VERSION 5.7 ;
  NOWIREEXTENSIONATPIN ON ;
  DIVIDERCHAR "/" ;
  BUSBITCHARS "[]" ;
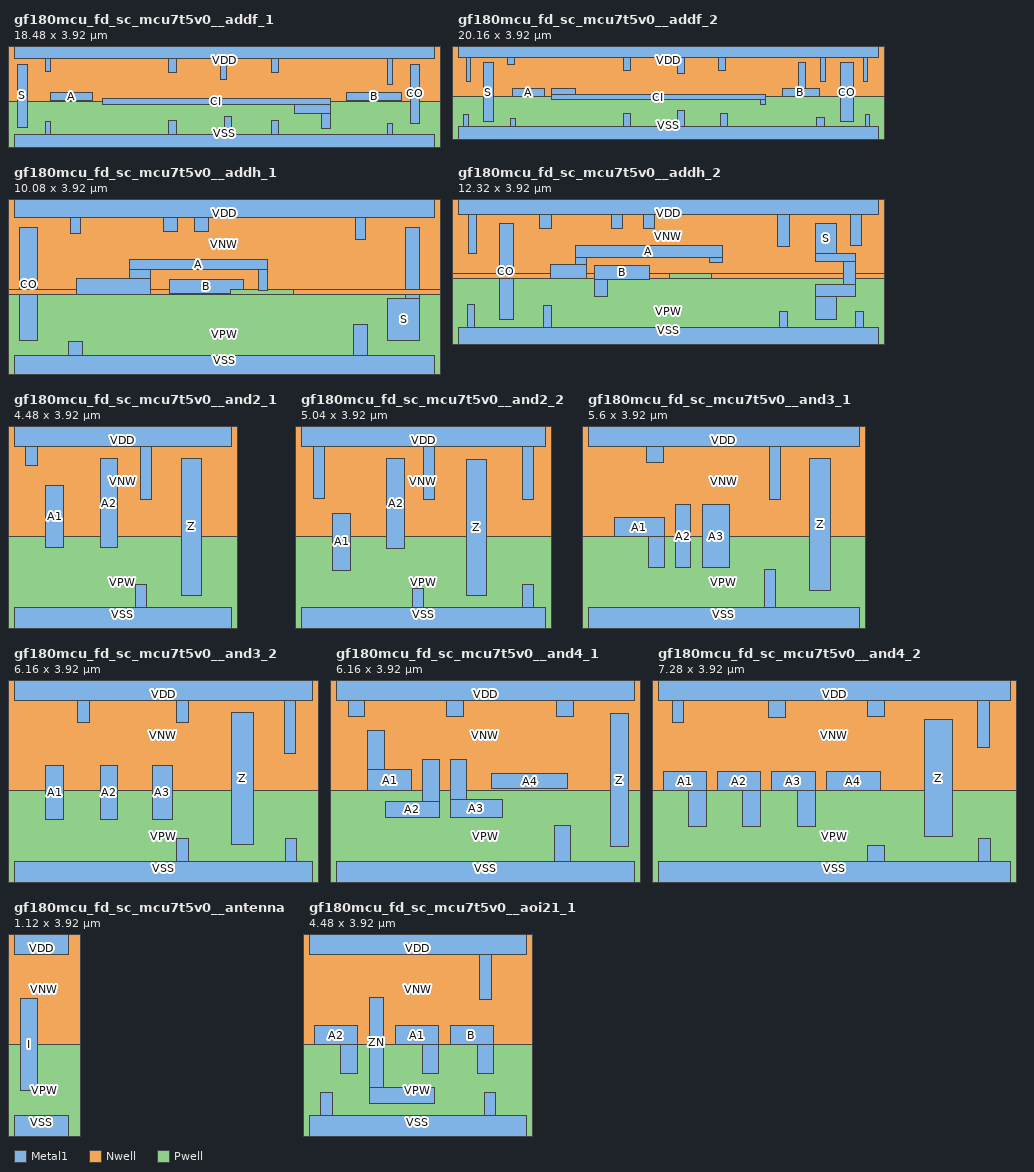
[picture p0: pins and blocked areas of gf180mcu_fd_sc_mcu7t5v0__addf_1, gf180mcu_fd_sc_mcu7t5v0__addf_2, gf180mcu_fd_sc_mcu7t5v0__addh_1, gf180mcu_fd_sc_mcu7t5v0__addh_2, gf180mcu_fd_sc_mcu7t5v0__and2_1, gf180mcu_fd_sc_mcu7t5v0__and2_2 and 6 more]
MACRO gf180mcu_fd_sc_mcu7t5v0__addf_1
  CLASS core ;
  FOREIGN gf180mcu_fd_sc_mcu7t5v0__addf_1 ;
  ORIGIN 0.000 0.000 ;
  SIZE 18.480 BY 3.920 ;
  SYMMETRY X Y ;
  SITE GF018hv5v_mcu_sc7 ;
  PIN A
    DIRECTION INPUT ;
    ANTENNAGATEAREA 2.272000 ;
    PORT
      LAYER Metal1 ;
        RECT 1.615 1.770 3.470 2.150 ;
    END
  END A
  PIN B
    DIRECTION INPUT ;
    ANTENNAGATEAREA 2.272000 ;
    PORT
      LAYER Metal1 ;
        RECT 14.640 1.795 17.070 2.150 ;
    END
  END B
  PIN CI
    DIRECTION INPUT ;
    ANTENNAGATEAREA 1.694000 ;
    PORT
      LAYER Metal1 ;
        RECT 3.890 1.620 13.910 1.850 ;
        RECT 12.340 1.200 13.910 1.620 ;
        RECT 13.540 0.550 13.910 1.200 ;
    END
  END CI
  PIN CO
    DIRECTION OUTPUT ;
    ANTENNADIFFAREA 0.893200 ;
    PORT
      LAYER Metal1 ;
        RECT 17.450 0.790 17.830 3.370 ;
    END
  END CO
  PIN S
    DIRECTION OUTPUT ;
    ANTENNADIFFAREA 0.847000 ;
    PORT
      LAYER Metal1 ;
        RECT 0.140 0.610 0.575 3.370 ;
    END
  END S
  PIN VDD
    DIRECTION INOUT ;
    USE POWER ;
    SHAPE ABUTMENT ;
    PORT
      LAYER Metal1 ;
        RECT 0.000 3.620 18.480 4.220 ;
        RECT 1.365 3.040 1.595 3.620 ;
        RECT 6.790 3.005 7.130 3.620 ;
        RECT 9.105 2.705 9.335 3.620 ;
        RECT 11.310 3.005 11.650 3.620 ;
        RECT 16.445 2.480 16.675 3.620 ;
    END
  END VDD
  PIN VNW
    DIRECTION INOUT ;
    USE POWER ;
    PORT
      LAYER Nwell ;
        RECT -0.430 1.760 18.910 4.350 ;
    END
  END VNW
  PIN VPW
    DIRECTION INOUT ;
    USE GROUND ;
    PORT
      LAYER Pwell ;
        RECT -0.430 -0.430 18.910 1.760 ;
    END
  END VPW
  PIN VSS
    DIRECTION INOUT ;
    USE GROUND ;
    SHAPE ABUTMENT ;
    PORT
      LAYER Metal1 ;
        RECT 1.365 0.300 1.595 0.870 ;
        RECT 6.790 0.300 7.130 0.915 ;
        RECT 9.250 0.300 9.590 1.090 ;
        RECT 11.310 0.300 11.650 0.915 ;
        RECT 16.445 0.300 16.675 0.765 ;
        RECT 0.000 -0.300 18.480 0.300 ;
    END
  END VSS
  OBS
      LAYER Metal1 ;
        RECT 0.925 2.560 4.710 2.790 ;
        RECT 5.550 2.775 5.890 2.845 ;
        RECT 8.030 2.775 8.370 2.845 ;
        RECT 0.925 1.390 1.155 2.560 ;
        RECT 5.550 2.545 8.370 2.775 ;
        RECT 10.070 2.545 13.430 2.775 ;
        RECT 14.165 2.315 14.400 2.765 ;
        RECT 5.010 2.080 14.400 2.315 ;
        RECT 14.170 1.565 14.400 2.080 ;
        RECT 0.925 1.160 4.615 1.390 ;
        RECT 4.385 0.810 4.615 1.160 ;
        RECT 5.505 1.145 8.415 1.375 ;
        RECT 5.505 0.810 5.735 1.145 ;
        RECT 8.185 0.810 8.415 1.145 ;
        RECT 10.025 1.145 12.110 1.375 ;
        RECT 10.025 0.770 10.255 1.145 ;
        RECT 11.880 0.915 12.110 1.145 ;
        RECT 14.170 1.335 17.200 1.565 ;
        RECT 11.880 0.680 13.210 0.915 ;
        RECT 14.170 0.750 14.495 1.335 ;
  END
END gf180mcu_fd_sc_mcu7t5v0__addf_1

#--------EOF---------

MACRO gf180mcu_fd_sc_mcu7t5v0__addf_2
  CLASS core ;
  FOREIGN gf180mcu_fd_sc_mcu7t5v0__addf_2 ;
  ORIGIN 0.000 0.000 ;
  SIZE 20.160 BY 3.920 ;
  SYMMETRY X Y ;
  SITE GF018hv5v_mcu_sc7 ;
  PIN A
    DIRECTION INPUT ;
    ANTENNAGATEAREA 2.372000 ;
    PORT
      LAYER Metal1 ;
        RECT 2.605 1.760 4.130 2.160 ;
    END
  END A
  PIN B
    DIRECTION INPUT ;
    ANTENNAGATEAREA 2.372000 ;
    PORT
      LAYER Metal1 ;
        RECT 16.340 2.160 16.700 3.370 ;
        RECT 15.580 1.760 17.335 2.160 ;
    END
  END B
  PIN CI
    DIRECTION INPUT ;
    ANTENNAGATEAREA 1.754000 ;
    PORT
      LAYER Metal1 ;
        RECT 4.490 1.835 5.660 2.160 ;
        RECT 4.490 1.605 14.755 1.835 ;
        RECT 14.525 1.345 14.755 1.605 ;
    END
  END CI
  PIN CO
    DIRECTION OUTPUT ;
    ANTENNADIFFAREA 1.045200 ;
    PORT
      LAYER Metal1 ;
        RECT 18.370 0.550 18.960 3.370 ;
    END
  END CO
  PIN S
    DIRECTION OUTPUT ;
    ANTENNADIFFAREA 1.006200 ;
    PORT
      LAYER Metal1 ;
        RECT 1.220 0.550 1.680 3.370 ;
    END
  END S
  PIN VDD
    DIRECTION INOUT ;
    USE POWER ;
    SHAPE ABUTMENT ;
    PORT
      LAYER Metal1 ;
        RECT 0.000 3.620 20.160 4.220 ;
        RECT 0.385 2.460 0.615 3.620 ;
        RECT 2.370 3.285 2.710 3.620 ;
        RECT 7.950 3.005 8.290 3.620 ;
        RECT 10.530 2.845 10.870 3.620 ;
        RECT 12.490 3.005 12.830 3.620 ;
        RECT 17.405 2.480 17.635 3.620 ;
        RECT 19.445 2.480 19.675 3.620 ;
    END
  END VDD
  PIN VNW
    DIRECTION INOUT ;
    USE POWER ;
    PORT
      LAYER Nwell ;
        RECT -0.430 1.760 20.590 4.350 ;
    END
  END VNW
  PIN VPW
    DIRECTION INOUT ;
    USE GROUND ;
    PORT
      LAYER Pwell ;
        RECT -0.430 -0.430 20.590 1.760 ;
    END
  END VPW
  PIN VSS
    DIRECTION INOUT ;
    USE GROUND ;
    SHAPE ABUTMENT ;
    PORT
      LAYER Metal1 ;
        RECT 0.285 0.300 0.515 0.905 ;
        RECT 2.525 0.300 2.755 0.695 ;
        RECT 7.950 0.300 8.290 0.915 ;
        RECT 10.530 0.300 10.870 1.075 ;
        RECT 12.590 0.300 12.930 0.915 ;
        RECT 17.230 0.300 17.570 0.730 ;
        RECT 19.545 0.300 19.775 0.905 ;
        RECT 0.000 -0.300 20.160 0.300 ;
    END
  END VSS
  OBS
      LAYER Metal1 ;
        RECT 1.940 2.610 5.830 2.845 ;
        RECT 1.940 1.155 2.170 2.610 ;
        RECT 6.710 2.540 9.790 2.775 ;
        RECT 11.240 2.545 14.310 2.775 ;
        RECT 15.105 2.295 15.335 3.140 ;
        RECT 6.070 2.065 15.335 2.295 ;
        RECT 1.940 0.925 5.775 1.155 ;
        RECT 5.545 0.780 5.775 0.925 ;
        RECT 6.665 1.145 9.695 1.375 ;
        RECT 6.665 0.790 6.895 1.145 ;
        RECT 9.465 0.790 9.695 1.145 ;
        RECT 11.305 1.145 14.215 1.375 ;
        RECT 11.305 0.790 11.535 1.145 ;
        RECT 13.985 0.790 14.215 1.145 ;
        RECT 15.105 1.315 15.335 2.065 ;
        RECT 17.890 1.315 18.120 2.230 ;
        RECT 15.105 1.085 18.120 1.315 ;
        RECT 15.105 0.780 15.335 1.085 ;
  END
END gf180mcu_fd_sc_mcu7t5v0__addf_2

#--------EOF---------

MACRO gf180mcu_fd_sc_mcu7t5v0__addh_1
  CLASS core ;
  FOREIGN gf180mcu_fd_sc_mcu7t5v0__addh_1 ;
  ORIGIN 0.000 0.000 ;
  SIZE 10.080 BY 3.920 ;
  SYMMETRY X Y ;
  SITE GF018hv5v_mcu_sc7 ;
  PIN A
    DIRECTION INPUT ;
    ANTENNAGATEAREA 1.175000 ;
    PORT
      LAYER Metal1 ;
        RECT 2.775 2.365 6.095 2.595 ;
        RECT 2.775 2.150 3.270 2.365 ;
        RECT 1.505 1.770 3.270 2.150 ;
        RECT 5.865 1.870 6.095 2.365 ;
    END
  END A
  PIN B
    DIRECTION INPUT ;
    ANTENNAGATEAREA 1.175000 ;
    PORT
      LAYER Metal1 ;
        RECT 3.725 1.790 5.510 2.135 ;
    END
  END B
  PIN CO
    DIRECTION OUTPUT ;
    ANTENNADIFFAREA 0.895400 ;
    PORT
      LAYER Metal1 ;
        RECT 0.140 0.650 0.575 3.370 ;
    END
  END CO
  PIN S
    DIRECTION OUTPUT ;
    ANTENNADIFFAREA 0.895400 ;
    PORT
      LAYER Metal1 ;
        RECT 9.405 1.680 9.735 3.370 ;
        RECT 8.975 0.650 9.735 1.680 ;
    END
  END S
  PIN VDD
    DIRECTION INOUT ;
    USE POWER ;
    SHAPE ABUTMENT ;
    PORT
      LAYER Metal1 ;
        RECT 0.000 3.620 10.080 4.220 ;
        RECT 1.365 3.230 1.595 3.620 ;
        RECT 3.590 3.285 3.930 3.620 ;
        RECT 4.330 3.285 4.670 3.620 ;
        RECT 8.205 3.075 8.435 3.620 ;
    END
  END VDD
  PIN VNW
    DIRECTION INOUT ;
    USE POWER ;
    PORT
      LAYER Nwell ;
        RECT -0.430 1.885 10.510 4.350 ;
        RECT -0.430 1.760 5.190 1.885 ;
        RECT 6.710 1.760 10.510 1.885 ;
    END
  END VNW
  PIN VPW
    DIRECTION INOUT ;
    USE GROUND ;
    PORT
      LAYER Pwell ;
        RECT 5.190 1.760 6.710 1.885 ;
        RECT -0.430 -0.430 10.510 1.760 ;
    END
  END VPW
  PIN VSS
    DIRECTION INOUT ;
    USE GROUND ;
    SHAPE ABUTMENT ;
    PORT
      LAYER Metal1 ;
        RECT 1.310 0.300 1.650 0.640 ;
        RECT 8.150 0.300 8.490 1.035 ;
        RECT 0.000 -0.300 10.080 0.300 ;
    END
  END VSS
  OBS
      LAYER Metal1 ;
        RECT 2.140 3.100 3.340 3.330 ;
        RECT 2.140 3.000 2.370 3.100 ;
        RECT 0.925 2.770 2.370 3.000 ;
        RECT 3.110 3.055 3.340 3.100 ;
        RECT 3.110 2.825 6.645 3.055 ;
        RECT 7.010 3.010 7.350 3.240 ;
        RECT 0.925 1.100 1.155 2.770 ;
        RECT 6.415 1.970 6.645 2.825 ;
        RECT 7.120 2.610 7.350 3.010 ;
        RECT 7.120 2.375 8.370 2.610 ;
        RECT 8.140 2.250 8.370 2.375 ;
        RECT 6.415 1.740 7.910 1.970 ;
        RECT 8.140 1.910 9.055 2.250 ;
        RECT 8.140 1.495 8.370 1.910 ;
        RECT 5.570 1.265 8.370 1.495 ;
        RECT 0.925 0.870 3.850 1.100 ;
        RECT 3.475 0.810 3.850 0.870 ;
        RECT 4.230 0.760 4.570 1.035 ;
        RECT 5.570 0.990 5.910 1.265 ;
        RECT 6.910 0.760 7.250 1.035 ;
        RECT 4.230 0.530 7.250 0.760 ;
  END
END gf180mcu_fd_sc_mcu7t5v0__addh_1

#--------EOF---------

MACRO gf180mcu_fd_sc_mcu7t5v0__addh_2
  CLASS core ;
  FOREIGN gf180mcu_fd_sc_mcu7t5v0__addh_2 ;
  ORIGIN 0.000 0.000 ;
  SIZE 12.320 BY 3.920 ;
  SYMMETRY X Y ;
  SITE GF018hv5v_mcu_sc7 ;
  PIN A
    DIRECTION INPUT ;
    ANTENNAGATEAREA 2.073000 ;
    PORT
      LAYER Metal1 ;
        RECT 3.435 2.350 7.770 2.710 ;
        RECT 3.435 2.150 3.780 2.350 ;
        RECT 7.380 2.205 7.770 2.350 ;
        RECT 2.715 1.740 3.780 2.150 ;
    END
  END A
  PIN B
    DIRECTION INPUT ;
    ANTENNAGATEAREA 2.073000 ;
    PORT
      LAYER Metal1 ;
        RECT 4.010 1.720 5.620 2.120 ;
        RECT 4.010 1.210 4.390 1.720 ;
    END
  END B
  PIN CO
    DIRECTION OUTPUT ;
    ANTENNADIFFAREA 1.177100 ;
    PORT
      LAYER Metal1 ;
        RECT 1.210 0.550 1.615 3.370 ;
    END
  END CO
  PIN S
    DIRECTION OUTPUT ;
    ANTENNADIFFAREA 0.930800 ;
    PORT
      LAYER Metal1 ;
        RECT 10.490 2.480 11.110 3.370 ;
        RECT 10.490 2.250 11.650 2.480 ;
        RECT 11.310 1.560 11.650 2.250 ;
        RECT 10.490 1.220 11.650 1.560 ;
        RECT 10.490 0.550 11.110 1.220 ;
    END
  END S
  PIN VDD
    DIRECTION INOUT ;
    USE POWER ;
    SHAPE ABUTMENT ;
    PORT
      LAYER Metal1 ;
        RECT 0.000 3.620 12.320 4.220 ;
        RECT 0.315 2.480 0.545 3.620 ;
        RECT 2.400 3.215 2.740 3.620 ;
        RECT 4.490 3.215 4.830 3.620 ;
        RECT 5.430 3.215 5.770 3.620 ;
        RECT 9.370 2.685 9.710 3.620 ;
        RECT 11.510 2.710 11.850 3.620 ;
    END
  END VDD
  PIN VNW
    DIRECTION INOUT ;
    USE POWER ;
    PORT
      LAYER Nwell ;
        RECT -0.430 1.885 12.750 4.350 ;
        RECT -0.430 1.760 6.200 1.885 ;
        RECT 7.425 1.760 12.750 1.885 ;
    END
  END VNW
  PIN VPW
    DIRECTION INOUT ;
    USE GROUND ;
    PORT
      LAYER Pwell ;
        RECT 6.200 1.760 7.425 1.885 ;
        RECT -0.430 -0.430 12.750 1.760 ;
    END
  END VPW
  PIN VSS
    DIRECTION INOUT ;
    USE GROUND ;
    SHAPE ABUTMENT ;
    PORT
      LAYER Metal1 ;
        RECT 0.265 0.300 0.495 0.985 ;
        RECT 2.505 0.300 2.735 0.940 ;
        RECT 9.425 0.300 9.655 0.780 ;
        RECT 11.665 0.300 11.895 0.780 ;
        RECT 0.000 -0.300 12.320 0.300 ;
    END
  END VSS
  OBS
      LAYER Metal1 ;
        RECT 2.975 2.985 3.810 3.170 ;
        RECT 2.015 2.940 3.810 2.985 ;
        RECT 2.015 2.755 3.205 2.940 ;
        RECT 2.015 1.410 2.245 2.755 ;
        RECT 8.010 2.435 8.350 3.370 ;
        RECT 8.010 2.205 9.400 2.435 ;
        RECT 9.170 2.020 9.400 2.205 ;
        RECT 6.095 1.745 8.790 1.975 ;
        RECT 9.170 1.790 10.790 2.020 ;
        RECT 6.095 1.420 6.325 1.745 ;
        RECT 9.170 1.515 9.400 1.790 ;
        RECT 2.015 1.180 3.355 1.410 ;
        RECT 3.125 0.760 3.355 1.180 ;
        RECT 4.665 1.190 6.325 1.420 ;
        RECT 6.670 1.285 9.400 1.515 ;
        RECT 4.665 0.760 4.895 1.190 ;
        RECT 6.670 0.990 7.010 1.285 ;
        RECT 3.125 0.530 4.895 0.760 ;
        RECT 5.330 0.530 8.350 0.760 ;
  END
END gf180mcu_fd_sc_mcu7t5v0__addh_2

#--------EOF---------

MACRO gf180mcu_fd_sc_mcu7t5v0__and2_1
  CLASS core ;
  FOREIGN gf180mcu_fd_sc_mcu7t5v0__and2_1 ;
  ORIGIN 0.000 0.000 ;
  SIZE 4.480 BY 3.920 ;
  SYMMETRY X Y ;
  SITE GF018hv5v_mcu_sc7 ;
  PIN A1
    DIRECTION INPUT ;
    ANTENNAGATEAREA 0.519000 ;
    PORT
      LAYER Metal1 ;
        RECT 0.660 1.540 1.020 2.810 ;
    END
  END A1
  PIN A2
    DIRECTION INPUT ;
    ANTENNAGATEAREA 0.519000 ;
    PORT
      LAYER Metal1 ;
        RECT 1.780 1.540 2.140 3.370 ;
    END
  END A2
  PIN Z
    DIRECTION OUTPUT ;
    ANTENNADIFFAREA 0.893200 ;
    PORT
      LAYER Metal1 ;
        RECT 3.450 0.555 3.870 3.380 ;
    END
  END Z
  PIN VDD
    DIRECTION INOUT ;
    USE POWER ;
    SHAPE ABUTMENT ;
    PORT
      LAYER Metal1 ;
        RECT 0.000 3.620 4.480 4.220 ;
        RECT 0.245 3.225 0.475 3.620 ;
        RECT 2.605 2.530 2.835 3.620 ;
    END
  END VDD
  PIN VNW
    DIRECTION INOUT ;
    USE POWER ;
    PORT
      LAYER Nwell ;
        RECT -0.430 1.760 4.910 4.350 ;
    END
  END VNW
  PIN VPW
    DIRECTION INOUT ;
    USE GROUND ;
    PORT
      LAYER Pwell ;
        RECT -0.430 -0.430 4.910 1.760 ;
    END
  END VPW
  PIN VSS
    DIRECTION INOUT ;
    USE GROUND ;
    SHAPE ABUTMENT ;
    PORT
      LAYER Metal1 ;
        RECT 2.505 0.300 2.735 0.765 ;
        RECT 0.000 -0.300 4.480 0.300 ;
    END
  END VSS
  OBS
      LAYER Metal1 ;
        RECT 1.265 1.290 1.495 3.325 ;
        RECT 2.945 1.290 3.175 1.985 ;
        RECT 0.245 1.055 3.175 1.290 ;
        RECT 0.245 0.805 0.475 1.055 ;
  END
END gf180mcu_fd_sc_mcu7t5v0__and2_1

#--------EOF---------

MACRO gf180mcu_fd_sc_mcu7t5v0__and2_2
  CLASS core ;
  FOREIGN gf180mcu_fd_sc_mcu7t5v0__and2_2 ;
  ORIGIN 0.000 0.000 ;
  SIZE 5.040 BY 3.920 ;
  SYMMETRY X Y ;
  SITE GF018hv5v_mcu_sc7 ;
  PIN A1
    DIRECTION INPUT ;
    ANTENNAGATEAREA 1.024000 ;
    PORT
      LAYER Metal1 ;
        RECT 0.660 1.065 1.020 2.240 ;
    END
  END A1
  PIN A2
    DIRECTION INPUT ;
    ANTENNAGATEAREA 1.024000 ;
    PORT
      LAYER Metal1 ;
        RECT 1.770 1.515 2.130 3.370 ;
    END
  END A2
  PIN Z
    DIRECTION OUTPUT ;
    ANTENNADIFFAREA 1.071900 ;
    PORT
      LAYER Metal1 ;
        RECT 3.420 0.550 3.830 3.355 ;
    END
  END Z
  PIN VDD
    DIRECTION INOUT ;
    USE POWER ;
    SHAPE ABUTMENT ;
    PORT
      LAYER Metal1 ;
        RECT 0.000 3.620 5.040 4.220 ;
        RECT 0.260 2.545 0.490 3.620 ;
        RECT 2.520 2.530 2.750 3.620 ;
        RECT 4.560 2.530 4.790 3.620 ;
    END
  END VDD
  PIN VNW
    DIRECTION INOUT ;
    USE POWER ;
    PORT
      LAYER Nwell ;
        RECT -0.430 1.760 5.470 4.350 ;
    END
  END VNW
  PIN VPW
    DIRECTION INOUT ;
    USE GROUND ;
    PORT
      LAYER Pwell ;
        RECT -0.430 -0.430 5.470 1.760 ;
    END
  END VPW
  PIN VSS
    DIRECTION INOUT ;
    USE GROUND ;
    SHAPE ABUTMENT ;
    PORT
      LAYER Metal1 ;
        RECT 2.300 0.300 2.530 0.690 ;
        RECT 4.560 0.300 4.790 0.765 ;
        RECT 0.000 -0.300 5.040 0.300 ;
    END
  END VSS
  OBS
      LAYER Metal1 ;
        RECT 1.280 1.165 1.510 3.355 ;
        RECT 2.960 1.165 3.190 1.755 ;
        RECT 1.280 0.930 3.190 1.165 ;
        RECT 1.280 0.780 1.510 0.930 ;
        RECT 0.195 0.550 1.510 0.780 ;
  END
END gf180mcu_fd_sc_mcu7t5v0__and2_2

#--------EOF---------

MACRO gf180mcu_fd_sc_mcu7t5v0__and3_1
  CLASS core ;
  FOREIGN gf180mcu_fd_sc_mcu7t5v0__and3_1 ;
  ORIGIN 0.000 0.000 ;
  SIZE 5.600 BY 3.920 ;
  SYMMETRY X Y ;
  SITE GF018hv5v_mcu_sc7 ;
  PIN A1
    DIRECTION INPUT ;
    ANTENNAGATEAREA 0.495500 ;
    PORT
      LAYER Metal1 ;
        RECT 0.540 1.770 1.570 2.150 ;
        RECT 1.250 1.120 1.570 1.770 ;
    END
  END A1
  PIN A2
    DIRECTION INPUT ;
    ANTENNAGATEAREA 0.495500 ;
    PORT
      LAYER Metal1 ;
        RECT 1.800 1.120 2.120 2.415 ;
    END
  END A2
  PIN A3
    DIRECTION INPUT ;
    ANTENNAGATEAREA 0.495500 ;
    PORT
      LAYER Metal1 ;
        RECT 2.360 1.120 2.910 2.415 ;
    END
  END A3
  PIN Z
    DIRECTION OUTPUT ;
    ANTENNADIFFAREA 0.875600 ;
    PORT
      LAYER Metal1 ;
        RECT 4.570 0.650 5.010 3.380 ;
    END
  END Z
  PIN VDD
    DIRECTION INOUT ;
    USE POWER ;
    SHAPE ABUTMENT ;
    PORT
      LAYER Metal1 ;
        RECT 0.000 3.620 5.600 4.220 ;
        RECT 1.210 3.285 1.550 3.620 ;
        RECT 3.745 2.530 3.975 3.620 ;
    END
  END VDD
  PIN VNW
    DIRECTION INOUT ;
    USE POWER ;
    PORT
      LAYER Nwell ;
        RECT -0.430 1.760 6.030 4.350 ;
    END
  END VNW
  PIN VPW
    DIRECTION INOUT ;
    USE GROUND ;
    PORT
      LAYER Pwell ;
        RECT -0.430 -0.430 6.030 1.760 ;
    END
  END VPW
  PIN VSS
    DIRECTION INOUT ;
    USE GROUND ;
    SHAPE ABUTMENT ;
    PORT
      LAYER Metal1 ;
        RECT 3.645 0.300 3.875 1.090 ;
        RECT 0.000 -0.300 5.600 0.300 ;
    END
  END VSS
  OBS
      LAYER Metal1 ;
        RECT 0.190 3.055 0.530 3.340 ;
        RECT 2.230 3.055 2.570 3.340 ;
        RECT 0.190 2.825 3.415 3.055 ;
        RECT 3.185 1.800 3.415 2.825 ;
        RECT 3.185 1.460 4.315 1.800 ;
        RECT 0.190 0.805 0.530 1.035 ;
        RECT 3.185 0.805 3.415 1.460 ;
        RECT 0.190 0.575 3.415 0.805 ;
  END
END gf180mcu_fd_sc_mcu7t5v0__and3_1

#--------EOF---------

MACRO gf180mcu_fd_sc_mcu7t5v0__and3_2
  CLASS core ;
  FOREIGN gf180mcu_fd_sc_mcu7t5v0__and3_2 ;
  ORIGIN 0.000 0.000 ;
  SIZE 6.160 BY 3.920 ;
  SYMMETRY X Y ;
  SITE GF018hv5v_mcu_sc7 ;
  PIN A1
    DIRECTION INPUT ;
    ANTENNAGATEAREA 0.981500 ;
    PORT
      LAYER Metal1 ;
        RECT 0.660 1.160 1.020 2.290 ;
    END
  END A1
  PIN A2
    DIRECTION INPUT ;
    ANTENNAGATEAREA 0.981500 ;
    PORT
      LAYER Metal1 ;
        RECT 1.780 1.160 2.140 2.290 ;
    END
  END A2
  PIN A3
    DIRECTION INPUT ;
    ANTENNAGATEAREA 0.981500 ;
    PORT
      LAYER Metal1 ;
        RECT 2.865 1.160 3.260 2.290 ;
    END
  END A3
  PIN Z
    DIRECTION OUTPUT ;
    ANTENNADIFFAREA 1.055600 ;
    PORT
      LAYER Metal1 ;
        RECT 4.480 0.650 4.950 3.380 ;
    END
  END Z
  PIN VDD
    DIRECTION INOUT ;
    USE POWER ;
    SHAPE ABUTMENT ;
    PORT
      LAYER Metal1 ;
        RECT 0.000 3.620 6.160 4.220 ;
        RECT 1.320 3.160 1.550 3.620 ;
        RECT 3.360 3.160 3.590 3.620 ;
        RECT 5.580 2.530 5.810 3.620 ;
    END
  END VDD
  PIN VNW
    DIRECTION INOUT ;
    USE POWER ;
    PORT
      LAYER Nwell ;
        RECT -0.430 1.760 6.590 4.350 ;
    END
  END VNW
  PIN VPW
    DIRECTION INOUT ;
    USE GROUND ;
    PORT
      LAYER Pwell ;
        RECT -0.430 -0.430 6.590 1.760 ;
    END
  END VPW
  PIN VSS
    DIRECTION INOUT ;
    USE GROUND ;
    SHAPE ABUTMENT ;
    PORT
      LAYER Metal1 ;
        RECT 3.360 0.300 3.590 0.765 ;
        RECT 5.600 0.300 5.830 0.765 ;
        RECT 0.000 -0.300 6.160 0.300 ;
    END
  END VSS
  OBS
      LAYER Metal1 ;
        RECT 0.245 2.910 0.585 3.355 ;
        RECT 0.245 2.655 4.250 2.910 ;
        RECT 1.285 0.865 1.515 2.655 ;
        RECT 4.020 1.445 4.250 2.655 ;
        RECT 0.235 0.635 1.515 0.865 ;
  END
END gf180mcu_fd_sc_mcu7t5v0__and3_2

#--------EOF---------

MACRO gf180mcu_fd_sc_mcu7t5v0__and4_1
  CLASS core ;
  FOREIGN gf180mcu_fd_sc_mcu7t5v0__and4_1 ;
  ORIGIN 0.000 0.000 ;
  SIZE 6.160 BY 3.920 ;
  SYMMETRY X Y ;
  SITE GF018hv5v_mcu_sc7 ;
  PIN A1
    DIRECTION INPUT ;
    ANTENNAGATEAREA 0.552000 ;
    PORT
      LAYER Metal1 ;
        RECT 0.660 2.190 1.000 3.000 ;
        RECT 0.660 1.770 1.560 2.190 ;
    END
  END A1
  PIN A2
    DIRECTION INPUT ;
    ANTENNAGATEAREA 0.552000 ;
    PORT
      LAYER Metal1 ;
        RECT 1.790 1.540 2.130 2.410 ;
        RECT 1.015 1.210 2.130 1.540 ;
    END
  END A2
  PIN A3
    DIRECTION INPUT ;
    ANTENNAGATEAREA 0.552000 ;
    PORT
      LAYER Metal1 ;
        RECT 2.360 1.570 2.700 2.410 ;
        RECT 2.360 1.210 3.430 1.570 ;
    END
  END A3
  PIN A4
    DIRECTION INPUT ;
    ANTENNAGATEAREA 0.552000 ;
    PORT
      LAYER Metal1 ;
        RECT 3.215 1.800 4.780 2.120 ;
    END
  END A4
  PIN Z
    DIRECTION OUTPUT ;
    ANTENNADIFFAREA 0.895400 ;
    PORT
      LAYER Metal1 ;
        RECT 5.660 0.610 6.030 3.350 ;
    END
  END Z
  PIN VDD
    DIRECTION INOUT ;
    USE POWER ;
    SHAPE ABUTMENT ;
    PORT
      LAYER Metal1 ;
        RECT 0.000 3.620 6.160 4.220 ;
        RECT 0.250 3.285 0.590 3.620 ;
        RECT 2.290 3.285 2.630 3.620 ;
        RECT 4.550 3.285 4.890 3.620 ;
    END
  END VDD
  PIN VNW
    DIRECTION INOUT ;
    USE POWER ;
    PORT
      LAYER Nwell ;
        RECT -0.430 1.760 6.590 4.350 ;
    END
  END VNW
  PIN VPW
    DIRECTION INOUT ;
    USE GROUND ;
    PORT
      LAYER Pwell ;
        RECT -0.430 -0.430 6.590 1.760 ;
    END
  END VPW
  PIN VSS
    DIRECTION INOUT ;
    USE GROUND ;
    SHAPE ABUTMENT ;
    PORT
      LAYER Metal1 ;
        RECT 4.505 0.300 4.845 1.035 ;
        RECT 0.000 -0.300 6.160 0.300 ;
    END
  END VSS
  OBS
      LAYER Metal1 ;
        RECT 1.270 3.055 1.610 3.390 ;
        RECT 3.310 3.055 3.650 3.390 ;
        RECT 1.270 2.825 5.385 3.055 ;
        RECT 5.155 1.505 5.385 2.825 ;
        RECT 3.770 1.265 5.385 1.505 ;
        RECT 0.305 0.760 0.535 1.090 ;
        RECT 3.770 0.760 4.000 1.265 ;
        RECT 0.305 0.530 4.000 0.760 ;
  END
END gf180mcu_fd_sc_mcu7t5v0__and4_1

#--------EOF---------

MACRO gf180mcu_fd_sc_mcu7t5v0__and4_2
  CLASS core ;
  FOREIGN gf180mcu_fd_sc_mcu7t5v0__and4_2 ;
  ORIGIN 0.000 0.000 ;
  SIZE 7.280 BY 3.920 ;
  SYMMETRY X Y ;
  SITE GF018hv5v_mcu_sc7 ;
  PIN A1
    DIRECTION INPUT ;
    ANTENNAGATEAREA 0.919500 ;
    PORT
      LAYER Metal1 ;
        RECT 0.120 1.770 1.000 2.150 ;
        RECT 0.630 1.030 1.000 1.770 ;
    END
  END A1
  PIN A2
    DIRECTION INPUT ;
    ANTENNAGATEAREA 0.919500 ;
    PORT
      LAYER Metal1 ;
        RECT 1.230 1.770 2.120 2.150 ;
        RECT 1.750 1.030 2.120 1.770 ;
    END
  END A2
  PIN A3
    DIRECTION INPUT ;
    ANTENNAGATEAREA 0.919500 ;
    PORT
      LAYER Metal1 ;
        RECT 2.350 1.770 3.240 2.150 ;
        RECT 2.870 1.030 3.240 1.770 ;
    END
  END A3
  PIN A4
    DIRECTION INPUT ;
    ANTENNAGATEAREA 0.919500 ;
    PORT
      LAYER Metal1 ;
        RECT 3.470 1.770 4.595 2.150 ;
    END
  END A4
  PIN Z
    DIRECTION OUTPUT ;
    ANTENNADIFFAREA 1.060800 ;
    PORT
      LAYER Metal1 ;
        RECT 5.495 0.805 6.070 3.235 ;
    END
  END Z
  PIN VDD
    DIRECTION INOUT ;
    USE POWER ;
    SHAPE ABUTMENT ;
    PORT
      LAYER Metal1 ;
        RECT 0.000 3.620 7.280 4.220 ;
        RECT 0.300 3.160 0.530 3.620 ;
        RECT 2.285 3.280 2.625 3.620 ;
        RECT 4.325 3.285 4.665 3.620 ;
        RECT 6.600 2.650 6.830 3.620 ;
    END
  END VDD
  PIN VNW
    DIRECTION INOUT ;
    USE POWER ;
    PORT
      LAYER Nwell ;
        RECT -0.430 1.760 7.710 4.350 ;
    END
  END VNW
  PIN VPW
    DIRECTION INOUT ;
    USE GROUND ;
    PORT
      LAYER Pwell ;
        RECT -0.430 -0.430 7.710 1.760 ;
    END
  END VPW
  PIN VSS
    DIRECTION INOUT ;
    USE GROUND ;
    SHAPE ABUTMENT ;
    PORT
      LAYER Metal1 ;
        RECT 4.325 0.300 4.665 0.635 ;
        RECT 6.620 0.300 6.850 0.765 ;
        RECT 0.000 -0.300 7.280 0.300 ;
    END
  END VSS
  OBS
      LAYER Metal1 ;
        RECT 1.260 2.790 5.230 3.020 ;
        RECT 5.000 1.095 5.230 2.790 ;
        RECT 3.845 0.865 5.230 1.095 ;
        RECT 3.845 0.780 4.075 0.865 ;
        RECT 0.235 0.550 4.075 0.780 ;
  END
END gf180mcu_fd_sc_mcu7t5v0__and4_2

#--------EOF---------

MACRO gf180mcu_fd_sc_mcu7t5v0__antenna
  CLASS core ANTENNACELL ;
  FOREIGN gf180mcu_fd_sc_mcu7t5v0__antenna ;
  ORIGIN 0.000 0.000 ;
  SIZE 1.120 BY 3.920 ;
  SYMMETRY X Y ;
  SITE GF018hv5v_mcu_sc7 ;
  PIN I
    DIRECTION INPUT ;
    ANTENNADIFFAREA 0.410400 ;
    PORT
      LAYER Metal1 ;
        RECT 0.140 0.810 0.475 2.710 ;
    END
  END I
  PIN VDD
    DIRECTION INOUT ;
    USE POWER ;
    SHAPE ABUTMENT ;
    PORT
      LAYER Metal1 ;
        RECT 0.000 3.620 1.120 4.220 ;
    END
  END VDD
  PIN VNW
    DIRECTION INOUT ;
    USE POWER ;
    PORT
      LAYER Nwell ;
        RECT -0.430 1.760 1.550 4.350 ;
    END
  END VNW
  PIN VPW
    DIRECTION INOUT ;
    USE GROUND ;
    PORT
      LAYER Pwell ;
        RECT -0.430 -0.430 1.550 1.760 ;
    END
  END VPW
  PIN VSS
    DIRECTION INOUT ;
    USE GROUND ;
    SHAPE ABUTMENT ;
    PORT
      LAYER Metal1 ;
        RECT 0.000 -0.300 1.120 0.300 ;
    END
  END VSS
END gf180mcu_fd_sc_mcu7t5v0__antenna

#--------EOF---------

MACRO gf180mcu_fd_sc_mcu7t5v0__aoi21_1
  CLASS core ;
  FOREIGN gf180mcu_fd_sc_mcu7t5v0__aoi21_1 ;
  ORIGIN 0.000 0.000 ;
  SIZE 4.480 BY 3.920 ;
  SYMMETRY X Y ;
  SITE GF018hv5v_mcu_sc7 ;
  PIN A1
    DIRECTION INPUT ;
    ANTENNAGATEAREA 1.099500 ;
    PORT
      LAYER Metal1 ;
        RECT 1.775 1.770 2.680 2.150 ;
        RECT 2.340 1.160 2.680 1.770 ;
    END
  END A1
  PIN A2
    DIRECTION INPUT ;
    ANTENNAGATEAREA 1.099500 ;
    PORT
      LAYER Metal1 ;
        RECT 0.115 1.770 1.010 2.150 ;
        RECT 0.660 1.160 1.010 1.770 ;
    END
  END A2
  PIN B
    DIRECTION INPUT ;
    ANTENNAGATEAREA 0.913500 ;
    PORT
      LAYER Metal1 ;
        RECT 2.910 1.770 3.815 2.150 ;
        RECT 3.475 1.160 3.815 1.770 ;
    END
  END B
  PIN ZN
    DIRECTION OUTPUT ;
    ANTENNADIFFAREA 1.145600 ;
    PORT
      LAYER Metal1 ;
        RECT 1.240 0.870 1.545 2.725 ;
        RECT 1.240 0.550 2.580 0.870 ;
    END
  END ZN
  PIN VDD
    DIRECTION INOUT ;
    USE POWER ;
    SHAPE ABUTMENT ;
    PORT
      LAYER Metal1 ;
        RECT 0.000 3.620 4.480 4.220 ;
        RECT 3.525 2.690 3.755 3.620 ;
    END
  END VDD
  PIN VNW
    DIRECTION INOUT ;
    USE POWER ;
    PORT
      LAYER Nwell ;
        RECT -0.430 1.760 4.910 4.350 ;
    END
  END VNW
  PIN VPW
    DIRECTION INOUT ;
    USE GROUND ;
    PORT
      LAYER Pwell ;
        RECT -0.430 -0.430 4.910 1.760 ;
    END
  END VPW
  PIN VSS
    DIRECTION INOUT ;
    USE GROUND ;
    SHAPE ABUTMENT ;
    PORT
      LAYER Metal1 ;
        RECT 0.245 0.300 0.475 0.765 ;
        RECT 3.625 0.300 3.855 0.765 ;
        RECT 0.000 -0.300 4.480 0.300 ;
    END
  END VSS
  OBS
      LAYER Metal1 ;
        RECT 0.190 3.160 2.570 3.390 ;
        RECT 0.190 2.495 0.530 3.160 ;
        RECT 2.230 2.495 2.570 3.160 ;
  END
END gf180mcu_fd_sc_mcu7t5v0__aoi21_1

#--------EOF---------

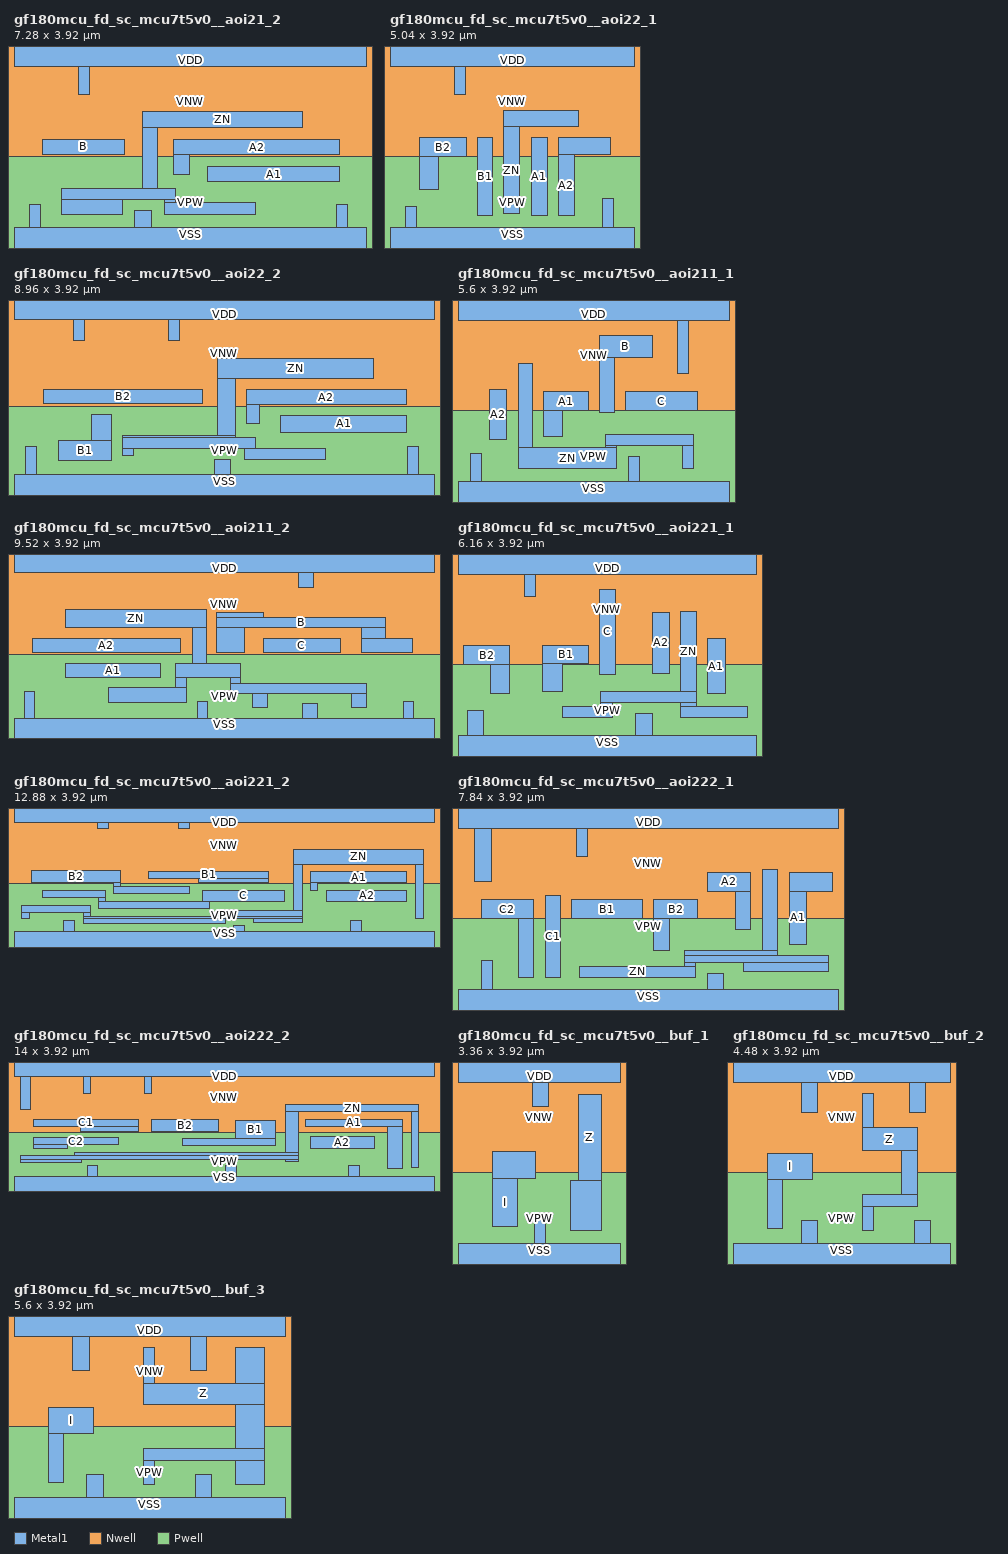
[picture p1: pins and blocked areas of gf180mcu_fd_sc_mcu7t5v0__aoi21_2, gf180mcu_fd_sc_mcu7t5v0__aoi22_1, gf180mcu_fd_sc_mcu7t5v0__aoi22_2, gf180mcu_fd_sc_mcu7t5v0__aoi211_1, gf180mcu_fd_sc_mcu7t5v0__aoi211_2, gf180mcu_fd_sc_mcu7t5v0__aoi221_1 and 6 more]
MACRO gf180mcu_fd_sc_mcu7t5v0__aoi21_2
  CLASS core ;
  FOREIGN gf180mcu_fd_sc_mcu7t5v0__aoi21_2 ;
  ORIGIN 0.000 0.000 ;
  SIZE 7.280 BY 3.920 ;
  SYMMETRY X Y ;
  SITE GF018hv5v_mcu_sc7 ;
  PIN A1
    DIRECTION INPUT ;
    ANTENNAGATEAREA 2.145000 ;
    PORT
      LAYER Metal1 ;
        RECT 4.000 1.240 6.725 1.560 ;
    END
  END A1
  PIN A2
    DIRECTION INPUT ;
    ANTENNAGATEAREA 2.145000 ;
    PORT
      LAYER Metal1 ;
        RECT 3.290 1.800 6.725 2.120 ;
        RECT 3.290 1.400 3.630 1.800 ;
    END
  END A2
  PIN B
    DIRECTION INPUT ;
    ANTENNAGATEAREA 1.893000 ;
    PORT
      LAYER Metal1 ;
        RECT 0.580 1.800 2.280 2.125 ;
    END
  END B
  PIN ZN
    DIRECTION OUTPUT ;
    ANTENNADIFFAREA 2.081900 ;
    PORT
      LAYER Metal1 ;
        RECT 2.650 2.360 5.955 2.700 ;
        RECT 2.650 1.100 2.970 2.360 ;
        RECT 0.970 0.870 3.325 1.100 ;
        RECT 0.970 0.560 2.245 0.870 ;
        RECT 3.095 0.805 3.325 0.870 ;
        RECT 3.095 0.575 4.975 0.805 ;
    END
  END ZN
  PIN VDD
    DIRECTION INOUT ;
    USE POWER ;
    SHAPE ABUTMENT ;
    PORT
      LAYER Metal1 ;
        RECT 0.000 3.620 7.280 4.220 ;
        RECT 1.330 3.040 1.560 3.620 ;
    END
  END VDD
  PIN VNW
    DIRECTION INOUT ;
    USE POWER ;
    PORT
      LAYER Nwell ;
        RECT -0.430 1.760 7.710 4.350 ;
    END
  END VNW
  PIN VPW
    DIRECTION INOUT ;
    USE GROUND ;
    PORT
      LAYER Pwell ;
        RECT -0.430 -0.430 7.710 1.760 ;
    END
  END VPW
  PIN VSS
    DIRECTION INOUT ;
    USE GROUND ;
    SHAPE ABUTMENT ;
    PORT
      LAYER Metal1 ;
        RECT 0.310 0.300 0.540 0.765 ;
        RECT 2.495 0.300 2.835 0.640 ;
        RECT 6.650 0.300 6.880 0.765 ;
        RECT 0.000 -0.300 7.280 0.300 ;
    END
  END VSS
  OBS
      LAYER Metal1 ;
        RECT 0.310 2.760 0.540 3.380 ;
        RECT 1.800 3.095 6.880 3.325 ;
        RECT 1.800 2.760 2.035 3.095 ;
        RECT 0.310 2.530 2.035 2.760 ;
        RECT 6.650 2.435 6.880 3.095 ;
  END
END gf180mcu_fd_sc_mcu7t5v0__aoi21_2

#--------EOF---------

MACRO gf180mcu_fd_sc_mcu7t5v0__aoi22_1
  CLASS core ;
  FOREIGN gf180mcu_fd_sc_mcu7t5v0__aoi22_1 ;
  ORIGIN 0.000 0.000 ;
  SIZE 5.040 BY 3.920 ;
  SYMMETRY X Y ;
  SITE GF018hv5v_mcu_sc7 ;
  PIN A1
    DIRECTION INPUT ;
    ANTENNAGATEAREA 1.096500 ;
    PORT
      LAYER Metal1 ;
        RECT 2.920 0.550 3.240 2.150 ;
    END
  END A1
  PIN A2
    DIRECTION INPUT ;
    ANTENNAGATEAREA 1.096500 ;
    PORT
      LAYER Metal1 ;
        RECT 3.480 1.800 4.545 2.150 ;
        RECT 3.480 0.550 3.800 1.800 ;
    END
  END A2
  PIN B1
    DIRECTION INPUT ;
    ANTENNAGATEAREA 1.096500 ;
    PORT
      LAYER Metal1 ;
        RECT 1.800 0.550 2.120 2.150 ;
    END
  END B1
  PIN B2
    DIRECTION INPUT ;
    ANTENNAGATEAREA 1.096500 ;
    PORT
      LAYER Metal1 ;
        RECT 0.610 1.770 1.570 2.150 ;
        RECT 0.610 1.085 1.005 1.770 ;
    END
  END B2
  PIN ZN
    DIRECTION OUTPUT ;
    ANTENNADIFFAREA 1.055600 ;
    PORT
      LAYER Metal1 ;
        RECT 2.350 2.380 3.890 2.710 ;
        RECT 2.350 0.585 2.680 2.380 ;
    END
  END ZN
  PIN VDD
    DIRECTION INOUT ;
    USE POWER ;
    SHAPE ABUTMENT ;
    PORT
      LAYER Metal1 ;
        RECT 0.000 3.620 5.040 4.220 ;
        RECT 1.330 3.040 1.560 3.620 ;
    END
  END VDD
  PIN VNW
    DIRECTION INOUT ;
    USE POWER ;
    PORT
      LAYER Nwell ;
        RECT -0.430 1.760 5.470 4.350 ;
    END
  END VNW
  PIN VPW
    DIRECTION INOUT ;
    USE GROUND ;
    PORT
      LAYER Pwell ;
        RECT -0.430 -0.430 5.470 1.760 ;
    END
  END VPW
  PIN VSS
    DIRECTION INOUT ;
    USE GROUND ;
    SHAPE ABUTMENT ;
    PORT
      LAYER Metal1 ;
        RECT 0.310 0.300 0.540 0.725 ;
        RECT 4.390 0.300 4.620 0.905 ;
        RECT 0.000 -0.300 5.040 0.300 ;
    END
  END VSS
  OBS
      LAYER Metal1 ;
        RECT 0.255 2.760 0.595 3.380 ;
        RECT 1.820 3.145 4.675 3.380 ;
        RECT 1.820 2.760 2.050 3.145 ;
        RECT 0.255 2.530 2.050 2.760 ;
        RECT 4.335 2.530 4.675 3.145 ;
  END
END gf180mcu_fd_sc_mcu7t5v0__aoi22_1

#--------EOF---------

MACRO gf180mcu_fd_sc_mcu7t5v0__aoi22_2
  CLASS core ;
  FOREIGN gf180mcu_fd_sc_mcu7t5v0__aoi22_2 ;
  ORIGIN 0.000 0.000 ;
  SIZE 8.960 BY 3.920 ;
  SYMMETRY X Y ;
  SITE GF018hv5v_mcu_sc7 ;
  PIN A1
    DIRECTION INPUT ;
    ANTENNAGATEAREA 2.193000 ;
    PORT
      LAYER Metal1 ;
        RECT 5.690 1.210 8.380 1.570 ;
    END
  END A1
  PIN A2
    DIRECTION INPUT ;
    ANTENNAGATEAREA 2.193000 ;
    PORT
      LAYER Metal1 ;
        RECT 4.950 1.800 8.380 2.120 ;
        RECT 4.950 1.400 5.235 1.800 ;
    END
  END A2
  PIN B1
    DIRECTION INPUT ;
    ANTENNAGATEAREA 2.193000 ;
    PORT
      LAYER Metal1 ;
        RECT 1.650 1.030 2.090 1.590 ;
        RECT 0.940 0.610 2.090 1.030 ;
    END
  END B1
  PIN B2
    DIRECTION INPUT ;
    ANTENNAGATEAREA 2.193000 ;
    PORT
      LAYER Metal1 ;
        RECT 0.620 1.820 4.030 2.120 ;
    END
  END B2
  PIN ZN
    DIRECTION OUTPUT ;
    ANTENNADIFFAREA 2.139725 ;
    PORT
      LAYER Metal1 ;
        RECT 4.345 2.360 7.670 2.780 ;
        RECT 4.345 1.150 4.720 2.360 ;
        RECT 2.320 1.100 4.720 1.150 ;
        RECT 2.320 0.870 5.155 1.100 ;
        RECT 2.320 0.715 2.555 0.870 ;
        RECT 4.925 0.640 6.650 0.870 ;
    END
  END ZN
  PIN VDD
    DIRECTION INOUT ;
    USE POWER ;
    SHAPE ABUTMENT ;
    PORT
      LAYER Metal1 ;
        RECT 0.000 3.620 8.960 4.220 ;
        RECT 1.265 3.160 1.495 3.620 ;
        RECT 3.305 3.160 3.535 3.620 ;
    END
  END VDD
  PIN VNW
    DIRECTION INOUT ;
    USE POWER ;
    PORT
      LAYER Nwell ;
        RECT -0.430 1.760 9.390 4.350 ;
    END
  END VNW
  PIN VPW
    DIRECTION INOUT ;
    USE GROUND ;
    PORT
      LAYER Pwell ;
        RECT -0.430 -0.430 9.390 1.760 ;
    END
  END VPW
  PIN VSS
    DIRECTION INOUT ;
    USE GROUND ;
    SHAPE ABUTMENT ;
    PORT
      LAYER Metal1 ;
        RECT 0.245 0.300 0.475 0.905 ;
        RECT 4.270 0.300 4.610 0.640 ;
        RECT 8.405 0.300 8.635 0.905 ;
        RECT 0.000 -0.300 8.960 0.300 ;
    END
  END VSS
  OBS
      LAYER Metal1 ;
        RECT 0.190 2.760 0.530 3.380 ;
        RECT 2.230 2.760 2.570 3.380 ;
        RECT 3.795 3.130 8.690 3.365 ;
        RECT 3.795 2.760 4.025 3.130 ;
        RECT 0.190 2.530 4.025 2.760 ;
        RECT 8.350 2.475 8.690 3.130 ;
  END
END gf180mcu_fd_sc_mcu7t5v0__aoi22_2

#--------EOF---------

MACRO gf180mcu_fd_sc_mcu7t5v0__aoi211_1
  CLASS core ;
  FOREIGN gf180mcu_fd_sc_mcu7t5v0__aoi211_1 ;
  ORIGIN 0.000 0.000 ;
  SIZE 5.600 BY 3.920 ;
  SYMMETRY X Y ;
  SITE GF018hv5v_mcu_sc7 ;
  PIN A1
    DIRECTION INPUT ;
    ANTENNAGATEAREA 1.033500 ;
    PORT
      LAYER Metal1 ;
        RECT 1.770 1.770 2.690 2.150 ;
        RECT 1.770 1.230 2.150 1.770 ;
    END
  END A1
  PIN A2
    DIRECTION INPUT ;
    ANTENNAGATEAREA 1.033500 ;
    PORT
      LAYER Metal1 ;
        RECT 0.650 1.160 1.000 2.190 ;
    END
  END A2
  PIN B
    DIRECTION INPUT ;
    ANTENNAGATEAREA 0.886500 ;
    PORT
      LAYER Metal1 ;
        RECT 2.920 2.850 4.010 3.310 ;
        RECT 2.920 1.730 3.220 2.850 ;
    END
  END B
  PIN C
    DIRECTION INPUT ;
    ANTENNAGATEAREA 0.886500 ;
    PORT
      LAYER Metal1 ;
        RECT 3.450 1.770 4.950 2.150 ;
    END
  END C
  PIN ZN
    DIRECTION OUTPUT ;
    ANTENNADIFFAREA 1.259900 ;
    PORT
      LAYER Metal1 ;
        RECT 1.240 1.000 1.540 2.725 ;
        RECT 3.050 1.045 4.860 1.275 ;
        RECT 3.050 1.000 3.280 1.045 ;
        RECT 1.240 0.560 3.280 1.000 ;
        RECT 4.630 0.565 4.860 1.045 ;
    END
  END ZN
  PIN VDD
    DIRECTION INOUT ;
    USE POWER ;
    SHAPE ABUTMENT ;
    PORT
      LAYER Metal1 ;
        RECT 0.000 3.620 5.600 4.220 ;
        RECT 4.530 2.530 4.760 3.620 ;
    END
  END VDD
  PIN VNW
    DIRECTION INOUT ;
    USE POWER ;
    PORT
      LAYER Nwell ;
        RECT -0.430 1.760 6.030 4.350 ;
    END
  END VNW
  PIN VPW
    DIRECTION INOUT ;
    USE GROUND ;
    PORT
      LAYER Pwell ;
        RECT -0.430 -0.430 6.030 1.760 ;
    END
  END VPW
  PIN VSS
    DIRECTION INOUT ;
    USE GROUND ;
    SHAPE ABUTMENT ;
    PORT
      LAYER Metal1 ;
        RECT 0.250 0.300 0.480 0.870 ;
        RECT 3.510 0.300 3.740 0.815 ;
        RECT 0.000 -0.300 5.600 0.300 ;
    END
  END VSS
  OBS
      LAYER Metal1 ;
        RECT 0.250 3.150 2.520 3.380 ;
        RECT 0.250 2.530 0.480 3.150 ;
        RECT 2.290 2.530 2.520 3.150 ;
  END
END gf180mcu_fd_sc_mcu7t5v0__aoi211_1

#--------EOF---------

MACRO gf180mcu_fd_sc_mcu7t5v0__aoi211_2
  CLASS core ;
  FOREIGN gf180mcu_fd_sc_mcu7t5v0__aoi211_2 ;
  ORIGIN 0.000 0.000 ;
  SIZE 9.520 BY 3.920 ;
  SYMMETRY X Y ;
  SITE GF018hv5v_mcu_sc7 ;
  PIN A1
    DIRECTION INPUT ;
    ANTENNAGATEAREA 2.076000 ;
    PORT
      LAYER Metal1 ;
        RECT 1.160 1.240 3.310 1.560 ;
    END
  END A1
  PIN A2
    DIRECTION INPUT ;
    ANTENNAGATEAREA 2.076000 ;
    PORT
      LAYER Metal1 ;
        RECT 0.420 1.800 3.770 2.120 ;
    END
  END A2
  PIN B
    DIRECTION INPUT ;
    ANTENNAGATEAREA 1.758000 ;
    PORT
      LAYER Metal1 ;
        RECT 4.600 2.595 5.665 2.710 ;
        RECT 4.600 2.360 8.430 2.595 ;
        RECT 4.600 1.800 5.220 2.360 ;
        RECT 7.885 2.120 8.430 2.360 ;
        RECT 7.885 1.800 9.025 2.120 ;
    END
  END B
  PIN C
    DIRECTION INPUT ;
    ANTENNAGATEAREA 1.758000 ;
    PORT
      LAYER Metal1 ;
        RECT 5.650 1.800 7.395 2.120 ;
    END
  END C
  PIN ZN
    DIRECTION OUTPUT ;
    ANTENNADIFFAREA 2.126800 ;
    PORT
      LAYER Metal1 ;
        RECT 1.170 2.360 4.360 2.780 ;
        RECT 4.040 1.560 4.360 2.360 ;
        RECT 3.655 1.240 5.145 1.560 ;
        RECT 3.655 1.000 3.915 1.240 ;
        RECT 2.150 0.680 3.915 1.000 ;
        RECT 4.915 1.100 5.145 1.240 ;
        RECT 4.915 0.870 7.990 1.100 ;
        RECT 5.410 0.560 5.750 0.870 ;
        RECT 7.650 0.560 7.990 0.870 ;
    END
  END ZN
  PIN VDD
    DIRECTION INOUT ;
    USE POWER ;
    SHAPE ABUTMENT ;
    PORT
      LAYER Metal1 ;
        RECT 0.000 3.620 9.520 4.220 ;
        RECT 6.450 3.285 6.790 3.620 ;
    END
  END VDD
  PIN VNW
    DIRECTION INOUT ;
    USE POWER ;
    PORT
      LAYER Nwell ;
        RECT -0.430 1.760 9.950 4.350 ;
    END
  END VNW
  PIN VPW
    DIRECTION INOUT ;
    USE GROUND ;
    PORT
      LAYER Pwell ;
        RECT -0.430 -0.430 9.950 1.760 ;
    END
  END VPW
  PIN VSS
    DIRECTION INOUT ;
    USE GROUND ;
    SHAPE ABUTMENT ;
    PORT
      LAYER Metal1 ;
        RECT 0.245 0.300 0.475 0.910 ;
        RECT 4.165 0.300 4.395 0.690 ;
        RECT 6.530 0.300 6.870 0.640 ;
        RECT 8.825 0.300 9.055 0.695 ;
        RECT 0.000 -0.300 9.520 0.300 ;
    END
  END VSS
  OBS
      LAYER Metal1 ;
        RECT 0.245 3.160 6.140 3.390 ;
        RECT 0.245 2.500 0.475 3.160 ;
        RECT 5.910 3.055 6.140 3.160 ;
        RECT 8.725 3.055 8.955 3.390 ;
        RECT 5.910 2.825 8.955 3.055 ;
        RECT 8.725 2.500 8.955 2.825 ;
  END
END gf180mcu_fd_sc_mcu7t5v0__aoi211_2

#--------EOF---------

MACRO gf180mcu_fd_sc_mcu7t5v0__aoi221_1
  CLASS core ;
  FOREIGN gf180mcu_fd_sc_mcu7t5v0__aoi221_1 ;
  ORIGIN 0.000 0.000 ;
  SIZE 6.160 BY 3.920 ;
  SYMMETRY X Y ;
  SITE GF018hv5v_mcu_sc7 ;
  PIN A1
    DIRECTION INPUT ;
    ANTENNAGATEAREA 1.033500 ;
    PORT
      LAYER Metal1 ;
        RECT 5.150 1.160 5.510 2.300 ;
    END
  END A1
  PIN A2
    DIRECTION INPUT ;
    ANTENNAGATEAREA 1.033500 ;
    PORT
      LAYER Metal1 ;
        RECT 4.005 1.585 4.370 2.835 ;
    END
  END A2
  PIN B1
    DIRECTION INPUT ;
    ANTENNAGATEAREA 1.033500 ;
    PORT
      LAYER Metal1 ;
        RECT 1.750 1.780 2.690 2.150 ;
        RECT 1.750 1.210 2.150 1.780 ;
    END
  END B1
  PIN B2
    DIRECTION INPUT ;
    ANTENNAGATEAREA 1.033500 ;
    PORT
      LAYER Metal1 ;
        RECT 0.120 1.770 1.070 2.150 ;
        RECT 0.680 1.160 1.070 1.770 ;
    END
  END B2
  PIN C
    DIRECTION INPUT ;
    ANTENNAGATEAREA 0.886500 ;
    PORT
      LAYER Metal1 ;
        RECT 2.920 1.550 3.240 3.320 ;
    END
  END C
  PIN ZN
    DIRECTION OUTPUT ;
    ANTENNADIFFAREA 1.489200 ;
    PORT
      LAYER Metal1 ;
        RECT 4.600 1.205 4.920 2.865 ;
        RECT 2.950 0.975 4.920 1.205 ;
        RECT 2.950 0.905 3.180 0.975 ;
        RECT 2.150 0.675 3.180 0.905 ;
        RECT 4.600 0.905 4.920 0.975 ;
        RECT 4.600 0.675 5.980 0.905 ;
    END
  END ZN
  PIN VDD
    DIRECTION INOUT ;
    USE POWER ;
    SHAPE ABUTMENT ;
    PORT
      LAYER Metal1 ;
        RECT 0.000 3.620 6.160 4.220 ;
        RECT 1.365 3.160 1.595 3.620 ;
    END
  END VDD
  PIN VNW
    DIRECTION INOUT ;
    USE POWER ;
    PORT
      LAYER Nwell ;
        RECT -0.430 1.760 6.590 4.350 ;
    END
  END VNW
  PIN VPW
    DIRECTION INOUT ;
    USE GROUND ;
    PORT
      LAYER Pwell ;
        RECT -0.430 -0.430 6.590 1.760 ;
    END
  END VPW
  PIN VSS
    DIRECTION INOUT ;
    USE GROUND ;
    SHAPE ABUTMENT ;
    PORT
      LAYER Metal1 ;
        RECT 0.190 0.300 0.530 0.815 ;
        RECT 3.670 0.300 4.010 0.745 ;
        RECT 0.000 -0.300 6.160 0.300 ;
    END
  END VSS
  OBS
      LAYER Metal1 ;
        RECT 0.280 2.930 0.630 3.380 ;
        RECT 2.330 2.930 2.670 3.380 ;
        RECT 0.280 2.590 2.670 2.930 ;
        RECT 3.545 3.150 5.915 3.380 ;
        RECT 3.545 2.530 3.775 3.150 ;
        RECT 5.685 2.530 5.915 3.150 ;
  END
END gf180mcu_fd_sc_mcu7t5v0__aoi221_1

#--------EOF---------

MACRO gf180mcu_fd_sc_mcu7t5v0__aoi221_2
  CLASS core ;
  FOREIGN gf180mcu_fd_sc_mcu7t5v0__aoi221_2 ;
  ORIGIN 0.000 0.000 ;
  SIZE 12.880 BY 3.920 ;
  SYMMETRY X Y ;
  SITE GF018hv5v_mcu_sc7 ;
  PIN A1
    DIRECTION INPUT ;
    ANTENNAGATEAREA 1.978000 ;
    PORT
      LAYER Metal1 ;
        RECT 9.080 1.790 12.050 2.120 ;
        RECT 9.080 1.550 9.310 1.790 ;
    END
  END A1
  PIN A2
    DIRECTION INPUT ;
    ANTENNAGATEAREA 1.978000 ;
    PORT
      LAYER Metal1 ;
        RECT 9.570 1.225 12.050 1.560 ;
    END
  END A2
  PIN B1
    DIRECTION INPUT ;
    ANTENNAGATEAREA 1.978000 ;
    PORT
      LAYER Metal1 ;
        RECT 4.125 1.910 7.815 2.140 ;
        RECT 5.650 1.800 7.815 1.910 ;
    END
  END B1
  PIN B2
    DIRECTION INPUT ;
    ANTENNAGATEAREA 1.978000 ;
    PORT
      LAYER Metal1 ;
        RECT 0.525 1.785 3.270 2.150 ;
        RECT 3.040 1.680 3.270 1.785 ;
        RECT 3.040 1.450 5.390 1.680 ;
    END
  END B2
  PIN C
    DIRECTION INPUT ;
    ANTENNAGATEAREA 1.708000 ;
    PORT
      LAYER Metal1 ;
        RECT 0.870 1.325 2.810 1.555 ;
        RECT 2.580 1.220 2.810 1.325 ;
        RECT 5.770 1.220 8.310 1.560 ;
        RECT 2.580 1.210 8.310 1.220 ;
        RECT 2.580 0.990 6.000 1.210 ;
    END
  END C
  PIN ZN
    DIRECTION OUTPUT ;
    ANTENNADIFFAREA 2.496525 ;
    PORT
      LAYER Metal1 ;
        RECT 8.565 2.360 12.550 2.795 ;
        RECT 0.245 0.865 2.350 1.095 ;
        RECT 8.565 0.935 8.845 2.360 ;
        RECT 0.245 0.705 0.475 0.865 ;
        RECT 2.120 0.760 2.350 0.865 ;
        RECT 6.265 0.760 8.845 0.935 ;
        RECT 2.120 0.705 8.845 0.760 ;
        RECT 2.120 0.530 6.495 0.705 ;
        RECT 7.350 0.565 8.845 0.705 ;
        RECT 12.320 0.700 12.550 2.360 ;
    END
  END ZN
  PIN VDD
    DIRECTION INOUT ;
    USE POWER ;
    SHAPE ABUTMENT ;
    PORT
      LAYER Metal1 ;
        RECT 0.000 3.620 12.880 4.220 ;
        RECT 2.550 3.445 2.890 3.620 ;
        RECT 5.050 3.445 5.390 3.620 ;
    END
  END VDD
  PIN VNW
    DIRECTION INOUT ;
    USE POWER ;
    PORT
      LAYER Nwell ;
        RECT -0.430 1.760 13.310 4.350 ;
    END
  END VNW
  PIN VPW
    DIRECTION INOUT ;
    USE GROUND ;
    PORT
      LAYER Pwell ;
        RECT -0.430 -0.430 13.310 1.760 ;
    END
  END VPW
  PIN VSS
    DIRECTION INOUT ;
    USE GROUND ;
    SHAPE ABUTMENT ;
    PORT
      LAYER Metal1 ;
        RECT 1.530 0.300 1.870 0.635 ;
        RECT 6.725 0.300 7.065 0.475 ;
        RECT 10.305 0.300 10.645 0.635 ;
        RECT 0.000 -0.300 12.880 0.300 ;
    END
  END VSS
  OBS
      LAYER Metal1 ;
        RECT 0.345 3.215 2.290 3.350 ;
        RECT 5.855 3.215 12.505 3.365 ;
        RECT 0.345 3.135 12.505 3.215 ;
        RECT 0.345 3.120 6.195 3.135 ;
        RECT 0.345 2.460 0.575 3.120 ;
        RECT 2.075 2.985 6.195 3.120 ;
        RECT 1.310 2.525 7.410 2.755 ;
        RECT 8.105 2.460 8.335 3.135 ;
  END
END gf180mcu_fd_sc_mcu7t5v0__aoi221_2

#--------EOF---------

MACRO gf180mcu_fd_sc_mcu7t5v0__aoi222_1
  CLASS core ;
  FOREIGN gf180mcu_fd_sc_mcu7t5v0__aoi222_1 ;
  ORIGIN 0.000 0.000 ;
  SIZE 7.840 BY 3.920 ;
  SYMMETRY X Y ;
  SITE GF018hv5v_mcu_sc7 ;
  PIN A1
    DIRECTION INPUT ;
    ANTENNAGATEAREA 1.072000 ;
    PORT
      LAYER Metal1 ;
        RECT 6.840 2.330 7.720 2.710 ;
        RECT 6.840 1.230 7.180 2.330 ;
    END
  END A1
  PIN A2
    DIRECTION INPUT ;
    ANTENNAGATEAREA 1.072000 ;
    PORT
      LAYER Metal1 ;
        RECT 5.140 2.330 6.040 2.710 ;
        RECT 5.720 1.535 6.040 2.330 ;
    END
  END A2
  PIN B1
    DIRECTION INPUT ;
    ANTENNAGATEAREA 1.072000 ;
    PORT
      LAYER Metal1 ;
        RECT 2.350 1.770 3.800 2.150 ;
    END
  END B1
  PIN B2
    DIRECTION INPUT ;
    ANTENNAGATEAREA 1.072000 ;
    PORT
      LAYER Metal1 ;
        RECT 4.040 1.770 4.950 2.150 ;
        RECT 4.040 1.105 4.360 1.770 ;
    END
  END B2
  PIN C1
    DIRECTION INPUT ;
    ANTENNAGATEAREA 1.072000 ;
    PORT
      LAYER Metal1 ;
        RECT 1.800 0.550 2.120 2.235 ;
    END
  END C1
  PIN C2
    DIRECTION INPUT ;
    ANTENNAGATEAREA 1.072000 ;
    PORT
      LAYER Metal1 ;
        RECT 0.480 1.770 1.560 2.150 ;
        RECT 1.240 0.550 1.560 1.770 ;
    END
  END C2
  PIN ZN
    DIRECTION OUTPUT ;
    ANTENNADIFFAREA 1.756500 ;
    PORT
      LAYER Metal1 ;
        RECT 6.280 1.095 6.600 2.770 ;
        RECT 4.665 1.000 6.600 1.095 ;
        RECT 4.665 0.865 7.635 1.000 ;
        RECT 4.665 0.780 4.895 0.865 ;
        RECT 2.510 0.550 4.895 0.780 ;
        RECT 5.880 0.670 7.635 0.865 ;
    END
  END ZN
  PIN VDD
    DIRECTION INOUT ;
    USE POWER ;
    SHAPE ABUTMENT ;
    PORT
      LAYER Metal1 ;
        RECT 0.000 3.620 7.840 4.220 ;
        RECT 0.345 2.530 0.685 3.620 ;
        RECT 2.440 3.040 2.670 3.620 ;
    END
  END VDD
  PIN VNW
    DIRECTION INOUT ;
    USE POWER ;
    PORT
      LAYER Nwell ;
        RECT -0.430 1.760 8.270 4.350 ;
    END
  END VNW
  PIN VPW
    DIRECTION INOUT ;
    USE GROUND ;
    PORT
      LAYER Pwell ;
        RECT -0.430 -0.430 8.270 1.760 ;
    END
  END VPW
  PIN VSS
    DIRECTION INOUT ;
    USE GROUND ;
    SHAPE ABUTMENT ;
    PORT
      LAYER Metal1 ;
        RECT 0.480 0.300 0.710 0.905 ;
        RECT 5.145 0.300 5.485 0.635 ;
        RECT 0.000 -0.300 7.840 0.300 ;
    END
  END VSS
  OBS
      LAYER Metal1 ;
        RECT 1.365 2.760 1.705 3.380 ;
        RECT 3.095 3.095 7.635 3.325 ;
        RECT 1.365 2.530 4.500 2.760 ;
  END
END gf180mcu_fd_sc_mcu7t5v0__aoi222_1

#--------EOF---------

MACRO gf180mcu_fd_sc_mcu7t5v0__aoi222_2
  CLASS core ;
  FOREIGN gf180mcu_fd_sc_mcu7t5v0__aoi222_2 ;
  ORIGIN 0.000 0.000 ;
  SIZE 14.000 BY 3.920 ;
  SYMMETRY X Y ;
  SITE GF018hv5v_mcu_sc7 ;
  PIN A1
    DIRECTION INPUT ;
    ANTENNAGATEAREA 2.180000 ;
    PORT
      LAYER Metal1 ;
        RECT 9.700 1.960 12.960 2.195 ;
        RECT 12.440 0.550 12.960 1.960 ;
    END
  END A1
  PIN A2
    DIRECTION INPUT ;
    ANTENNAGATEAREA 2.180000 ;
    PORT
      LAYER Metal1 ;
        RECT 9.870 1.210 12.005 1.630 ;
    END
  END A2
  PIN B1
    DIRECTION INPUT ;
    ANTENNAGATEAREA 2.180000 ;
    PORT
      LAYER Metal1 ;
        RECT 7.370 1.555 8.710 2.150 ;
        RECT 5.605 1.325 8.710 1.555 ;
    END
  END B1
  PIN B2
    DIRECTION INPUT ;
    ANTENNAGATEAREA 2.180000 ;
    PORT
      LAYER Metal1 ;
        RECT 4.570 1.785 6.825 2.195 ;
        RECT 4.570 1.770 5.460 1.785 ;
    END
  END B2
  PIN C1
    DIRECTION INPUT ;
    ANTENNAGATEAREA 2.180000 ;
    PORT
      LAYER Metal1 ;
        RECT 0.655 1.965 4.155 2.195 ;
        RECT 2.225 1.800 4.155 1.965 ;
    END
  END C1
  PIN C2
    DIRECTION INPUT ;
    ANTENNAGATEAREA 2.180000 ;
    PORT
      LAYER Metal1 ;
        RECT 0.650 1.570 1.790 1.590 ;
        RECT 0.650 1.340 3.485 1.570 ;
        RECT 0.650 1.210 1.790 1.340 ;
    END
  END C2
  PIN ZN
    DIRECTION OUTPUT ;
    ANTENNADIFFAREA 3.168800 ;
    PORT
      LAYER Metal1 ;
        RECT 9.050 2.440 13.485 2.670 ;
        RECT 9.050 1.095 9.470 2.440 ;
        RECT 2.020 0.970 9.470 1.095 ;
        RECT 0.225 0.865 9.470 0.970 ;
        RECT 0.225 0.740 2.250 0.865 ;
        RECT 4.925 0.845 5.265 0.865 ;
        RECT 9.050 0.790 9.470 0.865 ;
        RECT 13.255 0.570 13.485 2.440 ;
    END
  END ZN
  PIN VDD
    DIRECTION INOUT ;
    USE POWER ;
    SHAPE ABUTMENT ;
    PORT
      LAYER Metal1 ;
        RECT 0.000 3.620 14.000 4.220 ;
        RECT 0.225 2.530 0.565 3.620 ;
        RECT 2.320 3.040 2.550 3.620 ;
        RECT 4.360 3.040 4.590 3.620 ;
    END
  END VDD
  PIN VNW
    DIRECTION INOUT ;
    USE POWER ;
    PORT
      LAYER Nwell ;
        RECT -0.430 1.760 14.430 4.350 ;
    END
  END VNW
  PIN VPW
    DIRECTION INOUT ;
    USE GROUND ;
    PORT
      LAYER Pwell ;
        RECT -0.430 -0.430 14.430 1.760 ;
    END
  END VPW
  PIN VSS
    DIRECTION INOUT ;
    USE GROUND ;
    SHAPE ABUTMENT ;
    PORT
      LAYER Metal1 ;
        RECT 2.455 0.300 2.795 0.635 ;
        RECT 7.065 0.300 7.405 0.635 ;
        RECT 11.160 0.300 11.500 0.635 ;
        RECT 0.000 -0.300 14.000 0.300 ;
    END
  END VSS
  OBS
      LAYER Metal1 ;
        RECT 1.245 2.760 1.585 3.380 ;
        RECT 3.285 2.760 3.625 3.380 ;
        RECT 5.020 3.160 13.550 3.390 ;
        RECT 1.245 2.530 8.425 2.760 ;
  END
END gf180mcu_fd_sc_mcu7t5v0__aoi222_2

#--------EOF---------

MACRO gf180mcu_fd_sc_mcu7t5v0__buf_1
  CLASS core ;
  FOREIGN gf180mcu_fd_sc_mcu7t5v0__buf_1 ;
  ORIGIN 0.000 0.000 ;
  SIZE 3.360 BY 3.920 ;
  SYMMETRY X Y ;
  SITE GF018hv5v_mcu_sc7 ;
  PIN I
    DIRECTION INPUT ;
    ANTENNAGATEAREA 0.498500 ;
    PORT
      LAYER Metal1 ;
        RECT 0.705 1.630 1.590 2.190 ;
        RECT 0.705 0.650 1.220 1.630 ;
    END
  END I
  PIN Z
    DIRECTION OUTPUT ;
    ANTENNADIFFAREA 0.897600 ;
    PORT
      LAYER Metal1 ;
        RECT 2.485 1.600 2.955 3.380 ;
        RECT 2.330 0.575 2.955 1.600 ;
    END
  END Z
  PIN VDD
    DIRECTION INOUT ;
    USE POWER ;
    SHAPE ABUTMENT ;
    PORT
      LAYER Metal1 ;
        RECT 0.000 3.620 3.360 4.220 ;
        RECT 1.530 3.130 1.870 3.620 ;
    END
  END VDD
  PIN VNW
    DIRECTION INOUT ;
    USE POWER ;
    PORT
      LAYER Nwell ;
        RECT -0.430 1.760 3.790 4.350 ;
    END
  END VNW
  PIN VPW
    DIRECTION INOUT ;
    USE GROUND ;
    PORT
      LAYER Pwell ;
        RECT -0.430 -0.430 3.790 1.760 ;
    END
  END VPW
  PIN VSS
    DIRECTION INOUT ;
    USE GROUND ;
    SHAPE ABUTMENT ;
    PORT
      LAYER Metal1 ;
        RECT 1.585 0.300 1.815 0.865 ;
        RECT 0.000 -0.300 3.360 0.300 ;
    END
  END VSS
  OBS
      LAYER Metal1 ;
        RECT 0.245 2.815 0.630 3.390 ;
        RECT 0.245 2.580 2.255 2.815 ;
        RECT 0.245 0.800 0.475 2.580 ;
        RECT 1.970 1.830 2.255 2.580 ;
  END
END gf180mcu_fd_sc_mcu7t5v0__buf_1

#--------EOF---------

MACRO gf180mcu_fd_sc_mcu7t5v0__buf_2
  CLASS core ;
  FOREIGN gf180mcu_fd_sc_mcu7t5v0__buf_2 ;
  ORIGIN 0.000 0.000 ;
  SIZE 4.480 BY 3.920 ;
  SYMMETRY X Y ;
  SITE GF018hv5v_mcu_sc7 ;
  PIN I
    DIRECTION INPUT ;
    ANTENNAGATEAREA 1.102000 ;
    PORT
      LAYER Metal1 ;
        RECT 0.705 1.625 1.650 2.150 ;
        RECT 0.705 0.610 1.015 1.625 ;
    END
  END I
  PIN Z
    DIRECTION OUTPUT ;
    ANTENNADIFFAREA 1.182800 ;
    PORT
      LAYER Metal1 ;
        RECT 2.675 2.700 2.905 3.390 ;
        RECT 2.675 2.210 3.800 2.700 ;
        RECT 3.480 1.300 3.800 2.210 ;
        RECT 2.675 1.065 3.800 1.300 ;
        RECT 2.675 0.570 2.905 1.065 ;
    END
  END Z
  PIN VDD
    DIRECTION INOUT ;
    USE POWER ;
    SHAPE ABUTMENT ;
    PORT
      LAYER Metal1 ;
        RECT 0.000 3.620 4.480 4.220 ;
        RECT 1.405 3.010 1.745 3.620 ;
        RECT 3.640 3.010 3.980 3.620 ;
    END
  END VDD
  PIN VNW
    DIRECTION INOUT ;
    USE POWER ;
    PORT
      LAYER Nwell ;
        RECT -0.430 1.760 4.910 4.350 ;
    END
  END VNW
  PIN VPW
    DIRECTION INOUT ;
    USE GROUND ;
    PORT
      LAYER Pwell ;
        RECT -0.430 -0.430 4.910 1.760 ;
    END
  END VPW
  PIN VSS
    DIRECTION INOUT ;
    USE GROUND ;
    SHAPE ABUTMENT ;
    PORT
      LAYER Metal1 ;
        RECT 1.405 0.300 1.745 0.765 ;
        RECT 3.740 0.300 4.080 0.765 ;
        RECT 0.000 -0.300 4.480 0.300 ;
    END
  END VSS
  OBS
      LAYER Metal1 ;
        RECT 0.245 2.625 0.475 3.390 ;
        RECT 0.245 2.390 2.130 2.625 ;
        RECT 0.245 0.570 0.475 2.390 ;
        RECT 1.900 1.890 2.130 2.390 ;
        RECT 1.900 1.550 3.240 1.890 ;
  END
END gf180mcu_fd_sc_mcu7t5v0__buf_2

#--------EOF---------

MACRO gf180mcu_fd_sc_mcu7t5v0__buf_3
  CLASS core ;
  FOREIGN gf180mcu_fd_sc_mcu7t5v0__buf_3 ;
  ORIGIN 0.000 0.000 ;
  SIZE 5.600 BY 3.920 ;
  SYMMETRY X Y ;
  SITE GF018hv5v_mcu_sc7 ;
  PIN I
    DIRECTION INPUT ;
    ANTENNAGATEAREA 1.102000 ;
    PORT
      LAYER Metal1 ;
        RECT 0.705 1.625 1.650 2.150 ;
        RECT 0.705 0.610 1.015 1.625 ;
    END
  END I
  PIN Z
    DIRECTION OUTPUT ;
    ANTENNADIFFAREA 2.080400 ;
    PORT
      LAYER Metal1 ;
        RECT 2.675 2.660 2.905 3.390 ;
        RECT 4.580 2.660 5.160 3.390 ;
        RECT 2.675 2.210 5.160 2.660 ;
        RECT 4.580 1.300 5.160 2.210 ;
        RECT 2.675 1.065 5.160 1.300 ;
        RECT 2.675 0.570 2.905 1.065 ;
        RECT 4.580 0.570 5.160 1.065 ;
    END
  END Z
  PIN VDD
    DIRECTION INOUT ;
    USE POWER ;
    SHAPE ABUTMENT ;
    PORT
      LAYER Metal1 ;
        RECT 0.000 3.620 5.600 4.220 ;
        RECT 1.210 2.910 1.550 3.620 ;
        RECT 3.640 2.910 3.980 3.620 ;
    END
  END VDD
  PIN VNW
    DIRECTION INOUT ;
    USE POWER ;
    PORT
      LAYER Nwell ;
        RECT -0.430 1.760 6.030 4.350 ;
    END
  END VNW
  PIN VPW
    DIRECTION INOUT ;
    USE GROUND ;
    PORT
      LAYER Pwell ;
        RECT -0.430 -0.430 6.030 1.760 ;
    END
  END VPW
  PIN VSS
    DIRECTION INOUT ;
    USE GROUND ;
    SHAPE ABUTMENT ;
    PORT
      LAYER Metal1 ;
        RECT 1.500 0.300 1.840 0.765 ;
        RECT 3.740 0.300 4.080 0.765 ;
        RECT 0.000 -0.300 5.600 0.300 ;
    END
  END VSS
  OBS
      LAYER Metal1 ;
        RECT 0.245 2.625 0.475 3.390 ;
        RECT 0.245 2.390 2.130 2.625 ;
        RECT 0.245 0.570 0.475 2.390 ;
        RECT 1.900 1.890 2.130 2.390 ;
        RECT 1.900 1.550 4.175 1.890 ;
  END
END gf180mcu_fd_sc_mcu7t5v0__buf_3

#--------EOF---------

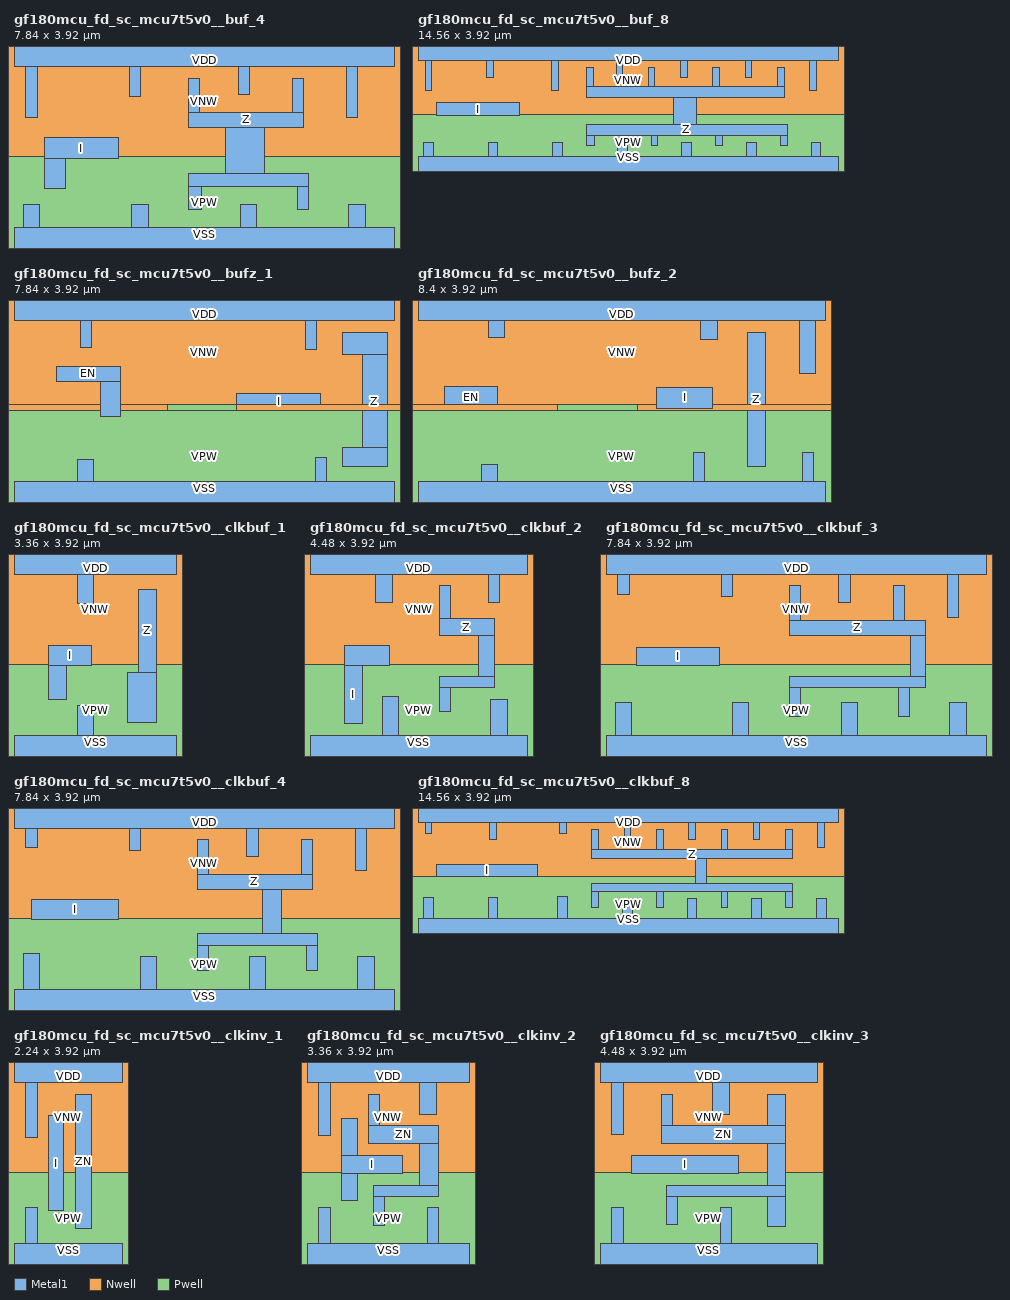
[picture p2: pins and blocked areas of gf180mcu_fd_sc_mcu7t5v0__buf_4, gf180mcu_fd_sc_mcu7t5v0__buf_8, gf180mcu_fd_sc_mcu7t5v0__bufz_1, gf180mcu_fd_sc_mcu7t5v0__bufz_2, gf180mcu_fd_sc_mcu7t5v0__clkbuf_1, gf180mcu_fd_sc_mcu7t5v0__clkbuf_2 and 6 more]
MACRO gf180mcu_fd_sc_mcu7t5v0__buf_4
  CLASS core ;
  FOREIGN gf180mcu_fd_sc_mcu7t5v0__buf_4 ;
  ORIGIN 0.000 0.000 ;
  SIZE 7.840 BY 3.920 ;
  SYMMETRY X Y ;
  SITE GF018hv5v_mcu_sc7 ;
  PIN I
    DIRECTION INPUT ;
    ANTENNAGATEAREA 2.204000 ;
    PORT
      LAYER Metal1 ;
        RECT 0.620 1.715 2.150 2.150 ;
        RECT 0.620 1.100 1.060 1.715 ;
    END
  END I
  PIN Z
    DIRECTION OUTPUT ;
    ANTENNADIFFAREA 2.365600 ;
    PORT
      LAYER Metal1 ;
        RECT 3.605 2.680 3.835 3.380 ;
        RECT 5.745 2.680 5.975 3.380 ;
        RECT 3.605 2.360 5.975 2.680 ;
        RECT 4.360 1.420 5.160 2.360 ;
        RECT 3.605 1.140 6.075 1.420 ;
        RECT 3.605 0.675 3.865 1.140 ;
        RECT 5.845 0.675 6.075 1.140 ;
    END
  END Z
  PIN VDD
    DIRECTION INOUT ;
    USE POWER ;
    SHAPE ABUTMENT ;
    PORT
      LAYER Metal1 ;
        RECT 0.000 3.620 7.840 4.220 ;
        RECT 0.245 2.570 0.475 3.620 ;
        RECT 2.385 3.000 2.615 3.620 ;
        RECT 4.625 3.050 4.855 3.620 ;
        RECT 6.865 2.570 7.095 3.620 ;
    END
  END VDD
  PIN VNW
    DIRECTION INOUT ;
    USE POWER ;
    PORT
      LAYER Nwell ;
        RECT -0.430 1.760 8.270 4.350 ;
    END
  END VNW
  PIN VPW
    DIRECTION INOUT ;
    USE GROUND ;
    PORT
      LAYER Pwell ;
        RECT -0.430 -0.430 8.270 1.760 ;
    END
  END VPW
  PIN VSS
    DIRECTION INOUT ;
    USE GROUND ;
    SHAPE ABUTMENT ;
    PORT
      LAYER Metal1 ;
        RECT 0.190 0.300 0.530 0.765 ;
        RECT 2.430 0.300 2.770 0.765 ;
        RECT 4.670 0.300 5.010 0.765 ;
        RECT 6.910 0.300 7.250 0.765 ;
        RECT 0.000 -0.300 7.840 0.300 ;
    END
  END VSS
  OBS
      LAYER Metal1 ;
        RECT 1.265 2.760 1.495 3.380 ;
        RECT 1.265 2.530 2.905 2.760 ;
        RECT 2.670 2.025 2.905 2.530 ;
        RECT 2.670 1.685 4.095 2.025 ;
        RECT 5.585 1.685 6.810 2.025 ;
        RECT 2.670 1.250 2.905 1.685 ;
        RECT 1.365 1.015 2.905 1.250 ;
        RECT 1.365 0.675 1.595 1.015 ;
  END
END gf180mcu_fd_sc_mcu7t5v0__buf_4

#--------EOF---------

MACRO gf180mcu_fd_sc_mcu7t5v0__buf_8
  CLASS core ;
  FOREIGN gf180mcu_fd_sc_mcu7t5v0__buf_8 ;
  ORIGIN 0.000 0.000 ;
  SIZE 14.560 BY 3.920 ;
  SYMMETRY X Y ;
  SITE GF018hv5v_mcu_sc7 ;
  PIN I
    DIRECTION INPUT ;
    ANTENNAGATEAREA 4.408000 ;
    PORT
      LAYER Metal1 ;
        RECT 0.650 1.715 3.510 2.150 ;
    END
  END I
  PIN Z
    DIRECTION OUTPUT ;
    ANTENNADIFFAREA 4.731200 ;
    PORT
      LAYER Metal1 ;
        RECT 5.845 2.710 6.075 3.380 ;
        RECT 7.985 2.710 8.215 3.380 ;
        RECT 10.225 2.710 10.455 3.380 ;
        RECT 12.465 2.710 12.695 3.380 ;
        RECT 5.845 2.330 12.695 2.710 ;
        RECT 8.840 1.420 9.640 2.330 ;
        RECT 5.845 1.040 12.795 1.420 ;
        RECT 5.845 0.675 6.105 1.040 ;
        RECT 8.085 0.675 8.315 1.040 ;
        RECT 10.325 0.675 10.555 1.040 ;
        RECT 12.565 0.675 12.795 1.040 ;
    END
  END Z
  PIN VDD
    DIRECTION INOUT ;
    USE POWER ;
    SHAPE ABUTMENT ;
    PORT
      LAYER Metal1 ;
        RECT 0.000 3.620 14.560 4.220 ;
        RECT 0.245 2.570 0.475 3.620 ;
        RECT 2.385 3.040 2.615 3.620 ;
        RECT 4.625 2.570 4.855 3.620 ;
        RECT 6.865 3.040 7.095 3.620 ;
        RECT 9.105 3.040 9.335 3.620 ;
        RECT 11.345 3.040 11.575 3.620 ;
        RECT 13.585 2.570 13.815 3.620 ;
    END
  END VDD
  PIN VNW
    DIRECTION INOUT ;
    USE POWER ;
    PORT
      LAYER Nwell ;
        RECT -0.430 1.760 14.990 4.350 ;
    END
  END VNW
  PIN VPW
    DIRECTION INOUT ;
    USE GROUND ;
    PORT
      LAYER Pwell ;
        RECT -0.430 -0.430 14.990 1.760 ;
    END
  END VPW
  PIN VSS
    DIRECTION INOUT ;
    USE GROUND ;
    SHAPE ABUTMENT ;
    PORT
      LAYER Metal1 ;
        RECT 0.190 0.300 0.530 0.765 ;
        RECT 2.430 0.300 2.770 0.765 ;
        RECT 4.670 0.300 5.010 0.765 ;
        RECT 6.910 0.300 7.250 0.765 ;
        RECT 9.150 0.300 9.490 0.765 ;
        RECT 11.390 0.300 11.730 0.765 ;
        RECT 13.630 0.300 13.970 0.765 ;
        RECT 0.000 -0.300 14.560 0.300 ;
    END
  END VSS
  OBS
      LAYER Metal1 ;
        RECT 1.265 2.760 1.495 3.380 ;
        RECT 3.505 2.760 3.735 3.380 ;
        RECT 1.265 2.530 4.315 2.760 ;
        RECT 3.980 2.025 4.315 2.530 ;
        RECT 3.980 1.685 8.270 2.025 ;
        RECT 10.340 1.685 13.540 2.030 ;
        RECT 3.980 1.250 4.315 1.685 ;
        RECT 1.365 1.015 4.315 1.250 ;
        RECT 1.365 0.675 1.595 1.015 ;
        RECT 3.605 0.675 3.835 1.015 ;
  END
END gf180mcu_fd_sc_mcu7t5v0__buf_8

#--------EOF---------

MACRO gf180mcu_fd_sc_mcu7t5v0__bufz_1
  CLASS core ;
  FOREIGN gf180mcu_fd_sc_mcu7t5v0__bufz_1 ;
  ORIGIN 0.000 0.000 ;
  SIZE 7.840 BY 3.920 ;
  SYMMETRY X Y ;
  SITE GF018hv5v_mcu_sc7 ;
  PIN EN
    DIRECTION INPUT ;
    ANTENNAGATEAREA 1.052000 ;
    PORT
      LAYER Metal1 ;
        RECT 0.870 2.360 2.190 2.680 ;
        RECT 1.780 1.650 2.190 2.360 ;
    END
  END EN
  PIN I
    DIRECTION INPUT ;
    ANTENNAGATEAREA 0.526000 ;
    PORT
      LAYER Metal1 ;
        RECT 4.600 1.795 6.330 2.120 ;
    END
  END I
  PIN Z
    DIRECTION OUTPUT ;
    ANTENNADIFFAREA 0.897600 ;
    PORT
      LAYER Metal1 ;
        RECT 6.770 2.920 7.710 3.380 ;
        RECT 7.180 1.000 7.710 2.920 ;
        RECT 6.770 0.600 7.710 1.000 ;
    END
  END Z
  PIN VDD
    DIRECTION INOUT ;
    USE POWER ;
    SHAPE ABUTMENT ;
    PORT
      LAYER Metal1 ;
        RECT 0.000 3.620 7.840 4.220 ;
        RECT 1.365 3.065 1.595 3.620 ;
        RECT 6.005 3.015 6.235 3.620 ;
    END
  END VDD
  PIN VNW
    DIRECTION INOUT ;
    USE POWER ;
    PORT
      LAYER Nwell ;
        RECT -0.430 1.885 8.270 4.350 ;
        RECT -0.430 1.760 3.175 1.885 ;
        RECT 4.595 1.760 8.270 1.885 ;
    END
  END VNW
  PIN VPW
    DIRECTION INOUT ;
    USE GROUND ;
    PORT
      LAYER Pwell ;
        RECT 3.175 1.760 4.595 1.885 ;
        RECT -0.430 -0.430 8.270 1.760 ;
    END
  END VPW
  PIN VSS
    DIRECTION INOUT ;
    USE GROUND ;
    SHAPE ABUTMENT ;
    PORT
      LAYER Metal1 ;
        RECT 1.310 0.300 1.650 0.760 ;
        RECT 6.225 0.300 6.455 0.790 ;
        RECT 0.000 -0.300 7.840 0.300 ;
    END
  END VSS
  OBS
      LAYER Metal1 ;
        RECT 0.190 1.240 0.575 3.370 ;
        RECT 2.290 3.160 5.235 3.390 ;
        RECT 2.630 2.480 3.175 2.740 ;
        RECT 2.630 1.240 2.860 2.480 ;
        RECT 3.650 2.170 3.910 2.930 ;
        RECT 0.190 1.005 2.860 1.240 ;
        RECT 3.090 1.880 3.910 2.170 ;
        RECT 0.190 0.530 0.530 1.005 ;
        RECT 3.090 0.760 3.320 1.880 ;
        RECT 4.140 1.220 4.370 3.160 ;
        RECT 4.920 2.590 5.235 3.160 ;
        RECT 4.920 2.360 6.855 2.590 ;
        RECT 6.625 1.880 6.855 2.360 ;
        RECT 3.760 0.990 4.370 1.220 ;
        RECT 4.885 1.335 6.950 1.565 ;
        RECT 4.885 0.760 5.115 1.335 ;
        RECT 2.340 0.530 5.115 0.760 ;
  END
END gf180mcu_fd_sc_mcu7t5v0__bufz_1

#--------EOF---------

MACRO gf180mcu_fd_sc_mcu7t5v0__bufz_2
  CLASS core ;
  FOREIGN gf180mcu_fd_sc_mcu7t5v0__bufz_2 ;
  ORIGIN 0.000 0.000 ;
  SIZE 8.400 BY 3.920 ;
  SYMMETRY X Y ;
  SITE GF018hv5v_mcu_sc7 ;
  PIN EN
    DIRECTION INPUT ;
    ANTENNAGATEAREA 1.929000 ;
    PORT
      LAYER Metal1 ;
        RECT 0.545 1.780 1.630 2.265 ;
    END
  END EN
  PIN I
    DIRECTION INPUT ;
    ANTENNAGATEAREA 1.079500 ;
    PORT
      LAYER Metal1 ;
        RECT 4.920 1.815 6.085 2.235 ;
    END
  END I
  PIN Z
    DIRECTION OUTPUT ;
    ANTENNADIFFAREA 1.037400 ;
    PORT
      LAYER Metal1 ;
        RECT 6.805 0.600 7.160 3.380 ;
    END
  END Z
  PIN VDD
    DIRECTION INOUT ;
    USE POWER ;
    SHAPE ABUTMENT ;
    PORT
      LAYER Metal1 ;
        RECT 0.000 3.620 8.400 4.220 ;
        RECT 1.450 3.260 1.790 3.620 ;
        RECT 5.830 3.220 6.170 3.620 ;
        RECT 7.870 2.530 8.210 3.620 ;
    END
  END VDD
  PIN VNW
    DIRECTION INOUT ;
    USE POWER ;
    PORT
      LAYER Nwell ;
        RECT -0.430 1.885 8.830 4.350 ;
        RECT -0.430 1.760 2.875 1.885 ;
        RECT 4.530 1.760 8.830 1.885 ;
    END
  END VNW
  PIN VPW
    DIRECTION INOUT ;
    USE GROUND ;
    PORT
      LAYER Pwell ;
        RECT 2.875 1.760 4.530 1.885 ;
        RECT -0.430 -0.430 8.830 1.760 ;
    END
  END VPW
  PIN VSS
    DIRECTION INOUT ;
    USE GROUND ;
    SHAPE ABUTMENT ;
    PORT
      LAYER Metal1 ;
        RECT 1.310 0.300 1.650 0.640 ;
        RECT 5.685 0.300 5.915 0.900 ;
        RECT 7.925 0.300 8.155 0.900 ;
        RECT 0.000 -0.300 8.400 0.300 ;
    END
  END VSS
  OBS
      LAYER Metal1 ;
        RECT 2.700 3.160 5.175 3.390 ;
        RECT 0.420 2.780 2.130 3.010 ;
        RECT 4.460 2.930 5.175 3.160 ;
        RECT 1.900 2.520 2.130 2.780 ;
        RECT 1.900 2.235 3.650 2.520 ;
        RECT 1.900 1.325 2.130 2.235 ;
        RECT 3.890 2.005 4.230 2.930 ;
        RECT 0.190 1.095 2.130 1.325 ;
        RECT 2.485 1.775 4.230 2.005 ;
        RECT 4.460 2.700 6.565 2.930 ;
        RECT 0.190 0.865 0.530 1.095 ;
        RECT 2.485 0.760 2.715 1.775 ;
        RECT 4.460 1.545 4.690 2.700 ;
        RECT 6.335 1.900 6.565 2.700 ;
        RECT 3.770 1.315 4.690 1.545 ;
        RECT 5.125 1.355 6.510 1.585 ;
        RECT 3.770 0.990 4.110 1.315 ;
        RECT 5.125 0.760 5.355 1.355 ;
        RECT 2.485 0.530 5.355 0.760 ;
  END
END gf180mcu_fd_sc_mcu7t5v0__bufz_2

#--------EOF---------

MACRO gf180mcu_fd_sc_mcu7t5v0__clkbuf_1
  CLASS core ;
  FOREIGN gf180mcu_fd_sc_mcu7t5v0__clkbuf_1 ;
  ORIGIN 0.000 0.000 ;
  SIZE 3.360 BY 3.920 ;
  SYMMETRY X Y ;
  SITE GF018hv5v_mcu_sc7 ;
  PIN I
    DIRECTION INPUT ;
    ANTENNAGATEAREA 0.741000 ;
    PORT
      LAYER Metal1 ;
        RECT 0.705 1.740 1.590 2.150 ;
        RECT 0.705 1.035 1.080 1.740 ;
    END
  END I
  PIN Z
    DIRECTION OUTPUT ;
    ANTENNADIFFAREA 0.754600 ;
    PORT
      LAYER Metal1 ;
        RECT 2.565 1.605 2.930 3.320 ;
        RECT 2.340 0.565 2.930 1.605 ;
    END
  END Z
  PIN VDD
    DIRECTION INOUT ;
    USE POWER ;
    SHAPE ABUTMENT ;
    PORT
      LAYER Metal1 ;
        RECT 0.000 3.620 3.360 4.220 ;
        RECT 1.310 3.015 1.650 3.620 ;
    END
  END VDD
  PIN VNW
    DIRECTION INOUT ;
    USE POWER ;
    PORT
      LAYER Nwell ;
        RECT -0.430 1.760 3.790 4.350 ;
    END
  END VNW
  PIN VPW
    DIRECTION INOUT ;
    USE GROUND ;
    PORT
      LAYER Pwell ;
        RECT -0.430 -0.430 3.790 1.760 ;
    END
  END VPW
  PIN VSS
    DIRECTION INOUT ;
    USE GROUND ;
    SHAPE ABUTMENT ;
    PORT
      LAYER Metal1 ;
        RECT 1.310 0.300 1.650 0.925 ;
        RECT 0.000 -0.300 3.360 0.300 ;
    END
  END VSS
  OBS
      LAYER Metal1 ;
        RECT 0.245 2.755 0.575 3.380 ;
        RECT 0.245 2.520 2.270 2.755 ;
        RECT 0.245 0.565 0.475 2.520 ;
        RECT 1.930 1.880 2.270 2.520 ;
  END
END gf180mcu_fd_sc_mcu7t5v0__clkbuf_1

#--------EOF---------

MACRO gf180mcu_fd_sc_mcu7t5v0__clkbuf_2
  CLASS core ;
  FOREIGN gf180mcu_fd_sc_mcu7t5v0__clkbuf_2 ;
  ORIGIN 0.000 0.000 ;
  SIZE 4.480 BY 3.920 ;
  SYMMETRY X Y ;
  SITE GF018hv5v_mcu_sc7 ;
  PIN I
    DIRECTION INPUT ;
    ANTENNAGATEAREA 0.726000 ;
    PORT
      LAYER Metal1 ;
        RECT 0.705 1.740 1.650 2.150 ;
        RECT 0.705 0.550 1.080 1.740 ;
    END
  END I
  PIN Z
    DIRECTION OUTPUT ;
    ANTENNADIFFAREA 1.008600 ;
    PORT
      LAYER Metal1 ;
        RECT 2.665 2.710 2.895 3.390 ;
        RECT 2.665 2.360 3.810 2.710 ;
        RECT 3.470 1.510 3.810 2.360 ;
        RECT 2.665 1.280 3.810 1.510 ;
        RECT 2.665 0.800 2.895 1.280 ;
    END
  END Z
  PIN VDD
    DIRECTION INOUT ;
    USE POWER ;
    SHAPE ABUTMENT ;
    PORT
      LAYER Metal1 ;
        RECT 0.000 3.620 4.480 4.220 ;
        RECT 1.360 3.050 1.700 3.620 ;
        RECT 3.685 3.050 3.915 3.620 ;
    END
  END VDD
  PIN VNW
    DIRECTION INOUT ;
    USE POWER ;
    PORT
      LAYER Nwell ;
        RECT -0.430 1.760 4.910 4.350 ;
    END
  END VNW
  PIN VPW
    DIRECTION INOUT ;
    USE GROUND ;
    PORT
      LAYER Pwell ;
        RECT -0.430 -0.430 4.910 1.760 ;
    END
  END VPW
  PIN VSS
    DIRECTION INOUT ;
    USE GROUND ;
    SHAPE ABUTMENT ;
    PORT
      LAYER Metal1 ;
        RECT 1.490 0.300 1.830 1.095 ;
        RECT 3.730 0.300 4.070 1.050 ;
        RECT 0.000 -0.300 4.480 0.300 ;
    END
  END VSS
  OBS
      LAYER Metal1 ;
        RECT 0.245 2.820 0.475 3.390 ;
        RECT 0.245 2.590 2.215 2.820 ;
        RECT 0.245 0.805 0.475 2.590 ;
        RECT 1.890 2.040 2.215 2.590 ;
        RECT 1.890 1.740 3.210 2.040 ;
  END
END gf180mcu_fd_sc_mcu7t5v0__clkbuf_2

#--------EOF---------

MACRO gf180mcu_fd_sc_mcu7t5v0__clkbuf_3
  CLASS core ;
  FOREIGN gf180mcu_fd_sc_mcu7t5v0__clkbuf_3 ;
  ORIGIN 0.000 0.000 ;
  SIZE 7.840 BY 3.920 ;
  SYMMETRY X Y ;
  SITE GF018hv5v_mcu_sc7 ;
  PIN I
    DIRECTION INPUT ;
    ANTENNAGATEAREA 1.183000 ;
    PORT
      LAYER Metal1 ;
        RECT 0.620 1.740 2.340 2.120 ;
    END
  END I
  PIN Z
    DIRECTION OUTPUT ;
    ANTENNADIFFAREA 1.986000 ;
    PORT
      LAYER Metal1 ;
        RECT 3.785 2.680 4.015 3.390 ;
        RECT 5.925 2.680 6.155 3.390 ;
        RECT 3.785 2.360 6.600 2.680 ;
        RECT 6.280 1.510 6.600 2.360 ;
        RECT 3.785 1.280 6.600 1.510 ;
        RECT 3.785 0.690 4.015 1.280 ;
        RECT 6.025 0.690 6.255 1.280 ;
    END
  END Z
  PIN VDD
    DIRECTION INOUT ;
    USE POWER ;
    SHAPE ABUTMENT ;
    PORT
      LAYER Metal1 ;
        RECT 0.000 3.620 7.840 4.220 ;
        RECT 0.245 3.200 0.475 3.620 ;
        RECT 2.385 3.160 2.615 3.620 ;
        RECT 4.805 3.050 5.035 3.620 ;
        RECT 7.045 2.730 7.275 3.620 ;
    END
  END VDD
  PIN VNW
    DIRECTION INOUT ;
    USE POWER ;
    PORT
      LAYER Nwell ;
        RECT -0.430 1.760 8.270 4.350 ;
    END
  END VNW
  PIN VPW
    DIRECTION INOUT ;
    USE GROUND ;
    PORT
      LAYER Pwell ;
        RECT -0.430 -0.430 8.270 1.760 ;
    END
  END VPW
  PIN VSS
    DIRECTION INOUT ;
    USE GROUND ;
    SHAPE ABUTMENT ;
    PORT
      LAYER Metal1 ;
        RECT 0.190 0.300 0.530 0.985 ;
        RECT 2.610 0.300 2.950 0.985 ;
        RECT 4.850 0.300 5.190 0.985 ;
        RECT 7.090 0.300 7.430 0.985 ;
        RECT 0.000 -0.300 7.840 0.300 ;
    END
  END VSS
  OBS
      LAYER Metal1 ;
        RECT 1.265 2.820 1.495 3.390 ;
        RECT 1.265 2.590 3.185 2.820 ;
        RECT 2.955 2.040 3.185 2.590 ;
        RECT 2.955 1.740 5.945 2.040 ;
        RECT 2.955 1.500 3.185 1.740 ;
        RECT 1.365 1.270 3.185 1.500 ;
        RECT 1.365 0.690 1.595 1.270 ;
  END
END gf180mcu_fd_sc_mcu7t5v0__clkbuf_3

#--------EOF---------

MACRO gf180mcu_fd_sc_mcu7t5v0__clkbuf_4
  CLASS core ;
  FOREIGN gf180mcu_fd_sc_mcu7t5v0__clkbuf_4 ;
  ORIGIN 0.000 0.000 ;
  SIZE 7.840 BY 3.920 ;
  SYMMETRY X Y ;
  SITE GF018hv5v_mcu_sc7 ;
  PIN I
    DIRECTION INPUT ;
    ANTENNAGATEAREA 1.183000 ;
    PORT
      LAYER Metal1 ;
        RECT 0.370 1.740 2.150 2.150 ;
    END
  END I
  PIN Z
    DIRECTION OUTPUT ;
    ANTENNADIFFAREA 1.986000 ;
    PORT
      LAYER Metal1 ;
        RECT 3.785 2.680 4.015 3.390 ;
        RECT 5.925 2.680 6.155 3.390 ;
        RECT 3.785 2.360 6.155 2.680 ;
        RECT 5.130 1.445 5.510 2.360 ;
        RECT 3.785 1.215 6.255 1.445 ;
        RECT 3.785 0.690 4.015 1.215 ;
        RECT 6.025 0.690 6.255 1.215 ;
    END
  END Z
  PIN VDD
    DIRECTION INOUT ;
    USE POWER ;
    SHAPE ABUTMENT ;
    PORT
      LAYER Metal1 ;
        RECT 0.000 3.620 7.840 4.220 ;
        RECT 0.245 3.230 0.475 3.620 ;
        RECT 2.385 3.160 2.615 3.620 ;
        RECT 4.805 3.050 5.035 3.620 ;
        RECT 7.045 2.760 7.275 3.620 ;
    END
  END VDD
  PIN VNW
    DIRECTION INOUT ;
    USE POWER ;
    PORT
      LAYER Nwell ;
        RECT -0.430 1.760 8.270 4.350 ;
    END
  END VNW
  PIN VPW
    DIRECTION INOUT ;
    USE GROUND ;
    PORT
      LAYER Pwell ;
        RECT -0.430 -0.430 8.270 1.760 ;
    END
  END VPW
  PIN VSS
    DIRECTION INOUT ;
    USE GROUND ;
    SHAPE ABUTMENT ;
    PORT
      LAYER Metal1 ;
        RECT 0.190 0.300 0.530 1.040 ;
        RECT 2.610 0.300 2.950 0.985 ;
        RECT 4.850 0.300 5.190 0.985 ;
        RECT 7.090 0.300 7.430 0.985 ;
        RECT 0.000 -0.300 7.840 0.300 ;
    END
  END VSS
  OBS
      LAYER Metal1 ;
        RECT 1.265 2.760 1.495 3.380 ;
        RECT 1.265 2.530 3.175 2.760 ;
        RECT 2.945 2.025 3.175 2.530 ;
        RECT 2.945 1.685 4.830 2.025 ;
        RECT 5.765 1.685 6.935 2.025 ;
        RECT 2.945 1.500 3.175 1.685 ;
        RECT 1.365 1.270 3.175 1.500 ;
        RECT 1.365 0.740 1.595 1.270 ;
  END
END gf180mcu_fd_sc_mcu7t5v0__clkbuf_4

#--------EOF---------

MACRO gf180mcu_fd_sc_mcu7t5v0__clkbuf_8
  CLASS core ;
  FOREIGN gf180mcu_fd_sc_mcu7t5v0__clkbuf_8 ;
  ORIGIN 0.000 0.000 ;
  SIZE 14.560 BY 3.920 ;
  SYMMETRY X Y ;
  SITE GF018hv5v_mcu_sc7 ;
  PIN I
    DIRECTION INPUT ;
    ANTENNAGATEAREA 2.369000 ;
    PORT
      LAYER Metal1 ;
        RECT 0.650 1.745 4.130 2.150 ;
    END
  END I
  PIN Z
    DIRECTION OUTPUT ;
    ANTENNADIFFAREA 4.408000 ;
    PORT
      LAYER Metal1 ;
        RECT 6.025 2.680 6.255 3.390 ;
        RECT 8.265 2.680 8.495 3.390 ;
        RECT 10.505 2.680 10.735 3.390 ;
        RECT 12.745 2.680 12.975 3.390 ;
        RECT 6.025 2.360 12.975 2.680 ;
        RECT 9.610 1.510 9.990 2.360 ;
        RECT 6.025 1.220 12.975 1.510 ;
        RECT 6.025 0.690 6.255 1.220 ;
        RECT 8.265 0.690 8.495 1.220 ;
        RECT 10.505 0.690 10.735 1.220 ;
        RECT 12.745 0.690 12.975 1.220 ;
    END
  END Z
  PIN VDD
    DIRECTION INOUT ;
    USE POWER ;
    SHAPE ABUTMENT ;
    PORT
      LAYER Metal1 ;
        RECT 0.000 3.620 14.560 4.220 ;
        RECT 0.245 3.230 0.475 3.620 ;
        RECT 2.485 3.050 2.715 3.620 ;
        RECT 4.905 3.230 5.135 3.620 ;
        RECT 7.145 3.050 7.375 3.620 ;
        RECT 9.385 3.050 9.615 3.620 ;
        RECT 11.625 3.050 11.855 3.620 ;
        RECT 13.865 2.760 14.095 3.620 ;
    END
  END VDD
  PIN VNW
    DIRECTION INOUT ;
    USE POWER ;
    PORT
      LAYER Nwell ;
        RECT -0.430 1.760 14.990 4.350 ;
    END
  END VNW
  PIN VPW
    DIRECTION INOUT ;
    USE GROUND ;
    PORT
      LAYER Pwell ;
        RECT -0.430 -0.430 14.990 1.760 ;
    END
  END VPW
  PIN VSS
    DIRECTION INOUT ;
    USE GROUND ;
    SHAPE ABUTMENT ;
    PORT
      LAYER Metal1 ;
        RECT 0.190 0.300 0.530 1.040 ;
        RECT 2.430 0.300 2.770 1.040 ;
        RECT 4.850 0.300 5.190 1.055 ;
        RECT 7.090 0.300 7.430 0.985 ;
        RECT 9.330 0.300 9.670 0.985 ;
        RECT 11.570 0.300 11.910 0.985 ;
        RECT 13.810 0.300 14.150 0.985 ;
        RECT 0.000 -0.300 14.560 0.300 ;
    END
  END VSS
  OBS
      LAYER Metal1 ;
        RECT 1.365 2.760 1.595 3.390 ;
        RECT 3.605 2.760 3.835 3.390 ;
        RECT 1.365 2.530 4.655 2.760 ;
        RECT 4.425 1.975 4.655 2.530 ;
        RECT 4.425 1.740 8.920 1.975 ;
        RECT 10.530 1.740 13.720 2.040 ;
        RECT 4.425 1.500 4.655 1.740 ;
        RECT 1.365 1.270 4.655 1.500 ;
        RECT 1.365 0.740 1.595 1.270 ;
        RECT 3.605 0.740 3.835 1.270 ;
  END
END gf180mcu_fd_sc_mcu7t5v0__clkbuf_8

#--------EOF---------

MACRO gf180mcu_fd_sc_mcu7t5v0__clkinv_1
  CLASS core ;
  FOREIGN gf180mcu_fd_sc_mcu7t5v0__clkinv_1 ;
  ORIGIN 0.000 0.000 ;
  SIZE 2.240 BY 3.920 ;
  SYMMETRY X Y ;
  SITE GF018hv5v_mcu_sc7 ;
  PIN I
    DIRECTION INPUT ;
    ANTENNAGATEAREA 0.898000 ;
    PORT
      LAYER Metal1 ;
        RECT 0.705 0.970 1.030 2.950 ;
    END
  END I
  PIN ZN
    DIRECTION OUTPUT ;
    ANTENNADIFFAREA 0.748000 ;
    PORT
      LAYER Metal1 ;
        RECT 1.260 0.600 1.595 3.370 ;
    END
  END ZN
  PIN VDD
    DIRECTION INOUT ;
    USE POWER ;
    SHAPE ABUTMENT ;
    PORT
      LAYER Metal1 ;
        RECT 0.000 3.620 2.240 4.220 ;
        RECT 0.245 2.480 0.475 3.620 ;
    END
  END VDD
  PIN VNW
    DIRECTION INOUT ;
    USE POWER ;
    PORT
      LAYER Nwell ;
        RECT -0.430 1.760 2.670 4.350 ;
    END
  END VNW
  PIN VPW
    DIRECTION INOUT ;
    USE GROUND ;
    PORT
      LAYER Pwell ;
        RECT -0.430 -0.430 2.670 1.760 ;
    END
  END VPW
  PIN VSS
    DIRECTION INOUT ;
    USE GROUND ;
    SHAPE ABUTMENT ;
    PORT
      LAYER Metal1 ;
        RECT 0.245 0.300 0.475 1.040 ;
        RECT 0.000 -0.300 2.240 0.300 ;
    END
  END VSS
END gf180mcu_fd_sc_mcu7t5v0__clkinv_1

#--------EOF---------

MACRO gf180mcu_fd_sc_mcu7t5v0__clkinv_2
  CLASS core ;
  FOREIGN gf180mcu_fd_sc_mcu7t5v0__clkinv_2 ;
  ORIGIN 0.000 0.000 ;
  SIZE 3.360 BY 3.920 ;
  SYMMETRY X Y ;
  SITE GF018hv5v_mcu_sc7 ;
  PIN I
    DIRECTION INPUT ;
    ANTENNAGATEAREA 1.796000 ;
    PORT
      LAYER Metal1 ;
        RECT 0.705 2.120 1.035 2.875 ;
        RECT 0.705 1.735 1.970 2.120 ;
        RECT 0.705 1.190 1.035 1.735 ;
    END
  END I
  PIN ZN
    DIRECTION OUTPUT ;
    ANTENNADIFFAREA 1.006000 ;
    PORT
      LAYER Metal1 ;
        RECT 1.265 2.735 1.495 3.380 ;
        RECT 1.265 2.360 2.710 2.735 ;
        RECT 2.330 1.505 2.710 2.360 ;
        RECT 1.365 1.270 2.710 1.505 ;
        RECT 1.365 0.680 1.595 1.270 ;
    END
  END ZN
  PIN VDD
    DIRECTION INOUT ;
    USE POWER ;
    SHAPE ABUTMENT ;
    PORT
      LAYER Metal1 ;
        RECT 0.000 3.620 3.360 4.220 ;
        RECT 0.245 2.530 0.475 3.620 ;
        RECT 2.330 2.965 2.670 3.620 ;
    END
  END VDD
  PIN VNW
    DIRECTION INOUT ;
    USE POWER ;
    PORT
      LAYER Nwell ;
        RECT -0.430 1.760 3.790 4.350 ;
    END
  END VNW
  PIN VPW
    DIRECTION INOUT ;
    USE GROUND ;
    PORT
      LAYER Pwell ;
        RECT -0.430 -0.430 3.790 1.760 ;
    END
  END VPW
  PIN VSS
    DIRECTION INOUT ;
    USE GROUND ;
    SHAPE ABUTMENT ;
    PORT
      LAYER Metal1 ;
        RECT 0.245 0.300 0.475 1.040 ;
        RECT 2.485 0.300 2.715 1.040 ;
        RECT 0.000 -0.300 3.360 0.300 ;
    END
  END VSS
END gf180mcu_fd_sc_mcu7t5v0__clkinv_2

#--------EOF---------

MACRO gf180mcu_fd_sc_mcu7t5v0__clkinv_3
  CLASS core ;
  FOREIGN gf180mcu_fd_sc_mcu7t5v0__clkinv_3 ;
  ORIGIN 0.000 0.000 ;
  SIZE 4.480 BY 3.920 ;
  SYMMETRY X Y ;
  SITE GF018hv5v_mcu_sc7 ;
  PIN I
    DIRECTION INPUT ;
    ANTENNAGATEAREA 2.694000 ;
    PORT
      LAYER Metal1 ;
        RECT 0.650 1.740 2.855 2.120 ;
    END
  END I
  PIN ZN
    DIRECTION OUTPUT ;
    ANTENNADIFFAREA 1.754000 ;
    PORT
      LAYER Metal1 ;
        RECT 1.265 2.735 1.495 3.380 ;
        RECT 3.450 2.735 3.835 3.380 ;
        RECT 1.265 2.360 3.835 2.735 ;
        RECT 3.460 1.505 3.835 2.360 ;
        RECT 1.365 1.270 3.835 1.505 ;
        RECT 1.365 0.700 1.595 1.270 ;
        RECT 3.450 0.650 3.835 1.270 ;
    END
  END ZN
  PIN VDD
    DIRECTION INOUT ;
    USE POWER ;
    SHAPE ABUTMENT ;
    PORT
      LAYER Metal1 ;
        RECT 0.000 3.620 4.480 4.220 ;
        RECT 0.245 2.550 0.475 3.620 ;
        RECT 2.330 2.965 2.670 3.620 ;
    END
  END VDD
  PIN VNW
    DIRECTION INOUT ;
    USE POWER ;
    PORT
      LAYER Nwell ;
        RECT -0.430 1.760 4.910 4.350 ;
    END
  END VNW
  PIN VPW
    DIRECTION INOUT ;
    USE GROUND ;
    PORT
      LAYER Pwell ;
        RECT -0.430 -0.430 4.910 1.760 ;
    END
  END VPW
  PIN VSS
    DIRECTION INOUT ;
    USE GROUND ;
    SHAPE ABUTMENT ;
    PORT
      LAYER Metal1 ;
        RECT 0.245 0.300 0.475 1.040 ;
        RECT 2.485 0.300 2.715 1.040 ;
        RECT 0.000 -0.300 4.480 0.300 ;
    END
  END VSS
END gf180mcu_fd_sc_mcu7t5v0__clkinv_3

#--------EOF---------

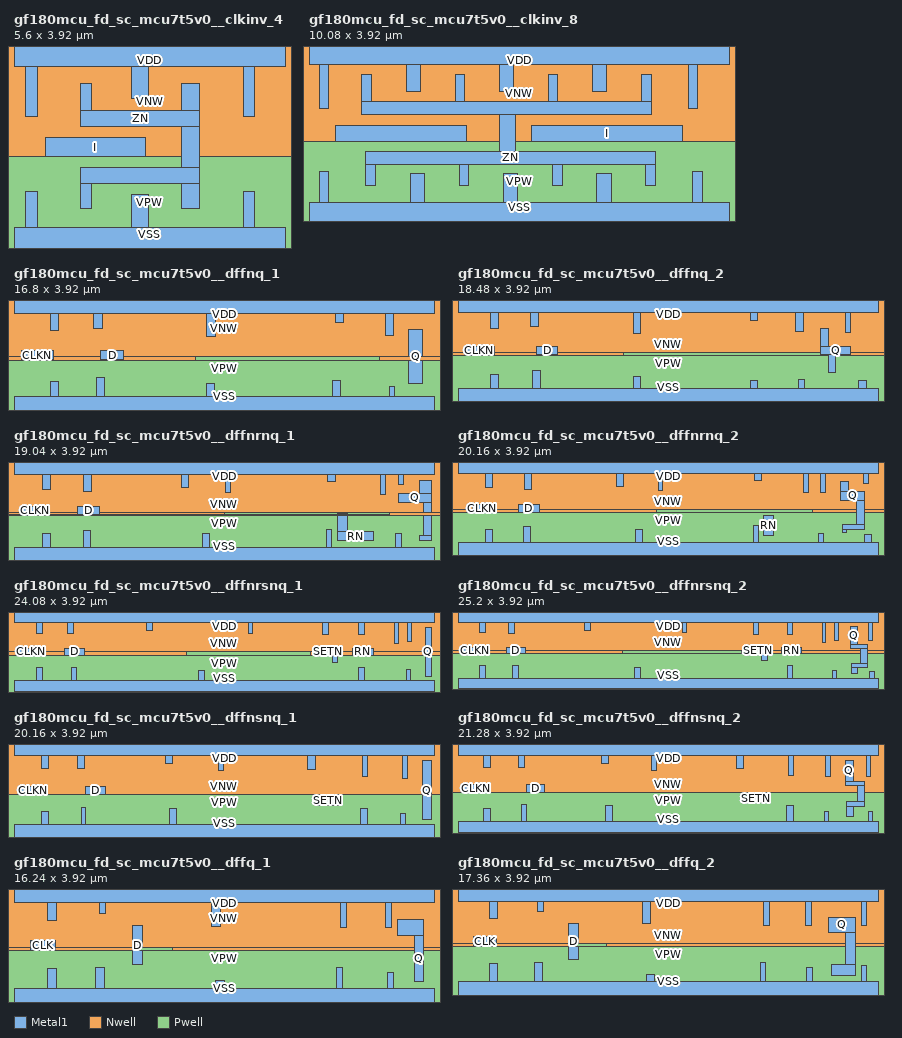
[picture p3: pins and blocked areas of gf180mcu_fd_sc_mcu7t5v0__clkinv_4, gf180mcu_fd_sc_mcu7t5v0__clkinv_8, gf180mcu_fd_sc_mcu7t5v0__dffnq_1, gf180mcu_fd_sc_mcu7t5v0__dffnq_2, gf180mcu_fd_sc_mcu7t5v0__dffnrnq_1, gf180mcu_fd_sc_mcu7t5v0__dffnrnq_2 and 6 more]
MACRO gf180mcu_fd_sc_mcu7t5v0__clkinv_4
  CLASS core ;
  FOREIGN gf180mcu_fd_sc_mcu7t5v0__clkinv_4 ;
  ORIGIN 0.000 0.000 ;
  SIZE 5.600 BY 3.920 ;
  SYMMETRY X Y ;
  SITE GF018hv5v_mcu_sc7 ;
  PIN I
    DIRECTION INPUT ;
    ANTENNAGATEAREA 3.592000 ;
    PORT
      LAYER Metal1 ;
        RECT 0.650 1.765 2.710 2.150 ;
    END
  END I
  PIN ZN
    DIRECTION OUTPUT ;
    ANTENNADIFFAREA 2.256000 ;
    PORT
      LAYER Metal1 ;
        RECT 1.365 2.705 1.595 3.270 ;
        RECT 3.450 2.705 3.835 3.270 ;
        RECT 1.365 2.385 3.835 2.705 ;
        RECT 3.450 1.535 3.835 2.385 ;
        RECT 1.365 1.215 3.835 1.535 ;
        RECT 1.365 0.700 1.595 1.215 ;
        RECT 3.450 0.700 3.835 1.215 ;
    END
  END ZN
  PIN VDD
    DIRECTION INOUT ;
    USE POWER ;
    SHAPE ABUTMENT ;
    PORT
      LAYER Metal1 ;
        RECT 0.000 3.620 5.600 4.220 ;
        RECT 0.245 2.590 0.475 3.620 ;
        RECT 2.430 2.965 2.770 3.620 ;
        RECT 4.725 2.590 4.955 3.620 ;
    END
  END VDD
  PIN VNW
    DIRECTION INOUT ;
    USE POWER ;
    PORT
      LAYER Nwell ;
        RECT -0.430 1.760 6.030 4.350 ;
    END
  END VNW
  PIN VPW
    DIRECTION INOUT ;
    USE GROUND ;
    PORT
      LAYER Pwell ;
        RECT -0.430 -0.430 6.030 1.760 ;
    END
  END VPW
  PIN VSS
    DIRECTION INOUT ;
    USE GROUND ;
    SHAPE ABUTMENT ;
    PORT
      LAYER Metal1 ;
        RECT 0.245 0.300 0.475 1.040 ;
        RECT 2.430 0.300 2.770 0.985 ;
        RECT 4.725 0.300 4.955 1.040 ;
        RECT 0.000 -0.300 5.600 0.300 ;
    END
  END VSS
END gf180mcu_fd_sc_mcu7t5v0__clkinv_4

#--------EOF---------

MACRO gf180mcu_fd_sc_mcu7t5v0__clkinv_8
  CLASS core ;
  FOREIGN gf180mcu_fd_sc_mcu7t5v0__clkinv_8 ;
  ORIGIN 0.000 0.000 ;
  SIZE 10.080 BY 3.920 ;
  SYMMETRY X Y ;
  SITE GF018hv5v_mcu_sc7 ;
  PIN I
    DIRECTION INPUT ;
    ANTENNAGATEAREA 7.184000 ;
    PORT
      LAYER Metal1 ;
        RECT 0.630 1.765 3.790 2.150 ;
        RECT 5.330 1.765 8.960 2.150 ;
    END
  END I
  PIN ZN
    DIRECTION OUTPUT ;
    ANTENNADIFFAREA 4.024000 ;
    PORT
      LAYER Metal1 ;
        RECT 1.265 2.730 1.495 3.380 ;
        RECT 3.505 2.730 3.735 3.380 ;
        RECT 1.265 2.725 3.735 2.730 ;
        RECT 5.745 2.725 5.975 3.380 ;
        RECT 7.985 2.725 8.215 3.380 ;
        RECT 1.265 2.410 8.215 2.725 ;
        RECT 4.570 1.535 4.950 2.410 ;
        RECT 1.365 1.215 8.315 1.535 ;
        RECT 1.365 0.700 1.595 1.215 ;
        RECT 3.605 0.700 3.835 1.215 ;
        RECT 5.845 0.700 6.075 1.215 ;
        RECT 8.085 0.700 8.315 1.215 ;
    END
  END ZN
  PIN VDD
    DIRECTION INOUT ;
    USE POWER ;
    SHAPE ABUTMENT ;
    PORT
      LAYER Metal1 ;
        RECT 0.000 3.620 10.080 4.220 ;
        RECT 0.245 2.550 0.475 3.620 ;
        RECT 2.330 2.965 2.670 3.620 ;
        RECT 4.570 2.965 4.910 3.620 ;
        RECT 6.810 2.965 7.150 3.620 ;
        RECT 9.105 2.550 9.335 3.620 ;
    END
  END VDD
  PIN VNW
    DIRECTION INOUT ;
    USE POWER ;
    PORT
      LAYER Nwell ;
        RECT -0.430 1.760 10.510 4.350 ;
    END
  END VNW
  PIN VPW
    DIRECTION INOUT ;
    USE GROUND ;
    PORT
      LAYER Pwell ;
        RECT -0.430 -0.430 10.510 1.760 ;
    END
  END VPW
  PIN VSS
    DIRECTION INOUT ;
    USE GROUND ;
    SHAPE ABUTMENT ;
    PORT
      LAYER Metal1 ;
        RECT 0.245 0.300 0.475 1.040 ;
        RECT 2.430 0.300 2.770 0.985 ;
        RECT 4.670 0.300 5.010 0.985 ;
        RECT 6.910 0.300 7.250 0.985 ;
        RECT 9.205 0.300 9.435 1.040 ;
        RECT 0.000 -0.300 10.080 0.300 ;
    END
  END VSS
END gf180mcu_fd_sc_mcu7t5v0__clkinv_8

#--------EOF---------

MACRO gf180mcu_fd_sc_mcu7t5v0__dffnq_1
  CLASS core ;
  FOREIGN gf180mcu_fd_sc_mcu7t5v0__dffnq_1 ;
  ORIGIN 0.000 0.000 ;
  SIZE 16.800 BY 3.920 ;
  SYMMETRY X Y ;
  SITE GF018hv5v_mcu_sc7 ;
  PIN D
    DIRECTION INPUT ;
    ANTENNAGATEAREA 0.463500 ;
    PORT
      LAYER Metal1 ;
        RECT 3.450 1.770 4.390 2.150 ;
    END
  END D
  PIN CLKN
    DIRECTION INPUT ;
    USE CLOCK ;
    ANTENNAGATEAREA 0.711500 ;
    PORT
      LAYER Metal1 ;
        RECT 0.280 1.770 1.590 2.130 ;
    END
  END CLKN
  PIN Q
    DIRECTION OUTPUT ;
    ANTENNADIFFAREA 0.858000 ;
    PORT
      LAYER Metal1 ;
        RECT 15.770 0.810 16.350 2.985 ;
    END
  END Q
  PIN VDD
    DIRECTION INOUT ;
    USE POWER ;
    SHAPE ABUTMENT ;
    PORT
      LAYER Metal1 ;
        RECT 0.000 3.620 16.800 4.220 ;
        RECT 1.440 2.930 1.780 3.620 ;
        RECT 3.180 3.005 3.520 3.620 ;
        RECT 7.705 2.700 8.045 3.620 ;
        RECT 12.850 3.280 13.190 3.620 ;
        RECT 14.845 2.755 15.185 3.620 ;
    END
  END VDD
  PIN VNW
    DIRECTION INOUT ;
    USE POWER ;
    PORT
      LAYER Nwell ;
        RECT -0.430 1.885 17.230 4.350 ;
        RECT -0.430 1.760 7.265 1.885 ;
        RECT 14.620 1.760 17.230 1.885 ;
    END
  END VNW
  PIN VPW
    DIRECTION INOUT ;
    USE GROUND ;
    PORT
      LAYER Pwell ;
        RECT 7.265 1.760 14.620 1.885 ;
        RECT -0.430 -0.430 17.230 1.760 ;
    END
  END VPW
  PIN VSS
    DIRECTION INOUT ;
    USE GROUND ;
    SHAPE ABUTMENT ;
    PORT
      LAYER Metal1 ;
        RECT 1.440 0.300 1.780 0.915 ;
        RECT 3.280 0.300 3.620 1.075 ;
        RECT 7.700 0.300 8.040 0.810 ;
        RECT 12.720 0.300 13.060 0.950 ;
        RECT 15.000 0.300 15.230 0.690 ;
        RECT 0.000 -0.300 16.800 0.300 ;
    END
  END VSS
  OBS
      LAYER Metal1 ;
        RECT 0.475 2.590 0.705 3.225 ;
        RECT 2.515 2.710 2.845 3.225 ;
        RECT 3.830 3.160 6.355 3.390 ;
        RECT 3.830 2.710 4.060 3.160 ;
        RECT 13.430 3.100 14.615 3.330 ;
        RECT 13.430 3.050 13.660 3.100 ;
        RECT 0.475 2.360 2.165 2.590 ;
        RECT 1.935 1.375 2.165 2.360 ;
        RECT 0.375 1.145 2.165 1.375 ;
        RECT 2.515 2.480 4.060 2.710 ;
        RECT 4.420 2.645 5.290 2.875 ;
        RECT 0.375 0.735 0.605 1.145 ;
        RECT 2.515 0.735 2.845 2.480 ;
        RECT 5.055 1.075 5.290 2.645 ;
        RECT 4.400 0.845 5.290 1.075 ;
        RECT 5.575 2.050 5.915 2.795 ;
        RECT 9.040 2.390 9.380 2.930 ;
        RECT 7.095 2.050 9.380 2.390 ;
        RECT 5.575 1.820 6.780 2.050 ;
        RECT 5.575 0.790 5.805 1.820 ;
        RECT 6.550 1.730 6.780 1.820 ;
        RECT 6.090 1.270 6.320 1.590 ;
        RECT 6.550 1.500 8.700 1.730 ;
        RECT 6.090 1.040 8.560 1.270 ;
        RECT 8.330 0.760 8.560 1.040 ;
        RECT 9.040 0.990 9.380 2.050 ;
        RECT 10.160 2.585 10.500 2.930 ;
        RECT 11.790 2.815 13.660 3.050 ;
        RECT 10.160 2.355 13.630 2.585 ;
        RECT 10.160 0.990 10.500 2.355 ;
        RECT 13.290 2.105 13.630 2.355 ;
        RECT 11.195 0.760 11.425 2.095 ;
        RECT 13.925 1.885 14.155 2.850 ;
        RECT 14.385 2.345 14.615 3.100 ;
        RECT 14.385 2.115 15.460 2.345 ;
        RECT 13.925 1.875 15.000 1.885 ;
        RECT 12.175 1.640 15.000 1.875 ;
        RECT 13.900 1.500 15.000 1.640 ;
        RECT 11.655 1.180 13.520 1.410 ;
        RECT 11.655 0.890 11.885 1.180 ;
        RECT 8.330 0.530 11.425 0.760 ;
        RECT 13.290 0.760 13.520 1.180 ;
        RECT 13.900 0.990 14.240 1.500 ;
        RECT 15.230 1.150 15.460 2.115 ;
        RECT 14.540 0.920 15.460 1.150 ;
        RECT 14.540 0.760 14.770 0.920 ;
        RECT 13.290 0.530 14.770 0.760 ;
  END
END gf180mcu_fd_sc_mcu7t5v0__dffnq_1

#--------EOF---------

MACRO gf180mcu_fd_sc_mcu7t5v0__dffnq_2
  CLASS core ;
  FOREIGN gf180mcu_fd_sc_mcu7t5v0__dffnq_2 ;
  ORIGIN 0.000 0.000 ;
  SIZE 18.480 BY 3.920 ;
  SYMMETRY X Y ;
  SITE GF018hv5v_mcu_sc7 ;
  PIN D
    DIRECTION INPUT ;
    ANTENNAGATEAREA 0.463500 ;
    PORT
      LAYER Metal1 ;
        RECT 3.450 1.770 4.390 2.150 ;
    END
  END D
  PIN CLKN
    DIRECTION INPUT ;
    USE CLOCK ;
    ANTENNAGATEAREA 0.711500 ;
    PORT
      LAYER Metal1 ;
        RECT 0.280 1.770 1.590 2.130 ;
    END
  END CLKN
  PIN Q
    DIRECTION OUTPUT ;
    ANTENNADIFFAREA 1.401600 ;
    PORT
      LAYER Metal1 ;
        RECT 15.965 2.150 16.315 2.930 ;
        RECT 15.965 1.770 17.270 2.150 ;
        RECT 16.285 0.990 16.625 1.770 ;
    END
  END Q
  PIN VDD
    DIRECTION INOUT ;
    USE POWER ;
    SHAPE ABUTMENT ;
    PORT
      LAYER Metal1 ;
        RECT 0.000 3.620 18.480 4.220 ;
        RECT 1.440 2.930 1.780 3.620 ;
        RECT 3.180 3.005 3.520 3.620 ;
        RECT 7.705 2.700 8.045 3.620 ;
        RECT 12.850 3.280 13.190 3.620 ;
        RECT 14.845 2.815 15.185 3.620 ;
        RECT 17.040 2.760 17.270 3.620 ;
    END
  END VDD
  PIN VNW
    DIRECTION INOUT ;
    USE POWER ;
    PORT
      LAYER Nwell ;
        RECT -0.430 1.885 18.910 4.350 ;
        RECT -0.430 1.760 7.265 1.885 ;
        RECT 17.275 1.760 18.910 1.885 ;
    END
  END VNW
  PIN VPW
    DIRECTION INOUT ;
    USE GROUND ;
    PORT
      LAYER Pwell ;
        RECT 7.265 1.760 17.275 1.885 ;
        RECT -0.430 -0.430 18.910 1.760 ;
    END
  END VPW
  PIN VSS
    DIRECTION INOUT ;
    USE GROUND ;
    SHAPE ABUTMENT ;
    PORT
      LAYER Metal1 ;
        RECT 1.440 0.300 1.780 0.915 ;
        RECT 3.280 0.300 3.620 1.075 ;
        RECT 7.700 0.300 8.040 0.810 ;
        RECT 12.850 0.300 13.190 0.635 ;
        RECT 15.000 0.300 15.230 0.690 ;
        RECT 17.625 0.300 17.965 0.635 ;
        RECT 0.000 -0.300 18.480 0.300 ;
    END
  END VSS
  OBS
      LAYER Metal1 ;
        RECT 0.475 2.590 0.705 3.225 ;
        RECT 2.515 2.710 2.845 3.225 ;
        RECT 3.830 3.160 6.355 3.390 ;
        RECT 3.830 2.710 4.060 3.160 ;
        RECT 13.430 3.100 14.615 3.330 ;
        RECT 13.430 3.050 13.660 3.100 ;
        RECT 0.475 2.360 2.165 2.590 ;
        RECT 1.935 1.375 2.165 2.360 ;
        RECT 0.375 1.145 2.165 1.375 ;
        RECT 2.515 2.480 4.060 2.710 ;
        RECT 4.420 2.645 5.290 2.875 ;
        RECT 0.375 0.735 0.605 1.145 ;
        RECT 2.515 0.735 2.845 2.480 ;
        RECT 5.055 1.075 5.290 2.645 ;
        RECT 4.400 0.845 5.290 1.075 ;
        RECT 5.575 2.050 5.915 2.795 ;
        RECT 9.040 2.390 9.380 2.930 ;
        RECT 7.095 2.050 9.380 2.390 ;
        RECT 5.575 1.820 6.780 2.050 ;
        RECT 5.575 0.790 5.805 1.820 ;
        RECT 6.550 1.730 6.780 1.820 ;
        RECT 6.090 1.270 6.320 1.590 ;
        RECT 6.550 1.500 8.700 1.730 ;
        RECT 6.090 1.040 8.560 1.270 ;
        RECT 8.330 0.760 8.560 1.040 ;
        RECT 9.040 0.990 9.380 2.050 ;
        RECT 10.160 2.585 10.500 2.930 ;
        RECT 11.790 2.815 13.660 3.050 ;
        RECT 10.160 2.355 13.575 2.585 ;
        RECT 10.160 0.990 10.500 2.355 ;
        RECT 13.345 2.050 13.575 2.355 ;
        RECT 13.925 2.055 14.155 2.850 ;
        RECT 14.385 2.515 14.615 3.100 ;
        RECT 14.385 2.285 15.645 2.515 ;
        RECT 11.170 0.760 11.510 2.040 ;
        RECT 13.925 1.730 15.075 2.055 ;
        RECT 12.410 1.715 15.075 1.730 ;
        RECT 12.410 1.495 14.310 1.715 ;
        RECT 8.330 0.530 11.510 0.760 ;
        RECT 11.745 0.865 13.650 1.095 ;
        RECT 13.970 0.990 14.310 1.495 ;
        RECT 15.415 1.150 15.645 2.285 ;
        RECT 11.745 0.675 11.975 0.865 ;
        RECT 13.420 0.760 13.650 0.865 ;
        RECT 14.540 0.920 15.645 1.150 ;
        RECT 14.540 0.760 14.770 0.920 ;
        RECT 13.420 0.530 14.770 0.760 ;
  END
END gf180mcu_fd_sc_mcu7t5v0__dffnq_2

#--------EOF---------

MACRO gf180mcu_fd_sc_mcu7t5v0__dffnrnq_1
  CLASS core ;
  FOREIGN gf180mcu_fd_sc_mcu7t5v0__dffnrnq_1 ;
  ORIGIN 0.000 0.000 ;
  SIZE 19.040 BY 3.920 ;
  SYMMETRY X Y ;
  SITE GF018hv5v_mcu_sc7 ;
  PIN D
    DIRECTION INPUT ;
    ANTENNAGATEAREA 0.614000 ;
    PORT
      LAYER Metal1 ;
        RECT 2.890 1.770 3.895 2.150 ;
    END
  END D
  PIN RN
    DIRECTION INPUT ;
    ANTENNAGATEAREA 1.318000 ;
    PORT
      LAYER Metal1 ;
        RECT 14.650 1.020 15.140 1.830 ;
        RECT 14.650 0.600 16.300 1.020 ;
    END
  END RN
  PIN CLKN
    DIRECTION INPUT ;
    USE CLOCK ;
    ANTENNAGATEAREA 0.675500 ;
    PORT
      LAYER Metal1 ;
        RECT 0.290 1.770 1.575 2.150 ;
    END
  END CLKN
  PIN Q
    DIRECTION OUTPUT ;
    ANTENNADIFFAREA 0.866800 ;
    PORT
      LAYER Metal1 ;
        RECT 18.365 2.765 18.920 3.320 ;
        RECT 17.450 2.330 18.920 2.765 ;
        RECT 18.570 0.830 18.920 2.330 ;
        RECT 18.380 0.600 18.920 0.830 ;
    END
  END Q
  PIN VDD
    DIRECTION INOUT ;
    USE POWER ;
    SHAPE ABUTMENT ;
    PORT
      LAYER Metal1 ;
        RECT 0.000 3.620 19.040 4.220 ;
        RECT 1.310 2.930 1.650 3.620 ;
        RECT 3.170 2.845 3.510 3.620 ;
        RECT 7.590 3.005 7.930 3.620 ;
        RECT 9.605 2.790 9.835 3.620 ;
        RECT 14.220 3.280 14.560 3.620 ;
        RECT 16.595 2.690 16.825 3.620 ;
        RECT 17.415 3.160 17.645 3.620 ;
    END
  END VDD
  PIN VNW
    DIRECTION INOUT ;
    USE POWER ;
    PORT
      LAYER Nwell ;
        RECT -0.430 1.885 19.470 4.350 ;
        RECT -0.430 1.770 9.525 1.885 ;
        RECT -0.430 1.760 2.960 1.770 ;
        RECT 17.040 1.760 19.470 1.885 ;
    END
  END VNW
  PIN VPW
    DIRECTION INOUT ;
    USE GROUND ;
    PORT
      LAYER Pwell ;
        RECT 9.525 1.770 17.040 1.885 ;
        RECT 2.960 1.760 17.040 1.770 ;
        RECT -0.430 -0.430 19.470 1.760 ;
    END
  END VPW
  PIN VSS
    DIRECTION INOUT ;
    USE GROUND ;
    SHAPE ABUTMENT ;
    PORT
      LAYER Metal1 ;
        RECT 1.310 0.300 1.650 0.915 ;
        RECT 3.150 0.300 3.490 1.075 ;
        RECT 8.530 0.300 8.870 0.915 ;
        RECT 14.175 0.300 14.405 1.130 ;
        RECT 17.315 0.300 17.545 0.930 ;
        RECT 0.000 -0.300 19.040 0.300 ;
    END
  END VSS
  OBS
      LAYER Metal1 ;
        RECT 3.785 3.160 5.015 3.390 ;
        RECT 0.345 2.700 0.575 2.805 ;
        RECT 0.345 2.465 2.035 2.700 ;
        RECT 1.805 1.375 2.035 2.465 ;
        RECT 0.245 1.145 2.035 1.375 ;
        RECT 2.385 2.610 2.615 2.805 ;
        RECT 3.785 2.610 4.015 3.160 ;
        RECT 2.385 2.380 4.015 2.610 ;
        RECT 0.245 0.630 0.475 1.145 ;
        RECT 2.385 0.970 2.615 2.380 ;
        RECT 2.385 0.630 2.715 0.970 ;
        RECT 4.245 0.790 4.555 2.800 ;
        RECT 4.785 1.555 5.015 3.160 ;
        RECT 11.875 3.160 13.900 3.390 ;
        RECT 5.265 2.315 5.495 2.800 ;
        RECT 6.285 2.775 6.515 3.115 ;
        RECT 8.160 2.830 9.170 3.060 ;
        RECT 8.160 2.775 8.390 2.830 ;
        RECT 6.285 2.545 8.390 2.775 ;
        RECT 8.620 2.315 10.330 2.470 ;
        RECT 5.265 2.240 10.330 2.315 ;
        RECT 5.265 2.085 8.850 2.240 ;
        RECT 5.265 0.790 5.675 2.085 ;
        RECT 10.625 2.010 10.855 3.130 ;
        RECT 11.875 2.405 12.105 3.160 ;
        RECT 13.670 3.050 13.900 3.160 ;
        RECT 14.790 3.160 16.365 3.390 ;
        RECT 14.790 3.050 15.020 3.160 ;
        RECT 10.060 1.855 10.855 2.010 ;
        RECT 6.930 1.780 10.855 1.855 ;
        RECT 11.645 2.065 12.105 2.405 ;
        RECT 6.930 1.625 10.430 1.780 ;
        RECT 6.170 1.395 6.515 1.565 ;
        RECT 6.170 1.165 9.330 1.395 ;
        RECT 9.100 0.760 9.330 1.165 ;
        RECT 10.090 0.990 10.430 1.625 ;
        RECT 11.025 0.760 11.255 1.620 ;
        RECT 11.645 0.990 11.995 2.065 ;
        RECT 12.395 0.760 12.625 2.525 ;
        RECT 12.980 0.820 13.320 2.930 ;
        RECT 13.670 2.815 15.020 3.050 ;
        RECT 15.450 2.470 15.790 2.930 ;
        RECT 13.560 2.235 15.790 2.470 ;
        RECT 15.560 1.735 15.790 2.235 ;
        RECT 16.135 2.375 16.365 3.160 ;
        RECT 16.135 2.035 16.385 2.375 ;
        RECT 15.560 1.505 18.040 1.735 ;
        RECT 16.595 0.790 16.825 1.505 ;
        RECT 9.100 0.530 12.625 0.760 ;
  END
END gf180mcu_fd_sc_mcu7t5v0__dffnrnq_1

#--------EOF---------

MACRO gf180mcu_fd_sc_mcu7t5v0__dffnrnq_2
  CLASS core ;
  FOREIGN gf180mcu_fd_sc_mcu7t5v0__dffnrnq_2 ;
  ORIGIN 0.000 0.000 ;
  SIZE 20.160 BY 3.920 ;
  SYMMETRY X Y ;
  SITE GF018hv5v_mcu_sc7 ;
  PIN D
    DIRECTION INPUT ;
    ANTENNAGATEAREA 0.614000 ;
    PORT
      LAYER Metal1 ;
        RECT 2.890 1.770 3.895 2.150 ;
    END
  END D
  PIN RN
    DIRECTION INPUT ;
    ANTENNAGATEAREA 1.393000 ;
    PORT
      LAYER Metal1 ;
        RECT 14.650 0.650 15.140 1.590 ;
    END
  END RN
  PIN CLKN
    DIRECTION INPUT ;
    USE CLOCK ;
    ANTENNAGATEAREA 0.675500 ;
    PORT
      LAYER Metal1 ;
        RECT 0.710 1.770 1.575 2.150 ;
    END
  END CLKN
  PIN Q
    DIRECTION OUTPUT ;
    ANTENNADIFFAREA 1.029600 ;
    PORT
      LAYER Metal1 ;
        RECT 18.380 2.765 18.720 3.235 ;
        RECT 18.380 2.330 19.510 2.765 ;
        RECT 19.130 1.175 19.510 2.330 ;
        RECT 18.435 0.945 19.510 1.175 ;
        RECT 18.435 0.790 18.665 0.945 ;
    END
  END Q
  PIN VDD
    DIRECTION INOUT ;
    USE POWER ;
    SHAPE ABUTMENT ;
    PORT
      LAYER Metal1 ;
        RECT 0.000 3.620 20.160 4.220 ;
        RECT 1.310 2.930 1.650 3.620 ;
        RECT 3.170 2.845 3.510 3.620 ;
        RECT 7.590 3.005 7.930 3.620 ;
        RECT 9.605 2.790 9.835 3.620 ;
        RECT 14.220 3.280 14.560 3.620 ;
        RECT 16.595 2.690 16.825 3.620 ;
        RECT 17.415 2.690 17.645 3.620 ;
        RECT 19.455 3.160 19.685 3.620 ;
    END
  END VDD
  PIN VNW
    DIRECTION INOUT ;
    USE POWER ;
    PORT
      LAYER Nwell ;
        RECT -0.430 1.885 20.590 4.350 ;
        RECT -0.430 1.770 9.525 1.885 ;
        RECT -0.430 1.760 2.960 1.770 ;
        RECT 17.020 1.760 20.590 1.885 ;
    END
  END VNW
  PIN VPW
    DIRECTION INOUT ;
    USE GROUND ;
    PORT
      LAYER Pwell ;
        RECT 9.525 1.770 17.020 1.885 ;
        RECT 2.960 1.760 17.020 1.770 ;
        RECT -0.430 -0.430 20.590 1.760 ;
    END
  END VPW
  PIN VSS
    DIRECTION INOUT ;
    USE GROUND ;
    SHAPE ABUTMENT ;
    PORT
      LAYER Metal1 ;
        RECT 1.310 0.300 1.650 0.915 ;
        RECT 3.150 0.300 3.490 1.075 ;
        RECT 8.530 0.300 8.870 0.915 ;
        RECT 14.175 0.300 14.405 1.130 ;
        RECT 17.315 0.300 17.545 0.765 ;
        RECT 19.500 0.300 19.840 0.715 ;
        RECT 0.000 -0.300 20.160 0.300 ;
    END
  END VSS
  OBS
      LAYER Metal1 ;
        RECT 3.785 3.160 5.015 3.390 ;
        RECT 0.345 2.700 0.575 2.805 ;
        RECT 0.345 2.465 2.035 2.700 ;
        RECT 1.805 1.375 2.035 2.465 ;
        RECT 0.245 1.145 2.035 1.375 ;
        RECT 2.385 2.610 2.615 2.805 ;
        RECT 3.785 2.610 4.015 3.160 ;
        RECT 2.385 2.380 4.015 2.610 ;
        RECT 0.245 0.630 0.475 1.145 ;
        RECT 2.385 0.970 2.615 2.380 ;
        RECT 2.385 0.630 2.715 0.970 ;
        RECT 4.245 0.790 4.555 2.800 ;
        RECT 4.785 1.555 5.015 3.160 ;
        RECT 11.875 3.160 13.900 3.390 ;
        RECT 5.265 2.315 5.495 2.800 ;
        RECT 6.285 2.775 6.515 3.115 ;
        RECT 8.160 2.830 9.170 3.060 ;
        RECT 8.160 2.775 8.390 2.830 ;
        RECT 6.285 2.545 8.390 2.775 ;
        RECT 8.620 2.315 10.330 2.470 ;
        RECT 5.265 2.240 10.330 2.315 ;
        RECT 5.265 2.085 8.850 2.240 ;
        RECT 5.265 0.790 5.675 2.085 ;
        RECT 10.625 2.010 10.855 3.130 ;
        RECT 11.875 2.405 12.105 3.160 ;
        RECT 13.670 3.050 13.900 3.160 ;
        RECT 14.790 3.155 16.365 3.390 ;
        RECT 14.790 3.050 15.020 3.155 ;
        RECT 10.060 1.855 10.855 2.010 ;
        RECT 6.930 1.780 10.855 1.855 ;
        RECT 11.645 2.065 12.105 2.405 ;
        RECT 6.930 1.625 10.430 1.780 ;
        RECT 6.170 1.395 6.515 1.565 ;
        RECT 6.170 1.165 9.330 1.395 ;
        RECT 9.100 0.760 9.330 1.165 ;
        RECT 10.090 0.990 10.430 1.625 ;
        RECT 11.025 0.760 11.255 1.620 ;
        RECT 11.645 0.990 11.995 2.065 ;
        RECT 12.395 0.760 12.625 2.525 ;
        RECT 12.980 0.820 13.320 2.930 ;
        RECT 13.670 2.815 15.020 3.050 ;
        RECT 15.450 2.470 15.790 2.870 ;
        RECT 13.560 2.235 15.790 2.470 ;
        RECT 13.560 1.770 13.900 2.235 ;
        RECT 15.560 1.735 15.790 2.235 ;
        RECT 16.135 2.375 16.365 3.155 ;
        RECT 16.135 2.035 16.385 2.375 ;
        RECT 15.560 1.505 18.610 1.735 ;
        RECT 9.100 0.530 12.625 0.760 ;
        RECT 16.595 0.740 16.825 1.505 ;
  END
END gf180mcu_fd_sc_mcu7t5v0__dffnrnq_2

#--------EOF---------

MACRO gf180mcu_fd_sc_mcu7t5v0__dffnrsnq_1
  CLASS core ;
  FOREIGN gf180mcu_fd_sc_mcu7t5v0__dffnrsnq_1 ;
  ORIGIN 0.000 0.000 ;
  SIZE 24.080 BY 3.920 ;
  SYMMETRY X Y ;
  SITE GF018hv5v_mcu_sc7 ;
  PIN D
    DIRECTION INPUT ;
    ANTENNAGATEAREA 0.433000 ;
    PORT
      LAYER Metal1 ;
        RECT 2.890 1.770 4.050 2.150 ;
    END
  END D
  PIN RN
    DIRECTION INPUT ;
    ANTENNAGATEAREA 1.284000 ;
    PORT
      LAYER Metal1 ;
        RECT 19.380 1.770 20.630 2.150 ;
    END
  END RN
  PIN SETN
    DIRECTION INPUT ;
    ANTENNAGATEAREA 1.149500 ;
    PORT
      LAYER Metal1 ;
        RECT 17.450 1.770 18.550 2.150 ;
        RECT 18.280 1.320 18.550 1.770 ;
    END
  END SETN
  PIN CLKN
    DIRECTION INPUT ;
    USE CLOCK ;
    ANTENNAGATEAREA 0.675500 ;
    PORT
      LAYER Metal1 ;
        RECT 0.280 1.770 1.590 2.150 ;
    END
  END CLKN
  PIN Q
    DIRECTION OUTPUT ;
    ANTENNADIFFAREA 0.895400 ;
    PORT
      LAYER Metal1 ;
        RECT 23.585 0.550 23.960 3.380 ;
    END
  END Q
  PIN VDD
    DIRECTION INOUT ;
    USE POWER ;
    SHAPE ABUTMENT ;
    PORT
      LAYER Metal1 ;
        RECT 0.000 3.620 24.080 4.220 ;
        RECT 1.310 3.005 1.650 3.620 ;
        RECT 3.050 3.000 3.390 3.620 ;
        RECT 7.585 3.165 7.930 3.620 ;
        RECT 13.450 3.035 13.680 3.620 ;
        RECT 17.705 2.940 18.045 3.620 ;
        RECT 19.745 2.940 20.085 3.620 ;
        RECT 21.840 2.415 22.070 3.620 ;
        RECT 22.580 2.565 22.810 3.620 ;
    END
  END VDD
  PIN VNW
    DIRECTION INOUT ;
    USE POWER ;
    PORT
      LAYER Nwell ;
        RECT -0.430 1.980 24.510 4.350 ;
        RECT -0.430 1.760 9.885 1.980 ;
        RECT 17.020 1.760 24.510 1.980 ;
    END
  END VNW
  PIN VPW
    DIRECTION INOUT ;
    USE GROUND ;
    PORT
      LAYER Pwell ;
        RECT 9.885 1.760 17.020 1.980 ;
        RECT -0.430 -0.430 24.510 1.760 ;
    END
  END VPW
  PIN VSS
    DIRECTION INOUT ;
    USE GROUND ;
    SHAPE ABUTMENT ;
    PORT
      LAYER Metal1 ;
        RECT 1.310 0.300 1.650 1.050 ;
        RECT 3.270 0.300 3.610 1.075 ;
        RECT 10.580 0.300 10.920 0.915 ;
        RECT 19.745 0.300 20.085 1.075 ;
        RECT 22.480 0.300 22.710 0.930 ;
        RECT 0.000 -0.300 24.080 0.300 ;
    END
  END VSS
  OBS
      LAYER Metal1 ;
        RECT 0.345 2.670 0.575 3.300 ;
        RECT 2.385 2.770 2.615 3.300 ;
        RECT 3.785 3.105 7.095 3.335 ;
        RECT 3.785 2.770 4.015 3.105 ;
        RECT 6.865 2.935 7.095 3.105 ;
        RECT 8.280 3.160 13.220 3.390 ;
        RECT 8.280 2.935 8.510 3.160 ;
        RECT 0.345 2.435 2.055 2.670 ;
        RECT 1.825 1.510 2.055 2.435 ;
        RECT 0.245 1.280 2.055 1.510 ;
        RECT 2.385 2.540 4.015 2.770 ;
        RECT 0.245 0.810 0.475 1.280 ;
        RECT 2.385 1.150 2.615 2.540 ;
        RECT 2.385 0.810 2.715 1.150 ;
        RECT 4.290 0.845 4.730 2.830 ;
        RECT 5.310 2.015 5.650 2.830 ;
        RECT 6.405 2.475 6.635 2.870 ;
        RECT 6.865 2.705 8.510 2.935 ;
        RECT 10.510 2.815 10.850 2.875 ;
        RECT 8.740 2.585 10.850 2.815 ;
        RECT 11.790 2.645 12.760 2.875 ;
        RECT 8.740 2.475 8.970 2.585 ;
        RECT 6.405 2.245 8.970 2.475 ;
        RECT 12.530 2.345 12.760 2.645 ;
        RECT 12.990 2.805 13.220 3.160 ;
        RECT 14.175 3.160 15.480 3.390 ;
        RECT 14.175 2.805 14.405 3.160 ;
        RECT 12.990 2.575 14.405 2.805 ;
        RECT 14.635 2.345 14.975 2.875 ;
        RECT 9.200 2.070 12.300 2.300 ;
        RECT 12.530 2.125 14.975 2.345 ;
        RECT 12.530 2.115 14.750 2.125 ;
        RECT 9.200 2.015 9.430 2.070 ;
        RECT 5.310 1.785 9.430 2.015 ;
        RECT 5.565 0.790 5.795 1.785 ;
        RECT 9.660 1.605 11.840 1.835 ;
        RECT 9.660 1.555 9.890 1.605 ;
        RECT 6.135 1.020 6.475 1.555 ;
        RECT 7.030 1.325 9.890 1.555 ;
        RECT 10.120 1.145 11.380 1.375 ;
        RECT 10.120 1.020 10.350 1.145 ;
        RECT 6.135 0.790 10.350 1.020 ;
        RECT 11.150 0.760 11.380 1.145 ;
        RECT 11.610 1.315 11.840 1.605 ;
        RECT 12.070 1.775 12.300 2.070 ;
        RECT 12.070 1.545 12.470 1.775 ;
        RECT 14.465 1.315 14.750 2.115 ;
        RECT 15.250 2.070 15.480 3.160 ;
        RECT 15.710 3.160 17.475 3.390 ;
        RECT 15.710 1.315 15.940 3.160 ;
        RECT 16.675 1.370 17.015 2.895 ;
        RECT 17.245 2.710 17.475 3.160 ;
        RECT 18.275 3.085 19.470 3.320 ;
        RECT 18.275 2.710 18.505 3.085 ;
        RECT 17.245 2.475 18.505 2.710 ;
        RECT 11.610 1.085 14.750 1.315 ;
        RECT 14.980 1.085 15.940 1.315 ;
        RECT 16.170 1.315 17.015 1.370 ;
        RECT 16.170 1.085 17.925 1.315 ;
        RECT 16.170 1.030 16.455 1.085 ;
        RECT 17.640 1.075 17.925 1.085 ;
        RECT 18.780 1.075 19.010 2.855 ;
        RECT 19.240 2.710 19.470 3.085 ;
        RECT 20.315 3.085 21.610 3.320 ;
        RECT 20.315 2.710 20.545 3.085 ;
        RECT 19.240 2.480 20.545 2.710 ;
        RECT 20.820 2.515 21.150 2.855 ;
        RECT 20.920 1.560 21.150 2.515 ;
        RECT 21.380 1.910 21.610 3.085 ;
        RECT 20.920 1.540 23.250 1.560 ;
        RECT 19.305 1.330 23.250 1.540 ;
        RECT 19.305 1.310 21.990 1.330 ;
        RECT 14.430 0.760 14.770 0.855 ;
        RECT 16.775 0.760 17.115 0.855 ;
        RECT 17.640 0.790 19.010 1.075 ;
        RECT 21.760 0.790 21.990 1.310 ;
        RECT 11.150 0.530 17.115 0.760 ;
  END
END gf180mcu_fd_sc_mcu7t5v0__dffnrsnq_1

#--------EOF---------

MACRO gf180mcu_fd_sc_mcu7t5v0__dffnrsnq_2
  CLASS core ;
  FOREIGN gf180mcu_fd_sc_mcu7t5v0__dffnrsnq_2 ;
  ORIGIN 0.000 0.000 ;
  SIZE 25.200 BY 3.920 ;
  SYMMETRY X Y ;
  SITE GF018hv5v_mcu_sc7 ;
  PIN D
    DIRECTION INPUT ;
    ANTENNAGATEAREA 0.433000 ;
    PORT
      LAYER Metal1 ;
        RECT 2.890 1.770 4.050 2.150 ;
    END
  END D
  PIN RN
    DIRECTION INPUT ;
    ANTENNAGATEAREA 1.284000 ;
    PORT
      LAYER Metal1 ;
        RECT 19.380 1.770 20.630 2.150 ;
    END
  END RN
  PIN SETN
    DIRECTION INPUT ;
    ANTENNAGATEAREA 1.149500 ;
    PORT
      LAYER Metal1 ;
        RECT 17.450 1.770 18.540 2.150 ;
        RECT 18.225 1.340 18.540 1.770 ;
    END
  END SETN
  PIN CLKN
    DIRECTION INPUT ;
    USE CLOCK ;
    ANTENNAGATEAREA 0.675500 ;
    PORT
      LAYER Metal1 ;
        RECT 0.280 1.770 1.590 2.150 ;
    END
  END CLKN
  PIN Q
    DIRECTION OUTPUT ;
    ANTENNADIFFAREA 1.058200 ;
    PORT
      LAYER Metal1 ;
        RECT 23.545 2.320 23.980 3.380 ;
        RECT 23.545 2.070 24.550 2.320 ;
        RECT 24.170 1.170 24.550 2.070 ;
        RECT 23.600 0.940 24.550 1.170 ;
        RECT 23.600 0.550 23.980 0.940 ;
    END
  END Q
  PIN VDD
    DIRECTION INOUT ;
    USE POWER ;
    SHAPE ABUTMENT ;
    PORT
      LAYER Metal1 ;
        RECT 0.000 3.620 25.200 4.220 ;
        RECT 1.310 3.005 1.650 3.620 ;
        RECT 3.050 3.000 3.390 3.620 ;
        RECT 7.585 3.165 7.930 3.620 ;
        RECT 13.450 3.035 13.680 3.620 ;
        RECT 17.705 2.940 18.045 3.620 ;
        RECT 19.745 2.940 20.085 3.620 ;
        RECT 21.840 2.415 22.070 3.620 ;
        RECT 22.580 2.570 22.810 3.620 ;
        RECT 24.620 2.570 24.850 3.620 ;
    END
  END VDD
  PIN VNW
    DIRECTION INOUT ;
    USE POWER ;
    PORT
      LAYER Nwell ;
        RECT -0.430 1.980 25.630 4.350 ;
        RECT -0.430 1.760 9.885 1.980 ;
        RECT 17.020 1.760 25.630 1.980 ;
    END
  END VNW
  PIN VPW
    DIRECTION INOUT ;
    USE GROUND ;
    PORT
      LAYER Pwell ;
        RECT 9.885 1.760 17.020 1.980 ;
        RECT -0.430 -0.430 25.630 1.760 ;
    END
  END VPW
  PIN VSS
    DIRECTION INOUT ;
    USE GROUND ;
    SHAPE ABUTMENT ;
    PORT
      LAYER Metal1 ;
        RECT 1.310 0.300 1.650 1.050 ;
        RECT 3.270 0.300 3.610 1.075 ;
        RECT 10.580 0.300 10.920 0.915 ;
        RECT 19.745 0.300 20.085 1.075 ;
        RECT 22.480 0.300 22.710 0.765 ;
        RECT 24.665 0.300 25.005 0.710 ;
        RECT 0.000 -0.300 25.200 0.300 ;
    END
  END VSS
  OBS
      LAYER Metal1 ;
        RECT 0.345 2.670 0.575 3.300 ;
        RECT 2.385 2.770 2.615 3.300 ;
        RECT 3.785 3.105 7.095 3.335 ;
        RECT 3.785 2.770 4.015 3.105 ;
        RECT 6.865 2.935 7.095 3.105 ;
        RECT 8.280 3.160 13.220 3.390 ;
        RECT 8.280 2.935 8.510 3.160 ;
        RECT 0.345 2.435 2.055 2.670 ;
        RECT 1.825 1.510 2.055 2.435 ;
        RECT 0.245 1.280 2.055 1.510 ;
        RECT 2.385 2.540 4.015 2.770 ;
        RECT 0.245 0.810 0.475 1.280 ;
        RECT 2.385 1.150 2.615 2.540 ;
        RECT 2.385 0.810 2.715 1.150 ;
        RECT 4.290 0.845 4.730 2.830 ;
        RECT 5.310 2.015 5.650 2.830 ;
        RECT 6.405 2.475 6.635 2.870 ;
        RECT 6.865 2.705 8.510 2.935 ;
        RECT 10.510 2.815 10.850 2.875 ;
        RECT 8.740 2.585 10.850 2.815 ;
        RECT 11.790 2.645 12.760 2.875 ;
        RECT 8.740 2.475 8.970 2.585 ;
        RECT 6.405 2.245 8.970 2.475 ;
        RECT 12.530 2.345 12.760 2.645 ;
        RECT 12.990 2.805 13.220 3.160 ;
        RECT 14.175 3.160 15.480 3.390 ;
        RECT 14.175 2.805 14.405 3.160 ;
        RECT 12.990 2.575 14.405 2.805 ;
        RECT 14.635 2.345 14.975 2.875 ;
        RECT 9.200 2.070 12.300 2.300 ;
        RECT 12.530 2.125 14.975 2.345 ;
        RECT 12.530 2.115 14.750 2.125 ;
        RECT 9.200 2.015 9.430 2.070 ;
        RECT 5.310 1.785 9.430 2.015 ;
        RECT 5.565 0.790 5.795 1.785 ;
        RECT 9.660 1.605 11.840 1.835 ;
        RECT 9.660 1.555 9.890 1.605 ;
        RECT 6.135 1.020 6.475 1.555 ;
        RECT 7.030 1.325 9.890 1.555 ;
        RECT 10.120 1.145 11.380 1.375 ;
        RECT 10.120 1.020 10.350 1.145 ;
        RECT 6.135 0.790 10.350 1.020 ;
        RECT 11.150 0.760 11.380 1.145 ;
        RECT 11.610 1.315 11.840 1.605 ;
        RECT 12.070 1.775 12.300 2.070 ;
        RECT 12.070 1.545 12.470 1.775 ;
        RECT 14.465 1.315 14.750 2.115 ;
        RECT 15.250 2.070 15.480 3.160 ;
        RECT 15.710 3.160 17.475 3.390 ;
        RECT 15.710 1.315 15.940 3.160 ;
        RECT 16.675 1.370 17.015 2.895 ;
        RECT 17.245 2.710 17.475 3.160 ;
        RECT 18.275 3.085 19.470 3.320 ;
        RECT 18.275 2.710 18.505 3.085 ;
        RECT 17.245 2.475 18.505 2.710 ;
        RECT 11.610 1.085 14.750 1.315 ;
        RECT 14.980 1.085 15.940 1.315 ;
        RECT 16.170 1.315 17.015 1.370 ;
        RECT 16.170 1.085 17.995 1.315 ;
        RECT 16.170 1.030 16.455 1.085 ;
        RECT 17.710 1.075 17.995 1.085 ;
        RECT 18.780 1.075 19.010 2.855 ;
        RECT 19.240 2.710 19.470 3.085 ;
        RECT 20.315 3.085 21.610 3.320 ;
        RECT 20.315 2.710 20.545 3.085 ;
        RECT 19.240 2.480 20.545 2.710 ;
        RECT 20.820 2.515 21.150 2.855 ;
        RECT 20.920 1.560 21.150 2.515 ;
        RECT 21.380 1.910 21.610 3.085 ;
        RECT 22.965 1.560 23.720 1.820 ;
        RECT 20.920 1.540 23.720 1.560 ;
        RECT 19.305 1.475 23.720 1.540 ;
        RECT 19.305 1.330 23.305 1.475 ;
        RECT 19.305 1.310 21.990 1.330 ;
        RECT 14.430 0.760 14.770 0.855 ;
        RECT 16.775 0.760 17.115 0.855 ;
        RECT 17.710 0.790 19.010 1.075 ;
        RECT 21.760 0.790 21.990 1.310 ;
        RECT 11.150 0.530 17.115 0.760 ;
  END
END gf180mcu_fd_sc_mcu7t5v0__dffnrsnq_2

#--------EOF---------

MACRO gf180mcu_fd_sc_mcu7t5v0__dffnsnq_1
  CLASS core ;
  FOREIGN gf180mcu_fd_sc_mcu7t5v0__dffnsnq_1 ;
  ORIGIN 0.000 0.000 ;
  SIZE 20.160 BY 3.920 ;
  SYMMETRY X Y ;
  SITE GF018hv5v_mcu_sc7 ;
  PIN D
    DIRECTION INPUT ;
    ANTENNAGATEAREA 0.530500 ;
    PORT
      LAYER Metal1 ;
        RECT 3.450 1.770 4.390 2.150 ;
    END
  END D
  PIN SETN
    DIRECTION INPUT ;
    ANTENNAGATEAREA 1.156500 ;
    PORT
      LAYER Metal1 ;
        RECT 14.560 1.220 15.590 1.670 ;
    END
  END SETN
  PIN CLKN
    DIRECTION INPUT ;
    USE CLOCK ;
    ANTENNAGATEAREA 0.794000 ;
    PORT
      LAYER Metal1 ;
        RECT 0.280 1.770 1.590 2.130 ;
    END
  END CLKN
  PIN Q
    DIRECTION OUTPUT ;
    ANTENNADIFFAREA 0.893200 ;
    PORT
      LAYER Metal1 ;
        RECT 19.610 0.550 20.040 3.380 ;
    END
  END Q
  PIN VDD
    DIRECTION INOUT ;
    USE POWER ;
    SHAPE ABUTMENT ;
    PORT
      LAYER Metal1 ;
        RECT 0.000 3.620 20.160 4.220 ;
        RECT 1.310 3.005 1.650 3.620 ;
        RECT 3.050 3.005 3.390 3.620 ;
        RECT 7.290 3.240 7.630 3.620 ;
        RECT 9.825 2.885 10.055 3.620 ;
        RECT 14.110 2.945 14.450 3.620 ;
        RECT 16.745 2.600 16.975 3.620 ;
        RECT 18.645 2.530 18.875 3.620 ;
    END
  END VDD
  PIN VNW
    DIRECTION INOUT ;
    USE POWER ;
    PORT
      LAYER Nwell ;
        RECT -0.430 1.760 20.590 4.350 ;
    END
  END VNW
  PIN VPW
    DIRECTION INOUT ;
    USE GROUND ;
    PORT
      LAYER Pwell ;
        RECT -0.430 -0.430 20.590 1.760 ;
    END
  END VPW
  PIN VSS
    DIRECTION INOUT ;
    USE GROUND ;
    SHAPE ABUTMENT ;
    PORT
      LAYER Metal1 ;
        RECT 1.310 0.300 1.650 0.935 ;
        RECT 3.225 0.300 3.455 1.145 ;
        RECT 7.470 0.300 7.810 1.090 ;
        RECT 16.650 0.300 16.990 1.080 ;
        RECT 18.545 0.300 18.775 0.835 ;
        RECT 0.000 -0.300 20.160 0.300 ;
    END
  END VSS
  OBS
      LAYER Metal1 ;
        RECT 0.345 2.595 0.575 3.300 ;
        RECT 2.385 2.775 2.715 3.300 ;
        RECT 3.620 3.120 6.230 3.360 ;
        RECT 3.620 2.775 3.850 3.120 ;
        RECT 0.345 2.360 2.155 2.595 ;
        RECT 1.925 1.395 2.155 2.360 ;
        RECT 0.245 1.165 2.155 1.395 ;
        RECT 2.385 2.545 3.850 2.775 ;
        RECT 5.940 2.880 6.230 3.120 ;
        RECT 7.975 2.885 9.330 3.115 ;
        RECT 7.975 2.880 8.205 2.885 ;
        RECT 0.245 0.660 0.475 1.165 ;
        RECT 2.385 0.660 2.715 2.545 ;
        RECT 4.290 2.520 5.090 2.750 ;
        RECT 4.860 1.095 5.090 2.520 ;
        RECT 4.290 0.865 5.090 1.095 ;
        RECT 5.365 1.630 5.595 2.710 ;
        RECT 5.940 2.650 8.205 2.880 ;
        RECT 9.100 2.655 9.330 2.885 ;
        RECT 10.285 3.065 11.670 3.295 ;
        RECT 10.285 2.655 10.515 3.065 ;
        RECT 12.145 2.940 13.855 3.175 ;
        RECT 8.530 2.195 8.870 2.655 ;
        RECT 9.100 2.425 10.515 2.655 ;
        RECT 10.890 2.195 11.230 2.655 ;
        RECT 6.630 1.965 11.230 2.195 ;
        RECT 9.825 1.930 11.230 1.965 ;
        RECT 5.365 1.395 8.290 1.630 ;
        RECT 5.365 0.865 5.850 1.395 ;
        RECT 9.825 0.810 10.055 1.930 ;
        RECT 12.145 1.585 12.375 2.940 ;
        RECT 13.625 2.715 13.855 2.940 ;
        RECT 14.755 2.885 16.380 3.120 ;
        RECT 14.755 2.715 14.985 2.885 ;
        RECT 10.945 1.355 12.375 1.585 ;
        RECT 13.165 2.195 13.395 2.710 ;
        RECT 13.625 2.480 14.985 2.715 ;
        RECT 15.380 2.195 15.730 2.655 ;
        RECT 13.165 1.965 15.730 2.195 ;
        RECT 16.150 2.195 16.380 2.885 ;
        RECT 10.945 0.810 11.175 1.355 ;
        RECT 13.165 1.135 13.395 1.965 ;
        RECT 16.150 1.960 17.470 2.195 ;
        RECT 17.765 1.895 17.995 2.875 ;
        RECT 17.765 1.615 19.215 1.895 ;
        RECT 15.990 1.545 19.215 1.615 ;
        RECT 15.990 1.385 18.055 1.545 ;
        RECT 13.165 1.075 14.295 1.135 ;
        RECT 12.010 0.795 14.295 1.075 ;
        RECT 17.825 0.795 18.055 1.385 ;
  END
END gf180mcu_fd_sc_mcu7t5v0__dffnsnq_1

#--------EOF---------

MACRO gf180mcu_fd_sc_mcu7t5v0__dffnsnq_2
  CLASS core ;
  FOREIGN gf180mcu_fd_sc_mcu7t5v0__dffnsnq_2 ;
  ORIGIN 0.000 0.000 ;
  SIZE 21.280 BY 3.920 ;
  SYMMETRY X Y ;
  SITE GF018hv5v_mcu_sc7 ;
  PIN D
    DIRECTION INPUT ;
    ANTENNAGATEAREA 0.530500 ;
    PORT
      LAYER Metal1 ;
        RECT 3.450 1.770 4.390 2.150 ;
    END
  END D
  PIN SETN
    DIRECTION INPUT ;
    ANTENNAGATEAREA 1.156500 ;
    PORT
      LAYER Metal1 ;
        RECT 14.560 1.220 15.590 1.670 ;
    END
  END SETN
  PIN CLKN
    DIRECTION INPUT ;
    USE CLOCK ;
    ANTENNAGATEAREA 0.794000 ;
    PORT
      LAYER Metal1 ;
        RECT 0.280 1.770 1.590 2.130 ;
    END
  END CLKN
  PIN Q
    DIRECTION OUTPUT ;
    ANTENNADIFFAREA 1.055600 ;
    PORT
      LAYER Metal1 ;
        RECT 19.610 2.320 20.060 3.380 ;
        RECT 19.610 2.090 20.620 2.320 ;
        RECT 20.260 1.290 20.620 2.090 ;
        RECT 19.665 1.060 20.620 1.290 ;
        RECT 19.665 0.550 20.060 1.060 ;
    END
  END Q
  PIN VDD
    DIRECTION INOUT ;
    USE POWER ;
    SHAPE ABUTMENT ;
    PORT
      LAYER Metal1 ;
        RECT 0.000 3.620 21.280 4.220 ;
        RECT 1.310 3.005 1.650 3.620 ;
        RECT 3.050 3.005 3.390 3.620 ;
        RECT 7.290 3.240 7.630 3.620 ;
        RECT 9.825 2.885 10.055 3.620 ;
        RECT 14.110 2.945 14.450 3.620 ;
        RECT 16.745 2.600 16.975 3.620 ;
        RECT 18.645 2.570 18.875 3.620 ;
        RECT 20.685 2.570 20.915 3.620 ;
    END
  END VDD
  PIN VNW
    DIRECTION INOUT ;
    USE POWER ;
    PORT
      LAYER Nwell ;
        RECT -0.430 1.760 21.710 4.350 ;
    END
  END VNW
  PIN VPW
    DIRECTION INOUT ;
    USE GROUND ;
    PORT
      LAYER Pwell ;
        RECT -0.430 -0.430 21.710 1.760 ;
    END
  END VPW
  PIN VSS
    DIRECTION INOUT ;
    USE GROUND ;
    SHAPE ABUTMENT ;
    PORT
      LAYER Metal1 ;
        RECT 1.310 0.300 1.650 0.935 ;
        RECT 3.225 0.300 3.455 1.145 ;
        RECT 7.470 0.300 7.810 1.090 ;
        RECT 16.650 0.300 16.990 1.080 ;
        RECT 18.545 0.300 18.775 0.765 ;
        RECT 20.785 0.300 21.015 0.765 ;
        RECT 0.000 -0.300 21.280 0.300 ;
    END
  END VSS
  OBS
      LAYER Metal1 ;
        RECT 0.345 2.595 0.575 3.300 ;
        RECT 2.385 2.775 2.715 3.300 ;
        RECT 3.620 3.120 6.230 3.360 ;
        RECT 3.620 2.775 3.850 3.120 ;
        RECT 0.345 2.360 2.155 2.595 ;
        RECT 1.925 1.395 2.155 2.360 ;
        RECT 0.245 1.165 2.155 1.395 ;
        RECT 2.385 2.545 3.850 2.775 ;
        RECT 5.940 2.880 6.230 3.120 ;
        RECT 7.975 2.885 9.330 3.115 ;
        RECT 7.975 2.880 8.205 2.885 ;
        RECT 0.245 0.660 0.475 1.165 ;
        RECT 2.385 0.660 2.715 2.545 ;
        RECT 4.290 2.520 5.090 2.750 ;
        RECT 4.860 1.095 5.090 2.520 ;
        RECT 4.290 0.865 5.090 1.095 ;
        RECT 5.365 1.630 5.595 2.710 ;
        RECT 5.940 2.650 8.205 2.880 ;
        RECT 9.100 2.655 9.330 2.885 ;
        RECT 10.285 3.065 11.670 3.295 ;
        RECT 10.285 2.655 10.515 3.065 ;
        RECT 12.145 2.940 13.855 3.175 ;
        RECT 8.530 2.195 8.870 2.655 ;
        RECT 9.100 2.425 10.515 2.655 ;
        RECT 10.890 2.195 11.230 2.655 ;
        RECT 6.630 1.965 11.230 2.195 ;
        RECT 9.825 1.930 11.230 1.965 ;
        RECT 5.365 1.395 8.290 1.630 ;
        RECT 5.365 0.865 5.850 1.395 ;
        RECT 9.825 0.810 10.055 1.930 ;
        RECT 12.145 1.585 12.375 2.940 ;
        RECT 13.625 2.715 13.855 2.940 ;
        RECT 14.755 2.885 16.380 3.120 ;
        RECT 14.755 2.715 14.985 2.885 ;
        RECT 10.945 1.355 12.375 1.585 ;
        RECT 13.165 2.195 13.395 2.710 ;
        RECT 13.625 2.480 14.985 2.715 ;
        RECT 15.380 2.195 15.730 2.655 ;
        RECT 13.165 1.965 15.730 2.195 ;
        RECT 16.150 2.195 16.380 2.885 ;
        RECT 10.945 0.810 11.175 1.355 ;
        RECT 13.165 1.135 13.395 1.965 ;
        RECT 16.150 1.960 17.470 2.195 ;
        RECT 17.765 1.835 17.995 2.875 ;
        RECT 17.765 1.615 19.930 1.835 ;
        RECT 15.990 1.605 19.930 1.615 ;
        RECT 15.990 1.385 18.055 1.605 ;
        RECT 13.165 1.075 14.295 1.135 ;
        RECT 12.010 0.795 14.295 1.075 ;
        RECT 17.825 0.795 18.055 1.385 ;
  END
END gf180mcu_fd_sc_mcu7t5v0__dffnsnq_2

#--------EOF---------

MACRO gf180mcu_fd_sc_mcu7t5v0__dffq_1
  CLASS core ;
  FOREIGN gf180mcu_fd_sc_mcu7t5v0__dffq_1 ;
  ORIGIN 0.000 0.000 ;
  SIZE 16.240 BY 3.920 ;
  SYMMETRY X Y ;
  SITE GF018hv5v_mcu_sc7 ;
  PIN D
    DIRECTION INPUT ;
    ANTENNAGATEAREA 0.396000 ;
    PORT
      LAYER Metal1 ;
        RECT 4.570 1.210 4.975 2.710 ;
    END
  END D
  PIN CLK
    DIRECTION INPUT ;
    USE CLOCK ;
    ANTENNAGATEAREA 0.675500 ;
    PORT
      LAYER Metal1 ;
        RECT 0.650 1.770 1.590 2.150 ;
    END
  END CLK
  PIN Q
    DIRECTION OUTPUT ;
    ANTENNADIFFAREA 0.897600 ;
    PORT
      LAYER Metal1 ;
        RECT 14.835 2.330 15.850 2.975 ;
        RECT 15.470 0.550 15.850 2.330 ;
    END
  END Q
  PIN VDD
    DIRECTION INOUT ;
    USE POWER ;
    SHAPE ABUTMENT ;
    PORT
      LAYER Metal1 ;
        RECT 0.000 3.620 16.240 4.220 ;
        RECT 1.310 2.930 1.650 3.620 ;
        RECT 3.305 3.185 3.535 3.620 ;
        RECT 7.630 2.700 7.970 3.620 ;
        RECT 12.625 2.635 12.855 3.620 ;
        RECT 14.365 2.635 14.595 3.620 ;
    END
  END VDD
  PIN VNW
    DIRECTION INOUT ;
    USE POWER ;
    PORT
      LAYER Nwell ;
        RECT -0.430 1.885 16.670 4.350 ;
        RECT -0.430 1.760 4.865 1.885 ;
        RECT 6.120 1.760 16.670 1.885 ;
    END
  END VNW
  PIN VPW
    DIRECTION INOUT ;
    USE GROUND ;
    PORT
      LAYER Pwell ;
        RECT 4.865 1.760 6.120 1.885 ;
        RECT -0.430 -0.430 16.670 1.760 ;
    END
  END VPW
  PIN VSS
    DIRECTION INOUT ;
    USE GROUND ;
    SHAPE ABUTMENT ;
    PORT
      LAYER Metal1 ;
        RECT 1.310 0.300 1.650 1.050 ;
        RECT 3.150 0.300 3.490 1.090 ;
        RECT 7.790 0.300 8.130 0.585 ;
        RECT 12.485 0.300 12.715 1.105 ;
        RECT 14.425 0.300 14.655 0.890 ;
        RECT 0.000 -0.300 16.240 0.300 ;
    END
  END VSS
  OBS
      LAYER Metal1 ;
        RECT 0.345 2.700 0.575 3.155 ;
        RECT 1.915 2.980 3.075 3.215 ;
        RECT 1.915 2.700 2.145 2.980 ;
        RECT 2.845 2.885 3.075 2.980 ;
        RECT 3.890 3.160 6.590 3.390 ;
        RECT 8.640 3.160 11.330 3.390 ;
        RECT 3.890 2.885 4.120 3.160 ;
        RECT 0.345 2.470 2.145 2.700 ;
        RECT 1.915 1.510 2.145 2.470 ;
        RECT 2.385 2.325 2.615 2.710 ;
        RECT 2.845 2.650 4.120 2.885 ;
        RECT 5.610 2.470 5.950 2.930 ;
        RECT 2.385 2.090 4.075 2.325 ;
        RECT 3.845 1.555 4.075 2.090 ;
        RECT 0.245 1.280 2.145 1.510 ;
        RECT 2.485 1.325 4.075 1.555 ;
        RECT 0.245 0.810 0.475 1.280 ;
        RECT 2.485 0.810 2.715 1.325 ;
        RECT 3.845 0.760 4.075 1.325 ;
        RECT 5.325 2.240 8.410 2.470 ;
        RECT 5.325 0.990 5.670 2.240 ;
        RECT 8.640 2.010 8.870 3.160 ;
        RECT 6.165 1.780 8.870 2.010 ;
        RECT 6.165 0.760 6.395 1.780 ;
        RECT 9.125 1.550 9.470 2.930 ;
        RECT 7.130 1.320 9.470 1.550 ;
        RECT 9.130 0.860 9.470 1.320 ;
        RECT 9.720 1.225 9.950 3.160 ;
        RECT 10.250 2.130 10.590 2.930 ;
        RECT 10.250 1.895 13.350 2.130 ;
        RECT 10.250 0.860 10.590 1.895 ;
        RECT 13.645 1.840 13.875 3.030 ;
        RECT 13.645 1.630 15.095 1.840 ;
        RECT 11.770 1.500 15.095 1.630 ;
        RECT 11.770 1.400 13.870 1.500 ;
        RECT 3.845 0.530 6.395 0.760 ;
        RECT 13.605 0.755 13.870 1.400 ;
  END
END gf180mcu_fd_sc_mcu7t5v0__dffq_1

#--------EOF---------

MACRO gf180mcu_fd_sc_mcu7t5v0__dffq_2
  CLASS core ;
  FOREIGN gf180mcu_fd_sc_mcu7t5v0__dffq_2 ;
  ORIGIN 0.000 0.000 ;
  SIZE 17.360 BY 3.920 ;
  SYMMETRY X Y ;
  SITE GF018hv5v_mcu_sc7 ;
  PIN D
    DIRECTION INPUT ;
    ANTENNAGATEAREA 0.396000 ;
    PORT
      LAYER Metal1 ;
        RECT 4.570 1.210 4.975 2.710 ;
    END
  END D
  PIN CLK
    DIRECTION INPUT ;
    USE CLOCK ;
    ANTENNAGATEAREA 0.675500 ;
    PORT
      LAYER Metal1 ;
        RECT 0.650 1.770 1.590 2.150 ;
    END
  END CLK
  PIN Q
    DIRECTION OUTPUT ;
    ANTENNADIFFAREA 1.060800 ;
    PORT
      LAYER Metal1 ;
        RECT 15.330 2.330 16.410 2.975 ;
        RECT 16.030 1.020 16.410 2.330 ;
        RECT 15.450 0.550 16.410 1.020 ;
    END
  END Q
  PIN VDD
    DIRECTION INOUT ;
    USE POWER ;
    SHAPE ABUTMENT ;
    PORT
      LAYER Metal1 ;
        RECT 0.000 3.620 17.360 4.220 ;
        RECT 1.310 2.930 1.650 3.620 ;
        RECT 3.305 3.185 3.535 3.620 ;
        RECT 7.630 2.700 7.970 3.620 ;
        RECT 12.625 2.635 12.855 3.620 ;
        RECT 14.365 2.635 14.595 3.620 ;
        RECT 16.665 2.635 16.895 3.620 ;
    END
  END VDD
  PIN VNW
    DIRECTION INOUT ;
    USE POWER ;
    PORT
      LAYER Nwell ;
        RECT -0.430 1.885 17.790 4.350 ;
        RECT -0.430 1.760 4.865 1.885 ;
        RECT 6.120 1.760 17.790 1.885 ;
    END
  END VNW
  PIN VPW
    DIRECTION INOUT ;
    USE GROUND ;
    PORT
      LAYER Pwell ;
        RECT 4.865 1.760 6.120 1.885 ;
        RECT -0.430 -0.430 17.790 1.760 ;
    END
  END VPW
  PIN VSS
    DIRECTION INOUT ;
    USE GROUND ;
    SHAPE ABUTMENT ;
    PORT
      LAYER Metal1 ;
        RECT 1.310 0.300 1.650 1.050 ;
        RECT 3.150 0.300 3.490 1.090 ;
        RECT 7.790 0.300 8.130 0.585 ;
        RECT 12.485 0.300 12.715 1.105 ;
        RECT 14.425 0.300 14.655 0.890 ;
        RECT 16.665 0.300 16.895 0.970 ;
        RECT 0.000 -0.300 17.360 0.300 ;
    END
  END VSS
  OBS
      LAYER Metal1 ;
        RECT 0.345 2.700 0.575 3.155 ;
        RECT 1.915 2.980 3.075 3.215 ;
        RECT 1.915 2.700 2.145 2.980 ;
        RECT 2.845 2.885 3.075 2.980 ;
        RECT 3.890 3.160 6.590 3.390 ;
        RECT 8.640 3.160 11.330 3.390 ;
        RECT 3.890 2.885 4.120 3.160 ;
        RECT 0.345 2.470 2.145 2.700 ;
        RECT 1.915 1.510 2.145 2.470 ;
        RECT 2.385 2.325 2.615 2.710 ;
        RECT 2.845 2.650 4.120 2.885 ;
        RECT 5.610 2.470 5.950 2.930 ;
        RECT 2.385 2.090 4.075 2.325 ;
        RECT 3.845 1.555 4.075 2.090 ;
        RECT 0.245 1.280 2.145 1.510 ;
        RECT 2.485 1.325 4.075 1.555 ;
        RECT 0.245 0.810 0.475 1.280 ;
        RECT 2.485 0.810 2.715 1.325 ;
        RECT 3.845 0.760 4.075 1.325 ;
        RECT 5.325 2.240 8.410 2.470 ;
        RECT 5.325 0.990 5.670 2.240 ;
        RECT 8.640 2.010 8.870 3.160 ;
        RECT 6.165 1.780 8.870 2.010 ;
        RECT 6.165 0.760 6.395 1.780 ;
        RECT 9.125 1.550 9.470 2.930 ;
        RECT 7.130 1.320 9.470 1.550 ;
        RECT 9.130 0.860 9.470 1.320 ;
        RECT 9.720 1.225 9.950 3.160 ;
        RECT 10.250 2.130 10.590 2.930 ;
        RECT 10.250 1.895 13.350 2.130 ;
        RECT 10.250 0.860 10.590 1.895 ;
        RECT 13.645 1.840 13.875 3.030 ;
        RECT 13.645 1.630 15.565 1.840 ;
        RECT 11.770 1.500 15.565 1.630 ;
        RECT 11.770 1.400 13.870 1.500 ;
        RECT 13.605 0.805 13.870 1.400 ;
        RECT 3.845 0.530 6.395 0.760 ;
  END
END gf180mcu_fd_sc_mcu7t5v0__dffq_2

#--------EOF---------

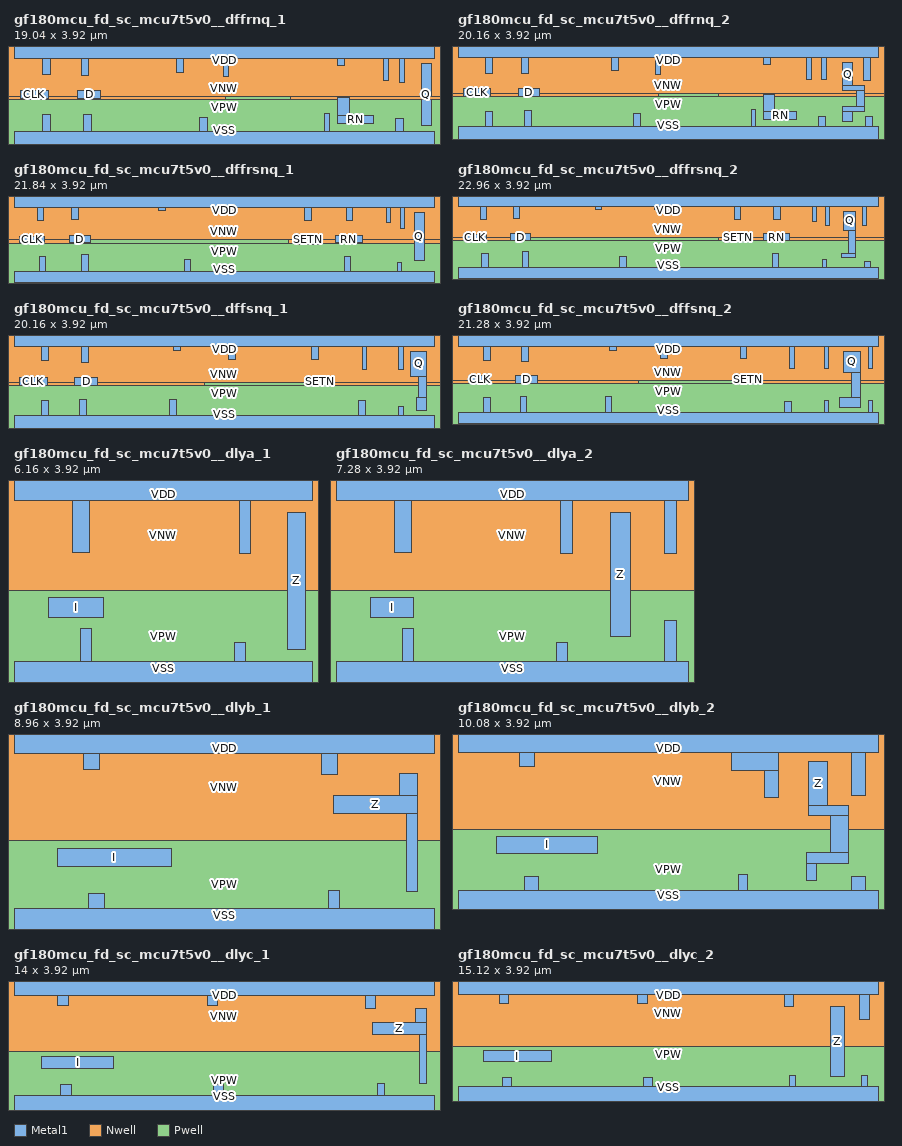
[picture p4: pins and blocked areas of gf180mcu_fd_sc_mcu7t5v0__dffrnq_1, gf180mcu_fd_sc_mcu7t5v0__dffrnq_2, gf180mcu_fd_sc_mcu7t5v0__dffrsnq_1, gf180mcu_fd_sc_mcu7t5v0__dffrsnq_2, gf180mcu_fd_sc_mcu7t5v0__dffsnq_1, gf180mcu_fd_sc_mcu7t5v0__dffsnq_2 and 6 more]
MACRO gf180mcu_fd_sc_mcu7t5v0__dffrnq_1
  CLASS core ;
  FOREIGN gf180mcu_fd_sc_mcu7t5v0__dffrnq_1 ;
  ORIGIN 0.000 0.000 ;
  SIZE 19.040 BY 3.920 ;
  SYMMETRY X Y ;
  SITE GF018hv5v_mcu_sc7 ;
  PIN D
    DIRECTION INPUT ;
    ANTENNAGATEAREA 0.606000 ;
    PORT
      LAYER Metal1 ;
        RECT 2.890 1.770 3.920 2.150 ;
    END
  END D
  PIN RN
    DIRECTION INPUT ;
    ANTENNAGATEAREA 1.322000 ;
    PORT
      LAYER Metal1 ;
        RECT 14.660 1.020 15.205 1.830 ;
        RECT 14.660 0.660 16.295 1.020 ;
    END
  END RN
  PIN CLK
    DIRECTION INPUT ;
    USE CLOCK ;
    ANTENNAGATEAREA 0.675500 ;
    PORT
      LAYER Metal1 ;
        RECT 0.280 1.770 1.570 2.150 ;
    END
  END CLK
  PIN Q
    DIRECTION OUTPUT ;
    ANTENNADIFFAREA 0.893200 ;
    PORT
      LAYER Metal1 ;
        RECT 18.475 0.550 18.910 3.380 ;
    END
  END Q
  PIN VDD
    DIRECTION INOUT ;
    USE POWER ;
    SHAPE ABUTMENT ;
    PORT
      LAYER Metal1 ;
        RECT 0.000 3.620 19.040 4.220 ;
        RECT 1.310 2.865 1.650 3.620 ;
        RECT 3.050 2.845 3.390 3.620 ;
        RECT 7.350 2.990 7.690 3.620 ;
        RECT 9.485 2.790 9.715 3.620 ;
        RECT 14.655 3.280 14.995 3.620 ;
        RECT 16.750 2.590 16.980 3.620 ;
        RECT 17.470 2.530 17.700 3.620 ;
    END
  END VDD
  PIN VNW
    DIRECTION INOUT ;
    USE POWER ;
    PORT
      LAYER Nwell ;
        RECT -0.430 1.895 19.470 4.350 ;
        RECT -0.430 1.760 9.600 1.895 ;
        RECT 12.515 1.760 19.470 1.895 ;
    END
  END VNW
  PIN VPW
    DIRECTION INOUT ;
    USE GROUND ;
    PORT
      LAYER Pwell ;
        RECT 9.600 1.760 12.515 1.895 ;
        RECT -0.430 -0.430 19.470 1.760 ;
    END
  END VPW
  PIN VSS
    DIRECTION INOUT ;
    USE GROUND ;
    SHAPE ABUTMENT ;
    PORT
      LAYER Metal1 ;
        RECT 1.310 0.300 1.655 1.050 ;
        RECT 3.170 0.300 3.510 1.075 ;
        RECT 8.430 0.300 8.770 0.915 ;
        RECT 14.070 0.300 14.300 1.130 ;
        RECT 17.315 0.300 17.655 0.875 ;
        RECT 0.000 -0.300 19.040 0.300 ;
    END
  END VSS
  OBS
      LAYER Metal1 ;
        RECT 0.345 2.635 0.575 3.225 ;
        RECT 0.345 2.405 2.035 2.635 ;
        RECT 1.805 1.510 2.035 2.405 ;
        RECT 0.245 1.280 2.035 1.510 ;
        RECT 2.265 2.615 2.615 3.215 ;
        RECT 3.665 2.990 4.915 3.220 ;
        RECT 12.210 3.160 14.425 3.390 ;
        RECT 3.665 2.615 3.895 2.990 ;
        RECT 2.265 2.385 3.895 2.615 ;
        RECT 4.125 2.420 4.455 2.760 ;
        RECT 0.245 0.810 0.475 1.280 ;
        RECT 2.265 1.095 2.495 2.385 ;
        RECT 2.265 0.865 2.770 1.095 ;
        RECT 4.225 1.075 4.455 2.420 ;
        RECT 4.685 1.910 4.915 2.990 ;
        RECT 6.165 2.760 6.395 2.955 ;
        RECT 8.765 2.760 8.995 3.130 ;
        RECT 5.145 2.300 5.375 2.760 ;
        RECT 6.165 2.530 8.995 2.760 ;
        RECT 10.440 2.845 11.080 3.075 ;
        RECT 9.855 2.300 10.155 2.525 ;
        RECT 5.145 2.070 10.155 2.300 ;
        RECT 4.225 0.845 4.630 1.075 ;
        RECT 5.465 0.790 5.695 2.070 ;
        RECT 10.440 1.840 10.670 2.845 ;
        RECT 12.210 2.050 12.440 3.160 ;
        RECT 14.195 3.050 14.425 3.160 ;
        RECT 15.235 3.160 16.420 3.390 ;
        RECT 15.235 3.050 15.465 3.160 ;
        RECT 6.690 1.610 10.670 1.840 ;
        RECT 11.550 1.820 12.440 2.050 ;
        RECT 6.045 1.380 6.275 1.590 ;
        RECT 6.045 1.150 9.230 1.380 ;
        RECT 9.000 0.760 9.230 1.150 ;
        RECT 9.990 1.000 10.330 1.610 ;
        RECT 10.925 0.760 11.155 1.590 ;
        RECT 11.550 1.000 11.890 1.820 ;
        RECT 12.890 1.590 13.120 2.525 ;
        RECT 12.120 1.360 13.120 1.590 ;
        RECT 12.120 0.760 12.350 1.360 ;
        RECT 13.415 1.130 13.755 2.930 ;
        RECT 14.195 2.820 15.465 3.050 ;
        RECT 15.730 2.405 15.960 2.930 ;
        RECT 13.995 2.175 15.960 2.405 ;
        RECT 15.730 1.680 15.960 2.175 ;
        RECT 16.190 1.910 16.420 3.160 ;
        RECT 15.730 1.450 18.230 1.680 ;
        RECT 12.950 0.790 13.755 1.130 ;
        RECT 16.650 0.790 16.880 1.450 ;
        RECT 9.000 0.530 12.350 0.760 ;
  END
END gf180mcu_fd_sc_mcu7t5v0__dffrnq_1

#--------EOF---------

MACRO gf180mcu_fd_sc_mcu7t5v0__dffrnq_2
  CLASS core ;
  FOREIGN gf180mcu_fd_sc_mcu7t5v0__dffrnq_2 ;
  ORIGIN 0.000 0.000 ;
  SIZE 20.160 BY 3.920 ;
  SYMMETRY X Y ;
  SITE GF018hv5v_mcu_sc7 ;
  PIN D
    DIRECTION INPUT ;
    ANTENNAGATEAREA 0.606000 ;
    PORT
      LAYER Metal1 ;
        RECT 2.890 1.770 3.920 2.150 ;
    END
  END D
  PIN RN
    DIRECTION INPUT ;
    ANTENNAGATEAREA 1.429500 ;
    PORT
      LAYER Metal1 ;
        RECT 14.660 1.020 15.205 1.830 ;
        RECT 14.660 0.660 16.255 1.020 ;
    END
  END RN
  PIN CLK
    DIRECTION INPUT ;
    USE CLOCK ;
    ANTENNAGATEAREA 0.675500 ;
    PORT
      LAYER Metal1 ;
        RECT 0.280 1.770 1.570 2.150 ;
    END
  END CLK
  PIN Q
    DIRECTION OUTPUT ;
    ANTENNADIFFAREA 1.055600 ;
    PORT
      LAYER Metal1 ;
        RECT 18.475 2.280 18.940 3.380 ;
        RECT 18.475 2.050 19.500 2.280 ;
        RECT 19.140 1.270 19.500 2.050 ;
        RECT 18.475 1.040 19.500 1.270 ;
        RECT 18.475 0.550 18.940 1.040 ;
    END
  END Q
  PIN VDD
    DIRECTION INOUT ;
    USE POWER ;
    SHAPE ABUTMENT ;
    PORT
      LAYER Metal1 ;
        RECT 0.000 3.620 20.160 4.220 ;
        RECT 1.310 2.865 1.650 3.620 ;
        RECT 3.050 2.845 3.390 3.620 ;
        RECT 7.350 2.990 7.690 3.620 ;
        RECT 9.485 2.790 9.715 3.620 ;
        RECT 14.655 3.280 14.995 3.620 ;
        RECT 16.750 2.570 16.985 3.620 ;
        RECT 17.465 2.570 17.700 3.620 ;
        RECT 19.455 2.530 19.795 3.620 ;
    END
  END VDD
  PIN VNW
    DIRECTION INOUT ;
    USE POWER ;
    PORT
      LAYER Nwell ;
        RECT -0.430 1.895 20.590 4.350 ;
        RECT -0.430 1.760 9.600 1.895 ;
        RECT 12.515 1.760 20.590 1.895 ;
    END
  END VNW
  PIN VPW
    DIRECTION INOUT ;
    USE GROUND ;
    PORT
      LAYER Pwell ;
        RECT 9.600 1.760 12.515 1.895 ;
        RECT -0.430 -0.430 20.590 1.760 ;
    END
  END VPW
  PIN VSS
    DIRECTION INOUT ;
    USE GROUND ;
    SHAPE ABUTMENT ;
    PORT
      LAYER Metal1 ;
        RECT 1.310 0.300 1.655 1.050 ;
        RECT 3.170 0.300 3.510 1.075 ;
        RECT 8.430 0.300 8.770 0.915 ;
        RECT 14.070 0.300 14.300 1.130 ;
        RECT 17.315 0.300 17.655 0.790 ;
        RECT 19.555 0.300 19.895 0.790 ;
        RECT 0.000 -0.300 20.160 0.300 ;
    END
  END VSS
  OBS
      LAYER Metal1 ;
        RECT 0.345 2.635 0.575 3.225 ;
        RECT 0.345 2.405 2.035 2.635 ;
        RECT 1.805 1.510 2.035 2.405 ;
        RECT 0.245 1.280 2.035 1.510 ;
        RECT 2.265 2.615 2.615 3.215 ;
        RECT 3.665 2.990 4.915 3.220 ;
        RECT 12.210 3.160 14.425 3.390 ;
        RECT 3.665 2.615 3.895 2.990 ;
        RECT 2.265 2.385 3.895 2.615 ;
        RECT 4.125 2.420 4.455 2.760 ;
        RECT 0.245 0.810 0.475 1.280 ;
        RECT 2.265 1.095 2.495 2.385 ;
        RECT 2.265 0.865 2.770 1.095 ;
        RECT 4.225 1.075 4.455 2.420 ;
        RECT 4.685 1.910 4.915 2.990 ;
        RECT 6.165 2.760 6.395 2.955 ;
        RECT 8.765 2.760 8.995 3.130 ;
        RECT 5.145 2.300 5.375 2.760 ;
        RECT 6.165 2.530 8.995 2.760 ;
        RECT 10.440 2.845 11.080 3.075 ;
        RECT 9.855 2.300 10.155 2.525 ;
        RECT 5.145 2.070 10.155 2.300 ;
        RECT 4.225 0.845 4.630 1.075 ;
        RECT 5.465 0.790 5.695 2.070 ;
        RECT 10.440 1.840 10.670 2.845 ;
        RECT 12.210 2.050 12.440 3.160 ;
        RECT 14.195 3.050 14.425 3.160 ;
        RECT 15.235 3.160 16.420 3.390 ;
        RECT 15.235 3.050 15.465 3.160 ;
        RECT 6.690 1.610 10.670 1.840 ;
        RECT 11.550 1.820 12.440 2.050 ;
        RECT 6.045 1.380 6.275 1.590 ;
        RECT 6.045 1.150 9.230 1.380 ;
        RECT 9.000 0.760 9.230 1.150 ;
        RECT 9.990 1.000 10.330 1.610 ;
        RECT 10.925 0.760 11.155 1.590 ;
        RECT 11.550 1.000 11.890 1.820 ;
        RECT 12.890 1.590 13.120 2.525 ;
        RECT 12.120 1.360 13.120 1.590 ;
        RECT 12.120 0.760 12.350 1.360 ;
        RECT 13.415 1.130 13.755 2.930 ;
        RECT 14.195 2.820 15.465 3.050 ;
        RECT 15.730 2.405 15.960 2.930 ;
        RECT 13.995 2.175 15.960 2.405 ;
        RECT 15.730 1.680 15.960 2.175 ;
        RECT 16.190 1.910 16.420 3.160 ;
        RECT 16.650 1.680 18.690 1.755 ;
        RECT 15.730 1.525 18.690 1.680 ;
        RECT 15.730 1.450 16.880 1.525 ;
        RECT 12.950 0.790 13.755 1.130 ;
        RECT 16.650 0.810 16.880 1.450 ;
        RECT 9.000 0.530 12.350 0.760 ;
  END
END gf180mcu_fd_sc_mcu7t5v0__dffrnq_2

#--------EOF---------

MACRO gf180mcu_fd_sc_mcu7t5v0__dffrsnq_1
  CLASS core ;
  FOREIGN gf180mcu_fd_sc_mcu7t5v0__dffrsnq_1 ;
  ORIGIN 0.000 0.000 ;
  SIZE 21.840 BY 3.920 ;
  SYMMETRY X Y ;
  SITE GF018hv5v_mcu_sc7 ;
  PIN D
    DIRECTION INPUT ;
    ANTENNAGATEAREA 0.401500 ;
    PORT
      LAYER Metal1 ;
        RECT 2.890 1.770 3.960 2.150 ;
    END
  END D
  PIN RN
    DIRECTION INPUT ;
    ANTENNAGATEAREA 1.209500 ;
    PORT
      LAYER Metal1 ;
        RECT 16.715 1.785 18.115 2.150 ;
    END
  END RN
  PIN SETN
    DIRECTION INPUT ;
    ANTENNAGATEAREA 1.096000 ;
    PORT
      LAYER Metal1 ;
        RECT 14.650 1.700 15.955 2.150 ;
    END
  END SETN
  PIN CLK
    DIRECTION INPUT ;
    USE CLOCK ;
    ANTENNAGATEAREA 0.675500 ;
    PORT
      LAYER Metal1 ;
        RECT 0.280 1.770 1.575 2.130 ;
    END
  END CLK
  PIN Q
    DIRECTION OUTPUT ;
    ANTENNADIFFAREA 0.893200 ;
    PORT
      LAYER Metal1 ;
        RECT 20.825 0.860 21.335 3.380 ;
    END
  END Q
  PIN VDD
    DIRECTION INOUT ;
    USE POWER ;
    SHAPE ABUTMENT ;
    PORT
      LAYER Metal1 ;
        RECT 0.000 3.620 21.840 4.220 ;
        RECT 1.205 2.930 1.555 3.620 ;
        RECT 3.010 3.005 3.350 3.620 ;
        RECT 7.530 3.445 7.870 3.620 ;
        RECT 10.730 3.445 11.070 3.620 ;
        RECT 15.125 2.930 15.465 3.620 ;
        RECT 17.270 2.930 17.610 3.620 ;
        RECT 19.365 2.810 19.595 3.620 ;
        RECT 20.085 2.530 20.315 3.620 ;
    END
  END VDD
  PIN VNW
    DIRECTION INOUT ;
    USE POWER ;
    PORT
      LAYER Nwell ;
        RECT -0.430 1.940 22.270 4.350 ;
        RECT -0.430 1.760 3.225 1.940 ;
        RECT 14.255 1.760 22.270 1.940 ;
    END
  END VNW
  PIN VPW
    DIRECTION INOUT ;
    USE GROUND ;
    PORT
      LAYER Pwell ;
        RECT 3.225 1.760 14.255 1.940 ;
        RECT -0.430 -0.430 22.270 1.760 ;
    END
  END VPW
  PIN VSS
    DIRECTION INOUT ;
    USE GROUND ;
    SHAPE ABUTMENT ;
    PORT
      LAYER Metal1 ;
        RECT 1.310 0.300 1.650 1.050 ;
        RECT 3.510 0.300 3.850 1.150 ;
        RECT 8.850 0.300 9.190 0.915 ;
        RECT 17.170 0.300 17.510 1.075 ;
        RECT 19.925 0.300 20.155 0.765 ;
        RECT 0.000 -0.300 21.840 0.300 ;
    END
  END VSS
  OBS
      LAYER Metal1 ;
        RECT 0.245 2.590 0.475 3.225 ;
        RECT 2.285 2.725 2.515 3.225 ;
        RECT 3.650 3.110 5.095 3.340 ;
        RECT 5.850 3.215 7.300 3.345 ;
        RECT 8.180 3.215 10.480 3.390 ;
        RECT 11.300 3.215 12.750 3.295 ;
        RECT 5.850 3.155 12.750 3.215 ;
        RECT 5.850 3.110 8.410 3.155 ;
        RECT 3.650 2.725 3.880 3.110 ;
        RECT 0.245 2.360 2.055 2.590 ;
        RECT 1.825 1.510 2.055 2.360 ;
        RECT 0.245 1.280 2.055 1.510 ;
        RECT 2.285 2.490 3.880 2.725 ;
        RECT 0.245 0.810 0.475 1.280 ;
        RECT 2.285 1.105 2.515 2.490 ;
        RECT 4.250 1.205 4.590 2.880 ;
        RECT 4.865 1.895 5.095 3.110 ;
        RECT 7.070 2.985 8.410 3.110 ;
        RECT 10.245 3.065 12.750 3.155 ;
        RECT 13.045 3.120 14.815 3.355 ;
        RECT 10.245 2.985 11.530 3.065 ;
        RECT 5.325 2.295 5.555 2.940 ;
        RECT 6.290 2.755 6.630 2.880 ;
        RECT 8.770 2.755 9.110 2.925 ;
        RECT 6.290 2.525 9.110 2.755 ;
        RECT 9.490 2.755 9.830 2.925 ;
        RECT 11.970 2.755 12.310 2.835 ;
        RECT 9.490 2.525 12.310 2.755 ;
        RECT 5.325 2.065 10.270 2.295 ;
        RECT 5.325 2.040 6.035 2.065 ;
        RECT 2.285 0.765 2.715 1.105 ;
        RECT 4.250 0.865 4.915 1.205 ;
        RECT 5.805 0.865 6.035 2.040 ;
        RECT 11.280 1.835 11.510 2.525 ;
        RECT 13.045 2.295 13.275 3.120 ;
        RECT 6.265 1.375 6.495 1.685 ;
        RECT 7.030 1.605 11.510 1.835 ;
        RECT 12.400 2.060 13.275 2.295 ;
        RECT 6.265 1.145 10.880 1.375 ;
        RECT 10.650 0.760 10.880 1.145 ;
        RECT 11.170 0.990 11.510 1.605 ;
        RECT 11.745 0.760 12.000 1.735 ;
        RECT 12.400 1.220 12.630 2.060 ;
        RECT 13.505 1.830 13.735 2.430 ;
        RECT 12.290 0.990 12.630 1.220 ;
        RECT 12.895 1.600 13.735 1.830 ;
        RECT 12.895 0.760 13.125 1.600 ;
        RECT 14.065 1.220 14.295 2.890 ;
        RECT 14.585 2.700 14.815 3.120 ;
        RECT 15.695 3.090 17.035 3.325 ;
        RECT 15.695 2.700 15.925 3.090 ;
        RECT 14.585 2.465 15.925 2.700 ;
        RECT 16.185 2.465 16.535 2.805 ;
        RECT 16.805 2.700 17.035 3.090 ;
        RECT 17.885 3.035 19.035 3.270 ;
        RECT 17.885 2.700 18.115 3.035 ;
        RECT 16.805 2.465 18.115 2.700 ;
        RECT 13.410 1.075 14.295 1.220 ;
        RECT 16.185 1.075 16.415 2.465 ;
        RECT 18.345 1.610 18.575 2.805 ;
        RECT 18.805 2.005 19.035 3.035 ;
        RECT 18.345 1.555 20.595 1.610 ;
        RECT 16.645 1.325 20.595 1.555 ;
        RECT 13.410 0.990 16.415 1.075 ;
        RECT 14.065 0.845 16.415 0.990 ;
        RECT 19.205 1.270 20.595 1.325 ;
        RECT 19.205 0.790 19.435 1.270 ;
        RECT 10.650 0.530 13.125 0.760 ;
  END
END gf180mcu_fd_sc_mcu7t5v0__dffrsnq_1

#--------EOF---------

MACRO gf180mcu_fd_sc_mcu7t5v0__dffrsnq_2
  CLASS core ;
  FOREIGN gf180mcu_fd_sc_mcu7t5v0__dffrsnq_2 ;
  ORIGIN 0.000 0.000 ;
  SIZE 22.960 BY 3.920 ;
  SYMMETRY X Y ;
  SITE GF018hv5v_mcu_sc7 ;
  PIN D
    DIRECTION INPUT ;
    ANTENNAGATEAREA 0.401500 ;
    PORT
      LAYER Metal1 ;
        RECT 2.890 1.770 3.960 2.150 ;
    END
  END D
  PIN RN
    DIRECTION INPUT ;
    ANTENNAGATEAREA 1.209500 ;
    PORT
      LAYER Metal1 ;
        RECT 16.715 1.785 18.115 2.150 ;
    END
  END RN
  PIN SETN
    DIRECTION INPUT ;
    ANTENNAGATEAREA 1.096000 ;
    PORT
      LAYER Metal1 ;
        RECT 14.650 1.700 15.955 2.150 ;
    END
  END SETN
  PIN CLK
    DIRECTION INPUT ;
    USE CLOCK ;
    ANTENNAGATEAREA 0.675500 ;
    PORT
      LAYER Metal1 ;
        RECT 0.310 1.770 1.575 2.130 ;
    END
  END CLK
  PIN Q
    DIRECTION OUTPUT ;
    ANTENNADIFFAREA 1.055600 ;
    PORT
      LAYER Metal1 ;
        RECT 21.100 2.330 21.755 3.380 ;
        RECT 21.370 1.090 21.755 2.330 ;
        RECT 20.990 0.860 21.755 1.090 ;
    END
  END Q
  PIN VDD
    DIRECTION INOUT ;
    USE POWER ;
    SHAPE ABUTMENT ;
    PORT
      LAYER Metal1 ;
        RECT 0.000 3.620 22.960 4.220 ;
        RECT 1.205 2.930 1.555 3.620 ;
        RECT 3.010 3.005 3.350 3.620 ;
        RECT 7.530 3.445 7.870 3.620 ;
        RECT 10.730 3.445 11.070 3.620 ;
        RECT 15.125 2.930 15.465 3.620 ;
        RECT 17.270 2.930 17.610 3.620 ;
        RECT 19.365 2.810 19.595 3.620 ;
        RECT 20.085 2.570 20.315 3.620 ;
        RECT 22.125 2.570 22.355 3.620 ;
    END
  END VDD
  PIN VNW
    DIRECTION INOUT ;
    USE POWER ;
    PORT
      LAYER Nwell ;
        RECT -0.430 1.940 23.390 4.350 ;
        RECT -0.430 1.760 3.225 1.940 ;
        RECT 14.255 1.760 23.390 1.940 ;
    END
  END VNW
  PIN VPW
    DIRECTION INOUT ;
    USE GROUND ;
    PORT
      LAYER Pwell ;
        RECT 3.225 1.760 14.255 1.940 ;
        RECT -0.430 -0.430 23.390 1.760 ;
    END
  END VPW
  PIN VSS
    DIRECTION INOUT ;
    USE GROUND ;
    SHAPE ABUTMENT ;
    PORT
      LAYER Metal1 ;
        RECT 1.310 0.300 1.650 1.050 ;
        RECT 3.510 0.300 3.850 1.150 ;
        RECT 8.850 0.300 9.190 0.915 ;
        RECT 17.170 0.300 17.510 1.075 ;
        RECT 19.925 0.300 20.155 0.765 ;
        RECT 22.210 0.300 22.550 0.640 ;
        RECT 0.000 -0.300 22.960 0.300 ;
    END
  END VSS
  OBS
      LAYER Metal1 ;
        RECT 0.245 2.590 0.475 3.225 ;
        RECT 2.285 2.725 2.515 3.225 ;
        RECT 3.650 3.110 5.095 3.340 ;
        RECT 5.850 3.215 7.300 3.345 ;
        RECT 8.180 3.215 10.480 3.390 ;
        RECT 11.300 3.215 12.750 3.295 ;
        RECT 5.850 3.155 12.750 3.215 ;
        RECT 5.850 3.110 8.410 3.155 ;
        RECT 3.650 2.725 3.880 3.110 ;
        RECT 0.245 2.360 2.055 2.590 ;
        RECT 1.825 1.510 2.055 2.360 ;
        RECT 0.245 1.280 2.055 1.510 ;
        RECT 2.285 2.490 3.880 2.725 ;
        RECT 0.245 0.810 0.475 1.280 ;
        RECT 2.285 1.105 2.515 2.490 ;
        RECT 4.250 1.205 4.590 2.880 ;
        RECT 4.865 1.895 5.095 3.110 ;
        RECT 7.070 2.985 8.410 3.110 ;
        RECT 10.245 3.065 12.750 3.155 ;
        RECT 13.045 3.120 14.815 3.355 ;
        RECT 10.245 2.985 11.530 3.065 ;
        RECT 5.325 2.295 5.555 2.940 ;
        RECT 6.290 2.755 6.630 2.880 ;
        RECT 8.770 2.755 9.110 2.925 ;
        RECT 6.290 2.525 9.110 2.755 ;
        RECT 9.490 2.755 9.830 2.925 ;
        RECT 11.970 2.755 12.310 2.835 ;
        RECT 9.490 2.525 12.310 2.755 ;
        RECT 5.325 2.065 10.270 2.295 ;
        RECT 5.325 2.040 6.035 2.065 ;
        RECT 2.285 0.765 2.715 1.105 ;
        RECT 4.250 0.865 4.915 1.205 ;
        RECT 5.805 0.865 6.035 2.040 ;
        RECT 11.280 1.835 11.510 2.525 ;
        RECT 13.045 2.295 13.275 3.120 ;
        RECT 6.265 1.375 6.495 1.685 ;
        RECT 7.030 1.605 11.510 1.835 ;
        RECT 12.400 2.060 13.275 2.295 ;
        RECT 6.265 1.145 10.880 1.375 ;
        RECT 10.650 0.760 10.880 1.145 ;
        RECT 11.170 0.990 11.510 1.605 ;
        RECT 11.745 0.760 12.000 1.735 ;
        RECT 12.400 1.220 12.630 2.060 ;
        RECT 13.505 1.830 13.735 2.430 ;
        RECT 12.290 0.990 12.630 1.220 ;
        RECT 12.895 1.600 13.735 1.830 ;
        RECT 12.895 0.760 13.125 1.600 ;
        RECT 14.065 1.220 14.295 2.890 ;
        RECT 14.585 2.700 14.815 3.120 ;
        RECT 15.695 3.090 17.035 3.325 ;
        RECT 15.695 2.700 15.925 3.090 ;
        RECT 14.585 2.465 15.925 2.700 ;
        RECT 16.185 2.465 16.535 2.805 ;
        RECT 16.805 2.700 17.035 3.090 ;
        RECT 17.885 3.035 19.035 3.270 ;
        RECT 17.885 2.700 18.115 3.035 ;
        RECT 16.805 2.465 18.115 2.700 ;
        RECT 13.410 1.075 14.295 1.220 ;
        RECT 16.185 1.075 16.415 2.465 ;
        RECT 18.345 1.555 18.575 2.805 ;
        RECT 18.805 2.005 19.035 3.035 ;
        RECT 20.305 1.555 21.120 1.755 ;
        RECT 16.645 1.525 21.120 1.555 ;
        RECT 16.645 1.325 20.595 1.525 ;
        RECT 13.410 0.990 16.415 1.075 ;
        RECT 14.065 0.845 16.415 0.990 ;
        RECT 19.205 0.790 19.435 1.325 ;
        RECT 10.650 0.530 13.125 0.760 ;
  END
END gf180mcu_fd_sc_mcu7t5v0__dffrsnq_2

#--------EOF---------

MACRO gf180mcu_fd_sc_mcu7t5v0__dffsnq_1
  CLASS core ;
  FOREIGN gf180mcu_fd_sc_mcu7t5v0__dffsnq_1 ;
  ORIGIN 0.000 0.000 ;
  SIZE 20.160 BY 3.920 ;
  SYMMETRY X Y ;
  SITE GF018hv5v_mcu_sc7 ;
  PIN D
    DIRECTION INPUT ;
    ANTENNAGATEAREA 0.468500 ;
    PORT
      LAYER Metal1 ;
        RECT 2.890 1.770 4.030 2.150 ;
    END
  END D
  PIN SETN
    DIRECTION INPUT ;
    ANTENNAGATEAREA 1.141500 ;
    PORT
      LAYER Metal1 ;
        RECT 14.090 1.770 15.285 2.150 ;
    END
  END SETN
  PIN CLK
    DIRECTION INPUT ;
    USE CLOCK ;
    ANTENNAGATEAREA 0.675500 ;
    PORT
      LAYER Metal1 ;
        RECT 0.280 1.765 1.590 2.130 ;
    END
  END CLK
  PIN Q
    DIRECTION OUTPUT ;
    ANTENNADIFFAREA 1.014700 ;
    PORT
      LAYER Metal1 ;
        RECT 19.045 2.190 19.815 3.380 ;
        RECT 19.425 1.160 19.815 2.190 ;
        RECT 19.300 0.550 19.815 1.160 ;
    END
  END Q
  PIN VDD
    DIRECTION INOUT ;
    USE POWER ;
    SHAPE ABUTMENT ;
    PORT
      LAYER Metal1 ;
        RECT 0.000 3.620 20.160 4.220 ;
        RECT 1.310 2.930 1.650 3.620 ;
        RECT 3.240 2.845 3.580 3.620 ;
        RECT 7.675 3.445 8.015 3.620 ;
        RECT 10.275 3.005 10.615 3.620 ;
        RECT 14.295 3.005 14.635 3.620 ;
        RECT 16.710 2.530 16.940 3.620 ;
        RECT 18.450 2.530 18.680 3.620 ;
    END
  END VDD
  PIN VNW
    DIRECTION INOUT ;
    USE POWER ;
    PORT
      LAYER Nwell ;
        RECT -0.430 1.885 20.590 4.350 ;
        RECT -0.430 1.760 9.135 1.885 ;
        RECT 15.165 1.760 20.590 1.885 ;
    END
  END VNW
  PIN VPW
    DIRECTION INOUT ;
    USE GROUND ;
    PORT
      LAYER Pwell ;
        RECT 9.135 1.760 15.165 1.885 ;
        RECT -0.430 -0.430 20.590 1.760 ;
    END
  END VPW
  PIN VSS
    DIRECTION INOUT ;
    USE GROUND ;
    SHAPE ABUTMENT ;
    PORT
      LAYER Metal1 ;
        RECT 1.310 0.300 1.650 1.050 ;
        RECT 3.150 0.300 3.490 1.075 ;
        RECT 7.455 0.300 7.795 1.075 ;
        RECT 16.555 0.300 16.895 1.050 ;
        RECT 18.450 0.300 18.680 0.765 ;
        RECT 0.000 -0.300 20.160 0.300 ;
    END
  END VSS
  OBS
      LAYER Metal1 ;
        RECT 0.345 2.595 0.575 3.225 ;
        RECT 2.385 2.615 2.615 3.225 ;
        RECT 3.810 3.160 5.115 3.390 ;
        RECT 8.270 3.215 9.915 3.390 ;
        RECT 3.810 2.615 4.040 3.160 ;
        RECT 0.345 2.360 2.090 2.595 ;
        RECT 1.860 1.510 2.090 2.360 ;
        RECT 0.245 1.280 2.090 1.510 ;
        RECT 2.385 2.380 4.040 2.615 ;
        RECT 0.245 0.810 0.475 1.280 ;
        RECT 2.385 1.150 2.620 2.380 ;
        RECT 2.385 0.810 2.715 1.150 ;
        RECT 4.270 0.790 4.610 2.930 ;
        RECT 4.885 1.930 5.115 3.160 ;
        RECT 6.115 3.160 9.915 3.215 ;
        RECT 6.115 2.985 8.500 3.160 ;
        RECT 5.345 1.995 5.575 2.985 ;
        RECT 6.115 2.240 6.455 2.985 ;
        RECT 9.035 2.455 9.375 2.930 ;
        RECT 9.685 2.775 9.915 3.160 ;
        RECT 10.845 3.065 12.315 3.295 ;
        RECT 10.845 2.775 11.075 3.065 ;
        RECT 9.685 2.540 11.075 2.775 ;
        RECT 7.015 2.310 9.375 2.455 ;
        RECT 11.305 2.310 11.645 2.780 ;
        RECT 7.015 2.225 11.645 2.310 ;
        RECT 9.035 2.080 11.645 2.225 ;
        RECT 11.930 2.550 12.895 2.780 ;
        RECT 13.630 2.775 13.860 2.845 ;
        RECT 15.370 2.775 15.600 2.885 ;
        RECT 5.345 1.765 8.235 1.995 ;
        RECT 5.345 0.790 5.675 1.765 ;
        RECT 6.000 1.305 8.340 1.535 ;
        RECT 8.110 0.760 8.340 1.305 ;
        RECT 9.875 0.990 10.215 2.080 ;
        RECT 10.810 0.760 11.040 1.615 ;
        RECT 11.930 1.130 12.160 2.550 ;
        RECT 13.630 2.540 15.600 2.775 ;
        RECT 13.630 1.220 13.860 2.540 ;
        RECT 17.730 2.105 17.960 3.380 ;
        RECT 15.755 1.860 17.960 2.105 ;
        RECT 17.730 1.840 17.960 1.860 ;
        RECT 15.880 1.395 17.335 1.630 ;
        RECT 17.730 1.500 19.120 1.840 ;
        RECT 11.270 0.790 12.160 1.130 ;
        RECT 12.555 0.990 14.495 1.220 ;
        RECT 8.110 0.530 11.040 0.760 ;
        RECT 11.930 0.760 12.160 0.790 ;
        RECT 15.880 0.760 16.110 1.395 ;
        RECT 17.730 0.805 17.960 1.500 ;
        RECT 11.930 0.530 16.110 0.760 ;
  END
END gf180mcu_fd_sc_mcu7t5v0__dffsnq_1

#--------EOF---------

MACRO gf180mcu_fd_sc_mcu7t5v0__dffsnq_2
  CLASS core ;
  FOREIGN gf180mcu_fd_sc_mcu7t5v0__dffsnq_2 ;
  ORIGIN 0.000 0.000 ;
  SIZE 21.280 BY 3.920 ;
  SYMMETRY X Y ;
  SITE GF018hv5v_mcu_sc7 ;
  PIN D
    DIRECTION INPUT ;
    ANTENNAGATEAREA 0.468500 ;
    PORT
      LAYER Metal1 ;
        RECT 2.890 1.770 4.030 2.150 ;
    END
  END D
  PIN SETN
    DIRECTION INPUT ;
    ANTENNAGATEAREA 1.141500 ;
    PORT
      LAYER Metal1 ;
        RECT 14.090 1.770 15.285 2.150 ;
    END
  END SETN
  PIN CLK
    DIRECTION INPUT ;
    USE CLOCK ;
    ANTENNAGATEAREA 0.675500 ;
    PORT
      LAYER Metal1 ;
        RECT 0.650 1.765 1.590 2.130 ;
    END
  END CLK
  PIN Q
    DIRECTION OUTPUT ;
    ANTENNADIFFAREA 1.298600 ;
    PORT
      LAYER Metal1 ;
        RECT 19.530 2.330 20.370 3.380 ;
        RECT 19.950 1.020 20.370 2.330 ;
        RECT 19.330 0.550 20.370 1.020 ;
    END
  END Q
  PIN VDD
    DIRECTION INOUT ;
    USE POWER ;
    SHAPE ABUTMENT ;
    PORT
      LAYER Metal1 ;
        RECT 0.000 3.620 21.280 4.220 ;
        RECT 1.310 2.930 1.650 3.620 ;
        RECT 3.240 2.845 3.580 3.620 ;
        RECT 7.675 3.445 8.015 3.620 ;
        RECT 10.275 3.005 10.615 3.620 ;
        RECT 14.295 3.005 14.635 3.620 ;
        RECT 16.810 2.530 17.040 3.620 ;
        RECT 18.550 2.530 18.780 3.620 ;
        RECT 20.790 2.530 21.020 3.620 ;
    END
  END VDD
  PIN VNW
    DIRECTION INOUT ;
    USE POWER ;
    PORT
      LAYER Nwell ;
        RECT -0.430 1.885 21.710 4.350 ;
        RECT -0.430 1.760 9.135 1.885 ;
        RECT 15.165 1.760 21.710 1.885 ;
    END
  END VNW
  PIN VPW
    DIRECTION INOUT ;
    USE GROUND ;
    PORT
      LAYER Pwell ;
        RECT 9.135 1.760 15.165 1.885 ;
        RECT -0.430 -0.430 21.710 1.760 ;
    END
  END VPW
  PIN VSS
    DIRECTION INOUT ;
    USE GROUND ;
    SHAPE ABUTMENT ;
    PORT
      LAYER Metal1 ;
        RECT 1.310 0.300 1.650 1.050 ;
        RECT 3.150 0.300 3.490 1.075 ;
        RECT 7.455 0.300 7.795 1.075 ;
        RECT 16.555 0.300 16.895 0.835 ;
        RECT 18.550 0.300 18.780 0.890 ;
        RECT 20.790 0.300 21.020 0.890 ;
        RECT 0.000 -0.300 21.280 0.300 ;
    END
  END VSS
  OBS
      LAYER Metal1 ;
        RECT 0.345 2.595 0.575 3.225 ;
        RECT 2.385 2.615 2.615 3.225 ;
        RECT 3.810 3.160 5.115 3.390 ;
        RECT 8.270 3.215 9.915 3.390 ;
        RECT 3.810 2.615 4.040 3.160 ;
        RECT 0.345 2.360 2.090 2.595 ;
        RECT 1.860 1.510 2.090 2.360 ;
        RECT 0.245 1.280 2.090 1.510 ;
        RECT 2.385 2.380 4.040 2.615 ;
        RECT 0.245 0.810 0.475 1.280 ;
        RECT 2.385 1.150 2.620 2.380 ;
        RECT 2.385 0.810 2.715 1.150 ;
        RECT 4.270 0.790 4.610 2.930 ;
        RECT 4.885 1.930 5.115 3.160 ;
        RECT 6.115 3.160 9.915 3.215 ;
        RECT 6.115 2.985 8.500 3.160 ;
        RECT 5.345 1.995 5.575 2.985 ;
        RECT 6.115 2.240 6.455 2.985 ;
        RECT 9.035 2.455 9.375 2.930 ;
        RECT 9.685 2.775 9.915 3.160 ;
        RECT 10.845 3.065 12.315 3.295 ;
        RECT 10.845 2.775 11.075 3.065 ;
        RECT 9.685 2.540 11.075 2.775 ;
        RECT 7.015 2.310 9.375 2.455 ;
        RECT 11.305 2.310 11.645 2.780 ;
        RECT 7.015 2.225 11.645 2.310 ;
        RECT 9.035 2.080 11.645 2.225 ;
        RECT 11.930 2.550 12.895 2.780 ;
        RECT 13.630 2.775 13.860 2.845 ;
        RECT 15.370 2.775 15.600 2.885 ;
        RECT 5.345 1.765 8.235 1.995 ;
        RECT 5.345 0.790 5.675 1.765 ;
        RECT 6.000 1.305 8.340 1.535 ;
        RECT 8.110 0.760 8.340 1.305 ;
        RECT 9.875 0.990 10.215 2.080 ;
        RECT 10.810 0.760 11.040 1.615 ;
        RECT 11.930 1.130 12.160 2.550 ;
        RECT 13.630 2.540 15.600 2.775 ;
        RECT 13.630 1.220 13.860 2.540 ;
        RECT 17.830 2.105 18.060 3.380 ;
        RECT 15.755 1.860 18.060 2.105 ;
        RECT 17.730 1.840 18.060 1.860 ;
        RECT 15.880 1.395 17.335 1.630 ;
        RECT 17.730 1.500 19.690 1.840 ;
        RECT 11.270 0.790 12.160 1.130 ;
        RECT 12.555 0.990 14.495 1.220 ;
        RECT 8.110 0.530 11.040 0.760 ;
        RECT 11.930 0.760 12.160 0.790 ;
        RECT 15.880 0.760 16.110 1.395 ;
        RECT 11.930 0.530 16.110 0.760 ;
        RECT 17.730 0.550 17.960 1.500 ;
  END
END gf180mcu_fd_sc_mcu7t5v0__dffsnq_2

#--------EOF---------

MACRO gf180mcu_fd_sc_mcu7t5v0__dlya_1
  CLASS core ;
  FOREIGN gf180mcu_fd_sc_mcu7t5v0__dlya_1 ;
  ORIGIN 0.000 0.000 ;
  SIZE 6.160 BY 3.920 ;
  SYMMETRY X Y ;
  SITE GF018hv5v_mcu_sc7 ;
  PIN I
    DIRECTION INPUT ;
    ANTENNAGATEAREA 0.396000 ;
    PORT
      LAYER Metal1 ;
        RECT 0.705 1.210 1.845 1.610 ;
    END
  END I
  PIN Z
    DIRECTION OUTPUT ;
    ANTENNADIFFAREA 0.897600 ;
    PORT
      LAYER Metal1 ;
        RECT 5.650 0.550 6.020 3.380 ;
    END
  END Z
  PIN VDD
    DIRECTION INOUT ;
    USE POWER ;
    SHAPE ABUTMENT ;
    PORT
      LAYER Metal1 ;
        RECT 0.000 3.620 6.160 4.220 ;
        RECT 1.210 2.540 1.550 3.620 ;
        RECT 4.645 2.530 4.875 3.620 ;
    END
  END VDD
  PIN VNW
    DIRECTION INOUT ;
    USE POWER ;
    PORT
      LAYER Nwell ;
        RECT -0.430 1.760 6.590 4.350 ;
    END
  END VNW
  PIN VPW
    DIRECTION INOUT ;
    USE GROUND ;
    PORT
      LAYER Pwell ;
        RECT -0.430 -0.430 6.590 1.760 ;
    END
  END VPW
  PIN VSS
    DIRECTION INOUT ;
    USE GROUND ;
    SHAPE ABUTMENT ;
    PORT
      LAYER Metal1 ;
        RECT 1.365 0.300 1.595 0.980 ;
        RECT 4.545 0.300 4.775 0.690 ;
        RECT 0.000 -0.300 6.160 0.300 ;
    END
  END VSS
  OBS
      LAYER Metal1 ;
        RECT 0.245 2.255 0.475 2.825 ;
        RECT 0.245 2.025 2.135 2.255 ;
        RECT 0.245 0.640 0.475 2.025 ;
        RECT 2.385 1.725 2.615 2.825 ;
        RECT 3.105 2.280 3.335 2.710 ;
        RECT 3.105 2.050 5.215 2.280 ;
        RECT 2.385 1.495 4.180 1.725 ;
        RECT 2.385 0.640 2.715 1.495 ;
        RECT 4.985 1.180 5.215 2.050 ;
        RECT 3.870 0.950 5.215 1.180 ;
        RECT 3.870 0.765 4.105 0.950 ;
        RECT 3.145 0.530 4.105 0.765 ;
  END
END gf180mcu_fd_sc_mcu7t5v0__dlya_1

#--------EOF---------

MACRO gf180mcu_fd_sc_mcu7t5v0__dlya_2
  CLASS core ;
  FOREIGN gf180mcu_fd_sc_mcu7t5v0__dlya_2 ;
  ORIGIN 0.000 0.000 ;
  SIZE 7.280 BY 3.920 ;
  SYMMETRY X Y ;
  SITE GF018hv5v_mcu_sc7 ;
  PIN I
    DIRECTION INPUT ;
    ANTENNAGATEAREA 0.396000 ;
    PORT
      LAYER Metal1 ;
        RECT 0.705 1.210 1.590 1.610 ;
    END
  END I
  PIN Z
    DIRECTION OUTPUT ;
    ANTENNADIFFAREA 1.188900 ;
    PORT
      LAYER Metal1 ;
        RECT 5.660 0.805 6.070 3.380 ;
    END
  END Z
  PIN VDD
    DIRECTION INOUT ;
    USE POWER ;
    SHAPE ABUTMENT ;
    PORT
      LAYER Metal1 ;
        RECT 0.000 3.620 7.280 4.220 ;
        RECT 1.210 2.540 1.550 3.620 ;
        RECT 4.640 2.530 4.870 3.620 ;
        RECT 6.785 2.530 7.020 3.620 ;
    END
  END VDD
  PIN VNW
    DIRECTION INOUT ;
    USE POWER ;
    PORT
      LAYER Nwell ;
        RECT -0.430 1.760 7.710 4.350 ;
    END
  END VNW
  PIN VPW
    DIRECTION INOUT ;
    USE GROUND ;
    PORT
      LAYER Pwell ;
        RECT -0.430 -0.430 7.710 1.760 ;
    END
  END VPW
  PIN VSS
    DIRECTION INOUT ;
    USE GROUND ;
    SHAPE ABUTMENT ;
    PORT
      LAYER Metal1 ;
        RECT 1.365 0.300 1.595 0.980 ;
        RECT 4.545 0.300 4.775 0.690 ;
        RECT 6.785 0.300 7.015 1.145 ;
        RECT 0.000 -0.300 7.280 0.300 ;
    END
  END VSS
  OBS
      LAYER Metal1 ;
        RECT 0.245 2.310 0.475 2.825 ;
        RECT 0.245 2.075 2.035 2.310 ;
        RECT 0.245 0.640 0.475 2.075 ;
        RECT 1.805 1.970 2.035 2.075 ;
        RECT 2.385 1.790 2.615 2.825 ;
        RECT 3.105 2.280 3.335 2.710 ;
        RECT 3.105 2.050 5.375 2.280 ;
        RECT 2.385 1.550 4.055 1.790 ;
        RECT 2.385 0.640 2.715 1.550 ;
        RECT 5.145 1.250 5.375 2.050 ;
        RECT 4.050 1.020 5.375 1.250 ;
        RECT 4.050 0.765 4.285 1.020 ;
        RECT 3.145 0.530 4.285 0.765 ;
  END
END gf180mcu_fd_sc_mcu7t5v0__dlya_2

#--------EOF---------

MACRO gf180mcu_fd_sc_mcu7t5v0__dlyb_1
  CLASS core ;
  FOREIGN gf180mcu_fd_sc_mcu7t5v0__dlyb_1 ;
  ORIGIN 0.000 0.000 ;
  SIZE 8.960 BY 3.920 ;
  SYMMETRY X Y ;
  SITE GF018hv5v_mcu_sc7 ;
  PIN I
    DIRECTION INPUT ;
    ANTENNAGATEAREA 0.396000 ;
    PORT
      LAYER Metal1 ;
        RECT 0.930 1.200 3.355 1.600 ;
    END
  END I
  PIN Z
    DIRECTION OUTPUT ;
    ANTENNADIFFAREA 0.897600 ;
    PORT
      LAYER Metal1 ;
        RECT 8.215 2.710 8.600 3.195 ;
        RECT 6.810 2.330 8.600 2.710 ;
        RECT 8.370 0.675 8.600 2.330 ;
    END
  END Z
  PIN VDD
    DIRECTION INOUT ;
    USE POWER ;
    SHAPE ABUTMENT ;
    PORT
      LAYER Metal1 ;
        RECT 0.000 3.620 8.960 4.220 ;
        RECT 1.485 3.285 1.825 3.620 ;
        RECT 6.565 3.175 6.905 3.620 ;
    END
  END VDD
  PIN VNW
    DIRECTION INOUT ;
    USE POWER ;
    PORT
      LAYER Nwell ;
        RECT -0.430 1.760 9.390 4.350 ;
    END
  END VNW
  PIN VPW
    DIRECTION INOUT ;
    USE GROUND ;
    PORT
      LAYER Pwell ;
        RECT -0.430 -0.430 9.390 1.760 ;
    END
  END VPW
  PIN VSS
    DIRECTION INOUT ;
    USE GROUND ;
    SHAPE ABUTMENT ;
    PORT
      LAYER Metal1 ;
        RECT 1.585 0.300 1.925 0.635 ;
        RECT 6.720 0.300 6.950 0.690 ;
        RECT 0.000 -0.300 8.960 0.300 ;
    END
  END VSS
  OBS
      LAYER Metal1 ;
        RECT 0.245 2.405 0.585 3.105 ;
        RECT 0.245 2.065 3.265 2.405 ;
        RECT 0.245 0.900 0.475 2.065 ;
        RECT 3.720 1.910 3.950 3.160 ;
        RECT 4.540 2.465 4.770 3.160 ;
        RECT 4.540 2.235 6.155 2.465 ;
        RECT 3.720 1.680 5.485 1.910 ;
        RECT 0.245 0.670 0.585 0.900 ;
        RECT 3.720 0.770 4.105 1.680 ;
        RECT 5.835 1.625 6.155 2.235 ;
        RECT 5.835 1.395 7.975 1.625 ;
        RECT 5.835 1.055 6.155 1.395 ;
        RECT 4.540 0.715 6.155 1.055 ;
  END
END gf180mcu_fd_sc_mcu7t5v0__dlyb_1

#--------EOF---------

MACRO gf180mcu_fd_sc_mcu7t5v0__dlyb_2
  CLASS core ;
  FOREIGN gf180mcu_fd_sc_mcu7t5v0__dlyb_2 ;
  ORIGIN 0.000 0.000 ;
  SIZE 10.080 BY 3.920 ;
  SYMMETRY X Y ;
  SITE GF018hv5v_mcu_sc7 ;
  PIN I
    DIRECTION INPUT ;
    ANTENNAGATEAREA 0.396000 ;
    PORT
      LAYER Metal1 ;
        RECT 0.930 1.200 3.355 1.600 ;
    END
  END I
  PIN Z
    DIRECTION OUTPUT ;
    ANTENNADIFFAREA 1.060800 ;
    PORT
      LAYER Metal1 ;
        RECT 8.420 2.340 8.860 3.390 ;
        RECT 8.420 2.105 9.380 2.340 ;
        RECT 8.930 1.215 9.380 2.105 ;
        RECT 8.370 0.960 9.380 1.215 ;
        RECT 8.370 0.530 8.600 0.960 ;
    END
  END Z
  PIN VDD
    DIRECTION INOUT ;
    USE POWER ;
    SHAPE ABUTMENT ;
    PORT
      LAYER Metal1 ;
        RECT 0.000 3.620 10.080 4.220 ;
        RECT 1.485 3.285 1.825 3.620 ;
        RECT 6.565 3.175 7.685 3.620 ;
        RECT 7.345 2.530 7.685 3.175 ;
        RECT 9.435 2.570 9.775 3.620 ;
    END
  END VDD
  PIN VNW
    DIRECTION INOUT ;
    USE POWER ;
    PORT
      LAYER Nwell ;
        RECT -0.430 1.760 10.510 4.350 ;
    END
  END VNW
  PIN VPW
    DIRECTION INOUT ;
    USE GROUND ;
    PORT
      LAYER Pwell ;
        RECT -0.430 -0.430 10.510 1.760 ;
    END
  END VPW
  PIN VSS
    DIRECTION INOUT ;
    USE GROUND ;
    SHAPE ABUTMENT ;
    PORT
      LAYER Metal1 ;
        RECT 1.585 0.300 1.925 0.635 ;
        RECT 6.720 0.300 6.950 0.690 ;
        RECT 9.435 0.300 9.775 0.635 ;
        RECT 0.000 -0.300 10.080 0.300 ;
    END
  END VSS
  OBS
      LAYER Metal1 ;
        RECT 0.245 2.405 0.585 3.105 ;
        RECT 0.245 2.065 3.265 2.405 ;
        RECT 0.245 0.900 0.475 2.065 ;
        RECT 3.720 1.910 3.950 3.160 ;
        RECT 4.540 2.465 4.770 3.160 ;
        RECT 4.540 2.235 6.155 2.465 ;
        RECT 3.720 1.680 5.485 1.910 ;
        RECT 5.835 1.855 6.155 2.235 ;
        RECT 0.245 0.670 0.585 0.900 ;
        RECT 3.720 0.770 4.105 1.680 ;
        RECT 5.835 1.625 8.540 1.855 ;
        RECT 5.835 1.055 6.155 1.625 ;
        RECT 4.540 0.715 6.155 1.055 ;
  END
END gf180mcu_fd_sc_mcu7t5v0__dlyb_2

#--------EOF---------

MACRO gf180mcu_fd_sc_mcu7t5v0__dlyc_1
  CLASS core ;
  FOREIGN gf180mcu_fd_sc_mcu7t5v0__dlyc_1 ;
  ORIGIN 0.000 0.000 ;
  SIZE 14.000 BY 3.920 ;
  SYMMETRY X Y ;
  SITE GF018hv5v_mcu_sc7 ;
  PIN I
    DIRECTION INPUT ;
    ANTENNAGATEAREA 0.396000 ;
    PORT
      LAYER Metal1 ;
        RECT 0.905 1.200 3.330 1.600 ;
    END
  END I
  PIN Z
    DIRECTION OUTPUT ;
    ANTENNADIFFAREA 0.897600 ;
    PORT
      LAYER Metal1 ;
        RECT 13.370 2.710 13.755 3.195 ;
        RECT 11.965 2.330 13.755 2.710 ;
        RECT 13.525 0.675 13.755 2.330 ;
    END
  END Z
  PIN VDD
    DIRECTION INOUT ;
    USE POWER ;
    SHAPE ABUTMENT ;
    PORT
      LAYER Metal1 ;
        RECT 0.000 3.620 14.000 4.220 ;
        RECT 1.460 3.285 1.800 3.620 ;
        RECT 6.440 3.285 6.780 3.620 ;
        RECT 11.720 3.175 12.060 3.620 ;
    END
  END VDD
  PIN VNW
    DIRECTION INOUT ;
    USE POWER ;
    PORT
      LAYER Nwell ;
        RECT -0.430 1.760 14.430 4.350 ;
    END
  END VNW
  PIN VPW
    DIRECTION INOUT ;
    USE GROUND ;
    PORT
      LAYER Pwell ;
        RECT -0.430 -0.430 14.430 1.760 ;
    END
  END VPW
  PIN VSS
    DIRECTION INOUT ;
    USE GROUND ;
    SHAPE ABUTMENT ;
    PORT
      LAYER Metal1 ;
        RECT 1.560 0.300 1.900 0.635 ;
        RECT 6.640 0.300 6.980 0.635 ;
        RECT 12.115 0.300 12.345 0.690 ;
        RECT 0.000 -0.300 14.000 0.300 ;
    END
  END VSS
  OBS
      LAYER Metal1 ;
        RECT 0.220 2.405 0.560 3.105 ;
        RECT 0.220 2.065 3.240 2.405 ;
        RECT 0.220 0.670 0.560 2.065 ;
        RECT 3.695 1.805 3.925 3.160 ;
        RECT 4.360 2.875 5.765 3.105 ;
        RECT 3.695 1.465 5.305 1.805 ;
        RECT 5.535 1.750 5.765 2.875 ;
        RECT 8.875 1.965 9.260 3.160 ;
        RECT 9.695 2.465 9.925 3.160 ;
        RECT 9.695 2.235 11.665 2.465 ;
        RECT 5.535 1.520 8.090 1.750 ;
        RECT 8.875 1.535 11.055 1.965 ;
        RECT 11.345 1.625 11.665 2.235 ;
        RECT 3.695 0.770 4.080 1.465 ;
        RECT 5.535 1.000 5.765 1.520 ;
        RECT 4.460 0.770 5.765 1.000 ;
        RECT 8.875 0.715 9.105 1.535 ;
        RECT 11.345 1.395 13.130 1.625 ;
        RECT 11.345 1.055 11.665 1.395 ;
        RECT 9.695 0.715 11.665 1.055 ;
  END
END gf180mcu_fd_sc_mcu7t5v0__dlyc_1

#--------EOF---------

MACRO gf180mcu_fd_sc_mcu7t5v0__dlyc_2
  CLASS core ;
  FOREIGN gf180mcu_fd_sc_mcu7t5v0__dlyc_2 ;
  ORIGIN 0.000 0.000 ;
  SIZE 15.120 BY 3.920 ;
  SYMMETRY X Y ;
  SITE GF018hv5v_mcu_sc7 ;
  PIN I
    DIRECTION INPUT ;
    ANTENNAGATEAREA 0.396000 ;
    PORT
      LAYER Metal1 ;
        RECT 0.930 1.200 3.350 1.600 ;
    END
  END I
  PIN Z
    DIRECTION OUTPUT ;
    ANTENNADIFFAREA 1.281700 ;
    PORT
      LAYER Metal1 ;
        RECT 13.395 0.675 13.910 3.195 ;
    END
  END Z
  PIN VDD
    DIRECTION INOUT ;
    USE POWER ;
    SHAPE ABUTMENT ;
    PORT
      LAYER Metal1 ;
        RECT 0.000 3.620 15.120 4.220 ;
        RECT 1.485 3.285 1.825 3.620 ;
        RECT 6.465 3.285 6.805 3.620 ;
        RECT 11.745 3.175 12.085 3.620 ;
        RECT 14.465 2.705 14.805 3.620 ;
    END
  END VDD
  PIN VNW
    DIRECTION INOUT ;
    USE POWER ;
    PORT
      LAYER Nwell ;
        RECT -0.430 1.760 15.550 4.350 ;
    END
  END VNW
  PIN VPW
    DIRECTION INOUT ;
    USE GROUND ;
    PORT
      LAYER Pwell ;
        RECT -0.430 -0.430 15.550 1.760 ;
    END
  END VPW
  PIN VSS
    DIRECTION INOUT ;
    USE GROUND ;
    SHAPE ABUTMENT ;
    PORT
      LAYER Metal1 ;
        RECT 1.585 0.300 1.925 0.635 ;
        RECT 6.665 0.300 7.005 0.635 ;
        RECT 11.925 0.300 12.155 0.690 ;
        RECT 14.520 0.300 14.750 0.690 ;
        RECT 0.000 -0.300 15.120 0.300 ;
    END
  END VSS
  OBS
      LAYER Metal1 ;
        RECT 0.245 2.405 0.585 3.105 ;
        RECT 0.245 2.065 3.265 2.405 ;
        RECT 0.245 0.900 0.475 2.065 ;
        RECT 3.720 1.805 3.950 3.160 ;
        RECT 4.385 2.875 5.790 3.105 ;
        RECT 3.720 1.465 5.330 1.805 ;
        RECT 5.560 1.750 5.790 2.875 ;
        RECT 8.900 2.820 9.285 3.160 ;
        RECT 8.900 1.875 9.130 2.820 ;
        RECT 9.720 2.465 9.950 3.160 ;
        RECT 9.720 2.235 11.690 2.465 ;
        RECT 5.560 1.520 8.115 1.750 ;
        RECT 8.900 1.535 11.080 1.875 ;
        RECT 11.370 1.730 11.690 2.235 ;
        RECT 0.245 0.670 0.585 0.900 ;
        RECT 3.720 0.770 4.105 1.465 ;
        RECT 5.560 1.000 5.790 1.520 ;
        RECT 4.485 0.770 5.790 1.000 ;
        RECT 8.900 0.715 9.130 1.535 ;
        RECT 11.370 1.500 12.810 1.730 ;
        RECT 11.370 1.055 11.690 1.500 ;
        RECT 9.720 0.715 11.690 1.055 ;
  END
END gf180mcu_fd_sc_mcu7t5v0__dlyc_2

#--------EOF---------

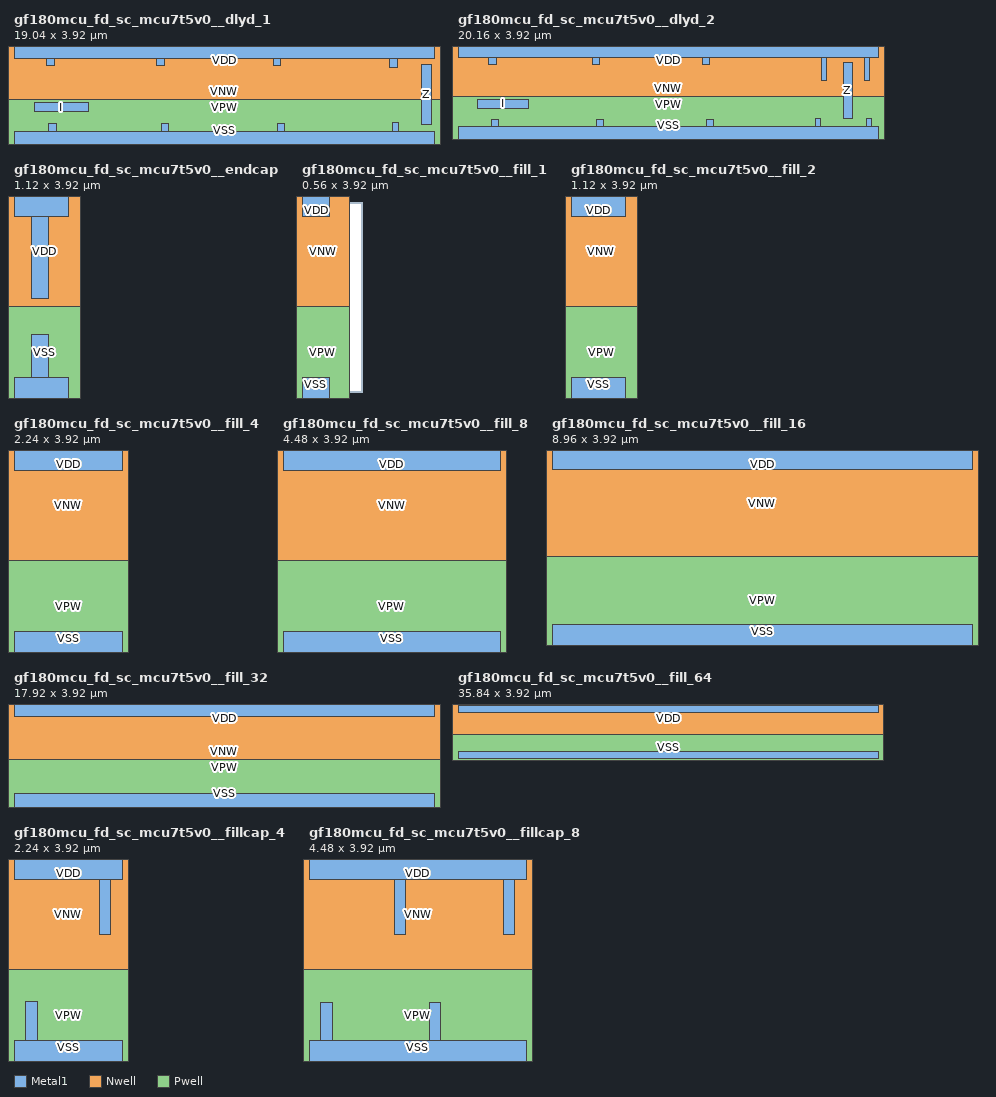
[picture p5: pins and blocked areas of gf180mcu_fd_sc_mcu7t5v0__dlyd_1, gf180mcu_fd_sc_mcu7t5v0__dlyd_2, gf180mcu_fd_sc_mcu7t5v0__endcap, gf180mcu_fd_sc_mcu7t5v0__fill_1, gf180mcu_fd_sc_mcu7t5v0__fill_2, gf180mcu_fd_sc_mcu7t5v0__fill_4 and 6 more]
MACRO gf180mcu_fd_sc_mcu7t5v0__dlyd_1
  CLASS core ;
  FOREIGN gf180mcu_fd_sc_mcu7t5v0__dlyd_1 ;
  ORIGIN 0.000 0.000 ;
  SIZE 19.040 BY 3.920 ;
  SYMMETRY X Y ;
  SITE GF018hv5v_mcu_sc7 ;
  PIN I
    DIRECTION INPUT ;
    ANTENNAGATEAREA 0.396000 ;
    PORT
      LAYER Metal1 ;
        RECT 0.930 1.200 3.355 1.600 ;
    END
  END I
  PIN Z
    DIRECTION OUTPUT ;
    ANTENNADIFFAREA 0.897600 ;
    PORT
      LAYER Metal1 ;
        RECT 18.480 0.600 18.920 3.320 ;
    END
  END Z
  PIN VDD
    DIRECTION INOUT ;
    USE POWER ;
    SHAPE ABUTMENT ;
    PORT
      LAYER Metal1 ;
        RECT 0.000 3.620 19.040 4.220 ;
        RECT 1.485 3.285 1.825 3.620 ;
        RECT 6.465 3.285 6.805 3.620 ;
        RECT 11.745 3.285 12.085 3.620 ;
        RECT 17.025 3.175 17.365 3.620 ;
    END
  END VDD
  PIN VNW
    DIRECTION INOUT ;
    USE POWER ;
    PORT
      LAYER Nwell ;
        RECT -0.430 1.760 19.470 4.350 ;
    END
  END VNW
  PIN VPW
    DIRECTION INOUT ;
    USE GROUND ;
    PORT
      LAYER Pwell ;
        RECT -0.430 -0.430 19.470 1.760 ;
    END
  END VPW
  PIN VSS
    DIRECTION INOUT ;
    USE GROUND ;
    SHAPE ABUTMENT ;
    PORT
      LAYER Metal1 ;
        RECT 1.585 0.300 1.925 0.635 ;
        RECT 6.665 0.300 7.005 0.635 ;
        RECT 11.945 0.300 12.285 0.635 ;
        RECT 17.180 0.300 17.410 0.690 ;
        RECT 0.000 -0.300 19.040 0.300 ;
    END
  END VSS
  OBS
      LAYER Metal1 ;
        RECT 0.245 2.405 0.585 3.105 ;
        RECT 0.245 2.065 3.265 2.405 ;
        RECT 0.245 0.900 0.475 2.065 ;
        RECT 3.720 1.805 3.950 3.160 ;
        RECT 4.385 2.875 5.790 3.105 ;
        RECT 3.720 1.465 5.330 1.805 ;
        RECT 5.560 1.750 5.790 2.875 ;
        RECT 8.900 2.820 9.285 3.160 ;
        RECT 9.665 2.875 11.070 3.105 ;
        RECT 8.900 1.805 9.130 2.820 ;
        RECT 5.560 1.520 8.115 1.750 ;
        RECT 0.245 0.670 0.585 0.900 ;
        RECT 3.720 0.770 4.105 1.465 ;
        RECT 5.560 1.000 5.790 1.520 ;
        RECT 4.485 0.770 5.790 1.000 ;
        RECT 8.900 1.465 10.610 1.805 ;
        RECT 10.840 1.750 11.070 2.875 ;
        RECT 14.180 2.820 14.565 3.160 ;
        RECT 14.180 1.875 14.410 2.820 ;
        RECT 15.000 2.465 15.230 3.160 ;
        RECT 15.000 2.235 16.880 2.465 ;
        RECT 10.840 1.520 13.395 1.750 ;
        RECT 14.180 1.535 16.360 1.875 ;
        RECT 16.650 1.625 16.880 2.235 ;
        RECT 8.900 0.715 9.130 1.465 ;
        RECT 10.840 1.000 11.070 1.520 ;
        RECT 9.765 0.770 11.070 1.000 ;
        RECT 14.180 0.715 14.410 1.535 ;
        RECT 16.650 1.395 18.185 1.625 ;
        RECT 16.650 1.000 16.880 1.395 ;
        RECT 14.945 0.770 16.880 1.000 ;
  END
END gf180mcu_fd_sc_mcu7t5v0__dlyd_1

#--------EOF---------

MACRO gf180mcu_fd_sc_mcu7t5v0__dlyd_2
  CLASS core ;
  FOREIGN gf180mcu_fd_sc_mcu7t5v0__dlyd_2 ;
  ORIGIN 0.000 0.000 ;
  SIZE 20.160 BY 3.920 ;
  SYMMETRY X Y ;
  SITE GF018hv5v_mcu_sc7 ;
  PIN I
    DIRECTION INPUT ;
    ANTENNAGATEAREA 0.396000 ;
    PORT
      LAYER Metal1 ;
        RECT 0.930 1.200 3.395 1.600 ;
    END
  END I
  PIN Z
    DIRECTION OUTPUT ;
    ANTENNADIFFAREA 1.060800 ;
    PORT
      LAYER Metal1 ;
        RECT 18.480 0.675 18.950 3.380 ;
    END
  END Z
  PIN VDD
    DIRECTION INOUT ;
    USE POWER ;
    SHAPE ABUTMENT ;
    PORT
      LAYER Metal1 ;
        RECT 0.000 3.620 20.160 4.220 ;
        RECT 1.485 3.285 1.825 3.620 ;
        RECT 6.465 3.285 6.805 3.620 ;
        RECT 11.745 3.285 12.085 3.620 ;
        RECT 17.460 2.530 17.690 3.620 ;
        RECT 19.500 2.530 19.730 3.620 ;
    END
  END VDD
  PIN VNW
    DIRECTION INOUT ;
    USE POWER ;
    PORT
      LAYER Nwell ;
        RECT -0.430 1.760 20.590 4.350 ;
    END
  END VNW
  PIN VPW
    DIRECTION INOUT ;
    USE GROUND ;
    PORT
      LAYER Pwell ;
        RECT -0.430 -0.430 20.590 1.760 ;
    END
  END VPW
  PIN VSS
    DIRECTION INOUT ;
    USE GROUND ;
    SHAPE ABUTMENT ;
    PORT
      LAYER Metal1 ;
        RECT 1.585 0.300 1.925 0.635 ;
        RECT 6.665 0.300 7.005 0.635 ;
        RECT 11.945 0.300 12.285 0.635 ;
        RECT 17.180 0.300 17.410 0.690 ;
        RECT 19.600 0.300 19.830 0.690 ;
        RECT 0.000 -0.300 20.160 0.300 ;
    END
  END VSS
  OBS
      LAYER Metal1 ;
        RECT 0.245 2.405 0.585 3.105 ;
        RECT 0.245 2.065 3.265 2.405 ;
        RECT 0.245 0.900 0.475 2.065 ;
        RECT 3.720 1.805 3.950 3.160 ;
        RECT 4.385 2.875 5.790 3.105 ;
        RECT 3.720 1.465 5.330 1.805 ;
        RECT 5.560 1.750 5.790 2.875 ;
        RECT 8.900 2.820 9.285 3.160 ;
        RECT 9.665 2.875 11.070 3.105 ;
        RECT 8.900 1.805 9.130 2.820 ;
        RECT 5.560 1.520 8.115 1.750 ;
        RECT 0.245 0.670 0.585 0.900 ;
        RECT 3.720 0.770 4.105 1.465 ;
        RECT 5.560 1.000 5.790 1.520 ;
        RECT 4.485 0.770 5.790 1.000 ;
        RECT 8.900 1.465 10.610 1.805 ;
        RECT 10.840 1.750 11.070 2.875 ;
        RECT 14.180 2.820 14.565 3.160 ;
        RECT 14.180 1.875 14.410 2.820 ;
        RECT 15.000 2.465 15.230 3.160 ;
        RECT 15.000 2.235 16.880 2.465 ;
        RECT 10.840 1.520 13.395 1.750 ;
        RECT 14.180 1.535 16.360 1.875 ;
        RECT 16.650 1.625 16.880 2.235 ;
        RECT 8.900 0.715 9.130 1.465 ;
        RECT 10.840 1.000 11.070 1.520 ;
        RECT 9.765 0.770 11.070 1.000 ;
        RECT 14.180 0.715 14.410 1.535 ;
        RECT 16.650 1.395 18.185 1.625 ;
        RECT 16.650 1.000 16.880 1.395 ;
        RECT 14.945 0.770 16.880 1.000 ;
  END
END gf180mcu_fd_sc_mcu7t5v0__dlyd_2

#--------EOF---------

MACRO gf180mcu_fd_sc_mcu7t5v0__endcap
  CLASS ENDCAP PRE ;
  FOREIGN gf180mcu_fd_sc_mcu7t5v0__endcap ;
  ORIGIN 0.000 0.000 ;
  SIZE 1.120 BY 3.920 ;
  SYMMETRY X Y ;
  SITE GF018hv5v_mcu_sc7 ;
  PIN VDD
    DIRECTION INOUT ;
    USE POWER ;
    SHAPE ABUTMENT ;
    PORT
      LAYER Nwell ;
        RECT -0.430 1.760 1.550 4.350 ;
      LAYER Metal1 ;
        RECT 0.000 3.620 1.120 4.220 ;
        RECT 0.370 1.920 0.710 3.620 ;
    END
  END VDD
  PIN VSS
    DIRECTION INOUT ;
    USE GROUND ;
    SHAPE ABUTMENT ;
    PORT
      LAYER Pwell ;
        RECT -0.430 -0.430 1.550 1.760 ;
      LAYER Metal1 ;
        RECT 0.370 0.300 0.710 1.190 ;
        RECT 0.000 -0.300 1.120 0.300 ;
    END
  END VSS
END gf180mcu_fd_sc_mcu7t5v0__endcap

#--------EOF---------

MACRO gf180mcu_fd_sc_mcu7t5v0__fill_1
  CLASS core SPACER ;
  FOREIGN gf180mcu_fd_sc_mcu7t5v0__fill_1 ;
  ORIGIN 0.000 0.000 ;
  SIZE 0.560 BY 3.920 ;
  SYMMETRY X Y ;
  SITE GF018hv5v_mcu_sc7 ;
  PIN VDD
    DIRECTION INOUT ;
    USE POWER ;
    SHAPE ABUTMENT ;
    PORT
      LAYER Metal1 ;
        RECT 0.000 3.620 0.560 4.220 ;
    END
  END VDD
  PIN VNW
    DIRECTION INOUT ;
    USE POWER ;
    PORT
      LAYER Nwell ;
        RECT -0.430 1.760 0.990 4.350 ;
    END
  END VNW
  PIN VPW
    DIRECTION INOUT ;
    USE GROUND ;
    PORT
      LAYER Pwell ;
        RECT -0.430 -0.430 0.990 1.760 ;
    END
  END VPW
  PIN VSS
    DIRECTION INOUT ;
    USE GROUND ;
    SHAPE ABUTMENT ;
    PORT
      LAYER Metal1 ;
        RECT 0.000 -0.300 0.560 0.300 ;
    END
  END VSS
END gf180mcu_fd_sc_mcu7t5v0__fill_1

#--------EOF---------

MACRO gf180mcu_fd_sc_mcu7t5v0__fill_2
  CLASS core SPACER ;
  FOREIGN gf180mcu_fd_sc_mcu7t5v0__fill_2 ;
  ORIGIN 0.000 0.000 ;
  SIZE 1.120 BY 3.920 ;
  SYMMETRY X Y ;
  SITE GF018hv5v_mcu_sc7 ;
  PIN VDD
    DIRECTION INOUT ;
    USE POWER ;
    SHAPE ABUTMENT ;
    PORT
      LAYER Metal1 ;
        RECT 0.000 3.620 1.120 4.220 ;
    END
  END VDD
  PIN VNW
    DIRECTION INOUT ;
    USE POWER ;
    PORT
      LAYER Nwell ;
        RECT -0.430 1.760 1.550 4.350 ;
    END
  END VNW
  PIN VPW
    DIRECTION INOUT ;
    USE GROUND ;
    PORT
      LAYER Pwell ;
        RECT -0.430 -0.430 1.550 1.760 ;
    END
  END VPW
  PIN VSS
    DIRECTION INOUT ;
    USE GROUND ;
    SHAPE ABUTMENT ;
    PORT
      LAYER Metal1 ;
        RECT 0.000 -0.300 1.120 0.300 ;
    END
  END VSS
END gf180mcu_fd_sc_mcu7t5v0__fill_2

#--------EOF---------

MACRO gf180mcu_fd_sc_mcu7t5v0__fill_4
  CLASS core SPACER ;
  FOREIGN gf180mcu_fd_sc_mcu7t5v0__fill_4 ;
  ORIGIN 0.000 0.000 ;
  SIZE 2.240 BY 3.920 ;
  SYMMETRY X Y ;
  SITE GF018hv5v_mcu_sc7 ;
  PIN VDD
    DIRECTION INOUT ;
    USE POWER ;
    SHAPE ABUTMENT ;
    PORT
      LAYER Metal1 ;
        RECT 0.000 3.620 2.240 4.220 ;
    END
  END VDD
  PIN VNW
    DIRECTION INOUT ;
    USE POWER ;
    PORT
      LAYER Nwell ;
        RECT -0.430 1.760 2.670 4.350 ;
    END
  END VNW
  PIN VPW
    DIRECTION INOUT ;
    USE GROUND ;
    PORT
      LAYER Pwell ;
        RECT -0.430 -0.430 2.670 1.760 ;
    END
  END VPW
  PIN VSS
    DIRECTION INOUT ;
    USE GROUND ;
    SHAPE ABUTMENT ;
    PORT
      LAYER Metal1 ;
        RECT 0.000 -0.300 2.240 0.300 ;
    END
  END VSS
END gf180mcu_fd_sc_mcu7t5v0__fill_4

#--------EOF---------

MACRO gf180mcu_fd_sc_mcu7t5v0__fill_8
  CLASS core SPACER ;
  FOREIGN gf180mcu_fd_sc_mcu7t5v0__fill_8 ;
  ORIGIN 0.000 0.000 ;
  SIZE 4.480 BY 3.920 ;
  SYMMETRY X Y ;
  SITE GF018hv5v_mcu_sc7 ;
  PIN VDD
    DIRECTION INOUT ;
    USE POWER ;
    SHAPE ABUTMENT ;
    PORT
      LAYER Metal1 ;
        RECT 0.000 3.620 4.480 4.220 ;
    END
  END VDD
  PIN VNW
    DIRECTION INOUT ;
    USE POWER ;
    PORT
      LAYER Nwell ;
        RECT -0.430 1.760 4.910 4.350 ;
    END
  END VNW
  PIN VPW
    DIRECTION INOUT ;
    USE GROUND ;
    PORT
      LAYER Pwell ;
        RECT -0.430 -0.430 4.910 1.760 ;
    END
  END VPW
  PIN VSS
    DIRECTION INOUT ;
    USE GROUND ;
    SHAPE ABUTMENT ;
    PORT
      LAYER Metal1 ;
        RECT 0.000 -0.300 4.480 0.300 ;
    END
  END VSS
END gf180mcu_fd_sc_mcu7t5v0__fill_8

#--------EOF---------

MACRO gf180mcu_fd_sc_mcu7t5v0__fill_16
  CLASS core SPACER ;
  FOREIGN gf180mcu_fd_sc_mcu7t5v0__fill_16 ;
  ORIGIN 0.000 0.000 ;
  SIZE 8.960 BY 3.920 ;
  SYMMETRY X Y ;
  SITE GF018hv5v_mcu_sc7 ;
  PIN VDD
    DIRECTION INOUT ;
    USE POWER ;
    SHAPE ABUTMENT ;
    PORT
      LAYER Metal1 ;
        RECT 0.000 3.620 8.960 4.220 ;
    END
  END VDD
  PIN VNW
    DIRECTION INOUT ;
    USE POWER ;
    PORT
      LAYER Nwell ;
        RECT -0.430 1.760 9.390 4.350 ;
    END
  END VNW
  PIN VPW
    DIRECTION INOUT ;
    USE GROUND ;
    PORT
      LAYER Pwell ;
        RECT -0.430 -0.430 9.390 1.760 ;
    END
  END VPW
  PIN VSS
    DIRECTION INOUT ;
    USE GROUND ;
    SHAPE ABUTMENT ;
    PORT
      LAYER Metal1 ;
        RECT 0.000 -0.300 8.960 0.300 ;
    END
  END VSS
END gf180mcu_fd_sc_mcu7t5v0__fill_16

#--------EOF---------

MACRO gf180mcu_fd_sc_mcu7t5v0__fill_32
  CLASS core SPACER ;
  FOREIGN gf180mcu_fd_sc_mcu7t5v0__fill_32 ;
  ORIGIN 0.000 0.000 ;
  SIZE 17.920 BY 3.920 ;
  SYMMETRY X Y ;
  SITE GF018hv5v_mcu_sc7 ;
  PIN VDD
    DIRECTION INOUT ;
    USE POWER ;
    SHAPE ABUTMENT ;
    PORT
      LAYER Metal1 ;
        RECT 0.000 3.620 17.920 4.220 ;
    END
  END VDD
  PIN VNW
    DIRECTION INOUT ;
    USE POWER ;
    PORT
      LAYER Nwell ;
        RECT -0.430 1.760 18.350 4.350 ;
    END
  END VNW
  PIN VPW
    DIRECTION INOUT ;
    USE GROUND ;
    PORT
      LAYER Pwell ;
        RECT -0.430 -0.430 18.350 1.760 ;
    END
  END VPW
  PIN VSS
    DIRECTION INOUT ;
    USE GROUND ;
    SHAPE ABUTMENT ;
    PORT
      LAYER Metal1 ;
        RECT 0.000 -0.300 17.920 0.300 ;
    END
  END VSS
END gf180mcu_fd_sc_mcu7t5v0__fill_32

#--------EOF---------

MACRO gf180mcu_fd_sc_mcu7t5v0__fill_64
  CLASS core SPACER ;
  FOREIGN gf180mcu_fd_sc_mcu7t5v0__fill_64 ;
  ORIGIN 0.000 0.000 ;
  SIZE 35.840 BY 3.920 ;
  SYMMETRY X Y ;
  SITE GF018hv5v_mcu_sc7 ;
  PIN VDD
    DIRECTION INOUT ;
    USE POWER ;
    SHAPE ABUTMENT ;
    PORT
      LAYER Metal1 ;
        RECT 0.000 3.620 35.840 4.220 ;
    END
  END VDD
  PIN VNW
    DIRECTION INOUT ;
    USE POWER ;
    PORT
      LAYER Nwell ;
        RECT -0.430 1.760 36.270 4.350 ;
    END
  END VNW
  PIN VPW
    DIRECTION INOUT ;
    USE GROUND ;
    PORT
      LAYER Pwell ;
        RECT -0.430 -0.430 36.270 1.760 ;
    END
  END VPW
  PIN VSS
    DIRECTION INOUT ;
    USE GROUND ;
    SHAPE ABUTMENT ;
    PORT
      LAYER Metal1 ;
        RECT 0.000 -0.300 35.840 0.300 ;
    END
  END VSS
END gf180mcu_fd_sc_mcu7t5v0__fill_64

#--------EOF---------

MACRO gf180mcu_fd_sc_mcu7t5v0__fillcap_4
  CLASS core SPACER ;
  FOREIGN gf180mcu_fd_sc_mcu7t5v0__fillcap_4 ;
  ORIGIN 0.000 0.000 ;
  SIZE 2.240 BY 3.920 ;
  SYMMETRY X Y ;
  SITE GF018hv5v_mcu_sc7 ;
  PIN VDD
    DIRECTION INOUT ;
    USE POWER ;
    SHAPE ABUTMENT ;
    PORT
      LAYER Metal1 ;
        RECT 0.000 3.620 2.240 4.220 ;
        RECT 1.765 2.490 1.995 3.620 ;
    END
  END VDD
  PIN VNW
    DIRECTION INOUT ;
    USE POWER ;
    PORT
      LAYER Nwell ;
        RECT -0.430 1.760 2.670 4.350 ;
    END
  END VNW
  PIN VPW
    DIRECTION INOUT ;
    USE GROUND ;
    PORT
      LAYER Pwell ;
        RECT -0.430 -0.430 2.670 1.760 ;
    END
  END VPW
  PIN VSS
    DIRECTION INOUT ;
    USE GROUND ;
    SHAPE ABUTMENT ;
    PORT
      LAYER Metal1 ;
        RECT 0.245 0.300 0.475 1.095 ;
        RECT 0.000 -0.300 2.240 0.300 ;
    END
  END VSS
  OBS
      LAYER Metal1 ;
        RECT 0.245 1.555 0.475 3.390 ;
        RECT 0.730 1.960 1.995 2.190 ;
        RECT 0.245 1.325 1.520 1.555 ;
        RECT 1.765 0.530 1.995 1.960 ;
  END
END gf180mcu_fd_sc_mcu7t5v0__fillcap_4

#--------EOF---------

MACRO gf180mcu_fd_sc_mcu7t5v0__fillcap_8
  CLASS core SPACER ;
  FOREIGN gf180mcu_fd_sc_mcu7t5v0__fillcap_8 ;
  ORIGIN 0.000 0.000 ;
  SIZE 4.480 BY 3.920 ;
  SYMMETRY X Y ;
  SITE GF018hv5v_mcu_sc7 ;
  PIN VDD
    DIRECTION INOUT ;
    USE POWER ;
    SHAPE ABUTMENT ;
    PORT
      LAYER Metal1 ;
        RECT 0.000 3.620 4.480 4.220 ;
        RECT 1.765 2.490 1.995 3.620 ;
        RECT 4.005 2.490 4.235 3.620 ;
    END
  END VDD
  PIN VNW
    DIRECTION INOUT ;
    USE POWER ;
    PORT
      LAYER Nwell ;
        RECT -0.430 1.760 4.910 4.350 ;
    END
  END VNW
  PIN VPW
    DIRECTION INOUT ;
    USE GROUND ;
    PORT
      LAYER Pwell ;
        RECT -0.430 -0.430 4.910 1.760 ;
    END
  END VPW
  PIN VSS
    DIRECTION INOUT ;
    USE GROUND ;
    SHAPE ABUTMENT ;
    PORT
      LAYER Metal1 ;
        RECT 0.245 0.300 0.475 1.085 ;
        RECT 2.485 0.300 2.715 1.085 ;
        RECT 0.000 -0.300 4.480 0.300 ;
    END
  END VSS
  OBS
      LAYER Metal1 ;
        RECT 0.245 1.555 0.475 3.390 ;
        RECT 0.730 1.960 1.995 2.190 ;
        RECT 0.245 1.325 1.520 1.555 ;
        RECT 1.765 0.530 1.995 1.960 ;
        RECT 2.485 1.555 2.715 3.390 ;
        RECT 2.970 1.960 4.235 2.190 ;
        RECT 2.485 1.325 3.760 1.555 ;
        RECT 4.005 0.530 4.235 1.960 ;
  END
END gf180mcu_fd_sc_mcu7t5v0__fillcap_8

#--------EOF---------

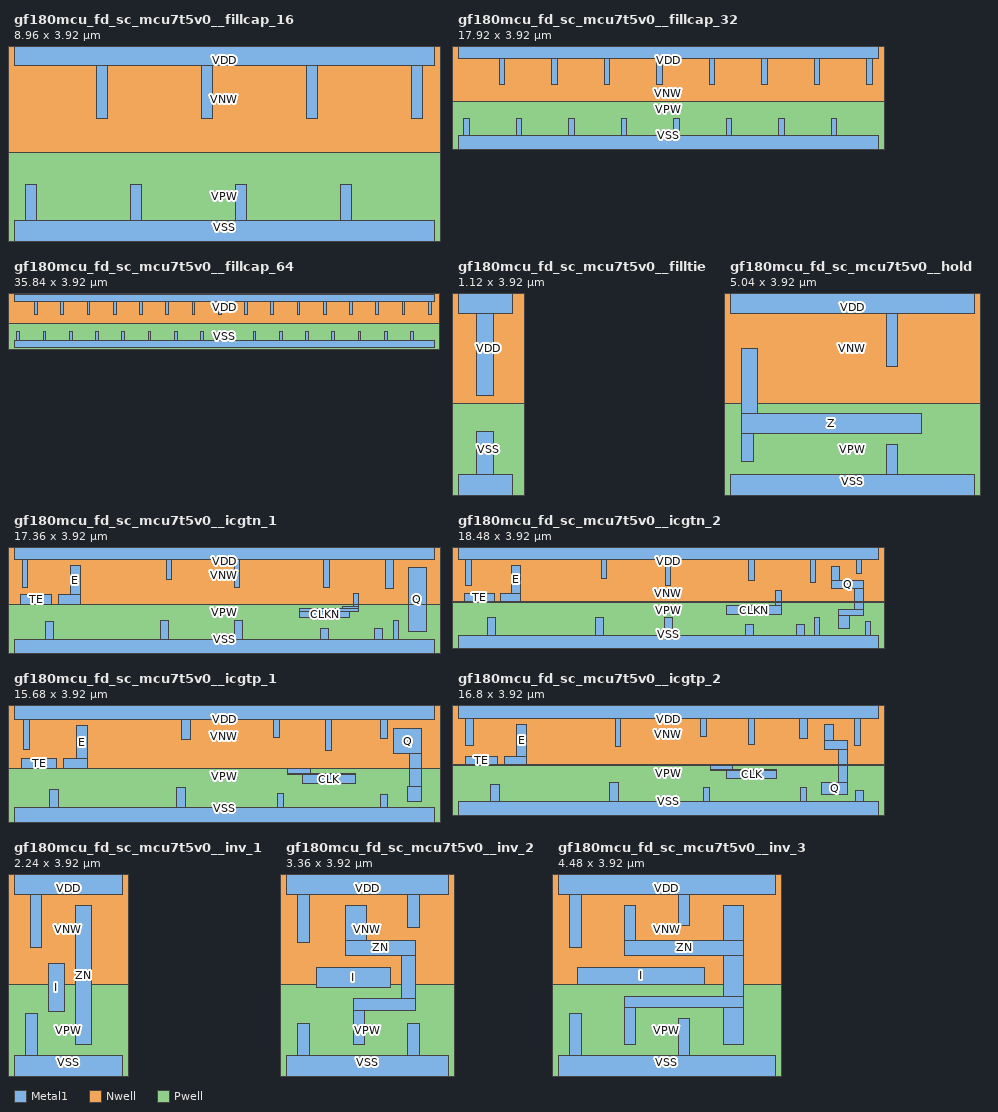
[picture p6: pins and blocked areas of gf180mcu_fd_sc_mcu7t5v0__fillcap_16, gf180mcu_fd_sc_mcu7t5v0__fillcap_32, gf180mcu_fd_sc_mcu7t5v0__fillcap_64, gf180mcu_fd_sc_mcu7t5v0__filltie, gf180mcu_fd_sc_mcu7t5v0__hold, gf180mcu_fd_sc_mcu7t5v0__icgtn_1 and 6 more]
MACRO gf180mcu_fd_sc_mcu7t5v0__fillcap_16
  CLASS core SPACER ;
  FOREIGN gf180mcu_fd_sc_mcu7t5v0__fillcap_16 ;
  ORIGIN 0.000 0.000 ;
  SIZE 8.960 BY 3.920 ;
  SYMMETRY X Y ;
  SITE GF018hv5v_mcu_sc7 ;
  PIN VDD
    DIRECTION INOUT ;
    USE POWER ;
    SHAPE ABUTMENT ;
    PORT
      LAYER Metal1 ;
        RECT 0.000 3.620 8.960 4.220 ;
        RECT 1.765 2.490 1.995 3.620 ;
        RECT 4.005 2.490 4.235 3.620 ;
        RECT 6.245 2.490 6.475 3.620 ;
        RECT 8.485 2.490 8.715 3.620 ;
    END
  END VDD
  PIN VNW
    DIRECTION INOUT ;
    USE POWER ;
    PORT
      LAYER Nwell ;
        RECT -0.430 1.760 9.390 4.350 ;
    END
  END VNW
  PIN VPW
    DIRECTION INOUT ;
    USE GROUND ;
    PORT
      LAYER Pwell ;
        RECT -0.430 -0.430 9.390 1.760 ;
    END
  END VPW
  PIN VSS
    DIRECTION INOUT ;
    USE GROUND ;
    SHAPE ABUTMENT ;
    PORT
      LAYER Metal1 ;
        RECT 0.245 0.300 0.475 1.070 ;
        RECT 2.485 0.300 2.715 1.070 ;
        RECT 4.725 0.300 4.955 1.070 ;
        RECT 6.965 0.300 7.195 1.070 ;
        RECT 0.000 -0.300 8.960 0.300 ;
    END
  END VSS
  OBS
      LAYER Metal1 ;
        RECT 0.245 1.555 0.475 3.390 ;
        RECT 0.730 1.960 1.995 2.190 ;
        RECT 0.245 1.325 1.520 1.555 ;
        RECT 1.765 0.530 1.995 1.960 ;
        RECT 2.485 1.555 2.715 3.390 ;
        RECT 2.970 1.960 4.235 2.190 ;
        RECT 2.485 1.325 3.760 1.555 ;
        RECT 4.005 0.530 4.235 1.960 ;
        RECT 4.725 1.555 4.955 3.390 ;
        RECT 5.210 1.960 6.475 2.190 ;
        RECT 4.725 1.325 6.000 1.555 ;
        RECT 6.245 0.530 6.475 1.960 ;
        RECT 6.965 1.555 7.195 3.390 ;
        RECT 7.450 1.960 8.715 2.190 ;
        RECT 6.965 1.325 8.240 1.555 ;
        RECT 8.485 0.530 8.715 1.960 ;
  END
END gf180mcu_fd_sc_mcu7t5v0__fillcap_16

#--------EOF---------

MACRO gf180mcu_fd_sc_mcu7t5v0__fillcap_32
  CLASS core SPACER ;
  FOREIGN gf180mcu_fd_sc_mcu7t5v0__fillcap_32 ;
  ORIGIN 0.000 0.000 ;
  SIZE 17.920 BY 3.920 ;
  SYMMETRY X Y ;
  SITE GF018hv5v_mcu_sc7 ;
  PIN VDD
    DIRECTION INOUT ;
    USE POWER ;
    SHAPE ABUTMENT ;
    PORT
      LAYER Metal1 ;
        RECT 0.000 3.620 17.920 4.220 ;
        RECT 1.765 2.490 1.995 3.620 ;
        RECT 4.005 2.490 4.235 3.620 ;
        RECT 6.245 2.490 6.475 3.620 ;
        RECT 8.485 2.490 8.715 3.620 ;
        RECT 10.725 2.490 10.955 3.620 ;
        RECT 12.965 2.490 13.195 3.620 ;
        RECT 15.205 2.490 15.435 3.620 ;
        RECT 17.445 2.490 17.675 3.620 ;
    END
  END VDD
  PIN VNW
    DIRECTION INOUT ;
    USE POWER ;
    PORT
      LAYER Nwell ;
        RECT -0.430 1.760 18.350 4.350 ;
    END
  END VNW
  PIN VPW
    DIRECTION INOUT ;
    USE GROUND ;
    PORT
      LAYER Pwell ;
        RECT -0.430 -0.430 18.350 1.760 ;
    END
  END VPW
  PIN VSS
    DIRECTION INOUT ;
    USE GROUND ;
    SHAPE ABUTMENT ;
    PORT
      LAYER Metal1 ;
        RECT 0.245 0.300 0.475 1.045 ;
        RECT 2.485 0.300 2.715 1.045 ;
        RECT 4.725 0.300 4.955 1.045 ;
        RECT 6.965 0.300 7.195 1.045 ;
        RECT 9.205 0.300 9.435 1.045 ;
        RECT 11.445 0.300 11.675 1.045 ;
        RECT 13.685 0.300 13.915 1.045 ;
        RECT 15.925 0.300 16.155 1.045 ;
        RECT 0.000 -0.300 17.920 0.300 ;
    END
  END VSS
  OBS
      LAYER Metal1 ;
        RECT 0.245 1.555 0.475 3.390 ;
        RECT 0.730 1.960 1.995 2.190 ;
        RECT 0.245 1.325 1.520 1.555 ;
        RECT 1.765 0.530 1.995 1.960 ;
        RECT 2.485 1.555 2.715 3.390 ;
        RECT 2.970 1.960 4.235 2.190 ;
        RECT 2.485 1.325 3.760 1.555 ;
        RECT 4.005 0.530 4.235 1.960 ;
        RECT 4.725 1.555 4.955 3.390 ;
        RECT 5.210 1.960 6.475 2.190 ;
        RECT 4.725 1.325 6.000 1.555 ;
        RECT 6.245 0.530 6.475 1.960 ;
        RECT 6.965 1.555 7.195 3.390 ;
        RECT 7.450 1.960 8.715 2.190 ;
        RECT 6.965 1.325 8.240 1.555 ;
        RECT 8.485 0.530 8.715 1.960 ;
        RECT 9.205 1.555 9.435 3.390 ;
        RECT 9.690 1.960 10.955 2.190 ;
        RECT 9.205 1.325 10.480 1.555 ;
        RECT 10.725 0.530 10.955 1.960 ;
        RECT 11.445 1.555 11.675 3.390 ;
        RECT 11.930 1.960 13.195 2.190 ;
        RECT 11.445 1.325 12.720 1.555 ;
        RECT 12.965 0.530 13.195 1.960 ;
        RECT 13.685 1.555 13.915 3.390 ;
        RECT 14.170 1.960 15.435 2.190 ;
        RECT 13.685 1.325 14.960 1.555 ;
        RECT 15.205 0.530 15.435 1.960 ;
        RECT 15.925 1.555 16.155 3.390 ;
        RECT 16.410 1.960 17.675 2.190 ;
        RECT 15.925 1.325 17.200 1.555 ;
        RECT 17.445 0.530 17.675 1.960 ;
  END
END gf180mcu_fd_sc_mcu7t5v0__fillcap_32

#--------EOF---------

MACRO gf180mcu_fd_sc_mcu7t5v0__fillcap_64
  CLASS core SPACER ;
  FOREIGN gf180mcu_fd_sc_mcu7t5v0__fillcap_64 ;
  ORIGIN 0.000 0.000 ;
  SIZE 35.840 BY 3.920 ;
  SYMMETRY X Y ;
  SITE GF018hv5v_mcu_sc7 ;
  PIN VDD
    DIRECTION INOUT ;
    USE POWER ;
    SHAPE ABUTMENT ;
    PORT
      LAYER Metal1 ;
        RECT 0.000 3.620 35.840 4.220 ;
        RECT 1.765 2.490 1.995 3.620 ;
        RECT 4.005 2.490 4.235 3.620 ;
        RECT 6.245 2.490 6.475 3.620 ;
        RECT 8.485 2.490 8.715 3.620 ;
        RECT 10.725 2.490 10.955 3.620 ;
        RECT 12.965 2.490 13.195 3.620 ;
        RECT 15.205 2.490 15.435 3.620 ;
        RECT 17.445 2.490 17.675 3.620 ;
        RECT 19.685 2.490 19.915 3.620 ;
        RECT 21.925 2.490 22.155 3.620 ;
        RECT 24.165 2.490 24.395 3.620 ;
        RECT 26.405 2.490 26.635 3.620 ;
        RECT 28.645 2.490 28.875 3.620 ;
        RECT 30.885 2.490 31.115 3.620 ;
        RECT 33.125 2.490 33.355 3.620 ;
        RECT 35.365 2.490 35.595 3.620 ;
    END
  END VDD
  PIN VNW
    DIRECTION INOUT ;
    USE POWER ;
    PORT
      LAYER Nwell ;
        RECT -0.430 1.760 36.270 4.350 ;
    END
  END VNW
  PIN VPW
    DIRECTION INOUT ;
    USE GROUND ;
    PORT
      LAYER Pwell ;
        RECT -0.430 -0.430 36.270 1.760 ;
    END
  END VPW
  PIN VSS
    DIRECTION INOUT ;
    USE GROUND ;
    SHAPE ABUTMENT ;
    PORT
      LAYER Metal1 ;
        RECT 0.245 0.300 0.475 1.055 ;
        RECT 2.485 0.300 2.715 1.055 ;
        RECT 4.725 0.300 4.955 1.055 ;
        RECT 6.965 0.300 7.195 1.055 ;
        RECT 9.205 0.300 9.435 1.055 ;
        RECT 11.445 0.300 11.675 1.055 ;
        RECT 13.685 0.300 13.915 1.055 ;
        RECT 15.925 0.300 16.155 1.055 ;
        RECT 18.165 0.300 18.395 1.055 ;
        RECT 20.405 0.300 20.635 1.055 ;
        RECT 22.645 0.300 22.875 1.055 ;
        RECT 24.885 0.300 25.115 1.055 ;
        RECT 27.125 0.300 27.355 1.055 ;
        RECT 29.365 0.300 29.595 1.055 ;
        RECT 31.605 0.300 31.835 1.055 ;
        RECT 33.845 0.300 34.075 1.055 ;
        RECT 0.000 -0.300 35.840 0.300 ;
    END
  END VSS
  OBS
      LAYER Metal1 ;
        RECT 0.245 1.555 0.475 3.390 ;
        RECT 0.730 1.960 1.995 2.190 ;
        RECT 0.245 1.325 1.520 1.555 ;
        RECT 1.765 0.530 1.995 1.960 ;
        RECT 2.485 1.555 2.715 3.390 ;
        RECT 2.970 1.960 4.235 2.190 ;
        RECT 2.485 1.325 3.760 1.555 ;
        RECT 4.005 0.530 4.235 1.960 ;
        RECT 4.725 1.555 4.955 3.390 ;
        RECT 5.210 1.960 6.475 2.190 ;
        RECT 4.725 1.325 6.000 1.555 ;
        RECT 6.245 0.530 6.475 1.960 ;
        RECT 6.965 1.555 7.195 3.390 ;
        RECT 7.450 1.960 8.715 2.190 ;
        RECT 6.965 1.325 8.240 1.555 ;
        RECT 8.485 0.530 8.715 1.960 ;
        RECT 9.205 1.555 9.435 3.390 ;
        RECT 9.690 1.960 10.955 2.190 ;
        RECT 9.205 1.325 10.480 1.555 ;
        RECT 10.725 0.530 10.955 1.960 ;
        RECT 11.445 1.555 11.675 3.390 ;
        RECT 11.930 1.960 13.195 2.190 ;
        RECT 11.445 1.325 12.720 1.555 ;
        RECT 12.965 0.530 13.195 1.960 ;
        RECT 13.685 1.555 13.915 3.390 ;
        RECT 14.170 1.960 15.435 2.190 ;
        RECT 13.685 1.325 14.960 1.555 ;
        RECT 15.205 0.530 15.435 1.960 ;
        RECT 15.925 1.555 16.155 3.390 ;
        RECT 16.410 1.960 17.675 2.190 ;
        RECT 15.925 1.325 17.200 1.555 ;
        RECT 17.445 0.530 17.675 1.960 ;
        RECT 18.165 1.555 18.395 3.390 ;
        RECT 18.650 1.960 19.915 2.190 ;
        RECT 18.165 1.325 19.440 1.555 ;
        RECT 19.685 0.530 19.915 1.960 ;
        RECT 20.405 1.555 20.635 3.390 ;
        RECT 20.890 1.960 22.155 2.190 ;
        RECT 20.405 1.325 21.680 1.555 ;
        RECT 21.925 0.530 22.155 1.960 ;
        RECT 22.645 1.555 22.875 3.390 ;
        RECT 23.130 1.960 24.395 2.190 ;
        RECT 22.645 1.325 23.920 1.555 ;
        RECT 24.165 0.530 24.395 1.960 ;
        RECT 24.885 1.555 25.115 3.390 ;
        RECT 25.370 1.960 26.635 2.190 ;
        RECT 24.885 1.325 26.160 1.555 ;
        RECT 26.405 0.530 26.635 1.960 ;
        RECT 27.125 1.555 27.355 3.390 ;
        RECT 27.610 1.960 28.875 2.190 ;
        RECT 27.125 1.325 28.400 1.555 ;
        RECT 28.645 0.530 28.875 1.960 ;
        RECT 29.365 1.555 29.595 3.390 ;
        RECT 29.850 1.960 31.115 2.190 ;
        RECT 29.365 1.325 30.640 1.555 ;
        RECT 30.885 0.530 31.115 1.960 ;
        RECT 31.605 1.555 31.835 3.390 ;
        RECT 32.090 1.960 33.355 2.190 ;
        RECT 31.605 1.325 32.880 1.555 ;
        RECT 33.125 0.530 33.355 1.960 ;
        RECT 33.845 1.555 34.075 3.390 ;
        RECT 34.330 1.960 35.595 2.190 ;
        RECT 33.845 1.325 35.120 1.555 ;
        RECT 35.365 0.530 35.595 1.960 ;
  END
END gf180mcu_fd_sc_mcu7t5v0__fillcap_64

#--------EOF---------

MACRO gf180mcu_fd_sc_mcu7t5v0__filltie
  CLASS core WELLTAP ;
  FOREIGN gf180mcu_fd_sc_mcu7t5v0__filltie ;
  ORIGIN 0.000 0.000 ;
  SIZE 1.120 BY 3.920 ;
  SYMMETRY X Y ;
  SITE GF018hv5v_mcu_sc7 ;
  PIN VDD
    DIRECTION INOUT ;
    USE POWER ;
    SHAPE ABUTMENT ;
    PORT
      LAYER Nwell ;
        RECT -0.430 1.760 1.550 4.350 ;
      LAYER Metal1 ;
        RECT 0.000 3.620 1.120 4.220 ;
        RECT 0.390 1.930 0.730 3.620 ;
    END
  END VDD
  PIN VSS
    DIRECTION INOUT ;
    USE GROUND ;
    SHAPE ABUTMENT ;
    PORT
      LAYER Pwell ;
        RECT -0.430 -0.430 1.550 1.760 ;
      LAYER Metal1 ;
        RECT 0.390 0.300 0.730 1.185 ;
        RECT 0.000 -0.300 1.120 0.300 ;
    END
  END VSS
END gf180mcu_fd_sc_mcu7t5v0__filltie

#--------EOF---------

MACRO gf180mcu_fd_sc_mcu7t5v0__hold
  CLASS core ;
  FOREIGN gf180mcu_fd_sc_mcu7t5v0__hold ;
  ORIGIN 0.000 0.000 ;
  SIZE 5.040 BY 3.920 ;
  SYMMETRY X Y ;
  SITE GF018hv5v_mcu_sc7 ;
  PIN Z
    DIRECTION INOUT ;
    ANTENNAGATEAREA 1.102000 ;
    ANTENNADIFFAREA 0.451200 ;
    PORT
      LAYER Metal1 ;
        RECT 0.245 1.560 0.575 2.895 ;
        RECT 0.245 1.155 3.950 1.560 ;
        RECT 0.245 0.565 0.475 1.155 ;
    END
  END Z
  PIN VDD
    DIRECTION INOUT ;
    USE POWER ;
    SHAPE ABUTMENT ;
    PORT
      LAYER Metal1 ;
        RECT 0.000 3.620 5.040 4.220 ;
        RECT 3.225 2.535 3.455 3.620 ;
    END
  END VDD
  PIN VNW
    DIRECTION INOUT ;
    USE POWER ;
    PORT
      LAYER Nwell ;
        RECT -0.430 1.760 5.470 4.350 ;
    END
  END VNW
  PIN VPW
    DIRECTION INOUT ;
    USE GROUND ;
    PORT
      LAYER Pwell ;
        RECT -0.430 -0.430 5.470 1.760 ;
    END
  END VPW
  PIN VSS
    DIRECTION INOUT ;
    USE GROUND ;
    SHAPE ABUTMENT ;
    PORT
      LAYER Metal1 ;
        RECT 3.225 0.300 3.455 0.925 ;
        RECT 0.000 -0.300 5.040 0.300 ;
    END
  END VSS
  OBS
      LAYER Metal1 ;
        RECT 4.245 2.185 4.575 3.180 ;
        RECT 2.450 1.885 4.575 2.185 ;
        RECT 4.345 0.575 4.575 1.885 ;
  END
END gf180mcu_fd_sc_mcu7t5v0__hold

#--------EOF---------

MACRO gf180mcu_fd_sc_mcu7t5v0__icgtn_1
  CLASS core ;
  FOREIGN gf180mcu_fd_sc_mcu7t5v0__icgtn_1 ;
  ORIGIN 0.000 0.000 ;
  SIZE 17.360 BY 3.920 ;
  SYMMETRY X Y ;
  SITE GF018hv5v_mcu_sc7 ;
  PIN CLKN
    DIRECTION INPUT ;
    USE CLOCK ;
    ANTENNAGATEAREA 1.394000 ;
    PORT
      LAYER Metal1 ;
        RECT 14.025 1.680 14.255 2.195 ;
        RECT 13.570 1.590 14.255 1.680 ;
        RECT 11.810 1.450 14.255 1.590 ;
        RECT 11.810 1.210 13.865 1.450 ;
    END
  END CLKN
  PIN E
    DIRECTION INPUT ;
    ANTENNAGATEAREA 0.699500 ;
    PORT
      LAYER Metal1 ;
        RECT 2.320 2.150 2.730 3.370 ;
        RECT 1.845 1.770 2.730 2.150 ;
    END
  END E
  PIN TE
    DIRECTION INPUT ;
    ANTENNAGATEAREA 0.699500 ;
    PORT
      LAYER Metal1 ;
        RECT 0.270 1.770 1.570 2.150 ;
    END
  END TE
  PIN Q
    DIRECTION OUTPUT ;
    ANTENNADIFFAREA 0.811800 ;
    PORT
      LAYER Metal1 ;
        RECT 16.300 0.630 17.035 3.270 ;
    END
  END Q
  PIN VDD
    DIRECTION INOUT ;
    USE POWER ;
    SHAPE ABUTMENT ;
    PORT
      LAYER Metal1 ;
        RECT 0.000 3.620 17.360 4.220 ;
        RECT 0.345 2.480 0.575 3.620 ;
        RECT 6.300 2.790 6.530 3.620 ;
        RECT 9.110 2.470 9.340 3.620 ;
        RECT 12.800 2.460 13.030 3.620 ;
        RECT 15.345 2.425 15.685 3.620 ;
    END
  END VDD
  PIN VNW
    DIRECTION INOUT ;
    USE POWER ;
    PORT
      LAYER Nwell ;
        RECT -0.430 1.775 17.790 4.350 ;
        RECT -0.430 1.760 4.735 1.775 ;
        RECT 10.880 1.760 17.790 1.775 ;
    END
  END VNW
  PIN VPW
    DIRECTION INOUT ;
    USE GROUND ;
    PORT
      LAYER Pwell ;
        RECT 4.735 1.760 10.880 1.775 ;
        RECT -0.430 -0.430 17.790 1.760 ;
    END
  END VPW
  PIN VSS
    DIRECTION INOUT ;
    USE GROUND ;
    SHAPE ABUTMENT ;
    PORT
      LAYER Metal1 ;
        RECT 1.310 0.300 1.650 1.060 ;
        RECT 6.065 0.300 6.405 1.075 ;
        RECT 9.105 0.300 9.445 1.075 ;
        RECT 12.665 0.300 13.005 0.760 ;
        RECT 14.905 0.300 15.245 0.760 ;
        RECT 15.680 0.300 15.910 1.095 ;
        RECT 0.000 -0.300 17.360 0.300 ;
    END
  END VSS
  OBS
      LAYER Metal1 ;
        RECT 6.810 3.160 8.790 3.390 ;
        RECT 3.810 2.560 4.040 3.125 ;
        RECT 6.810 2.560 7.040 3.160 ;
        RECT 3.000 2.330 7.040 2.560 ;
        RECT 0.190 1.290 2.115 1.520 ;
        RECT 0.190 0.845 0.530 1.290 ;
        RECT 1.885 1.075 2.115 1.290 ;
        RECT 3.000 1.075 3.230 2.330 ;
        RECT 7.320 2.100 7.550 2.900 ;
        RECT 3.460 1.870 7.550 2.100 ;
        RECT 3.460 1.420 3.690 1.870 ;
        RECT 1.885 0.845 2.770 1.075 ;
        RECT 3.000 0.845 3.890 1.075 ;
        RECT 7.320 0.780 7.550 1.870 ;
        RECT 8.040 1.575 8.270 2.900 ;
        RECT 8.560 1.820 8.790 3.160 ;
        RECT 10.180 3.160 12.570 3.390 ;
        RECT 8.040 1.340 9.910 1.575 ;
        RECT 8.040 0.780 8.270 1.340 ;
        RECT 10.180 0.780 10.510 3.160 ;
        RECT 11.780 2.495 12.010 2.930 ;
        RECT 10.860 2.260 12.010 2.495 ;
        RECT 10.860 0.760 11.090 2.260 ;
        RECT 12.340 2.140 12.570 3.160 ;
        RECT 12.340 1.910 13.630 2.140 ;
        RECT 14.560 2.130 14.790 3.180 ;
        RECT 14.560 1.790 16.070 2.130 ;
        RECT 14.560 1.220 14.790 1.790 ;
        RECT 14.340 0.990 14.790 1.220 ;
        RECT 14.340 0.760 14.570 0.990 ;
        RECT 10.860 0.530 11.975 0.760 ;
        RECT 13.785 0.530 14.570 0.760 ;
  END
END gf180mcu_fd_sc_mcu7t5v0__icgtn_1

#--------EOF---------

MACRO gf180mcu_fd_sc_mcu7t5v0__icgtn_2
  CLASS core ;
  FOREIGN gf180mcu_fd_sc_mcu7t5v0__icgtn_2 ;
  ORIGIN 0.000 0.000 ;
  SIZE 18.480 BY 3.920 ;
  SYMMETRY X Y ;
  SITE GF018hv5v_mcu_sc7 ;
  PIN CLKN
    DIRECTION INPUT ;
    USE CLOCK ;
    ANTENNAGATEAREA 1.725000 ;
    PORT
      LAYER Metal1 ;
        RECT 13.985 1.590 14.215 2.250 ;
        RECT 11.810 1.210 14.215 1.590 ;
    END
  END CLKN
  PIN E
    DIRECTION INPUT ;
    ANTENNAGATEAREA 0.699500 ;
    PORT
      LAYER Metal1 ;
        RECT 2.340 2.150 2.750 3.370 ;
        RECT 1.865 1.770 2.750 2.150 ;
    END
  END E
  PIN TE
    DIRECTION INPUT ;
    ANTENNAGATEAREA 0.699500 ;
    PORT
      LAYER Metal1 ;
        RECT 0.290 1.770 1.590 2.150 ;
    END
  END TE
  PIN Q
    DIRECTION OUTPUT ;
    ANTENNADIFFAREA 0.962000 ;
    PORT
      LAYER Metal1 ;
        RECT 16.455 2.710 16.795 3.305 ;
        RECT 16.455 2.370 17.830 2.710 ;
        RECT 17.450 1.415 17.830 2.370 ;
        RECT 16.750 1.145 17.830 1.415 ;
        RECT 16.750 0.600 17.220 1.145 ;
    END
  END Q
  PIN VDD
    DIRECTION INOUT ;
    USE POWER ;
    SHAPE ABUTMENT ;
    PORT
      LAYER Metal1 ;
        RECT 0.000 3.620 18.480 4.220 ;
        RECT 0.345 2.480 0.575 3.620 ;
        RECT 6.300 2.790 6.530 3.620 ;
        RECT 9.110 2.470 9.340 3.620 ;
        RECT 12.800 2.695 13.030 3.620 ;
        RECT 15.490 2.610 15.720 3.620 ;
        RECT 17.530 3.020 17.760 3.620 ;
    END
  END VDD
  PIN VNW
    DIRECTION INOUT ;
    USE POWER ;
    PORT
      LAYER Nwell ;
        RECT -0.430 1.775 18.910 4.350 ;
        RECT -0.430 1.760 4.760 1.775 ;
        RECT 10.710 1.760 18.910 1.775 ;
    END
  END VNW
  PIN VPW
    DIRECTION INOUT ;
    USE GROUND ;
    PORT
      LAYER Pwell ;
        RECT 4.760 1.760 10.710 1.775 ;
        RECT -0.430 -0.430 18.910 1.760 ;
    END
  END VPW
  PIN VSS
    DIRECTION INOUT ;
    USE GROUND ;
    SHAPE ABUTMENT ;
    PORT
      LAYER Metal1 ;
        RECT 1.310 0.300 1.650 1.060 ;
        RECT 6.065 0.300 6.405 1.075 ;
        RECT 9.105 0.300 9.445 1.075 ;
        RECT 12.665 0.300 13.005 0.760 ;
        RECT 14.905 0.300 15.245 0.760 ;
        RECT 15.680 0.300 15.910 1.090 ;
        RECT 17.920 0.300 18.150 0.915 ;
        RECT 0.000 -0.300 18.480 0.300 ;
    END
  END VSS
  OBS
      LAYER Metal1 ;
        RECT 3.810 2.560 4.040 3.265 ;
        RECT 6.810 3.160 8.790 3.390 ;
        RECT 6.810 2.560 7.040 3.160 ;
        RECT 3.000 2.330 7.040 2.560 ;
        RECT 0.190 1.290 2.115 1.520 ;
        RECT 0.190 0.845 0.530 1.290 ;
        RECT 1.885 1.075 2.115 1.290 ;
        RECT 3.000 1.075 3.230 2.330 ;
        RECT 7.320 2.100 7.550 2.900 ;
        RECT 3.460 1.870 7.550 2.100 ;
        RECT 3.460 1.420 3.690 1.870 ;
        RECT 1.885 0.845 2.770 1.075 ;
        RECT 3.000 0.845 3.890 1.075 ;
        RECT 7.320 0.780 7.550 1.870 ;
        RECT 8.040 1.575 8.270 2.900 ;
        RECT 8.560 1.820 8.790 3.160 ;
        RECT 10.180 3.160 12.570 3.390 ;
        RECT 8.040 1.340 9.910 1.575 ;
        RECT 8.040 0.780 8.270 1.340 ;
        RECT 10.180 0.780 10.510 3.160 ;
        RECT 11.780 2.495 12.010 2.930 ;
        RECT 10.860 2.260 12.010 2.495 ;
        RECT 10.860 0.760 11.090 2.260 ;
        RECT 12.340 2.140 12.570 3.160 ;
        RECT 14.560 2.140 14.790 3.180 ;
        RECT 12.340 1.910 13.630 2.140 ;
        RECT 14.560 2.130 17.190 2.140 ;
        RECT 14.445 1.790 17.190 2.130 ;
        RECT 14.445 0.990 14.790 1.790 ;
        RECT 14.445 0.760 14.675 0.990 ;
        RECT 10.860 0.530 11.885 0.760 ;
        RECT 13.785 0.530 14.675 0.760 ;
  END
END gf180mcu_fd_sc_mcu7t5v0__icgtn_2

#--------EOF---------

MACRO gf180mcu_fd_sc_mcu7t5v0__icgtp_1
  CLASS core ;
  FOREIGN gf180mcu_fd_sc_mcu7t5v0__icgtp_1 ;
  ORIGIN 0.000 0.000 ;
  SIZE 15.680 BY 3.920 ;
  SYMMETRY X Y ;
  SITE GF018hv5v_mcu_sc7 ;
  PIN CLK
    DIRECTION INPUT ;
    USE CLOCK ;
    ANTENNAGATEAREA 1.388000 ;
    PORT
      LAYER Metal1 ;
        RECT 10.215 1.590 11.065 1.765 ;
        RECT 10.215 1.535 12.755 1.590 ;
        RECT 10.785 1.210 12.755 1.535 ;
    END
  END CLK
  PIN E
    DIRECTION INPUT ;
    ANTENNAGATEAREA 0.699500 ;
    PORT
      LAYER Metal1 ;
        RECT 2.340 2.150 2.750 3.370 ;
        RECT 1.865 1.770 2.750 2.150 ;
    END
  END E
  PIN TE
    DIRECTION INPUT ;
    ANTENNAGATEAREA 0.699500 ;
    PORT
      LAYER Metal1 ;
        RECT 0.290 1.770 1.590 2.150 ;
    END
  END TE
  PIN Q
    DIRECTION OUTPUT ;
    ANTENNADIFFAREA 0.814000 ;
    PORT
      LAYER Metal1 ;
        RECT 14.160 2.330 15.230 3.270 ;
        RECT 14.780 1.120 15.230 2.330 ;
        RECT 14.700 0.560 15.230 1.120 ;
    END
  END Q
  PIN VDD
    DIRECTION INOUT ;
    USE POWER ;
    SHAPE ABUTMENT ;
    PORT
      LAYER Metal1 ;
        RECT 0.000 3.620 15.680 4.220 ;
        RECT 0.345 2.480 0.575 3.620 ;
        RECT 6.245 2.845 6.585 3.620 ;
        RECT 9.690 2.920 9.920 3.620 ;
        RECT 11.635 2.460 11.865 3.620 ;
        RECT 13.700 2.900 13.930 3.620 ;
    END
  END VDD
  PIN VNW
    DIRECTION INOUT ;
    USE POWER ;
    PORT
      LAYER Nwell ;
        RECT -0.430 1.775 16.110 4.350 ;
        RECT -0.430 1.760 4.760 1.775 ;
        RECT 7.750 1.760 16.110 1.775 ;
    END
  END VNW
  PIN VPW
    DIRECTION INOUT ;
    USE GROUND ;
    PORT
      LAYER Pwell ;
        RECT 4.760 1.760 7.750 1.775 ;
        RECT -0.430 -0.430 16.110 1.760 ;
    END
  END VPW
  PIN VSS
    DIRECTION INOUT ;
    USE GROUND ;
    SHAPE ABUTMENT ;
    PORT
      LAYER Metal1 ;
        RECT 1.310 0.300 1.650 0.995 ;
        RECT 6.065 0.300 6.405 1.075 ;
        RECT 9.820 0.300 10.050 0.845 ;
        RECT 13.700 0.300 13.930 0.805 ;
        RECT 0.000 -0.300 15.680 0.300 ;
    END
  END VSS
  OBS
      LAYER Metal1 ;
        RECT 7.320 3.160 9.395 3.390 ;
        RECT 3.810 2.560 4.040 3.125 ;
        RECT 3.000 2.330 5.435 2.560 ;
        RECT 0.190 1.225 2.115 1.460 ;
        RECT 0.190 0.765 0.530 1.225 ;
        RECT 1.885 0.995 2.115 1.225 ;
        RECT 3.000 0.995 3.230 2.330 ;
        RECT 3.460 1.870 4.935 2.100 ;
        RECT 3.460 1.445 3.690 1.870 ;
        RECT 5.205 1.575 5.435 2.330 ;
        RECT 7.320 2.035 7.550 3.160 ;
        RECT 8.645 2.035 8.930 2.850 ;
        RECT 9.165 2.690 9.395 3.160 ;
        RECT 10.200 3.160 11.405 3.390 ;
        RECT 10.200 2.690 10.430 3.160 ;
        RECT 9.165 2.455 10.430 2.690 ;
        RECT 10.715 2.225 10.945 2.850 ;
        RECT 5.685 1.805 7.550 2.035 ;
        RECT 5.205 1.340 7.080 1.575 ;
        RECT 1.885 0.765 2.770 0.995 ;
        RECT 3.000 0.765 3.890 0.995 ;
        RECT 7.320 0.780 7.550 1.805 ;
        RECT 7.915 1.805 8.930 2.035 ;
        RECT 9.245 1.995 10.945 2.225 ;
        RECT 11.175 2.225 11.405 3.160 ;
        RECT 12.680 2.670 12.910 3.250 ;
        RECT 12.680 2.440 13.875 2.670 ;
        RECT 11.175 2.210 12.265 2.225 ;
        RECT 11.175 1.995 13.415 2.210 ;
        RECT 7.915 0.760 8.275 1.805 ;
        RECT 9.245 1.305 9.485 1.995 ;
        RECT 12.010 1.965 13.415 1.995 ;
        RECT 13.645 2.025 13.875 2.440 ;
        RECT 13.645 1.685 14.550 2.025 ;
        RECT 13.645 1.535 13.875 1.685 ;
        RECT 9.245 1.075 10.510 1.305 ;
        RECT 10.280 0.760 10.510 1.075 ;
        RECT 13.010 1.265 13.875 1.535 ;
        RECT 13.010 0.760 13.240 1.265 ;
        RECT 7.915 0.530 9.075 0.760 ;
        RECT 10.280 0.530 11.235 0.760 ;
        RECT 11.595 0.530 13.240 0.760 ;
  END
END gf180mcu_fd_sc_mcu7t5v0__icgtp_1

#--------EOF---------

MACRO gf180mcu_fd_sc_mcu7t5v0__icgtp_2
  CLASS core ;
  FOREIGN gf180mcu_fd_sc_mcu7t5v0__icgtp_2 ;
  ORIGIN 0.000 0.000 ;
  SIZE 16.800 BY 3.920 ;
  SYMMETRY X Y ;
  SITE GF018hv5v_mcu_sc7 ;
  PIN CLK
    DIRECTION INPUT ;
    USE CLOCK ;
    ANTENNAGATEAREA 1.679000 ;
    PORT
      LAYER Metal1 ;
        RECT 10.110 1.590 10.970 1.765 ;
        RECT 10.110 1.535 12.755 1.590 ;
        RECT 10.740 1.210 12.755 1.535 ;
    END
  END CLK
  PIN E
    DIRECTION INPUT ;
    ANTENNAGATEAREA 0.699500 ;
    PORT
      LAYER Metal1 ;
        RECT 2.340 2.120 2.750 3.370 ;
        RECT 1.865 1.800 2.750 2.120 ;
    END
  END E
  PIN TE
    DIRECTION INPUT ;
    ANTENNAGATEAREA 0.699500 ;
    PORT
      LAYER Metal1 ;
        RECT 0.290 1.800 1.590 2.120 ;
    END
  END TE
  PIN Q
    DIRECTION OUTPUT ;
    ANTENNADIFFAREA 1.118000 ;
    PORT
      LAYER Metal1 ;
        RECT 14.660 2.740 15.020 3.380 ;
        RECT 14.660 2.400 15.580 2.740 ;
        RECT 15.220 1.080 15.580 2.400 ;
        RECT 14.555 0.600 15.580 1.080 ;
    END
  END Q
  PIN VDD
    DIRECTION INOUT ;
    USE POWER ;
    SHAPE ABUTMENT ;
    PORT
      LAYER Metal1 ;
        RECT 0.000 3.620 16.800 4.220 ;
        RECT 0.290 2.535 0.630 3.620 ;
        RECT 6.280 2.505 6.510 3.620 ;
        RECT 9.690 2.920 9.920 3.620 ;
        RECT 11.635 2.570 11.865 3.620 ;
        RECT 13.645 2.815 13.985 3.620 ;
        RECT 15.870 2.530 16.100 3.620 ;
    END
  END VDD
  PIN VNW
    DIRECTION INOUT ;
    USE POWER ;
    PORT
      LAYER Nwell ;
        RECT -0.430 1.775 17.230 4.350 ;
        RECT -0.430 1.760 4.760 1.775 ;
        RECT 7.750 1.760 17.230 1.775 ;
    END
  END VNW
  PIN VPW
    DIRECTION INOUT ;
    USE GROUND ;
    PORT
      LAYER Pwell ;
        RECT 4.760 1.760 7.750 1.775 ;
        RECT -0.430 -0.430 17.230 1.760 ;
    END
  END VPW
  PIN VSS
    DIRECTION INOUT ;
    USE GROUND ;
    SHAPE ABUTMENT ;
    PORT
      LAYER Metal1 ;
        RECT 1.310 0.300 1.650 0.995 ;
        RECT 6.065 0.300 6.405 1.075 ;
        RECT 9.820 0.300 10.050 0.845 ;
        RECT 13.700 0.300 13.930 0.845 ;
        RECT 15.885 0.300 16.235 0.750 ;
        RECT 0.000 -0.300 16.800 0.300 ;
    END
  END VSS
  OBS
      LAYER Metal1 ;
        RECT 3.810 2.560 4.040 3.265 ;
        RECT 7.320 3.160 9.395 3.390 ;
        RECT 3.000 2.330 5.435 2.560 ;
        RECT 0.190 1.225 2.115 1.460 ;
        RECT 0.190 0.765 0.530 1.225 ;
        RECT 1.885 0.995 2.115 1.225 ;
        RECT 3.000 0.995 3.230 2.330 ;
        RECT 3.460 1.870 4.935 2.100 ;
        RECT 3.460 1.445 3.690 1.870 ;
        RECT 5.205 1.575 5.435 2.330 ;
        RECT 7.320 2.035 7.550 3.160 ;
        RECT 8.645 2.035 8.930 2.850 ;
        RECT 9.165 2.690 9.395 3.160 ;
        RECT 10.200 3.160 11.405 3.390 ;
        RECT 10.200 2.690 10.430 3.160 ;
        RECT 9.165 2.455 10.430 2.690 ;
        RECT 10.715 2.225 10.945 2.850 ;
        RECT 5.685 1.805 7.550 2.035 ;
        RECT 5.205 1.340 7.080 1.575 ;
        RECT 1.885 0.765 2.770 0.995 ;
        RECT 3.000 0.765 3.890 0.995 ;
        RECT 7.320 0.780 7.550 1.805 ;
        RECT 7.915 1.805 8.930 2.035 ;
        RECT 9.175 1.995 10.945 2.225 ;
        RECT 11.175 2.125 11.405 3.160 ;
        RECT 12.680 2.585 12.910 3.380 ;
        RECT 12.680 2.355 13.875 2.585 ;
        RECT 7.915 0.760 8.275 1.805 ;
        RECT 9.175 1.305 9.415 1.995 ;
        RECT 11.175 1.895 13.415 2.125 ;
        RECT 13.645 1.825 13.875 2.355 ;
        RECT 13.645 1.595 14.970 1.825 ;
        RECT 13.645 1.535 13.875 1.595 ;
        RECT 9.175 1.075 10.510 1.305 ;
        RECT 10.280 0.760 10.510 1.075 ;
        RECT 13.010 1.265 13.875 1.535 ;
        RECT 13.010 0.760 13.240 1.265 ;
        RECT 7.915 0.530 9.075 0.760 ;
        RECT 10.280 0.530 11.235 0.760 ;
        RECT 11.595 0.530 13.240 0.760 ;
  END
END gf180mcu_fd_sc_mcu7t5v0__icgtp_2

#--------EOF---------

MACRO gf180mcu_fd_sc_mcu7t5v0__inv_1
  CLASS core ;
  FOREIGN gf180mcu_fd_sc_mcu7t5v0__inv_1 ;
  ORIGIN 0.000 0.000 ;
  SIZE 2.240 BY 3.920 ;
  SYMMETRY X Y ;
  SITE GF018hv5v_mcu_sc7 ;
  PIN I
    DIRECTION INPUT ;
    ANTENNAGATEAREA 1.102000 ;
    PORT
      LAYER Metal1 ;
        RECT 0.710 1.200 1.035 2.200 ;
    END
  END I
  PIN ZN
    DIRECTION OUTPUT ;
    ANTENNADIFFAREA 0.897600 ;
    PORT
      LAYER Metal1 ;
        RECT 1.265 0.530 1.595 3.390 ;
    END
  END ZN
  PIN VDD
    DIRECTION INOUT ;
    USE POWER ;
    SHAPE ABUTMENT ;
    PORT
      LAYER Metal1 ;
        RECT 0.000 3.620 2.240 4.220 ;
        RECT 0.345 2.530 0.575 3.620 ;
    END
  END VDD
  PIN VNW
    DIRECTION INOUT ;
    USE POWER ;
    PORT
      LAYER Nwell ;
        RECT -0.430 1.760 2.670 4.350 ;
    END
  END VNW
  PIN VPW
    DIRECTION INOUT ;
    USE GROUND ;
    PORT
      LAYER Pwell ;
        RECT -0.430 -0.430 2.670 1.760 ;
    END
  END VPW
  PIN VSS
    DIRECTION INOUT ;
    USE GROUND ;
    SHAPE ABUTMENT ;
    PORT
      LAYER Metal1 ;
        RECT 0.245 0.300 0.475 1.160 ;
        RECT 0.000 -0.300 2.240 0.300 ;
    END
  END VSS
END gf180mcu_fd_sc_mcu7t5v0__inv_1

#--------EOF---------

MACRO gf180mcu_fd_sc_mcu7t5v0__inv_2
  CLASS core ;
  FOREIGN gf180mcu_fd_sc_mcu7t5v0__inv_2 ;
  ORIGIN 0.000 0.000 ;
  SIZE 3.360 BY 3.920 ;
  SYMMETRY X Y ;
  SITE GF018hv5v_mcu_sc7 ;
  PIN I
    DIRECTION INPUT ;
    ANTENNAGATEAREA 2.204000 ;
    PORT
      LAYER Metal1 ;
        RECT 0.630 1.705 2.150 2.120 ;
    END
  END I
  PIN ZN
    DIRECTION OUTPUT ;
    ANTENNADIFFAREA 1.366000 ;
    PORT
      LAYER Metal1 ;
        RECT 1.220 2.680 1.670 3.390 ;
        RECT 1.220 2.360 2.680 2.680 ;
        RECT 2.380 1.475 2.680 2.360 ;
        RECT 1.395 1.220 2.680 1.475 ;
        RECT 1.395 0.530 1.625 1.220 ;
    END
  END ZN
  PIN VDD
    DIRECTION INOUT ;
    USE POWER ;
    SHAPE ABUTMENT ;
    PORT
      LAYER Metal1 ;
        RECT 0.000 3.620 3.360 4.220 ;
        RECT 0.245 2.640 0.475 3.620 ;
        RECT 2.515 2.930 2.745 3.620 ;
    END
  END VDD
  PIN VNW
    DIRECTION INOUT ;
    USE POWER ;
    PORT
      LAYER Nwell ;
        RECT -0.430 1.760 3.790 4.350 ;
    END
  END VNW
  PIN VPW
    DIRECTION INOUT ;
    USE GROUND ;
    PORT
      LAYER Pwell ;
        RECT -0.430 -0.430 3.790 1.760 ;
    END
  END VPW
  PIN VSS
    DIRECTION INOUT ;
    USE GROUND ;
    SHAPE ABUTMENT ;
    PORT
      LAYER Metal1 ;
        RECT 0.245 0.300 0.475 0.950 ;
        RECT 2.515 0.300 2.745 0.950 ;
        RECT 0.000 -0.300 3.360 0.300 ;
    END
  END VSS
END gf180mcu_fd_sc_mcu7t5v0__inv_2

#--------EOF---------

MACRO gf180mcu_fd_sc_mcu7t5v0__inv_3
  CLASS core ;
  FOREIGN gf180mcu_fd_sc_mcu7t5v0__inv_3 ;
  ORIGIN 0.000 0.000 ;
  SIZE 4.480 BY 3.920 ;
  SYMMETRY X Y ;
  SITE GF018hv5v_mcu_sc7 ;
  PIN I
    DIRECTION INPUT ;
    ANTENNAGATEAREA 3.306000 ;
    PORT
      LAYER Metal1 ;
        RECT 0.410 1.760 3.015 2.120 ;
    END
  END I
  PIN ZN
    DIRECTION OUTPUT ;
    ANTENNADIFFAREA 2.202400 ;
    PORT
      LAYER Metal1 ;
        RECT 1.365 2.680 1.595 3.390 ;
        RECT 3.410 2.680 3.835 3.390 ;
        RECT 1.365 2.360 3.835 2.680 ;
        RECT 3.410 1.525 3.835 2.360 ;
        RECT 1.365 1.290 3.835 1.525 ;
        RECT 1.365 0.530 1.595 1.290 ;
        RECT 3.410 0.530 3.835 1.290 ;
    END
  END ZN
  PIN VDD
    DIRECTION INOUT ;
    USE POWER ;
    SHAPE ABUTMENT ;
    PORT
      LAYER Metal1 ;
        RECT 0.000 3.620 4.480 4.220 ;
        RECT 0.245 2.530 0.475 3.620 ;
        RECT 2.485 2.985 2.715 3.620 ;
    END
  END VDD
  PIN VNW
    DIRECTION INOUT ;
    USE POWER ;
    PORT
      LAYER Nwell ;
        RECT -0.430 1.760 4.910 4.350 ;
    END
  END VNW
  PIN VPW
    DIRECTION INOUT ;
    USE GROUND ;
    PORT
      LAYER Pwell ;
        RECT -0.430 -0.430 4.910 1.760 ;
    END
  END VPW
  PIN VSS
    DIRECTION INOUT ;
    USE GROUND ;
    SHAPE ABUTMENT ;
    PORT
      LAYER Metal1 ;
        RECT 0.245 0.300 0.475 1.160 ;
        RECT 2.485 0.300 2.715 1.055 ;
        RECT 0.000 -0.300 4.480 0.300 ;
    END
  END VSS
END gf180mcu_fd_sc_mcu7t5v0__inv_3

#--------EOF---------

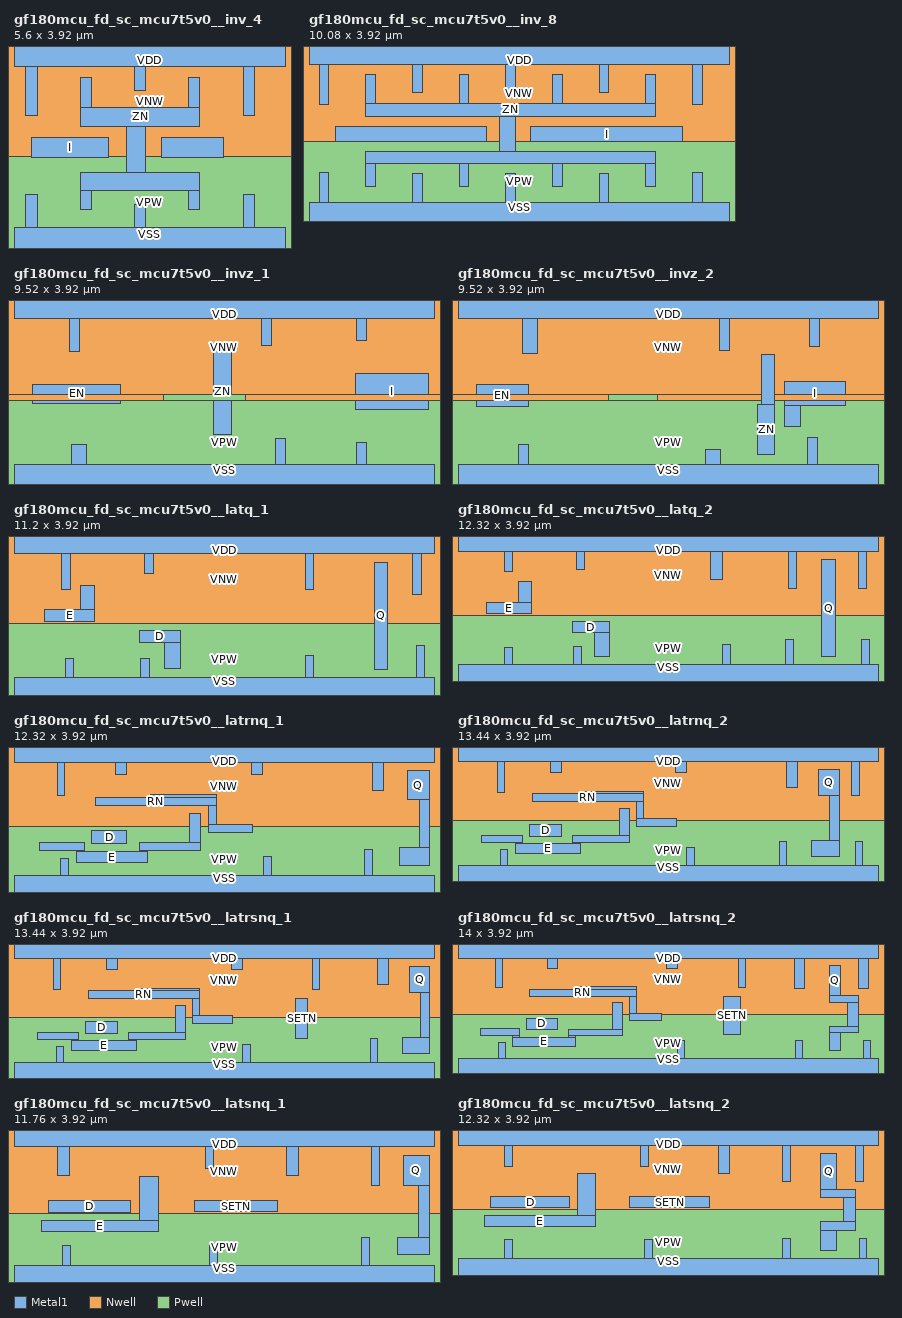
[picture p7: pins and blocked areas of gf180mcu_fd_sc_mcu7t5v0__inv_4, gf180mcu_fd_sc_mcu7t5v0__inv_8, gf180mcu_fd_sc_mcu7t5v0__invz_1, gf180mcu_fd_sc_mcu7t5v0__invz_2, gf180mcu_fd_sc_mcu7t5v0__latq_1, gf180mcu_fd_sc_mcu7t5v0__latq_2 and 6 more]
MACRO gf180mcu_fd_sc_mcu7t5v0__inv_4
  CLASS core ;
  FOREIGN gf180mcu_fd_sc_mcu7t5v0__inv_4 ;
  ORIGIN 0.000 0.000 ;
  SIZE 5.600 BY 3.920 ;
  SYMMETRY X Y ;
  SITE GF018hv5v_mcu_sc7 ;
  PIN I
    DIRECTION INPUT ;
    ANTENNAGATEAREA 4.408000 ;
    PORT
      LAYER Metal1 ;
        RECT 0.370 1.740 1.950 2.150 ;
        RECT 3.035 1.740 4.315 2.150 ;
    END
  END I
  PIN ZN
    DIRECTION OUTPUT ;
    ANTENNADIFFAREA 2.609600 ;
    PORT
      LAYER Metal1 ;
        RECT 1.365 2.770 1.595 3.390 ;
        RECT 3.605 2.770 3.835 3.390 ;
        RECT 1.365 2.390 3.835 2.770 ;
        RECT 2.330 1.440 2.710 2.390 ;
        RECT 1.365 1.060 3.835 1.440 ;
        RECT 1.365 0.675 1.595 1.060 ;
        RECT 3.605 0.675 3.835 1.060 ;
    END
  END ZN
  PIN VDD
    DIRECTION INOUT ;
    USE POWER ;
    SHAPE ABUTMENT ;
    PORT
      LAYER Metal1 ;
        RECT 0.000 3.620 5.600 4.220 ;
        RECT 0.245 2.615 0.475 3.620 ;
        RECT 2.485 3.130 2.715 3.620 ;
        RECT 4.725 2.620 4.955 3.620 ;
    END
  END VDD
  PIN VNW
    DIRECTION INOUT ;
    USE POWER ;
    PORT
      LAYER Nwell ;
        RECT -0.430 1.760 6.030 4.350 ;
    END
  END VNW
  PIN VPW
    DIRECTION INOUT ;
    USE GROUND ;
    PORT
      LAYER Pwell ;
        RECT -0.430 -0.430 6.030 1.760 ;
    END
  END VPW
  PIN VSS
    DIRECTION INOUT ;
    USE GROUND ;
    SHAPE ABUTMENT ;
    PORT
      LAYER Metal1 ;
        RECT 0.245 0.300 0.475 0.970 ;
        RECT 2.485 0.300 2.715 0.775 ;
        RECT 4.725 0.300 4.955 0.975 ;
        RECT 0.000 -0.300 5.600 0.300 ;
    END
  END VSS
END gf180mcu_fd_sc_mcu7t5v0__inv_4

#--------EOF---------

MACRO gf180mcu_fd_sc_mcu7t5v0__inv_8
  CLASS core ;
  FOREIGN gf180mcu_fd_sc_mcu7t5v0__inv_8 ;
  ORIGIN 0.000 0.000 ;
  SIZE 10.080 BY 3.920 ;
  SYMMETRY X Y ;
  SITE GF018hv5v_mcu_sc7 ;
  PIN I
    DIRECTION INPUT ;
    ANTENNAGATEAREA 8.816000 ;
    PORT
      LAYER Metal1 ;
        RECT 0.630 1.765 4.260 2.120 ;
        RECT 5.320 1.765 8.960 2.120 ;
    END
  END I
  PIN ZN
    DIRECTION OUTPUT ;
    ANTENNADIFFAREA 5.219200 ;
    PORT
      LAYER Metal1 ;
        RECT 1.365 2.675 1.595 3.380 ;
        RECT 3.605 2.675 3.835 3.380 ;
        RECT 5.845 2.680 6.075 3.380 ;
        RECT 8.085 2.680 8.315 3.380 ;
        RECT 5.845 2.675 8.315 2.680 ;
        RECT 1.365 2.375 8.315 2.675 ;
        RECT 4.570 1.535 4.950 2.375 ;
        RECT 1.365 1.235 8.315 1.535 ;
        RECT 1.365 0.675 1.595 1.235 ;
        RECT 3.605 0.675 3.835 1.235 ;
        RECT 5.845 0.675 6.075 1.235 ;
        RECT 8.085 0.675 8.315 1.235 ;
    END
  END ZN
  PIN VDD
    DIRECTION INOUT ;
    USE POWER ;
    SHAPE ABUTMENT ;
    PORT
      LAYER Metal1 ;
        RECT 0.000 3.620 10.080 4.220 ;
        RECT 0.245 2.655 0.475 3.620 ;
        RECT 2.485 2.950 2.715 3.620 ;
        RECT 4.725 2.950 4.955 3.620 ;
        RECT 6.965 2.950 7.195 3.620 ;
        RECT 9.205 2.650 9.435 3.620 ;
    END
  END VDD
  PIN VNW
    DIRECTION INOUT ;
    USE POWER ;
    PORT
      LAYER Nwell ;
        RECT -0.430 1.760 10.510 4.350 ;
    END
  END VNW
  PIN VPW
    DIRECTION INOUT ;
    USE GROUND ;
    PORT
      LAYER Pwell ;
        RECT -0.430 -0.430 10.510 1.760 ;
    END
  END VPW
  PIN VSS
    DIRECTION INOUT ;
    USE GROUND ;
    SHAPE ABUTMENT ;
    PORT
      LAYER Metal1 ;
        RECT 0.245 0.300 0.475 1.015 ;
        RECT 2.485 0.300 2.715 0.995 ;
        RECT 4.725 0.300 4.955 0.995 ;
        RECT 6.965 0.300 7.195 0.995 ;
        RECT 9.205 0.300 9.435 1.015 ;
        RECT 0.000 -0.300 10.080 0.300 ;
    END
  END VSS
END gf180mcu_fd_sc_mcu7t5v0__inv_8

#--------EOF---------

MACRO gf180mcu_fd_sc_mcu7t5v0__invz_1
  CLASS core ;
  FOREIGN gf180mcu_fd_sc_mcu7t5v0__invz_1 ;
  ORIGIN 0.000 0.000 ;
  SIZE 9.520 BY 3.920 ;
  SYMMETRY X Y ;
  SITE GF018hv5v_mcu_sc7 ;
  PIN EN
    DIRECTION INPUT ;
    ANTENNAGATEAREA 1.052000 ;
    PORT
      LAYER Metal1 ;
        RECT 0.410 1.700 2.425 2.120 ;
    END
  END EN
  PIN I
    DIRECTION INPUT ;
    ANTENNAGATEAREA 0.526000 ;
    PORT
      LAYER Metal1 ;
        RECT 7.740 1.560 9.400 2.375 ;
    END
  END I
  PIN ZN
    DIRECTION OUTPUT ;
    ANTENNADIFFAREA 1.072725 ;
    PORT
      LAYER Metal1 ;
        RECT 4.530 0.990 4.920 2.930 ;
    END
  END ZN
  PIN VDD
    DIRECTION INOUT ;
    USE POWER ;
    SHAPE ABUTMENT ;
    PORT
      LAYER Metal1 ;
        RECT 0.000 3.620 9.520 4.220 ;
        RECT 1.265 2.865 1.495 3.620 ;
        RECT 5.615 3.000 5.845 3.620 ;
        RECT 7.770 3.115 8.000 3.620 ;
    END
  END VDD
  PIN VNW
    DIRECTION INOUT ;
    USE POWER ;
    PORT
      LAYER Nwell ;
        RECT -0.430 1.885 9.950 4.350 ;
        RECT -0.430 1.760 3.390 1.885 ;
        RECT 5.255 1.760 9.950 1.885 ;
    END
  END VNW
  PIN VPW
    DIRECTION INOUT ;
    USE GROUND ;
    PORT
      LAYER Pwell ;
        RECT 3.390 1.760 5.255 1.885 ;
        RECT -0.430 -0.430 9.950 1.760 ;
    END
  END VPW
  PIN VSS
    DIRECTION INOUT ;
    USE GROUND ;
    SHAPE ABUTMENT ;
    PORT
      LAYER Metal1 ;
        RECT 1.310 0.300 1.650 0.760 ;
        RECT 5.930 0.300 6.160 0.905 ;
        RECT 7.770 0.300 8.000 0.815 ;
        RECT 0.000 -0.300 9.520 0.300 ;
    END
  END VSS
  OBS
      LAYER Metal1 ;
        RECT 0.245 2.635 0.475 3.390 ;
        RECT 2.285 3.160 5.385 3.390 ;
        RECT 2.285 2.865 2.515 3.160 ;
        RECT 0.245 2.405 3.010 2.635 ;
        RECT 2.710 1.225 3.010 2.405 ;
        RECT 0.180 0.995 3.010 1.225 ;
        RECT 3.240 2.610 3.820 2.910 ;
        RECT 0.180 0.530 0.540 0.995 ;
        RECT 3.240 0.760 3.470 2.610 ;
        RECT 4.050 2.380 4.280 3.160 ;
        RECT 3.770 2.150 4.280 2.380 ;
        RECT 5.150 2.770 5.385 3.160 ;
        RECT 6.750 2.770 6.980 3.375 ;
        RECT 8.945 2.885 9.175 3.375 ;
        RECT 5.150 2.535 6.980 2.770 ;
        RECT 7.260 2.650 9.175 2.885 ;
        RECT 3.770 0.990 4.110 2.150 ;
        RECT 5.150 1.900 5.380 2.535 ;
        RECT 5.345 1.365 5.575 1.620 ;
        RECT 5.345 1.135 6.935 1.365 ;
        RECT 5.345 0.760 5.575 1.135 ;
        RECT 2.400 0.530 5.575 0.760 ;
        RECT 6.585 0.530 6.935 1.135 ;
        RECT 7.260 1.275 7.490 2.650 ;
        RECT 7.260 1.045 8.460 1.275 ;
        RECT 8.230 0.760 8.460 1.045 ;
        RECT 8.230 0.530 9.340 0.760 ;
  END
END gf180mcu_fd_sc_mcu7t5v0__invz_1

#--------EOF---------

MACRO gf180mcu_fd_sc_mcu7t5v0__invz_2
  CLASS core ;
  FOREIGN gf180mcu_fd_sc_mcu7t5v0__invz_2 ;
  ORIGIN 0.000 0.000 ;
  SIZE 9.520 BY 3.920 ;
  SYMMETRY X Y ;
  SITE GF018hv5v_mcu_sc7 ;
  PIN EN
    DIRECTION INPUT ;
    ANTENNAGATEAREA 2.079000 ;
    PORT
      LAYER Metal1 ;
        RECT 0.410 1.625 1.590 2.125 ;
    END
  END EN
  PIN I
    DIRECTION INPUT ;
    ANTENNAGATEAREA 1.082000 ;
    PORT
      LAYER Metal1 ;
        RECT 7.405 1.640 8.775 2.190 ;
        RECT 7.405 1.160 7.770 1.640 ;
    END
  END I
  PIN ZN
    DIRECTION OUTPUT ;
    ANTENNADIFFAREA 1.040000 ;
    PORT
      LAYER Metal1 ;
        RECT 6.880 1.660 7.175 2.800 ;
        RECT 6.795 0.530 7.175 1.660 ;
    END
  END ZN
  PIN VDD
    DIRECTION INOUT ;
    USE POWER ;
    SHAPE ABUTMENT ;
    PORT
      LAYER Metal1 ;
        RECT 0.000 3.620 9.520 4.220 ;
        RECT 1.465 2.815 1.805 3.620 ;
        RECT 5.925 2.890 6.155 3.620 ;
        RECT 7.965 2.980 8.195 3.620 ;
    END
  END VDD
  PIN VNW
    DIRECTION INOUT ;
    USE POWER ;
    PORT
      LAYER Nwell ;
        RECT -0.430 1.885 9.950 4.350 ;
        RECT -0.430 1.760 3.400 1.885 ;
        RECT 4.520 1.760 9.950 1.885 ;
    END
  END VNW
  PIN VPW
    DIRECTION INOUT ;
    USE GROUND ;
    PORT
      LAYER Pwell ;
        RECT 3.400 1.760 4.520 1.885 ;
        RECT -0.430 -0.430 9.950 1.760 ;
    END
  END VPW
  PIN VSS
    DIRECTION INOUT ;
    USE GROUND ;
    SHAPE ABUTMENT ;
    PORT
      LAYER Metal1 ;
        RECT 1.375 0.300 1.605 0.760 ;
        RECT 5.620 0.300 5.960 0.635 ;
        RECT 7.915 0.300 8.145 0.920 ;
        RECT 0.000 -0.300 9.520 0.300 ;
    END
  END VSS
  OBS
      LAYER Metal1 ;
        RECT 0.500 2.585 0.730 3.380 ;
        RECT 2.445 3.125 5.135 3.355 ;
        RECT 0.500 2.355 3.210 2.585 ;
        RECT 1.840 2.035 3.210 2.355 ;
        RECT 1.840 1.225 2.070 2.035 ;
        RECT 3.555 1.805 3.790 2.890 ;
        RECT 0.255 0.990 2.070 1.225 ;
        RECT 2.985 1.575 3.790 1.805 ;
        RECT 0.255 0.570 0.485 0.990 ;
        RECT 2.985 0.885 3.215 1.575 ;
        RECT 4.020 1.555 4.250 3.125 ;
        RECT 4.905 2.465 5.135 3.125 ;
        RECT 6.385 3.070 7.735 3.300 ;
        RECT 6.385 2.660 6.615 3.070 ;
        RECT 5.415 2.425 6.615 2.660 ;
        RECT 7.505 2.750 7.735 3.070 ;
        RECT 9.020 2.750 9.285 3.380 ;
        RECT 7.505 2.520 9.285 2.750 ;
        RECT 5.415 1.915 5.645 2.425 ;
        RECT 5.875 1.965 6.650 2.195 ;
        RECT 5.875 1.555 6.105 1.965 ;
        RECT 4.020 1.345 6.105 1.555 ;
        RECT 3.770 1.325 6.105 1.345 ;
        RECT 3.770 0.990 4.250 1.325 ;
        RECT 6.335 1.095 6.565 1.640 ;
        RECT 2.495 0.760 3.215 0.885 ;
        RECT 5.160 0.865 6.565 1.095 ;
        RECT 5.160 0.760 5.390 0.865 ;
        RECT 2.495 0.530 5.390 0.760 ;
        RECT 9.020 0.580 9.285 2.520 ;
  END
END gf180mcu_fd_sc_mcu7t5v0__invz_2

#--------EOF---------

MACRO gf180mcu_fd_sc_mcu7t5v0__latq_1
  CLASS core ;
  FOREIGN gf180mcu_fd_sc_mcu7t5v0__latq_1 ;
  ORIGIN 0.000 0.000 ;
  SIZE 11.200 BY 3.920 ;
  SYMMETRY X Y ;
  SITE GF018hv5v_mcu_sc7 ;
  PIN D
    DIRECTION INPUT ;
    ANTENNAGATEAREA 0.552000 ;
    PORT
      LAYER Metal1 ;
        RECT 3.350 1.240 4.430 1.560 ;
        RECT 4.000 0.550 4.430 1.240 ;
    END
  END D
  PIN E
    DIRECTION INPUT ;
    USE CLOCK ;
    ANTENNAGATEAREA 0.736000 ;
    PORT
      LAYER Metal1 ;
        RECT 1.770 2.120 2.150 2.750 ;
        RECT 0.825 1.800 2.150 2.120 ;
    END
  END E
  PIN Q
    DIRECTION OUTPUT ;
    ANTENNADIFFAREA 0.897600 ;
    PORT
      LAYER Metal1 ;
        RECT 9.605 0.530 9.960 3.380 ;
    END
  END Q
  PIN VDD
    DIRECTION INOUT ;
    USE POWER ;
    SHAPE ABUTMENT ;
    PORT
      LAYER Metal1 ;
        RECT 0.000 3.620 11.200 4.220 ;
        RECT 1.265 2.660 1.495 3.620 ;
        RECT 3.485 3.085 3.715 3.620 ;
        RECT 7.765 2.655 7.995 3.620 ;
        RECT 10.625 2.530 10.855 3.620 ;
    END
  END VDD
  PIN VNW
    DIRECTION INOUT ;
    USE POWER ;
    PORT
      LAYER Nwell ;
        RECT -0.430 1.760 11.630 4.350 ;
    END
  END VNW
  PIN VPW
    DIRECTION INOUT ;
    USE GROUND ;
    PORT
      LAYER Pwell ;
        RECT -0.430 -0.430 11.630 1.760 ;
    END
  END VPW
  PIN VSS
    DIRECTION INOUT ;
    USE GROUND ;
    SHAPE ABUTMENT ;
    PORT
      LAYER Metal1 ;
        RECT 1.365 0.300 1.595 0.815 ;
        RECT 3.385 0.300 3.615 0.825 ;
        RECT 7.765 0.300 7.995 0.895 ;
        RECT 10.725 0.300 10.955 1.160 ;
        RECT 0.000 -0.300 11.200 0.300 ;
    END
  END VSS
  OBS
      LAYER Metal1 ;
        RECT 0.190 1.390 0.530 3.390 ;
        RECT 2.610 2.085 2.895 3.390 ;
        RECT 5.100 3.140 6.505 3.370 ;
        RECT 3.125 2.335 5.100 2.565 ;
        RECT 5.755 2.085 5.985 2.810 ;
        RECT 2.610 1.855 5.985 2.085 ;
        RECT 0.190 1.160 2.360 1.390 ;
        RECT 0.190 0.530 0.530 1.160 ;
        RECT 2.610 0.530 2.950 1.855 ;
        RECT 4.785 1.010 5.015 1.855 ;
        RECT 6.275 1.475 6.505 3.140 ;
        RECT 8.785 2.305 9.035 3.225 ;
        RECT 7.025 2.075 9.170 2.305 ;
        RECT 6.275 1.245 8.580 1.475 ;
        RECT 6.275 0.760 6.505 1.245 ;
        RECT 5.200 0.530 6.505 0.760 ;
        RECT 8.830 0.530 9.170 2.075 ;
  END
END gf180mcu_fd_sc_mcu7t5v0__latq_1

#--------EOF---------

MACRO gf180mcu_fd_sc_mcu7t5v0__latq_2
  CLASS core ;
  FOREIGN gf180mcu_fd_sc_mcu7t5v0__latq_2 ;
  ORIGIN 0.000 0.000 ;
  SIZE 12.320 BY 3.920 ;
  SYMMETRY X Y ;
  SITE GF018hv5v_mcu_sc7 ;
  PIN D
    DIRECTION INPUT ;
    ANTENNAGATEAREA 0.552000 ;
    PORT
      LAYER Metal1 ;
        RECT 3.350 1.240 4.430 1.560 ;
        RECT 4.000 0.550 4.430 1.240 ;
    END
  END D
  PIN E
    DIRECTION INPUT ;
    USE CLOCK ;
    ANTENNAGATEAREA 0.736000 ;
    PORT
      LAYER Metal1 ;
        RECT 1.770 2.120 2.150 2.750 ;
        RECT 0.825 1.800 2.150 2.120 ;
    END
  END E
  PIN Q
    DIRECTION OUTPUT ;
    ANTENNADIFFAREA 1.060800 ;
    PORT
      LAYER Metal1 ;
        RECT 10.660 0.530 11.080 3.380 ;
    END
  END Q
  PIN VDD
    DIRECTION INOUT ;
    USE POWER ;
    SHAPE ABUTMENT ;
    PORT
      LAYER Metal1 ;
        RECT 0.000 3.620 12.320 4.220 ;
        RECT 1.365 3.050 1.595 3.620 ;
        RECT 3.485 3.085 3.715 3.620 ;
        RECT 7.410 2.805 7.750 3.620 ;
        RECT 9.705 2.530 9.935 3.620 ;
        RECT 11.745 2.530 11.975 3.620 ;
    END
  END VDD
  PIN VNW
    DIRECTION INOUT ;
    USE POWER ;
    PORT
      LAYER Nwell ;
        RECT -0.430 1.760 12.750 4.350 ;
    END
  END VNW
  PIN VPW
    DIRECTION INOUT ;
    USE GROUND ;
    PORT
      LAYER Pwell ;
        RECT -0.430 -0.430 12.750 1.760 ;
    END
  END VPW
  PIN VSS
    DIRECTION INOUT ;
    USE GROUND ;
    SHAPE ABUTMENT ;
    PORT
      LAYER Metal1 ;
        RECT 1.365 0.300 1.595 0.815 ;
        RECT 3.385 0.300 3.615 0.825 ;
        RECT 7.765 0.300 7.995 0.895 ;
        RECT 9.605 0.300 9.835 1.055 ;
        RECT 11.845 0.300 12.075 1.055 ;
        RECT 0.000 -0.300 12.320 0.300 ;
    END
  END VSS
  OBS
      LAYER Metal1 ;
        RECT 0.190 1.390 0.575 3.390 ;
        RECT 2.610 2.085 2.895 3.390 ;
        RECT 5.100 3.140 6.505 3.370 ;
        RECT 3.125 2.335 5.100 2.565 ;
        RECT 5.755 2.085 5.985 2.810 ;
        RECT 2.610 1.855 5.985 2.085 ;
        RECT 0.190 1.160 2.360 1.390 ;
        RECT 0.190 0.530 0.575 1.160 ;
        RECT 2.610 0.530 2.950 1.855 ;
        RECT 4.785 1.010 5.015 1.855 ;
        RECT 6.275 1.475 6.505 3.140 ;
        RECT 8.485 2.305 8.715 3.225 ;
        RECT 6.820 2.075 9.170 2.305 ;
        RECT 6.275 1.245 8.580 1.475 ;
        RECT 6.275 0.760 6.505 1.245 ;
        RECT 5.200 0.530 6.505 0.760 ;
        RECT 8.830 0.530 9.170 2.075 ;
  END
END gf180mcu_fd_sc_mcu7t5v0__latq_2

#--------EOF---------

MACRO gf180mcu_fd_sc_mcu7t5v0__latrnq_1
  CLASS core ;
  FOREIGN gf180mcu_fd_sc_mcu7t5v0__latrnq_1 ;
  ORIGIN 0.000 0.000 ;
  SIZE 12.320 BY 3.920 ;
  SYMMETRY X Y ;
  SITE GF018hv5v_mcu_sc7 ;
  PIN D
    DIRECTION INPUT ;
    ANTENNAGATEAREA 0.552000 ;
    PORT
      LAYER Metal1 ;
        RECT 2.285 1.240 3.310 1.630 ;
    END
  END D
  PIN E
    DIRECTION INPUT ;
    USE CLOCK ;
    ANTENNAGATEAREA 1.293500 ;
    PORT
      LAYER Metal1 ;
        RECT 0.760 1.045 2.055 1.275 ;
        RECT 5.160 1.265 5.475 2.135 ;
        RECT 1.825 1.000 2.055 1.045 ;
        RECT 3.675 1.035 5.475 1.265 ;
        RECT 3.675 1.000 3.905 1.035 ;
        RECT 1.825 0.680 3.905 1.000 ;
    END
  END E
  PIN RN
    DIRECTION INPUT ;
    ANTENNAGATEAREA 0.789000 ;
    PORT
      LAYER Metal1 ;
        RECT 4.000 2.595 5.935 2.680 ;
        RECT 2.380 2.365 5.935 2.595 ;
        RECT 5.705 1.795 5.935 2.365 ;
        RECT 5.705 1.565 7.000 1.795 ;
    END
  END RN
  PIN Q
    DIRECTION OUTPUT ;
    ANTENNADIFFAREA 0.897600 ;
    PORT
      LAYER Metal1 ;
        RECT 11.530 2.530 12.190 3.380 ;
        RECT 11.880 1.120 12.190 2.530 ;
        RECT 11.310 0.600 12.190 1.120 ;
    END
  END Q
  PIN VDD
    DIRECTION INOUT ;
    USE POWER ;
    SHAPE ABUTMENT ;
    PORT
      LAYER Metal1 ;
        RECT 0.000 3.620 12.320 4.220 ;
        RECT 1.265 2.655 1.495 3.620 ;
        RECT 2.970 3.285 3.310 3.620 ;
        RECT 6.960 3.285 7.300 3.620 ;
        RECT 10.510 2.815 10.850 3.620 ;
    END
  END VDD
  PIN VNW
    DIRECTION INOUT ;
    USE POWER ;
    PORT
      LAYER Nwell ;
        RECT -0.430 1.760 12.750 4.350 ;
    END
  END VNW
  PIN VPW
    DIRECTION INOUT ;
    USE GROUND ;
    PORT
      LAYER Pwell ;
        RECT -0.430 -0.430 12.750 1.760 ;
    END
  END VPW
  PIN VSS
    DIRECTION INOUT ;
    USE GROUND ;
    SHAPE ABUTMENT ;
    PORT
      LAYER Metal1 ;
        RECT 1.365 0.300 1.595 0.815 ;
        RECT 7.325 0.300 7.555 0.875 ;
        RECT 10.285 0.300 10.515 1.075 ;
        RECT 0.000 -0.300 12.320 0.300 ;
    END
  END VSS
  OBS
      LAYER Metal1 ;
        RECT 0.190 2.135 0.475 3.310 ;
        RECT 2.005 3.055 2.235 3.390 ;
        RECT 3.560 3.105 6.445 3.335 ;
        RECT 3.560 3.055 3.790 3.105 ;
        RECT 2.005 2.825 3.790 3.055 ;
        RECT 6.195 3.055 6.445 3.105 ;
        RECT 6.195 2.825 8.115 3.055 ;
        RECT 6.165 2.195 7.545 2.535 ;
        RECT 7.775 2.250 8.115 2.825 ;
        RECT 0.190 1.905 4.640 2.135 ;
        RECT 7.315 2.020 7.545 2.195 ;
        RECT 8.345 2.020 8.575 3.390 ;
        RECT 9.165 2.570 9.395 3.250 ;
        RECT 9.165 2.340 10.575 2.570 ;
        RECT 10.345 2.020 10.575 2.340 ;
        RECT 0.190 0.530 0.530 1.905 ;
        RECT 7.315 1.790 10.005 2.020 ;
        RECT 10.345 1.790 11.310 2.020 ;
        RECT 6.865 1.105 8.170 1.335 ;
        RECT 6.865 0.760 7.095 1.105 ;
        RECT 4.290 0.530 7.095 0.760 ;
        RECT 8.445 0.550 8.675 1.790 ;
        RECT 10.345 1.535 10.575 1.790 ;
        RECT 9.165 1.305 10.575 1.535 ;
        RECT 9.165 0.735 9.395 1.305 ;
  END
END gf180mcu_fd_sc_mcu7t5v0__latrnq_1

#--------EOF---------

MACRO gf180mcu_fd_sc_mcu7t5v0__latrnq_2
  CLASS core ;
  FOREIGN gf180mcu_fd_sc_mcu7t5v0__latrnq_2 ;
  ORIGIN 0.000 0.000 ;
  SIZE 13.440 BY 3.920 ;
  SYMMETRY X Y ;
  SITE GF018hv5v_mcu_sc7 ;
  PIN D
    DIRECTION INPUT ;
    ANTENNAGATEAREA 0.552000 ;
    PORT
      LAYER Metal1 ;
        RECT 2.285 1.240 3.310 1.630 ;
    END
  END D
  PIN E
    DIRECTION INPUT ;
    USE CLOCK ;
    ANTENNAGATEAREA 1.293500 ;
    PORT
      LAYER Metal1 ;
        RECT 0.760 1.045 2.055 1.275 ;
        RECT 5.160 1.265 5.475 2.135 ;
        RECT 1.825 1.000 2.055 1.045 ;
        RECT 3.675 1.035 5.475 1.265 ;
        RECT 3.675 1.000 3.905 1.035 ;
        RECT 1.825 0.680 3.905 1.000 ;
    END
  END E
  PIN RN
    DIRECTION INPUT ;
    ANTENNAGATEAREA 0.789000 ;
    PORT
      LAYER Metal1 ;
        RECT 4.000 2.595 5.935 2.680 ;
        RECT 2.380 2.365 5.935 2.595 ;
        RECT 5.705 1.795 5.935 2.365 ;
        RECT 5.705 1.565 7.000 1.795 ;
    END
  END RN
  PIN Q
    DIRECTION OUTPUT ;
    ANTENNADIFFAREA 1.060800 ;
    PORT
      LAYER Metal1 ;
        RECT 11.530 2.530 12.220 3.380 ;
        RECT 11.900 1.120 12.220 2.530 ;
        RECT 11.310 0.600 12.220 1.120 ;
    END
  END Q
  PIN VDD
    DIRECTION INOUT ;
    USE POWER ;
    SHAPE ABUTMENT ;
    PORT
      LAYER Metal1 ;
        RECT 0.000 3.620 13.440 4.220 ;
        RECT 1.265 2.655 1.495 3.620 ;
        RECT 2.970 3.285 3.310 3.620 ;
        RECT 6.960 3.285 7.300 3.620 ;
        RECT 10.510 2.815 10.850 3.620 ;
        RECT 12.605 2.530 12.835 3.620 ;
    END
  END VDD
  PIN VNW
    DIRECTION INOUT ;
    USE POWER ;
    PORT
      LAYER Nwell ;
        RECT -0.430 1.760 13.870 4.350 ;
    END
  END VNW
  PIN VPW
    DIRECTION INOUT ;
    USE GROUND ;
    PORT
      LAYER Pwell ;
        RECT -0.430 -0.430 13.870 1.760 ;
    END
  END VPW
  PIN VSS
    DIRECTION INOUT ;
    USE GROUND ;
    SHAPE ABUTMENT ;
    PORT
      LAYER Metal1 ;
        RECT 1.365 0.300 1.595 0.815 ;
        RECT 7.325 0.300 7.555 0.875 ;
        RECT 10.285 0.300 10.515 1.075 ;
        RECT 12.705 0.300 12.935 1.075 ;
        RECT 0.000 -0.300 13.440 0.300 ;
    END
  END VSS
  OBS
      LAYER Metal1 ;
        RECT 0.190 2.135 0.475 3.310 ;
        RECT 2.005 3.055 2.235 3.390 ;
        RECT 3.560 3.105 6.445 3.335 ;
        RECT 3.560 3.055 3.790 3.105 ;
        RECT 2.005 2.825 3.790 3.055 ;
        RECT 6.195 3.055 6.445 3.105 ;
        RECT 6.195 2.825 8.115 3.055 ;
        RECT 6.165 2.195 7.545 2.535 ;
        RECT 7.775 2.250 8.115 2.825 ;
        RECT 0.190 1.905 4.640 2.135 ;
        RECT 7.315 2.020 7.545 2.195 ;
        RECT 8.345 2.020 8.575 3.390 ;
        RECT 9.165 2.570 9.395 3.250 ;
        RECT 9.165 2.340 10.575 2.570 ;
        RECT 10.345 2.030 10.575 2.340 ;
        RECT 0.190 0.530 0.530 1.905 ;
        RECT 7.315 1.790 9.890 2.020 ;
        RECT 6.865 1.105 8.170 1.335 ;
        RECT 6.865 0.760 7.095 1.105 ;
        RECT 4.290 0.530 7.095 0.760 ;
        RECT 8.445 0.550 8.675 1.790 ;
        RECT 10.345 1.690 11.650 2.030 ;
        RECT 10.345 1.545 10.575 1.690 ;
        RECT 9.165 1.315 10.575 1.545 ;
        RECT 9.165 0.735 9.395 1.315 ;
  END
END gf180mcu_fd_sc_mcu7t5v0__latrnq_2

#--------EOF---------

MACRO gf180mcu_fd_sc_mcu7t5v0__latrsnq_1
  CLASS core ;
  FOREIGN gf180mcu_fd_sc_mcu7t5v0__latrsnq_1 ;
  ORIGIN 0.000 0.000 ;
  SIZE 13.440 BY 3.920 ;
  SYMMETRY X Y ;
  SITE GF018hv5v_mcu_sc7 ;
  PIN D
    DIRECTION INPUT ;
    ANTENNAGATEAREA 0.552000 ;
    PORT
      LAYER Metal1 ;
        RECT 2.285 1.240 3.310 1.630 ;
    END
  END D
  PIN E
    DIRECTION INPUT ;
    USE CLOCK ;
    ANTENNAGATEAREA 1.293500 ;
    PORT
      LAYER Metal1 ;
        RECT 0.760 1.045 2.055 1.275 ;
        RECT 5.160 1.265 5.475 2.135 ;
        RECT 1.825 1.000 2.055 1.045 ;
        RECT 3.675 1.035 5.475 1.265 ;
        RECT 3.675 1.000 3.905 1.035 ;
        RECT 1.825 0.680 3.905 1.000 ;
    END
  END E
  PIN RN
    DIRECTION INPUT ;
    ANTENNAGATEAREA 0.789000 ;
    PORT
      LAYER Metal1 ;
        RECT 4.000 2.595 5.935 2.680 ;
        RECT 2.380 2.365 5.935 2.595 ;
        RECT 5.705 1.795 5.935 2.365 ;
        RECT 5.705 1.565 7.000 1.795 ;
    END
  END RN
  PIN SETN
    DIRECTION INPUT ;
    ANTENNAGATEAREA 0.741500 ;
    PORT
      LAYER Metal1 ;
        RECT 9.010 1.085 9.400 2.355 ;
    END
  END SETN
  PIN Q
    DIRECTION OUTPUT ;
    ANTENNADIFFAREA 0.897600 ;
    PORT
      LAYER Metal1 ;
        RECT 12.650 2.530 13.310 3.380 ;
        RECT 13.000 1.120 13.310 2.530 ;
        RECT 12.430 0.600 13.310 1.120 ;
    END
  END Q
  PIN VDD
    DIRECTION INOUT ;
    USE POWER ;
    SHAPE ABUTMENT ;
    PORT
      LAYER Metal1 ;
        RECT 0.000 3.620 13.440 4.220 ;
        RECT 1.265 2.655 1.495 3.620 ;
        RECT 2.970 3.285 3.310 3.620 ;
        RECT 6.960 3.285 7.300 3.620 ;
        RECT 9.545 2.655 9.775 3.620 ;
        RECT 11.630 2.815 11.970 3.620 ;
    END
  END VDD
  PIN VNW
    DIRECTION INOUT ;
    USE POWER ;
    PORT
      LAYER Nwell ;
        RECT -0.430 1.760 13.870 4.350 ;
    END
  END VNW
  PIN VPW
    DIRECTION INOUT ;
    USE GROUND ;
    PORT
      LAYER Pwell ;
        RECT -0.430 -0.430 13.870 1.760 ;
    END
  END VPW
  PIN VSS
    DIRECTION INOUT ;
    USE GROUND ;
    SHAPE ABUTMENT ;
    PORT
      LAYER Metal1 ;
        RECT 1.365 0.300 1.595 0.815 ;
        RECT 7.325 0.300 7.555 0.875 ;
        RECT 11.405 0.300 11.635 1.075 ;
        RECT 0.000 -0.300 13.440 0.300 ;
    END
  END VSS
  OBS
      LAYER Metal1 ;
        RECT 0.190 2.135 0.475 3.310 ;
        RECT 2.005 3.055 2.235 3.390 ;
        RECT 3.560 3.105 6.445 3.335 ;
        RECT 3.560 3.055 3.790 3.105 ;
        RECT 2.005 2.825 3.790 3.055 ;
        RECT 6.195 3.055 6.445 3.105 ;
        RECT 6.195 2.825 8.115 3.055 ;
        RECT 6.165 2.195 7.545 2.535 ;
        RECT 7.775 2.250 8.115 2.825 ;
        RECT 0.190 1.905 4.640 2.135 ;
        RECT 7.315 2.020 7.545 2.195 ;
        RECT 8.525 2.020 8.755 3.390 ;
        RECT 10.285 2.570 10.515 3.250 ;
        RECT 10.285 2.340 11.695 2.570 ;
        RECT 11.465 2.020 11.695 2.340 ;
        RECT 0.190 0.530 0.530 1.905 ;
        RECT 7.315 1.790 8.755 2.020 ;
        RECT 6.865 1.105 8.115 1.335 ;
        RECT 6.865 0.760 7.095 1.105 ;
        RECT 4.290 0.530 7.095 0.760 ;
        RECT 8.525 0.835 8.755 1.790 ;
        RECT 9.760 1.790 11.125 2.020 ;
        RECT 11.465 1.790 12.430 2.020 ;
        RECT 9.760 0.835 9.990 1.790 ;
        RECT 11.465 1.535 11.695 1.790 ;
        RECT 8.525 0.605 9.990 0.835 ;
        RECT 10.285 1.305 11.695 1.535 ;
        RECT 10.285 0.735 10.515 1.305 ;
  END
END gf180mcu_fd_sc_mcu7t5v0__latrsnq_1

#--------EOF---------

MACRO gf180mcu_fd_sc_mcu7t5v0__latrsnq_2
  CLASS core ;
  FOREIGN gf180mcu_fd_sc_mcu7t5v0__latrsnq_2 ;
  ORIGIN 0.000 0.000 ;
  SIZE 14.000 BY 3.920 ;
  SYMMETRY X Y ;
  SITE GF018hv5v_mcu_sc7 ;
  PIN D
    DIRECTION INPUT ;
    ANTENNAGATEAREA 0.552000 ;
    PORT
      LAYER Metal1 ;
        RECT 2.285 1.240 3.310 1.630 ;
    END
  END D
  PIN E
    DIRECTION INPUT ;
    USE CLOCK ;
    ANTENNAGATEAREA 1.293500 ;
    PORT
      LAYER Metal1 ;
        RECT 0.760 1.045 2.055 1.275 ;
        RECT 5.160 1.265 5.475 2.135 ;
        RECT 1.825 1.000 2.055 1.045 ;
        RECT 3.675 1.035 5.475 1.265 ;
        RECT 3.675 1.000 3.905 1.035 ;
        RECT 1.825 0.680 3.905 1.000 ;
    END
  END E
  PIN RN
    DIRECTION INPUT ;
    ANTENNAGATEAREA 0.789000 ;
    PORT
      LAYER Metal1 ;
        RECT 4.000 2.595 5.935 2.680 ;
        RECT 2.380 2.365 5.935 2.595 ;
        RECT 5.705 1.795 5.935 2.365 ;
        RECT 5.705 1.565 6.780 1.795 ;
    END
  END RN
  PIN SETN
    DIRECTION INPUT ;
    ANTENNAGATEAREA 0.741500 ;
    PORT
      LAYER Metal1 ;
        RECT 8.840 1.085 9.400 2.355 ;
    END
  END SETN
  PIN Q
    DIRECTION OUTPUT ;
    ANTENNADIFFAREA 1.060800 ;
    PORT
      LAYER Metal1 ;
        RECT 12.380 2.380 12.760 3.380 ;
        RECT 12.380 2.150 13.340 2.380 ;
        RECT 12.980 1.365 13.340 2.150 ;
        RECT 12.380 1.135 13.340 1.365 ;
        RECT 12.380 0.545 12.760 1.135 ;
    END
  END Q
  PIN VDD
    DIRECTION INOUT ;
    USE POWER ;
    SHAPE ABUTMENT ;
    PORT
      LAYER Metal1 ;
        RECT 0.000 3.620 14.000 4.220 ;
        RECT 1.265 2.655 1.495 3.620 ;
        RECT 2.970 3.285 3.310 3.620 ;
        RECT 6.960 3.285 7.300 3.620 ;
        RECT 9.345 2.655 9.575 3.620 ;
        RECT 11.210 2.630 11.550 3.620 ;
        RECT 13.350 2.630 13.690 3.620 ;
    END
  END VDD
  PIN VNW
    DIRECTION INOUT ;
    USE POWER ;
    PORT
      LAYER Nwell ;
        RECT -0.430 1.760 14.430 4.350 ;
    END
  END VNW
  PIN VPW
    DIRECTION INOUT ;
    USE GROUND ;
    PORT
      LAYER Pwell ;
        RECT -0.430 -0.430 14.430 1.760 ;
    END
  END VPW
  PIN VSS
    DIRECTION INOUT ;
    USE GROUND ;
    SHAPE ABUTMENT ;
    PORT
      LAYER Metal1 ;
        RECT 1.365 0.300 1.595 0.815 ;
        RECT 7.325 0.300 7.555 0.875 ;
        RECT 11.265 0.300 11.495 0.885 ;
        RECT 13.505 0.300 13.735 0.885 ;
        RECT 0.000 -0.300 14.000 0.300 ;
    END
  END VSS
  OBS
      LAYER Metal1 ;
        RECT 0.190 2.135 0.475 3.310 ;
        RECT 2.005 3.055 2.235 3.390 ;
        RECT 3.560 3.105 6.445 3.335 ;
        RECT 3.560 3.055 3.790 3.105 ;
        RECT 2.005 2.825 3.790 3.055 ;
        RECT 6.195 3.055 6.445 3.105 ;
        RECT 6.195 2.825 7.875 3.055 ;
        RECT 6.165 2.195 7.280 2.535 ;
        RECT 7.535 2.250 7.875 2.825 ;
        RECT 0.190 1.905 4.640 2.135 ;
        RECT 7.030 2.020 7.280 2.195 ;
        RECT 8.325 2.020 8.555 3.390 ;
        RECT 10.245 2.380 10.475 3.380 ;
        RECT 10.245 2.150 11.555 2.380 ;
        RECT 0.190 0.530 0.530 1.905 ;
        RECT 7.030 1.790 8.555 2.020 ;
        RECT 11.325 1.900 11.555 2.150 ;
        RECT 6.865 1.105 8.095 1.335 ;
        RECT 6.865 0.760 7.095 1.105 ;
        RECT 4.290 0.530 7.095 0.760 ;
        RECT 8.325 0.835 8.555 1.790 ;
        RECT 9.665 1.670 10.985 1.900 ;
        RECT 11.325 1.670 12.745 1.900 ;
        RECT 9.665 0.835 9.895 1.670 ;
        RECT 11.325 1.365 11.555 1.670 ;
        RECT 8.325 0.605 9.895 0.835 ;
        RECT 10.145 1.135 11.555 1.365 ;
        RECT 10.145 0.545 10.375 1.135 ;
  END
END gf180mcu_fd_sc_mcu7t5v0__latrsnq_2

#--------EOF---------

MACRO gf180mcu_fd_sc_mcu7t5v0__latsnq_1
  CLASS core ;
  FOREIGN gf180mcu_fd_sc_mcu7t5v0__latsnq_1 ;
  ORIGIN 0.000 0.000 ;
  SIZE 11.760 BY 3.920 ;
  SYMMETRY X Y ;
  SITE GF018hv5v_mcu_sc7 ;
  PIN D
    DIRECTION INPUT ;
    ANTENNAGATEAREA 0.552000 ;
    PORT
      LAYER Metal1 ;
        RECT 0.965 1.790 3.270 2.120 ;
    END
  END D
  PIN E
    DIRECTION INPUT ;
    USE CLOCK ;
    ANTENNAGATEAREA 1.293500 ;
    PORT
      LAYER Metal1 ;
        RECT 3.500 1.560 4.045 2.795 ;
        RECT 0.780 1.240 4.045 1.560 ;
    END
  END E
  PIN SETN
    DIRECTION INPUT ;
    ANTENNAGATEAREA 0.741500 ;
    PORT
      LAYER Metal1 ;
        RECT 5.040 1.800 7.380 2.120 ;
    END
  END SETN
  PIN Q
    DIRECTION OUTPUT ;
    ANTENNADIFFAREA 0.897600 ;
    PORT
      LAYER Metal1 ;
        RECT 10.895 2.530 11.630 3.380 ;
        RECT 11.320 1.065 11.630 2.530 ;
        RECT 10.750 0.600 11.630 1.065 ;
    END
  END Q
  PIN VDD
    DIRECTION INOUT ;
    USE POWER ;
    SHAPE ABUTMENT ;
    PORT
      LAYER Metal1 ;
        RECT 0.000 3.620 11.760 4.220 ;
        RECT 1.210 2.815 1.550 3.620 ;
        RECT 5.365 3.000 5.595 3.620 ;
        RECT 7.630 2.815 7.970 3.620 ;
        RECT 10.005 2.530 10.235 3.620 ;
    END
  END VDD
  PIN VNW
    DIRECTION INOUT ;
    USE POWER ;
    PORT
      LAYER Nwell ;
        RECT -0.430 1.760 12.190 4.350 ;
    END
  END VNW
  PIN VPW
    DIRECTION INOUT ;
    USE GROUND ;
    PORT
      LAYER Pwell ;
        RECT -0.430 -0.430 12.190 1.760 ;
    END
  END VPW
  PIN VSS
    DIRECTION INOUT ;
    USE GROUND ;
    SHAPE ABUTMENT ;
    PORT
      LAYER Metal1 ;
        RECT 1.365 0.300 1.595 0.860 ;
        RECT 5.465 0.300 5.695 0.860 ;
        RECT 9.725 0.300 9.955 1.075 ;
        RECT 0.000 -0.300 11.760 0.300 ;
    END
  END VSS
  OBS
      LAYER Metal1 ;
        RECT 0.190 2.580 0.530 3.380 ;
        RECT 3.160 3.095 4.560 3.325 ;
        RECT 0.190 2.350 3.160 2.580 ;
        RECT 0.190 0.530 0.530 2.350 ;
        RECT 4.320 1.455 4.560 3.095 ;
        RECT 6.665 2.580 6.895 3.380 ;
        RECT 8.605 2.625 8.835 3.250 ;
        RECT 4.810 2.350 7.970 2.580 ;
        RECT 8.605 2.395 9.755 2.625 ;
        RECT 7.630 2.145 7.970 2.350 ;
        RECT 7.630 1.805 9.285 2.145 ;
        RECT 9.525 2.020 9.755 2.395 ;
        RECT 4.320 1.225 6.530 1.455 ;
        RECT 4.320 0.760 4.560 1.225 ;
        RECT 3.410 0.530 4.560 0.760 ;
        RECT 7.630 0.530 7.970 1.805 ;
        RECT 9.525 1.790 10.750 2.020 ;
        RECT 9.525 1.555 9.755 1.790 ;
        RECT 8.605 1.325 9.755 1.555 ;
        RECT 8.605 0.735 8.835 1.325 ;
  END
END gf180mcu_fd_sc_mcu7t5v0__latsnq_1

#--------EOF---------

MACRO gf180mcu_fd_sc_mcu7t5v0__latsnq_2
  CLASS core ;
  FOREIGN gf180mcu_fd_sc_mcu7t5v0__latsnq_2 ;
  ORIGIN 0.000 0.000 ;
  SIZE 12.320 BY 3.920 ;
  SYMMETRY X Y ;
  SITE GF018hv5v_mcu_sc7 ;
  PIN D
    DIRECTION INPUT ;
    ANTENNAGATEAREA 0.552000 ;
    PORT
      LAYER Metal1 ;
        RECT 0.965 1.790 3.270 2.120 ;
    END
  END D
  PIN E
    DIRECTION INPUT ;
    USE CLOCK ;
    ANTENNAGATEAREA 1.293500 ;
    PORT
      LAYER Metal1 ;
        RECT 3.500 1.560 4.045 2.795 ;
        RECT 0.780 1.240 4.045 1.560 ;
    END
  END E
  PIN SETN
    DIRECTION INPUT ;
    ANTENNAGATEAREA 0.741500 ;
    PORT
      LAYER Metal1 ;
        RECT 5.040 1.800 7.380 2.120 ;
    END
  END SETN
  PIN Q
    DIRECTION OUTPUT ;
    ANTENNADIFFAREA 1.060800 ;
    PORT
      LAYER Metal1 ;
        RECT 10.640 2.340 11.100 3.380 ;
        RECT 10.640 2.110 11.660 2.340 ;
        RECT 11.300 1.380 11.660 2.110 ;
        RECT 10.640 1.130 11.660 1.380 ;
        RECT 10.640 0.555 11.100 1.130 ;
    END
  END Q
  PIN VDD
    DIRECTION INOUT ;
    USE POWER ;
    SHAPE ABUTMENT ;
    PORT
      LAYER Metal1 ;
        RECT 0.000 3.620 12.320 4.220 ;
        RECT 1.365 3.000 1.595 3.620 ;
        RECT 5.365 3.000 5.595 3.620 ;
        RECT 7.630 2.815 7.970 3.620 ;
        RECT 9.525 2.570 9.755 3.620 ;
        RECT 11.665 2.570 11.895 3.620 ;
    END
  END VDD
  PIN VNW
    DIRECTION INOUT ;
    USE POWER ;
    PORT
      LAYER Nwell ;
        RECT -0.430 1.760 12.750 4.350 ;
    END
  END VNW
  PIN VPW
    DIRECTION INOUT ;
    USE GROUND ;
    PORT
      LAYER Pwell ;
        RECT -0.430 -0.430 12.750 1.760 ;
    END
  END VPW
  PIN VSS
    DIRECTION INOUT ;
    USE GROUND ;
    SHAPE ABUTMENT ;
    PORT
      LAYER Metal1 ;
        RECT 1.365 0.300 1.595 0.860 ;
        RECT 5.465 0.300 5.695 0.860 ;
        RECT 9.525 0.300 9.755 0.895 ;
        RECT 11.765 0.300 11.995 0.895 ;
        RECT 0.000 -0.300 12.320 0.300 ;
    END
  END VSS
  OBS
      LAYER Metal1 ;
        RECT 0.190 2.580 0.575 3.380 ;
        RECT 3.160 3.095 4.560 3.325 ;
        RECT 0.190 2.350 3.160 2.580 ;
        RECT 0.190 0.530 0.530 2.350 ;
        RECT 4.320 1.455 4.560 3.095 ;
        RECT 6.665 2.580 6.895 3.380 ;
        RECT 4.810 2.350 7.970 2.580 ;
        RECT 7.630 1.860 7.970 2.350 ;
        RECT 8.505 2.340 8.735 3.380 ;
        RECT 8.505 2.110 9.815 2.340 ;
        RECT 9.585 1.860 9.815 2.110 ;
        RECT 7.630 1.630 9.245 1.860 ;
        RECT 9.585 1.630 10.935 1.860 ;
        RECT 4.320 1.225 6.530 1.455 ;
        RECT 4.320 0.760 4.560 1.225 ;
        RECT 3.410 0.530 4.560 0.760 ;
        RECT 7.630 0.530 7.970 1.630 ;
        RECT 9.585 1.380 9.815 1.630 ;
        RECT 8.405 1.150 9.815 1.380 ;
        RECT 8.405 0.555 8.635 1.150 ;
  END
END gf180mcu_fd_sc_mcu7t5v0__latsnq_2

#--------EOF---------

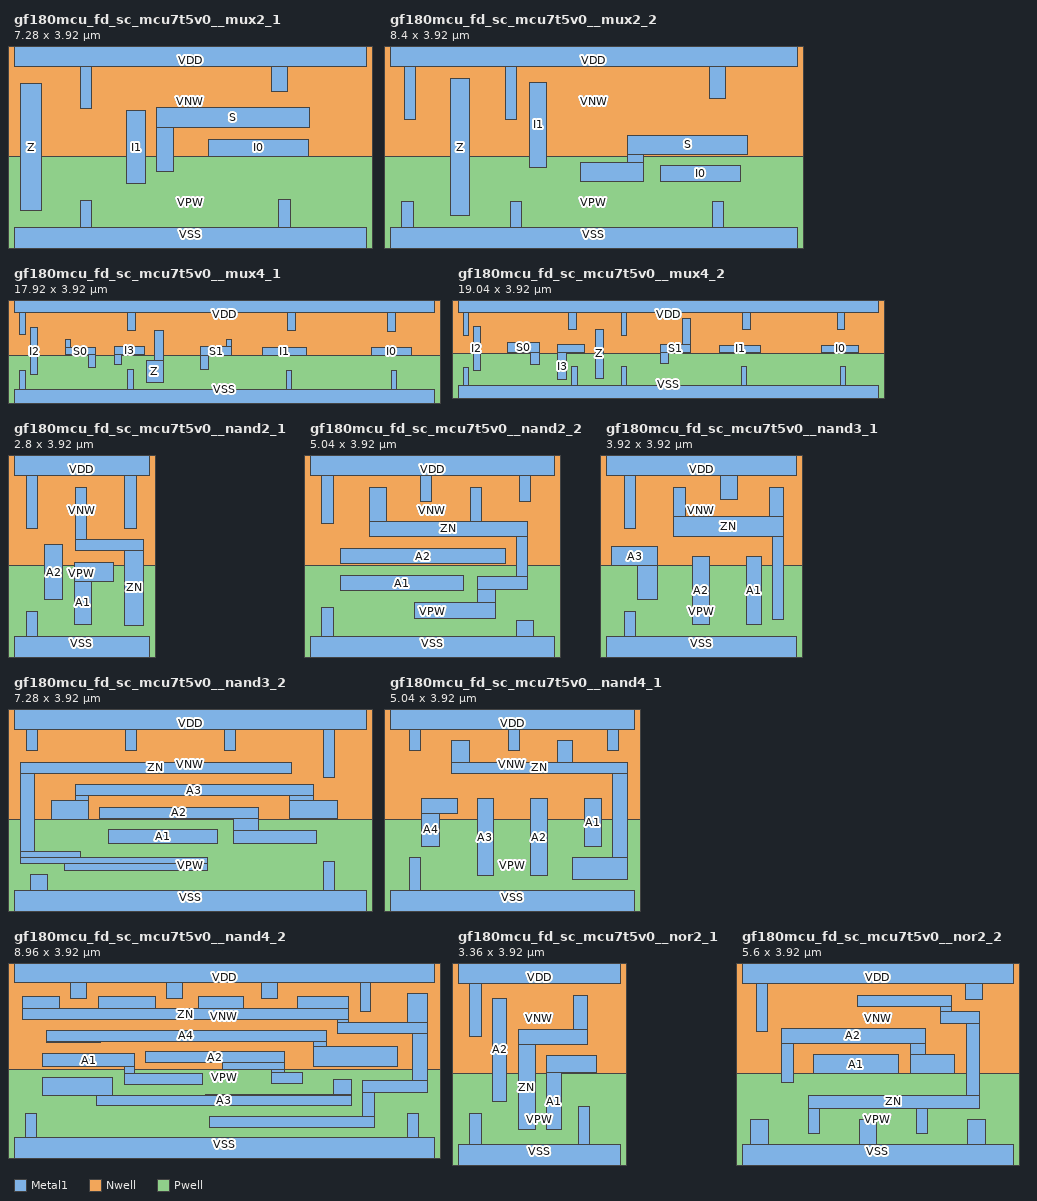
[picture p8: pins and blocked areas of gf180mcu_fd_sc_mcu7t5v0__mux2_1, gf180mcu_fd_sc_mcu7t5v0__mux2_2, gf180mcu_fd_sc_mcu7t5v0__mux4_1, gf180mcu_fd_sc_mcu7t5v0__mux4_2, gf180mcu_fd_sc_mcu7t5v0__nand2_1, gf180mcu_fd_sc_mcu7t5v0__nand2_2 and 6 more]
MACRO gf180mcu_fd_sc_mcu7t5v0__mux2_1
  CLASS core ;
  FOREIGN gf180mcu_fd_sc_mcu7t5v0__mux2_1 ;
  ORIGIN 0.000 0.000 ;
  SIZE 7.280 BY 3.920 ;
  SYMMETRY X Y ;
  SITE GF018hv5v_mcu_sc7 ;
  PIN I0
    DIRECTION INPUT ;
    ANTENNAGATEAREA 0.523500 ;
    PORT
      LAYER Metal1 ;
        RECT 4.010 1.770 6.070 2.120 ;
    END
  END I0
  PIN I1
    DIRECTION INPUT ;
    ANTENNAGATEAREA 0.523500 ;
    PORT
      LAYER Metal1 ;
        RECT 2.330 1.210 2.710 2.710 ;
    END
  END I1
  PIN S
    DIRECTION INPUT ;
    ANTENNAGATEAREA 1.047000 ;
    PORT
      LAYER Metal1 ;
        RECT 2.940 2.360 6.090 2.785 ;
        RECT 2.940 1.445 3.295 2.360 ;
    END
  END S
  PIN Z
    DIRECTION OUTPUT ;
    ANTENNADIFFAREA 0.897600 ;
    PORT
      LAYER Metal1 ;
        RECT 0.130 0.650 0.575 3.270 ;
    END
  END Z
  PIN VDD
    DIRECTION INOUT ;
    USE POWER ;
    SHAPE ABUTMENT ;
    PORT
      LAYER Metal1 ;
        RECT 0.000 3.620 7.280 4.220 ;
        RECT 1.365 2.760 1.595 3.620 ;
        RECT 5.310 3.105 5.650 3.620 ;
    END
  END VDD
  PIN VNW
    DIRECTION INOUT ;
    USE POWER ;
    PORT
      LAYER Nwell ;
        RECT -0.430 1.760 7.710 4.350 ;
    END
  END VNW
  PIN VPW
    DIRECTION INOUT ;
    USE GROUND ;
    PORT
      LAYER Pwell ;
        RECT -0.430 -0.430 7.710 1.760 ;
    END
  END VPW
  PIN VSS
    DIRECTION INOUT ;
    USE GROUND ;
    SHAPE ABUTMENT ;
    PORT
      LAYER Metal1 ;
        RECT 1.365 0.300 1.595 0.865 ;
        RECT 5.465 0.300 5.695 0.880 ;
        RECT 0.000 -0.300 7.280 0.300 ;
    END
  END VSS
  OBS
      LAYER Metal1 ;
        RECT 1.825 3.110 3.890 3.340 ;
        RECT 1.825 1.625 2.055 3.110 ;
        RECT 0.840 1.390 2.055 1.625 ;
        RECT 1.825 0.815 2.055 1.390 ;
        RECT 6.350 1.375 6.815 3.380 ;
        RECT 4.125 1.145 6.815 1.375 ;
        RECT 1.825 0.575 3.880 0.815 ;
        RECT 6.350 0.530 6.815 1.145 ;
  END
END gf180mcu_fd_sc_mcu7t5v0__mux2_1

#--------EOF---------

MACRO gf180mcu_fd_sc_mcu7t5v0__mux2_2
  CLASS core ;
  FOREIGN gf180mcu_fd_sc_mcu7t5v0__mux2_2 ;
  ORIGIN 0.000 0.000 ;
  SIZE 8.400 BY 3.920 ;
  SYMMETRY X Y ;
  SITE GF018hv5v_mcu_sc7 ;
  PIN I0
    DIRECTION INPUT ;
    ANTENNAGATEAREA 1.102000 ;
    PORT
      LAYER Metal1 ;
        RECT 5.575 1.250 7.225 1.580 ;
    END
  END I0
  PIN I1
    DIRECTION INPUT ;
    ANTENNAGATEAREA 1.102000 ;
    PORT
      LAYER Metal1 ;
        RECT 2.880 1.545 3.230 3.285 ;
    END
  END I1
  PIN S
    DIRECTION INPUT ;
    ANTENNAGATEAREA 2.204000 ;
    PORT
      LAYER Metal1 ;
        RECT 4.910 1.810 7.370 2.195 ;
        RECT 4.910 1.650 5.220 1.810 ;
        RECT 3.920 1.250 5.220 1.650 ;
    END
  END S
  PIN Z
    DIRECTION OUTPUT ;
    ANTENNADIFFAREA 1.121800 ;
    PORT
      LAYER Metal1 ;
        RECT 1.250 0.540 1.650 3.380 ;
    END
  END Z
  PIN VDD
    DIRECTION INOUT ;
    USE POWER ;
    SHAPE ABUTMENT ;
    PORT
      LAYER Metal1 ;
        RECT 0.000 3.620 8.400 4.220 ;
        RECT 0.295 2.530 0.525 3.620 ;
        RECT 2.385 2.530 2.615 3.620 ;
        RECT 6.590 2.965 6.930 3.620 ;
    END
  END VDD
  PIN VNW
    DIRECTION INOUT ;
    USE POWER ;
    PORT
      LAYER Nwell ;
        RECT -0.430 1.760 8.830 4.350 ;
    END
  END VNW
  PIN VPW
    DIRECTION INOUT ;
    USE GROUND ;
    PORT
      LAYER Pwell ;
        RECT -0.430 -0.430 8.830 1.760 ;
    END
  END VPW
  PIN VSS
    DIRECTION INOUT ;
    USE GROUND ;
    SHAPE ABUTMENT ;
    PORT
      LAYER Metal1 ;
        RECT 0.245 0.300 0.475 0.835 ;
        RECT 2.485 0.300 2.715 0.835 ;
        RECT 6.645 0.300 6.875 0.835 ;
        RECT 0.000 -0.300 8.400 0.300 ;
    END
  END VSS
  OBS
      LAYER Metal1 ;
        RECT 3.460 2.965 5.260 3.195 ;
        RECT 1.945 1.315 2.175 1.780 ;
        RECT 3.460 1.315 3.690 2.965 ;
        RECT 7.665 2.725 8.050 3.390 ;
        RECT 4.320 2.490 8.050 2.725 ;
        RECT 4.320 1.960 4.660 2.490 ;
        RECT 1.945 1.085 3.690 1.315 ;
        RECT 3.460 0.780 3.690 1.085 ;
        RECT 3.460 0.550 4.820 0.780 ;
        RECT 7.710 0.540 8.050 2.490 ;
  END
END gf180mcu_fd_sc_mcu7t5v0__mux2_2

#--------EOF---------

MACRO gf180mcu_fd_sc_mcu7t5v0__mux4_1
  CLASS core ;
  FOREIGN gf180mcu_fd_sc_mcu7t5v0__mux4_1 ;
  ORIGIN 0.000 0.000 ;
  SIZE 17.920 BY 3.920 ;
  SYMMETRY X Y ;
  SITE GF018hv5v_mcu_sc7 ;
  PIN I0
    DIRECTION INPUT ;
    ANTENNAGATEAREA 0.501500 ;
    PORT
      LAYER Metal1 ;
        RECT 15.250 1.750 16.940 2.120 ;
    END
  END I0
  PIN I1
    DIRECTION INPUT ;
    ANTENNAGATEAREA 0.501500 ;
    PORT
      LAYER Metal1 ;
        RECT 10.590 1.780 12.500 2.130 ;
    END
  END I1
  PIN I2
    DIRECTION INPUT ;
    ANTENNAGATEAREA 0.501500 ;
    PORT
      LAYER Metal1 ;
        RECT 0.705 0.970 1.010 2.950 ;
    END
  END I2
  PIN I3
    DIRECTION INPUT ;
    ANTENNAGATEAREA 0.501500 ;
    PORT
      LAYER Metal1 ;
        RECT 4.300 1.800 5.550 2.150 ;
        RECT 4.300 1.375 4.585 1.800 ;
    END
  END I3
  PIN S0
    DIRECTION INPUT ;
    ANTENNAGATEAREA 1.504500 ;
    PORT
      LAYER Metal1 ;
        RECT 2.185 2.120 2.415 2.465 ;
        RECT 2.185 1.800 3.495 2.120 ;
        RECT 3.200 1.240 3.495 1.800 ;
    END
  END S0
  PIN S1
    DIRECTION INPUT ;
    ANTENNAGATEAREA 1.003000 ;
    PORT
      LAYER Metal1 ;
        RECT 9.070 2.150 9.300 2.465 ;
        RECT 7.960 1.770 9.300 2.150 ;
        RECT 7.960 1.165 8.300 1.770 ;
    END
  END S1
  PIN Z
    DIRECTION OUTPUT ;
    ANTENNADIFFAREA 0.510400 ;
    PORT
      LAYER Metal1 ;
        RECT 5.990 1.570 6.380 2.855 ;
        RECT 5.650 0.600 6.380 1.570 ;
    END
  END Z
  PIN VDD
    DIRECTION INOUT ;
    USE POWER ;
    SHAPE ABUTMENT ;
    PORT
      LAYER Metal1 ;
        RECT 0.000 3.620 17.920 4.220 ;
        RECT 0.245 2.685 0.475 3.620 ;
        RECT 4.845 2.845 5.185 3.620 ;
        RECT 11.670 2.845 12.015 3.620 ;
        RECT 15.955 2.815 16.295 3.620 ;
    END
  END VDD
  PIN VNW
    DIRECTION INOUT ;
    USE POWER ;
    PORT
      LAYER Nwell ;
        RECT -0.430 1.760 18.350 4.350 ;
    END
  END VNW
  PIN VPW
    DIRECTION INOUT ;
    USE GROUND ;
    PORT
      LAYER Pwell ;
        RECT -0.430 -0.430 18.350 1.760 ;
    END
  END VPW
  PIN VSS
    DIRECTION INOUT ;
    USE GROUND ;
    SHAPE ABUTMENT ;
    PORT
      LAYER Metal1 ;
        RECT 0.245 0.300 0.475 1.130 ;
        RECT 4.850 0.300 5.080 1.160 ;
        RECT 11.630 0.300 11.860 1.145 ;
        RECT 16.110 0.300 16.340 1.145 ;
        RECT 0.000 -0.300 17.920 0.300 ;
    END
  END VSS
  OBS
      LAYER Metal1 ;
        RECT 2.635 3.100 4.530 3.330 ;
        RECT 1.260 1.075 1.495 3.025 ;
        RECT 2.635 2.970 2.975 3.100 ;
        RECT 1.725 2.740 2.975 2.970 ;
        RECT 1.725 1.570 1.955 2.740 ;
        RECT 1.725 1.340 2.290 1.570 ;
        RECT 2.040 1.075 2.290 1.340 ;
        RECT 1.260 0.845 1.650 1.075 ;
        RECT 2.040 0.845 2.770 1.075 ;
        RECT 3.725 0.780 4.070 2.870 ;
        RECT 4.300 2.615 4.530 3.100 ;
        RECT 5.520 3.155 6.860 3.390 ;
        RECT 5.520 2.615 5.750 3.155 ;
        RECT 4.300 2.380 5.750 2.615 ;
        RECT 6.630 3.005 6.860 3.155 ;
        RECT 9.650 3.160 11.355 3.390 ;
        RECT 6.630 2.665 7.270 3.005 ;
        RECT 7.500 2.720 8.755 2.950 ;
        RECT 6.630 1.130 6.860 2.665 ;
        RECT 7.500 1.820 7.730 2.720 ;
        RECT 7.090 1.460 7.730 1.820 ;
        RECT 6.630 0.790 7.270 1.130 ;
        RECT 7.500 0.760 7.730 1.460 ;
        RECT 8.530 0.760 8.760 1.145 ;
        RECT 9.650 0.780 9.880 3.160 ;
        RECT 10.110 2.575 10.840 2.925 ;
        RECT 11.125 2.615 11.355 3.160 ;
        RECT 12.265 3.160 14.100 3.390 ;
        RECT 12.265 2.615 12.495 3.160 ;
        RECT 10.110 1.145 10.350 2.575 ;
        RECT 11.125 2.380 12.495 2.615 ;
        RECT 10.110 0.795 10.840 1.145 ;
        RECT 12.750 0.780 12.980 2.925 ;
        RECT 13.770 0.780 14.100 3.160 ;
        RECT 14.330 2.815 15.190 3.045 ;
        RECT 14.330 1.080 14.560 2.815 ;
        RECT 17.125 2.585 17.460 3.140 ;
        RECT 14.790 2.355 17.460 2.585 ;
        RECT 14.790 1.685 15.020 2.355 ;
        RECT 14.330 0.850 15.275 1.080 ;
        RECT 17.230 0.780 17.460 2.355 ;
        RECT 7.500 0.530 8.760 0.760 ;
  END
END gf180mcu_fd_sc_mcu7t5v0__mux4_1

#--------EOF---------

MACRO gf180mcu_fd_sc_mcu7t5v0__mux4_2
  CLASS core ;
  FOREIGN gf180mcu_fd_sc_mcu7t5v0__mux4_2 ;
  ORIGIN 0.000 0.000 ;
  SIZE 19.040 BY 3.920 ;
  SYMMETRY X Y ;
  SITE GF018hv5v_mcu_sc7 ;
  PIN I0
    DIRECTION INPUT ;
    ANTENNAGATEAREA 0.516500 ;
    PORT
      LAYER Metal1 ;
        RECT 16.485 1.780 18.175 2.120 ;
    END
  END I0
  PIN I1
    DIRECTION INPUT ;
    ANTENNAGATEAREA 0.516500 ;
    PORT
      LAYER Metal1 ;
        RECT 11.835 1.780 13.735 2.130 ;
    END
  END I1
  PIN I2
    DIRECTION INPUT ;
    ANTENNAGATEAREA 0.618000 ;
    PORT
      LAYER Metal1 ;
        RECT 0.705 0.970 1.010 2.950 ;
    END
  END I2
  PIN I3
    DIRECTION INPUT ;
    ANTENNAGATEAREA 0.618000 ;
    PORT
      LAYER Metal1 ;
        RECT 4.505 1.800 5.755 2.150 ;
        RECT 4.505 0.550 4.935 1.800 ;
    END
  END I3
  PIN S0
    DIRECTION INPUT ;
    ANTENNAGATEAREA 1.651000 ;
    PORT
      LAYER Metal1 ;
        RECT 2.255 1.800 3.700 2.250 ;
        RECT 3.300 1.240 3.700 1.800 ;
    END
  END S0
  PIN S1
    DIRECTION INPUT ;
    ANTENNAGATEAREA 1.033000 ;
    PORT
      LAYER Metal1 ;
        RECT 10.165 2.150 10.535 3.320 ;
        RECT 9.170 1.770 10.535 2.150 ;
        RECT 9.170 1.305 9.535 1.770 ;
    END
  END S1
  PIN Z
    DIRECTION OUTPUT ;
    ANTENNADIFFAREA 0.759200 ;
    PORT
      LAYER Metal1 ;
        RECT 6.230 0.600 6.600 2.855 ;
    END
  END Z
  PIN VDD
    DIRECTION INOUT ;
    USE POWER ;
    SHAPE ABUTMENT ;
    PORT
      LAYER Metal1 ;
        RECT 0.000 3.620 19.040 4.220 ;
        RECT 0.245 2.575 0.475 3.620 ;
        RECT 5.010 2.845 5.350 3.620 ;
        RECT 7.405 2.570 7.635 3.620 ;
        RECT 12.905 2.845 13.250 3.620 ;
        RECT 17.190 2.815 17.530 3.620 ;
    END
  END VDD
  PIN VNW
    DIRECTION INOUT ;
    USE POWER ;
    PORT
      LAYER Nwell ;
        RECT -0.430 1.760 19.470 4.350 ;
    END
  END VNW
  PIN VPW
    DIRECTION INOUT ;
    USE GROUND ;
    PORT
      LAYER Pwell ;
        RECT -0.430 -0.430 19.470 1.760 ;
    END
  END VPW
  PIN VSS
    DIRECTION INOUT ;
    USE GROUND ;
    SHAPE ABUTMENT ;
    PORT
      LAYER Metal1 ;
        RECT 0.245 0.300 0.475 1.130 ;
        RECT 5.165 0.300 5.395 1.160 ;
        RECT 7.405 0.300 7.635 1.160 ;
        RECT 12.865 0.300 13.095 1.145 ;
        RECT 17.345 0.300 17.575 1.145 ;
        RECT 0.000 -0.300 19.040 0.300 ;
    END
  END VSS
  OBS
      LAYER Metal1 ;
        RECT 2.710 3.100 4.735 3.330 ;
        RECT 2.710 2.970 3.050 3.100 ;
        RECT 1.260 1.075 1.495 2.950 ;
        RECT 1.725 2.740 3.050 2.970 ;
        RECT 1.725 1.570 1.955 2.740 ;
        RECT 1.725 1.340 2.290 1.570 ;
        RECT 2.040 1.075 2.290 1.340 ;
        RECT 1.260 0.845 1.650 1.075 ;
        RECT 2.040 0.845 2.910 1.075 ;
        RECT 3.930 0.780 4.275 2.870 ;
        RECT 4.505 2.615 4.735 3.100 ;
        RECT 5.670 3.155 7.095 3.390 ;
        RECT 5.670 2.615 5.900 3.155 ;
        RECT 4.505 2.380 5.900 2.615 ;
        RECT 6.865 2.275 7.095 3.155 ;
        RECT 10.885 3.160 12.590 3.390 ;
        RECT 7.865 2.665 8.480 3.005 ;
        RECT 8.710 2.720 9.880 2.950 ;
        RECT 7.865 2.275 8.095 2.665 ;
        RECT 6.865 2.045 8.095 2.275 ;
        RECT 7.865 1.130 8.095 2.045 ;
        RECT 8.710 1.820 8.940 2.720 ;
        RECT 8.325 1.460 8.940 1.820 ;
        RECT 7.865 0.790 8.480 1.130 ;
        RECT 8.710 1.075 8.940 1.460 ;
        RECT 8.710 0.845 9.950 1.075 ;
        RECT 10.885 0.780 11.115 3.160 ;
        RECT 11.345 2.575 12.075 2.925 ;
        RECT 12.360 2.615 12.590 3.160 ;
        RECT 13.500 3.160 15.335 3.390 ;
        RECT 13.500 2.615 13.730 3.160 ;
        RECT 11.345 1.145 11.595 2.575 ;
        RECT 12.360 2.380 13.730 2.615 ;
        RECT 11.345 0.795 12.075 1.145 ;
        RECT 13.985 0.780 14.215 2.925 ;
        RECT 15.005 0.780 15.335 3.160 ;
        RECT 15.565 2.815 16.425 3.045 ;
        RECT 15.565 1.080 15.795 2.815 ;
        RECT 18.360 2.585 18.695 3.140 ;
        RECT 16.025 2.355 18.695 2.585 ;
        RECT 16.025 1.675 16.255 2.355 ;
        RECT 15.565 0.850 16.510 1.080 ;
        RECT 18.465 0.780 18.695 2.355 ;
  END
END gf180mcu_fd_sc_mcu7t5v0__mux4_2

#--------EOF---------

MACRO gf180mcu_fd_sc_mcu7t5v0__nand2_1
  CLASS core ;
  FOREIGN gf180mcu_fd_sc_mcu7t5v0__nand2_1 ;
  ORIGIN 0.000 0.000 ;
  SIZE 2.800 BY 3.920 ;
  SYMMETRY X Y ;
  SITE GF018hv5v_mcu_sc7 ;
  PIN A1
    DIRECTION INPUT ;
    ANTENNAGATEAREA 1.057000 ;
    PORT
      LAYER Metal1 ;
        RECT 1.240 1.440 2.055 1.820 ;
        RECT 1.240 0.555 1.605 1.440 ;
    END
  END A1
  PIN A2
    DIRECTION INPUT ;
    ANTENNAGATEAREA 1.057000 ;
    PORT
      LAYER Metal1 ;
        RECT 0.635 1.060 1.000 2.190 ;
    END
  END A2
  PIN ZN
    DIRECTION OUTPUT ;
    ANTENNADIFFAREA 0.948400 ;
    PORT
      LAYER Metal1 ;
        RECT 1.270 2.300 1.500 3.380 ;
        RECT 1.270 2.070 2.680 2.300 ;
        RECT 2.290 0.530 2.680 2.070 ;
    END
  END ZN
  PIN VDD
    DIRECTION INOUT ;
    USE POWER ;
    SHAPE ABUTMENT ;
    PORT
      LAYER Metal1 ;
        RECT 0.000 3.620 2.800 4.220 ;
        RECT 0.250 2.530 0.480 3.620 ;
        RECT 2.290 2.530 2.520 3.620 ;
    END
  END VDD
  PIN VNW
    DIRECTION INOUT ;
    USE POWER ;
    PORT
      LAYER Nwell ;
        RECT -0.430 1.760 3.230 4.350 ;
    END
  END VNW
  PIN VPW
    DIRECTION INOUT ;
    USE GROUND ;
    PORT
      LAYER Pwell ;
        RECT -0.430 -0.430 3.230 1.760 ;
    END
  END VPW
  PIN VSS
    DIRECTION INOUT ;
    USE GROUND ;
    SHAPE ABUTMENT ;
    PORT
      LAYER Metal1 ;
        RECT 0.250 0.300 0.480 0.805 ;
        RECT 0.000 -0.300 2.800 0.300 ;
    END
  END VSS
END gf180mcu_fd_sc_mcu7t5v0__nand2_1

#--------EOF---------

MACRO gf180mcu_fd_sc_mcu7t5v0__nand2_2
  CLASS core ;
  FOREIGN gf180mcu_fd_sc_mcu7t5v0__nand2_2 ;
  ORIGIN 0.000 0.000 ;
  SIZE 5.040 BY 3.920 ;
  SYMMETRY X Y ;
  SITE GF018hv5v_mcu_sc7 ;
  PIN A1
    DIRECTION INPUT ;
    ANTENNAGATEAREA 2.114000 ;
    PORT
      LAYER Metal1 ;
        RECT 0.620 1.240 3.160 1.560 ;
    END
  END A1
  PIN A2
    DIRECTION INPUT ;
    ANTENNAGATEAREA 2.114000 ;
    PORT
      LAYER Metal1 ;
        RECT 0.620 1.800 4.030 2.120 ;
    END
  END A2
  PIN ZN
    DIRECTION OUTPUT ;
    ANTENNADIFFAREA 1.601600 ;
    PORT
      LAYER Metal1 ;
        RECT 1.220 2.680 1.580 3.380 ;
        RECT 3.305 2.680 3.535 3.380 ;
        RECT 1.220 2.360 4.490 2.680 ;
        RECT 4.260 1.535 4.490 2.360 ;
        RECT 3.460 1.265 4.490 1.535 ;
        RECT 3.460 1.000 3.820 1.265 ;
        RECT 2.150 0.680 3.820 1.000 ;
    END
  END ZN
  PIN VDD
    DIRECTION INOUT ;
    USE POWER ;
    SHAPE ABUTMENT ;
    PORT
      LAYER Metal1 ;
        RECT 0.000 3.620 5.040 4.220 ;
        RECT 0.245 2.640 0.475 3.620 ;
        RECT 2.285 3.085 2.515 3.620 ;
        RECT 4.325 3.085 4.555 3.620 ;
    END
  END VDD
  PIN VNW
    DIRECTION INOUT ;
    USE POWER ;
    PORT
      LAYER Nwell ;
        RECT -0.430 1.760 5.470 4.350 ;
    END
  END VNW
  PIN VPW
    DIRECTION INOUT ;
    USE GROUND ;
    PORT
      LAYER Pwell ;
        RECT -0.430 -0.430 5.470 1.760 ;
    END
  END VPW
  PIN VSS
    DIRECTION INOUT ;
    USE GROUND ;
    SHAPE ABUTMENT ;
    PORT
      LAYER Metal1 ;
        RECT 0.245 0.300 0.475 0.905 ;
        RECT 4.260 0.300 4.620 0.635 ;
        RECT 0.000 -0.300 5.040 0.300 ;
    END
  END VSS
END gf180mcu_fd_sc_mcu7t5v0__nand2_2

#--------EOF---------

MACRO gf180mcu_fd_sc_mcu7t5v0__nand3_1
  CLASS core ;
  FOREIGN gf180mcu_fd_sc_mcu7t5v0__nand3_1 ;
  ORIGIN 0.000 0.000 ;
  SIZE 3.920 BY 3.920 ;
  SYMMETRY X Y ;
  SITE GF018hv5v_mcu_sc7 ;
  PIN A1
    DIRECTION INPUT ;
    ANTENNAGATEAREA 0.984500 ;
    PORT
      LAYER Metal1 ;
        RECT 2.900 0.550 3.210 1.960 ;
    END
  END A1
  PIN A2
    DIRECTION INPUT ;
    ANTENNAGATEAREA 0.984500 ;
    PORT
      LAYER Metal1 ;
        RECT 1.780 0.550 2.140 1.960 ;
    END
  END A2
  PIN A3
    DIRECTION INPUT ;
    ANTENNAGATEAREA 0.984500 ;
    PORT
      LAYER Metal1 ;
        RECT 0.120 1.760 1.065 2.150 ;
        RECT 0.660 1.055 1.065 1.760 ;
    END
  END A3
  PIN ZN
    DIRECTION OUTPUT ;
    ANTENNADIFFAREA 1.306400 ;
    PORT
      LAYER Metal1 ;
        RECT 1.400 2.780 1.630 3.380 ;
        RECT 3.380 2.780 3.670 3.380 ;
        RECT 1.400 2.360 3.670 2.780 ;
        RECT 3.440 0.655 3.670 2.360 ;
    END
  END ZN
  PIN VDD
    DIRECTION INOUT ;
    USE POWER ;
    SHAPE ABUTMENT ;
    PORT
      LAYER Metal1 ;
        RECT 0.000 3.620 3.920 4.220 ;
        RECT 0.380 2.530 0.610 3.620 ;
        RECT 2.365 3.130 2.705 3.620 ;
    END
  END VDD
  PIN VNW
    DIRECTION INOUT ;
    USE POWER ;
    PORT
      LAYER Nwell ;
        RECT -0.430 1.760 4.350 4.350 ;
    END
  END VNW
  PIN VPW
    DIRECTION INOUT ;
    USE GROUND ;
    PORT
      LAYER Pwell ;
        RECT -0.430 -0.430 4.350 1.760 ;
    END
  END VPW
  PIN VSS
    DIRECTION INOUT ;
    USE GROUND ;
    SHAPE ABUTMENT ;
    PORT
      LAYER Metal1 ;
        RECT 0.380 0.300 0.610 0.805 ;
        RECT 0.000 -0.300 3.920 0.300 ;
    END
  END VSS
END gf180mcu_fd_sc_mcu7t5v0__nand3_1

#--------EOF---------

MACRO gf180mcu_fd_sc_mcu7t5v0__nand3_2
  CLASS core ;
  FOREIGN gf180mcu_fd_sc_mcu7t5v0__nand3_2 ;
  ORIGIN 0.000 0.000 ;
  SIZE 7.280 BY 3.920 ;
  SYMMETRY X Y ;
  SITE GF018hv5v_mcu_sc7 ;
  PIN A1
    DIRECTION INPUT ;
    ANTENNAGATEAREA 1.969000 ;
    PORT
      LAYER Metal1 ;
        RECT 1.950 1.265 4.200 1.555 ;
    END
  END A1
  PIN A2
    DIRECTION INPUT ;
    ANTENNAGATEAREA 1.969000 ;
    PORT
      LAYER Metal1 ;
        RECT 1.770 1.785 5.050 2.020 ;
        RECT 4.530 1.535 5.050 1.785 ;
        RECT 4.530 1.260 6.245 1.535 ;
    END
  END A2
  PIN A3
    DIRECTION INPUT ;
    ANTENNAGATEAREA 1.969000 ;
    PORT
      LAYER Metal1 ;
        RECT 1.265 2.250 6.175 2.485 ;
        RECT 1.265 2.150 1.540 2.250 ;
        RECT 0.780 1.770 1.540 2.150 ;
        RECT 5.690 2.150 6.175 2.250 ;
        RECT 5.690 1.785 6.670 2.150 ;
    END
  END A3
  PIN ZN
    DIRECTION OUTPUT ;
    ANTENNADIFFAREA 1.963000 ;
    PORT
      LAYER Metal1 ;
        RECT 0.130 2.715 5.725 2.950 ;
        RECT 0.130 1.100 0.430 2.715 ;
        RECT 0.130 0.975 1.370 1.100 ;
        RECT 0.130 0.865 3.995 0.975 ;
        RECT 1.040 0.705 3.995 0.865 ;
    END
  END ZN
  PIN VDD
    DIRECTION INOUT ;
    USE POWER ;
    SHAPE ABUTMENT ;
    PORT
      LAYER Metal1 ;
        RECT 0.000 3.620 7.280 4.220 ;
        RECT 0.265 3.180 0.495 3.620 ;
        RECT 2.305 3.180 2.535 3.620 ;
        RECT 4.345 3.180 4.575 3.620 ;
        RECT 6.385 2.640 6.615 3.620 ;
    END
  END VDD
  PIN VNW
    DIRECTION INOUT ;
    USE POWER ;
    PORT
      LAYER Nwell ;
        RECT -0.430 1.760 7.710 4.350 ;
    END
  END VNW
  PIN VPW
    DIRECTION INOUT ;
    USE GROUND ;
    PORT
      LAYER Pwell ;
        RECT -0.430 -0.430 7.710 1.760 ;
    END
  END VPW
  PIN VSS
    DIRECTION INOUT ;
    USE GROUND ;
    SHAPE ABUTMENT ;
    PORT
      LAYER Metal1 ;
        RECT 0.350 0.300 0.690 0.635 ;
        RECT 6.385 0.300 6.615 0.900 ;
        RECT 0.000 -0.300 7.280 0.300 ;
    END
  END VSS
END gf180mcu_fd_sc_mcu7t5v0__nand3_2

#--------EOF---------

MACRO gf180mcu_fd_sc_mcu7t5v0__nand4_1
  CLASS core ;
  FOREIGN gf180mcu_fd_sc_mcu7t5v0__nand4_1 ;
  ORIGIN 0.000 0.000 ;
  SIZE 5.040 BY 3.920 ;
  SYMMETRY X Y ;
  SITE GF018hv5v_mcu_sc7 ;
  PIN A1
    DIRECTION INPUT ;
    ANTENNAGATEAREA 0.914500 ;
    PORT
      LAYER Metal1 ;
        RECT 4.020 1.210 4.370 2.190 ;
    END
  END A1
  PIN A2
    DIRECTION INPUT ;
    ANTENNAGATEAREA 0.914500 ;
    PORT
      LAYER Metal1 ;
        RECT 2.900 0.610 3.240 2.190 ;
    END
  END A2
  PIN A3
    DIRECTION INPUT ;
    ANTENNAGATEAREA 0.914500 ;
    PORT
      LAYER Metal1 ;
        RECT 1.800 0.610 2.140 2.190 ;
    END
  END A3
  PIN A4
    DIRECTION INPUT ;
    ANTENNAGATEAREA 0.914500 ;
    PORT
      LAYER Metal1 ;
        RECT 0.660 1.890 1.400 2.190 ;
        RECT 0.660 1.210 1.020 1.890 ;
    END
  END A4
  PIN ZN
    DIRECTION OUTPUT ;
    ANTENNADIFFAREA 1.239600 ;
    PORT
      LAYER Metal1 ;
        RECT 1.260 2.945 1.650 3.390 ;
        RECT 3.460 2.950 3.770 3.390 ;
        RECT 3.460 2.945 4.910 2.950 ;
        RECT 1.260 2.715 4.910 2.945 ;
        RECT 4.600 0.980 4.910 2.715 ;
        RECT 3.775 0.530 4.910 0.980 ;
    END
  END ZN
  PIN VDD
    DIRECTION INOUT ;
    USE POWER ;
    SHAPE ABUTMENT ;
    PORT
      LAYER Metal1 ;
        RECT 0.000 3.620 5.040 4.220 ;
        RECT 0.400 3.180 0.630 3.620 ;
        RECT 2.440 3.180 2.670 3.620 ;
        RECT 4.480 3.180 4.710 3.620 ;
    END
  END VDD
  PIN VNW
    DIRECTION INOUT ;
    USE POWER ;
    PORT
      LAYER Nwell ;
        RECT -0.430 1.760 5.470 4.350 ;
    END
  END VNW
  PIN VPW
    DIRECTION INOUT ;
    USE GROUND ;
    PORT
      LAYER Pwell ;
        RECT -0.430 -0.430 5.470 1.760 ;
    END
  END VPW
  PIN VSS
    DIRECTION INOUT ;
    USE GROUND ;
    SHAPE ABUTMENT ;
    PORT
      LAYER Metal1 ;
        RECT 0.400 0.300 0.630 0.980 ;
        RECT 0.000 -0.300 5.040 0.300 ;
    END
  END VSS
END gf180mcu_fd_sc_mcu7t5v0__nand4_1

#--------EOF---------

MACRO gf180mcu_fd_sc_mcu7t5v0__nand4_2
  CLASS core ;
  FOREIGN gf180mcu_fd_sc_mcu7t5v0__nand4_2 ;
  ORIGIN 0.000 0.000 ;
  SIZE 8.960 BY 3.920 ;
  SYMMETRY X Y ;
  SITE GF018hv5v_mcu_sc7 ;
  PIN A1
    DIRECTION INPUT ;
    ANTENNAGATEAREA 1.829000 ;
    PORT
      LAYER Metal1 ;
        RECT 0.610 1.820 2.580 2.100 ;
        RECT 2.350 1.675 2.580 1.820 ;
        RECT 2.350 1.445 4.030 1.675 ;
    END
  END A1
  PIN A2
    DIRECTION INPUT ;
    ANTENNAGATEAREA 1.829000 ;
    PORT
      LAYER Metal1 ;
        RECT 2.810 1.905 5.775 2.135 ;
        RECT 4.455 1.750 5.775 1.905 ;
        RECT 5.500 1.695 5.775 1.750 ;
        RECT 5.500 1.465 6.150 1.695 ;
    END
  END A2
  PIN A3
    DIRECTION INPUT ;
    ANTENNAGATEAREA 1.829000 ;
    PORT
      LAYER Metal1 ;
        RECT 0.610 1.215 2.095 1.590 ;
        RECT 6.810 1.220 7.190 1.555 ;
        RECT 4.080 1.215 7.190 1.220 ;
        RECT 0.610 1.210 7.190 1.215 ;
        RECT 1.755 0.990 7.190 1.210 ;
        RECT 1.755 0.985 4.130 0.990 ;
    END
  END A3
  PIN A4
    DIRECTION INPUT ;
    ANTENNAGATEAREA 1.829000 ;
    PORT
      LAYER Metal1 ;
        RECT 0.690 2.365 6.660 2.595 ;
        RECT 0.690 2.340 1.845 2.365 ;
        RECT 6.380 2.260 6.660 2.365 ;
        RECT 6.380 1.825 8.190 2.260 ;
    END
  END A4
  PIN ZN
    DIRECTION OUTPUT ;
    ANTENNADIFFAREA 2.488200 ;
    PORT
      LAYER Metal1 ;
        RECT 0.180 3.055 0.980 3.310 ;
        RECT 1.810 3.055 3.020 3.310 ;
        RECT 3.935 3.055 4.900 3.310 ;
        RECT 6.055 3.055 7.140 3.310 ;
        RECT 0.180 2.825 7.140 3.055 ;
        RECT 6.910 2.760 7.140 2.825 ;
        RECT 8.405 2.760 8.815 3.390 ;
        RECT 6.910 2.525 8.815 2.760 ;
        RECT 8.495 1.535 8.815 2.525 ;
        RECT 7.425 1.265 8.815 1.535 ;
        RECT 7.425 0.760 7.695 1.265 ;
        RECT 4.180 0.530 7.695 0.760 ;
    END
  END ZN
  PIN VDD
    DIRECTION INOUT ;
    USE POWER ;
    SHAPE ABUTMENT ;
    PORT
      LAYER Metal1 ;
        RECT 0.000 3.620 8.960 4.220 ;
        RECT 1.210 3.285 1.550 3.620 ;
        RECT 3.250 3.285 3.590 3.620 ;
        RECT 5.290 3.285 5.630 3.620 ;
        RECT 7.385 3.000 7.615 3.620 ;
    END
  END VDD
  PIN VNW
    DIRECTION INOUT ;
    USE POWER ;
    PORT
      LAYER Nwell ;
        RECT -0.430 1.760 9.390 4.350 ;
    END
  END VNW
  PIN VPW
    DIRECTION INOUT ;
    USE GROUND ;
    PORT
      LAYER Pwell ;
        RECT -0.430 -0.430 9.390 1.760 ;
    END
  END VPW
  PIN VSS
    DIRECTION INOUT ;
    USE GROUND ;
    SHAPE ABUTMENT ;
    PORT
      LAYER Metal1 ;
        RECT 0.245 0.300 0.475 0.830 ;
        RECT 8.405 0.300 8.635 0.830 ;
        RECT 0.000 -0.300 8.960 0.300 ;
    END
  END VSS
END gf180mcu_fd_sc_mcu7t5v0__nand4_2

#--------EOF---------

MACRO gf180mcu_fd_sc_mcu7t5v0__nor2_1
  CLASS core ;
  FOREIGN gf180mcu_fd_sc_mcu7t5v0__nor2_1 ;
  ORIGIN 0.000 0.000 ;
  SIZE 3.360 BY 3.920 ;
  SYMMETRY X Y ;
  SITE GF018hv5v_mcu_sc7 ;
  PIN A1
    DIRECTION INPUT ;
    ANTENNAGATEAREA 0.949000 ;
    PORT
      LAYER Metal1 ;
        RECT 1.825 1.790 2.855 2.130 ;
        RECT 1.825 0.600 2.130 1.790 ;
    END
  END A1
  PIN A2
    DIRECTION INPUT ;
    ANTENNAGATEAREA 0.949000 ;
    PORT
      LAYER Metal1 ;
        RECT 0.705 1.180 1.010 3.320 ;
    END
  END A2
  PIN ZN
    DIRECTION OUTPUT ;
    ANTENNADIFFAREA 0.830600 ;
    PORT
      LAYER Metal1 ;
        RECT 2.385 2.680 2.665 3.380 ;
        RECT 1.240 2.360 2.665 2.680 ;
        RECT 1.240 0.600 1.595 2.360 ;
    END
  END ZN
  PIN VDD
    DIRECTION INOUT ;
    USE POWER ;
    SHAPE ABUTMENT ;
    PORT
      LAYER Metal1 ;
        RECT 0.000 3.620 3.360 4.220 ;
        RECT 0.245 2.530 0.475 3.620 ;
    END
  END VDD
  PIN VNW
    DIRECTION INOUT ;
    USE POWER ;
    PORT
      LAYER Nwell ;
        RECT -0.430 1.760 3.790 4.350 ;
    END
  END VNW
  PIN VPW
    DIRECTION INOUT ;
    USE GROUND ;
    PORT
      LAYER Pwell ;
        RECT -0.430 -0.430 3.790 1.760 ;
    END
  END VPW
  PIN VSS
    DIRECTION INOUT ;
    USE GROUND ;
    SHAPE ABUTMENT ;
    PORT
      LAYER Metal1 ;
        RECT 0.245 0.300 0.475 0.945 ;
        RECT 2.485 0.300 2.715 1.090 ;
        RECT 0.000 -0.300 3.360 0.300 ;
    END
  END VSS
END gf180mcu_fd_sc_mcu7t5v0__nor2_1

#--------EOF---------

MACRO gf180mcu_fd_sc_mcu7t5v0__nor2_2
  CLASS core ;
  FOREIGN gf180mcu_fd_sc_mcu7t5v0__nor2_2 ;
  ORIGIN 0.000 0.000 ;
  SIZE 5.600 BY 3.920 ;
  SYMMETRY X Y ;
  SITE GF018hv5v_mcu_sc7 ;
  PIN A1
    DIRECTION INPUT ;
    ANTENNAGATEAREA 1.898000 ;
    PORT
      LAYER Metal1 ;
        RECT 1.480 1.770 3.220 2.150 ;
    END
  END A1
  PIN A2
    DIRECTION INPUT ;
    ANTENNAGATEAREA 1.898000 ;
    PORT
      LAYER Metal1 ;
        RECT 0.810 2.380 3.780 2.700 ;
        RECT 0.810 1.580 1.060 2.380 ;
        RECT 3.480 2.150 3.780 2.380 ;
        RECT 3.480 1.770 4.390 2.150 ;
    END
  END A2
  PIN ZN
    DIRECTION OUTPUT ;
    ANTENNADIFFAREA 1.283000 ;
    PORT
      LAYER Metal1 ;
        RECT 2.390 3.140 4.325 3.370 ;
        RECT 4.095 3.035 4.325 3.140 ;
        RECT 4.095 2.800 4.895 3.035 ;
        RECT 4.625 1.320 4.895 2.800 ;
        RECT 1.365 1.050 4.895 1.320 ;
        RECT 1.365 0.530 1.595 1.050 ;
        RECT 3.605 0.530 3.835 1.050 ;
    END
  END ZN
  PIN VDD
    DIRECTION INOUT ;
    USE POWER ;
    SHAPE ABUTMENT ;
    PORT
      LAYER Metal1 ;
        RECT 0.000 3.620 5.600 4.220 ;
        RECT 0.295 2.625 0.525 3.620 ;
        RECT 4.610 3.285 4.970 3.620 ;
    END
  END VDD
  PIN VNW
    DIRECTION INOUT ;
    USE POWER ;
    PORT
      LAYER Nwell ;
        RECT -0.430 1.760 6.030 4.350 ;
    END
  END VNW
  PIN VPW
    DIRECTION INOUT ;
    USE GROUND ;
    PORT
      LAYER Pwell ;
        RECT -0.430 -0.430 6.030 1.760 ;
    END
  END VPW
  PIN VSS
    DIRECTION INOUT ;
    USE GROUND ;
    SHAPE ABUTMENT ;
    PORT
      LAYER Metal1 ;
        RECT 0.180 0.300 0.540 0.820 ;
        RECT 2.420 0.300 2.780 0.820 ;
        RECT 4.660 0.300 5.020 0.820 ;
        RECT 0.000 -0.300 5.600 0.300 ;
    END
  END VSS
END gf180mcu_fd_sc_mcu7t5v0__nor2_2

#--------EOF---------

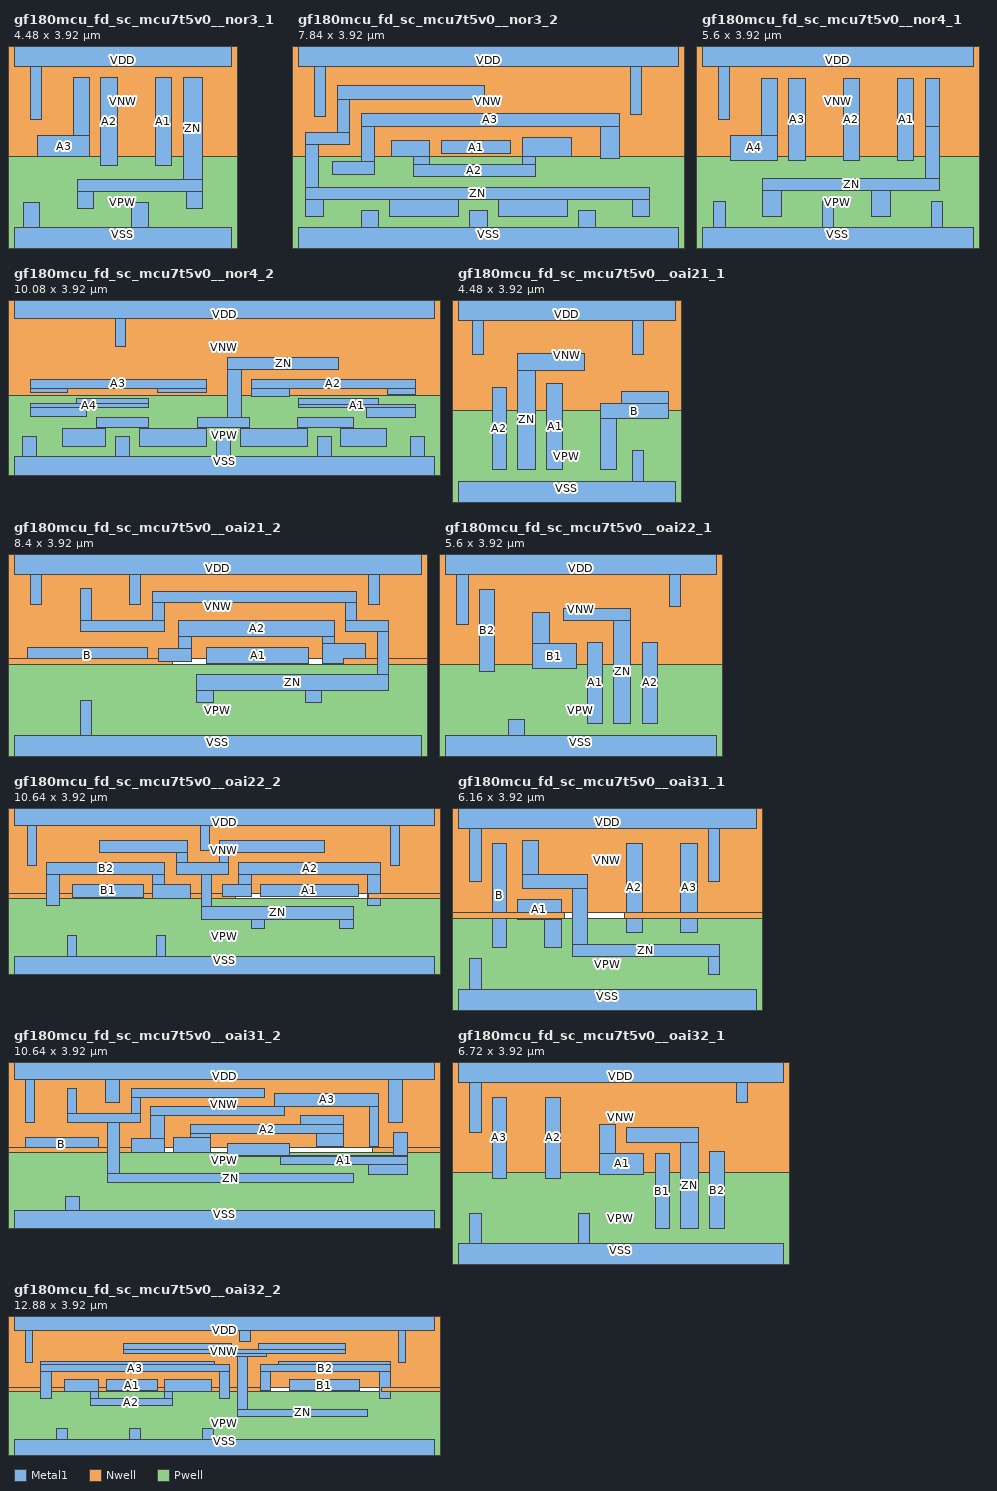
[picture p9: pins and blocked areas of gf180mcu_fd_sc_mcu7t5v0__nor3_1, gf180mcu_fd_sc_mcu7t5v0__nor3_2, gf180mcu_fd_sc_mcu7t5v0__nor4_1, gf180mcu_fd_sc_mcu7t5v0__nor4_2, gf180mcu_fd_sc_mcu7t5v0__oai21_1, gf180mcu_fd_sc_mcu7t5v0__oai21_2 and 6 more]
MACRO gf180mcu_fd_sc_mcu7t5v0__nor3_1
  CLASS core ;
  FOREIGN gf180mcu_fd_sc_mcu7t5v0__nor3_1 ;
  ORIGIN 0.000 0.000 ;
  SIZE 4.480 BY 3.920 ;
  SYMMETRY X Y ;
  SITE GF018hv5v_mcu_sc7 ;
  PIN A1
    DIRECTION INPUT ;
    ANTENNAGATEAREA 0.889000 ;
    PORT
      LAYER Metal1 ;
        RECT 2.910 1.575 3.250 3.390 ;
    END
  END A1
  PIN A2
    DIRECTION INPUT ;
    ANTENNAGATEAREA 0.889000 ;
    PORT
      LAYER Metal1 ;
        RECT 1.790 1.575 2.130 3.390 ;
    END
  END A2
  PIN A3
    DIRECTION INPUT ;
    ANTENNAGATEAREA 0.889000 ;
    PORT
      LAYER Metal1 ;
        RECT 1.220 2.190 1.560 3.390 ;
        RECT 0.490 1.760 1.560 2.190 ;
    END
  END A3
  PIN ZN
    DIRECTION OUTPUT ;
    ANTENNADIFFAREA 0.983200 ;
    PORT
      LAYER Metal1 ;
        RECT 3.490 1.285 3.890 3.390 ;
        RECT 1.310 1.050 3.890 1.285 ;
        RECT 1.310 0.695 1.650 1.050 ;
        RECT 3.550 0.695 3.890 1.050 ;
    END
  END ZN
  PIN VDD
    DIRECTION INOUT ;
    USE POWER ;
    SHAPE ABUTMENT ;
    PORT
      LAYER Metal1 ;
        RECT 0.000 3.620 4.480 4.220 ;
        RECT 0.345 2.530 0.575 3.620 ;
    END
  END VDD
  PIN VNW
    DIRECTION INOUT ;
    USE POWER ;
    PORT
      LAYER Nwell ;
        RECT -0.430 1.760 4.910 4.350 ;
    END
  END VNW
  PIN VPW
    DIRECTION INOUT ;
    USE GROUND ;
    PORT
      LAYER Pwell ;
        RECT -0.430 -0.430 4.910 1.760 ;
    END
  END VPW
  PIN VSS
    DIRECTION INOUT ;
    USE GROUND ;
    SHAPE ABUTMENT ;
    PORT
      LAYER Metal1 ;
        RECT 0.190 0.300 0.530 0.820 ;
        RECT 2.430 0.300 2.770 0.820 ;
        RECT 0.000 -0.300 4.480 0.300 ;
    END
  END VSS
END gf180mcu_fd_sc_mcu7t5v0__nor3_1

#--------EOF---------

MACRO gf180mcu_fd_sc_mcu7t5v0__nor3_2
  CLASS core ;
  FOREIGN gf180mcu_fd_sc_mcu7t5v0__nor3_2 ;
  ORIGIN 0.000 0.000 ;
  SIZE 7.840 BY 3.920 ;
  SYMMETRY X Y ;
  SITE GF018hv5v_mcu_sc7 ;
  PIN A1
    DIRECTION INPUT ;
    ANTENNAGATEAREA 1.778000 ;
    PORT
      LAYER Metal1 ;
        RECT 2.955 1.825 4.390 2.095 ;
    END
  END A1
  PIN A2
    DIRECTION INPUT ;
    ANTENNAGATEAREA 1.778000 ;
    PORT
      LAYER Metal1 ;
        RECT 1.935 1.770 2.710 2.095 ;
        RECT 2.385 1.590 2.710 1.770 ;
        RECT 4.625 1.770 5.650 2.150 ;
        RECT 4.625 1.590 4.895 1.770 ;
        RECT 2.385 1.360 4.895 1.590 ;
    END
  END A2
  PIN A3
    DIRECTION INPUT ;
    ANTENNAGATEAREA 1.778000 ;
    PORT
      LAYER Metal1 ;
        RECT 1.305 2.380 6.630 2.655 ;
        RECT 1.305 1.665 1.580 2.380 ;
        RECT 6.250 1.730 6.630 2.380 ;
        RECT 0.705 1.390 1.580 1.665 ;
    END
  END A3
  PIN ZN
    DIRECTION OUTPUT ;
    ANTENNADIFFAREA 1.649200 ;
    PORT
      LAYER Metal1 ;
        RECT 0.825 2.940 3.840 3.235 ;
        RECT 0.825 2.250 1.055 2.940 ;
        RECT 0.145 2.020 1.055 2.250 ;
        RECT 0.145 1.115 0.420 2.020 ;
        RECT 0.145 0.885 7.250 1.115 ;
        RECT 0.145 0.530 0.530 0.885 ;
        RECT 1.890 0.530 3.310 0.885 ;
        RECT 4.130 0.530 5.550 0.885 ;
        RECT 6.905 0.530 7.250 0.885 ;
    END
  END ZN
  PIN VDD
    DIRECTION INOUT ;
    USE POWER ;
    SHAPE ABUTMENT ;
    PORT
      LAYER Metal1 ;
        RECT 0.000 3.620 7.840 4.220 ;
        RECT 0.345 2.590 0.575 3.620 ;
        RECT 6.865 2.630 7.095 3.620 ;
    END
  END VDD
  PIN VNW
    DIRECTION INOUT ;
    USE POWER ;
    PORT
      LAYER Nwell ;
        RECT -0.430 1.760 8.270 4.350 ;
    END
  END VNW
  PIN VPW
    DIRECTION INOUT ;
    USE GROUND ;
    PORT
      LAYER Pwell ;
        RECT -0.430 -0.430 8.270 1.760 ;
    END
  END VPW
  PIN VSS
    DIRECTION INOUT ;
    USE GROUND ;
    SHAPE ABUTMENT ;
    PORT
      LAYER Metal1 ;
        RECT 1.300 0.300 1.660 0.655 ;
        RECT 3.540 0.300 3.900 0.655 ;
        RECT 5.780 0.300 6.140 0.655 ;
        RECT 0.000 -0.300 7.840 0.300 ;
    END
  END VSS
END gf180mcu_fd_sc_mcu7t5v0__nor3_2

#--------EOF---------

MACRO gf180mcu_fd_sc_mcu7t5v0__nor4_1
  CLASS core ;
  FOREIGN gf180mcu_fd_sc_mcu7t5v0__nor4_1 ;
  ORIGIN 0.000 0.000 ;
  SIZE 5.600 BY 3.920 ;
  SYMMETRY X Y ;
  SITE GF018hv5v_mcu_sc7 ;
  PIN A1
    DIRECTION INPUT ;
    ANTENNAGATEAREA 0.826000 ;
    PORT
      LAYER Metal1 ;
        RECT 4.030 1.685 4.370 3.380 ;
    END
  END A1
  PIN A2
    DIRECTION INPUT ;
    ANTENNAGATEAREA 0.826000 ;
    PORT
      LAYER Metal1 ;
        RECT 2.910 1.685 3.250 3.380 ;
    END
  END A2
  PIN A3
    DIRECTION INPUT ;
    ANTENNAGATEAREA 0.826000 ;
    PORT
      LAYER Metal1 ;
        RECT 1.790 1.685 2.130 3.380 ;
    END
  END A3
  PIN A4
    DIRECTION INPUT ;
    ANTENNAGATEAREA 0.826000 ;
    PORT
      LAYER Metal1 ;
        RECT 1.220 2.195 1.560 3.380 ;
        RECT 0.585 1.685 1.560 2.195 ;
    END
  END A4
  PIN ZN
    DIRECTION OUTPUT ;
    ANTENNADIFFAREA 0.911200 ;
    PORT
      LAYER Metal1 ;
        RECT 4.610 2.380 4.905 3.380 ;
        RECT 4.610 1.305 4.910 2.380 ;
        RECT 1.255 1.070 4.910 1.305 ;
        RECT 1.255 0.530 1.650 1.070 ;
        RECT 3.505 0.530 3.890 1.070 ;
    END
  END ZN
  PIN VDD
    DIRECTION INOUT ;
    USE POWER ;
    SHAPE ABUTMENT ;
    PORT
      LAYER Metal1 ;
        RECT 0.000 3.620 5.600 4.220 ;
        RECT 0.345 2.530 0.575 3.620 ;
    END
  END VDD
  PIN VNW
    DIRECTION INOUT ;
    USE POWER ;
    PORT
      LAYER Nwell ;
        RECT -0.430 1.760 6.030 4.350 ;
    END
  END VNW
  PIN VPW
    DIRECTION INOUT ;
    USE GROUND ;
    PORT
      LAYER Pwell ;
        RECT -0.430 -0.430 6.030 1.760 ;
    END
  END VPW
  PIN VSS
    DIRECTION INOUT ;
    USE GROUND ;
    SHAPE ABUTMENT ;
    PORT
      LAYER Metal1 ;
        RECT 0.245 0.300 0.475 0.840 ;
        RECT 2.485 0.300 2.715 0.840 ;
        RECT 4.725 0.300 4.955 0.840 ;
        RECT 0.000 -0.300 5.600 0.300 ;
    END
  END VSS
END gf180mcu_fd_sc_mcu7t5v0__nor4_1

#--------EOF---------

MACRO gf180mcu_fd_sc_mcu7t5v0__nor4_2
  CLASS core ;
  FOREIGN gf180mcu_fd_sc_mcu7t5v0__nor4_2 ;
  ORIGIN 0.000 0.000 ;
  SIZE 10.080 BY 3.920 ;
  SYMMETRY X Y ;
  SITE GF018hv5v_mcu_sc7 ;
  PIN A1
    DIRECTION INPUT ;
    ANTENNAGATEAREA 1.652000 ;
    PORT
      LAYER Metal1 ;
        RECT 6.835 1.560 8.745 1.695 ;
        RECT 6.835 1.465 9.630 1.560 ;
        RECT 8.470 1.240 9.630 1.465 ;
    END
  END A1
  PIN A2
    DIRECTION INPUT ;
    ANTENNAGATEAREA 1.652000 ;
    PORT
      LAYER Metal1 ;
        RECT 5.690 1.930 9.630 2.160 ;
        RECT 5.690 1.750 6.605 1.930 ;
        RECT 8.975 1.800 9.630 1.930 ;
    END
  END A2
  PIN A3
    DIRECTION INPUT ;
    ANTENNAGATEAREA 1.652000 ;
    PORT
      LAYER Metal1 ;
        RECT 0.385 1.930 4.615 2.160 ;
        RECT 0.385 1.825 1.275 1.930 ;
        RECT 3.450 1.825 4.615 1.930 ;
    END
  END A3
  PIN A4
    DIRECTION INPUT ;
    ANTENNAGATEAREA 1.652000 ;
    PORT
      LAYER Metal1 ;
        RECT 1.505 1.565 3.220 1.695 ;
        RECT 0.385 1.465 3.220 1.565 ;
        RECT 0.385 1.265 1.735 1.465 ;
    END
  END A4
  PIN ZN
    DIRECTION OUTPUT ;
    ANTENNADIFFAREA 1.631000 ;
    PORT
      LAYER Metal1 ;
        RECT 5.130 2.390 7.790 2.665 ;
        RECT 5.130 1.235 5.460 2.390 ;
        RECT 1.975 1.005 3.235 1.235 ;
        RECT 1.975 0.975 2.205 1.005 ;
        RECT 1.170 0.530 2.205 0.975 ;
        RECT 3.005 0.975 3.235 1.005 ;
        RECT 4.395 1.005 5.655 1.235 ;
        RECT 4.395 0.975 4.625 1.005 ;
        RECT 3.005 0.530 4.625 0.975 ;
        RECT 5.425 0.975 5.655 1.005 ;
        RECT 6.815 1.005 8.145 1.235 ;
        RECT 6.815 0.975 7.045 1.005 ;
        RECT 5.425 0.530 7.045 0.975 ;
        RECT 7.845 0.975 8.145 1.005 ;
        RECT 7.845 0.530 8.950 0.975 ;
    END
  END ZN
  PIN VDD
    DIRECTION INOUT ;
    USE POWER ;
    SHAPE ABUTMENT ;
    PORT
      LAYER Metal1 ;
        RECT 0.000 3.620 10.080 4.220 ;
        RECT 2.440 2.935 2.670 3.620 ;
    END
  END VDD
  PIN VNW
    DIRECTION INOUT ;
    USE POWER ;
    PORT
      LAYER Nwell ;
        RECT -0.430 1.760 10.510 4.350 ;
    END
  END VNW
  PIN VPW
    DIRECTION INOUT ;
    USE GROUND ;
    PORT
      LAYER Pwell ;
        RECT -0.430 -0.430 10.510 1.760 ;
    END
  END VPW
  PIN VSS
    DIRECTION INOUT ;
    USE GROUND ;
    SHAPE ABUTMENT ;
    PORT
      LAYER Metal1 ;
        RECT 0.195 0.300 0.535 0.775 ;
        RECT 2.435 0.300 2.775 0.775 ;
        RECT 4.855 0.300 5.195 0.775 ;
        RECT 7.275 0.300 7.615 0.775 ;
        RECT 9.515 0.300 9.855 0.775 ;
        RECT 0.000 -0.300 10.080 0.300 ;
    END
  END VSS
  OBS
      LAYER Metal1 ;
        RECT 0.350 2.625 0.580 3.380 ;
        RECT 9.470 3.195 9.700 3.380 ;
        RECT 4.385 2.965 9.700 3.195 ;
        RECT 4.385 2.625 4.615 2.965 ;
        RECT 0.350 2.390 4.615 2.625 ;
        RECT 9.470 2.530 9.700 2.965 ;
  END
END gf180mcu_fd_sc_mcu7t5v0__nor4_2

#--------EOF---------

MACRO gf180mcu_fd_sc_mcu7t5v0__oai21_1
  CLASS core ;
  FOREIGN gf180mcu_fd_sc_mcu7t5v0__oai21_1 ;
  ORIGIN 0.000 0.000 ;
  SIZE 4.480 BY 3.920 ;
  SYMMETRY X Y ;
  SITE GF018hv5v_mcu_sc7 ;
  PIN A1
    DIRECTION INPUT ;
    ANTENNAGATEAREA 1.102000 ;
    PORT
      LAYER Metal1 ;
        RECT 1.825 0.550 2.160 2.320 ;
    END
  END A1
  PIN A2
    DIRECTION INPUT ;
    ANTENNAGATEAREA 1.102000 ;
    PORT
      LAYER Metal1 ;
        RECT 0.705 0.550 1.000 2.230 ;
    END
  END A2
  PIN B
    DIRECTION INPUT ;
    ANTENNAGATEAREA 1.057000 ;
    PORT
      LAYER Metal1 ;
        RECT 3.375 1.900 4.350 2.150 ;
        RECT 2.945 1.600 4.350 1.900 ;
        RECT 2.945 0.550 3.280 1.600 ;
    END
  END B
  PIN ZN
    DIRECTION OUTPUT ;
    ANTENNADIFFAREA 1.276000 ;
    PORT
      LAYER Metal1 ;
        RECT 1.230 2.590 2.615 2.930 ;
        RECT 1.230 0.550 1.595 2.590 ;
    END
  END ZN
  PIN VDD
    DIRECTION INOUT ;
    USE POWER ;
    SHAPE ABUTMENT ;
    PORT
      LAYER Metal1 ;
        RECT 0.000 3.620 4.480 4.220 ;
        RECT 0.295 2.920 0.525 3.620 ;
        RECT 3.605 2.920 3.835 3.620 ;
    END
  END VDD
  PIN VNW
    DIRECTION INOUT ;
    USE POWER ;
    PORT
      LAYER Nwell ;
        RECT -0.430 1.760 4.910 4.350 ;
    END
  END VNW
  PIN VPW
    DIRECTION INOUT ;
    USE GROUND ;
    PORT
      LAYER Pwell ;
        RECT -0.430 -0.430 4.910 1.760 ;
    END
  END VPW
  PIN VSS
    DIRECTION INOUT ;
    USE GROUND ;
    SHAPE ABUTMENT ;
    PORT
      LAYER Metal1 ;
        RECT 3.605 0.300 3.835 0.930 ;
        RECT 0.000 -0.300 4.480 0.300 ;
    END
  END VSS
  OBS
      LAYER Metal1 ;
        RECT 0.755 3.160 3.075 3.390 ;
        RECT 0.755 2.690 0.985 3.160 ;
        RECT 0.245 2.460 0.985 2.690 ;
        RECT 0.245 0.550 0.475 2.460 ;
        RECT 2.845 2.360 3.075 3.160 ;
        RECT 2.485 2.130 3.075 2.360 ;
        RECT 2.485 0.550 2.715 2.130 ;
  END
END gf180mcu_fd_sc_mcu7t5v0__oai21_1

#--------EOF---------

MACRO gf180mcu_fd_sc_mcu7t5v0__oai21_2
  CLASS core ;
  FOREIGN gf180mcu_fd_sc_mcu7t5v0__oai21_2 ;
  ORIGIN 0.000 0.000 ;
  SIZE 8.400 BY 3.920 ;
  SYMMETRY X Y ;
  SITE GF018hv5v_mcu_sc7 ;
  PIN A1
    DIRECTION INPUT ;
    ANTENNAGATEAREA 2.079000 ;
    PORT
      LAYER Metal1 ;
        RECT 3.970 1.790 6.080 2.120 ;
    END
  END A1
  PIN A2
    DIRECTION INPUT ;
    ANTENNAGATEAREA 2.079000 ;
    PORT
      LAYER Metal1 ;
        RECT 3.395 2.350 6.615 2.680 ;
        RECT 3.395 2.090 3.655 2.350 ;
        RECT 2.980 1.830 3.655 2.090 ;
        RECT 6.355 2.195 6.615 2.350 ;
        RECT 6.355 1.790 7.250 2.195 ;
    END
  END A2
  PIN B
    DIRECTION INPUT ;
    ANTENNAGATEAREA 1.939000 ;
    PORT
      LAYER Metal1 ;
        RECT 0.280 1.785 2.750 2.120 ;
    END
  END B
  PIN ZN
    DIRECTION OUTPUT ;
    ANTENNADIFFAREA 2.309600 ;
    PORT
      LAYER Metal1 ;
        RECT 1.365 2.680 1.595 3.335 ;
        RECT 2.865 3.050 7.075 3.280 ;
        RECT 2.865 2.680 3.095 3.050 ;
        RECT 1.365 2.450 3.095 2.680 ;
        RECT 6.845 2.675 7.075 3.050 ;
        RECT 6.845 2.445 7.730 2.675 ;
        RECT 7.500 1.560 7.730 2.445 ;
        RECT 3.770 1.220 7.730 1.560 ;
        RECT 3.770 0.990 4.110 1.220 ;
        RECT 6.010 0.990 6.350 1.220 ;
    END
  END ZN
  PIN VDD
    DIRECTION INOUT ;
    USE POWER ;
    SHAPE ABUTMENT ;
    PORT
      LAYER Metal1 ;
        RECT 0.000 3.620 8.400 4.220 ;
        RECT 0.345 2.995 0.575 3.620 ;
        RECT 2.385 2.995 2.615 3.620 ;
        RECT 7.305 2.995 7.535 3.620 ;
    END
  END VDD
  PIN VNW
    DIRECTION INOUT ;
    USE POWER ;
    PORT
      LAYER Nwell ;
        RECT -0.430 1.885 8.830 4.350 ;
        RECT -0.430 1.760 3.265 1.885 ;
        RECT 6.805 1.760 8.830 1.885 ;
    END
  END VNW
  PIN VPW
    DIRECTION INOUT ;
    USE GROUND ;
    PORT
      LAYER Pwell ;
        RECT -0.430 -0.430 8.830 1.760 ;
    END
  END VPW
  PIN VSS
    DIRECTION INOUT ;
    USE GROUND ;
    SHAPE ABUTMENT ;
    PORT
      LAYER Metal1 ;
        RECT 1.365 0.300 1.595 1.015 ;
        RECT 0.000 -0.300 8.400 0.300 ;
    END
  END VSS
  OBS
      LAYER Metal1 ;
        RECT 0.245 1.310 2.715 1.545 ;
        RECT 0.245 0.635 0.475 1.310 ;
        RECT 2.485 0.760 2.715 1.310 ;
        RECT 2.485 0.530 7.700 0.760 ;
  END
END gf180mcu_fd_sc_mcu7t5v0__oai21_2

#--------EOF---------

MACRO gf180mcu_fd_sc_mcu7t5v0__oai22_1
  CLASS core ;
  FOREIGN gf180mcu_fd_sc_mcu7t5v0__oai22_1 ;
  ORIGIN 0.000 0.000 ;
  SIZE 5.600 BY 3.920 ;
  SYMMETRY X Y ;
  SITE GF018hv5v_mcu_sc7 ;
  PIN A1
    DIRECTION INPUT ;
    ANTENNAGATEAREA 1.102000 ;
    PORT
      LAYER Metal1 ;
        RECT 2.945 0.550 3.240 2.220 ;
    END
  END A1
  PIN A2
    DIRECTION INPUT ;
    ANTENNAGATEAREA 1.102000 ;
    PORT
      LAYER Metal1 ;
        RECT 4.065 0.550 4.380 2.220 ;
    END
  END A2
  PIN B1
    DIRECTION INPUT ;
    ANTENNAGATEAREA 1.102000 ;
    PORT
      LAYER Metal1 ;
        RECT 1.800 2.190 2.160 2.845 ;
        RECT 1.800 1.685 2.715 2.190 ;
    END
  END B1
  PIN B2
    DIRECTION INPUT ;
    ANTENNAGATEAREA 1.102000 ;
    PORT
      LAYER Metal1 ;
        RECT 0.705 1.610 1.030 3.320 ;
    END
  END B2
  PIN ZN
    DIRECTION OUTPUT ;
    ANTENNADIFFAREA 1.182800 ;
    PORT
      LAYER Metal1 ;
        RECT 2.440 2.680 3.835 2.910 ;
        RECT 3.480 0.550 3.835 2.680 ;
    END
  END ZN
  PIN VDD
    DIRECTION INOUT ;
    USE POWER ;
    SHAPE ABUTMENT ;
    PORT
      LAYER Metal1 ;
        RECT 0.000 3.620 5.600 4.220 ;
        RECT 0.245 2.590 0.475 3.620 ;
        RECT 4.625 2.960 4.855 3.620 ;
    END
  END VDD
  PIN VNW
    DIRECTION INOUT ;
    USE POWER ;
    PORT
      LAYER Nwell ;
        RECT -0.430 1.760 6.030 4.350 ;
    END
  END VNW
  PIN VPW
    DIRECTION INOUT ;
    USE GROUND ;
    PORT
      LAYER Pwell ;
        RECT -0.430 -0.430 6.030 1.760 ;
    END
  END VPW
  PIN VSS
    DIRECTION INOUT ;
    USE GROUND ;
    SHAPE ABUTMENT ;
    PORT
      LAYER Metal1 ;
        RECT 1.310 0.300 1.650 0.635 ;
        RECT 0.000 -0.300 5.600 0.300 ;
    END
  END VSS
  OBS
      LAYER Metal1 ;
        RECT 1.320 3.140 4.365 3.370 ;
        RECT 1.320 1.095 1.550 3.140 ;
        RECT 4.135 2.680 4.365 3.140 ;
        RECT 4.135 2.450 4.955 2.680 ;
        RECT 0.245 0.865 2.715 1.095 ;
        RECT 0.245 0.550 0.475 0.865 ;
        RECT 2.485 0.550 2.715 0.865 ;
        RECT 4.725 0.550 4.955 2.450 ;
  END
END gf180mcu_fd_sc_mcu7t5v0__oai22_1

#--------EOF---------

MACRO gf180mcu_fd_sc_mcu7t5v0__oai22_2
  CLASS core ;
  FOREIGN gf180mcu_fd_sc_mcu7t5v0__oai22_2 ;
  ORIGIN 0.000 0.000 ;
  SIZE 10.640 BY 3.920 ;
  SYMMETRY X Y ;
  SITE GF018hv5v_mcu_sc7 ;
  PIN A1
    DIRECTION INPUT ;
    ANTENNAGATEAREA 2.079000 ;
    PORT
      LAYER Metal1 ;
        RECT 6.250 1.800 8.715 2.120 ;
    END
  END A1
  PIN A2
    DIRECTION INPUT ;
    ANTENNAGATEAREA 2.079000 ;
    PORT
      LAYER Metal1 ;
        RECT 5.690 2.360 9.295 2.680 ;
        RECT 5.690 2.120 6.020 2.360 ;
        RECT 5.270 1.800 6.020 2.120 ;
        RECT 8.955 1.585 9.295 2.360 ;
    END
  END A2
  PIN B1
    DIRECTION INPUT ;
    ANTENNAGATEAREA 2.079000 ;
    PORT
      LAYER Metal1 ;
        RECT 1.475 1.785 3.270 2.120 ;
    END
  END B1
  PIN B2
    DIRECTION INPUT ;
    ANTENNAGATEAREA 2.079000 ;
    PORT
      LAYER Metal1 ;
        RECT 0.825 2.360 3.820 2.680 ;
        RECT 0.825 1.585 1.165 2.360 ;
        RECT 3.500 2.125 3.820 2.360 ;
        RECT 3.500 1.770 4.480 2.125 ;
    END
  END B2
  PIN ZN
    DIRECTION OUTPUT ;
    ANTENNADIFFAREA 2.377400 ;
    PORT
      LAYER Metal1 ;
        RECT 2.175 2.920 4.385 3.240 ;
        RECT 4.110 2.680 4.385 2.920 ;
        RECT 5.195 2.920 7.865 3.240 ;
        RECT 5.195 2.680 5.445 2.920 ;
        RECT 4.110 2.360 5.445 2.680 ;
        RECT 4.755 1.560 5.015 2.360 ;
        RECT 4.755 1.240 8.590 1.560 ;
        RECT 6.010 0.990 6.350 1.240 ;
        RECT 8.250 0.990 8.590 1.240 ;
    END
  END ZN
  PIN VDD
    DIRECTION INOUT ;
    USE POWER ;
    SHAPE ABUTMENT ;
    PORT
      LAYER Metal1 ;
        RECT 0.000 3.620 10.640 4.220 ;
        RECT 0.345 2.590 0.575 3.620 ;
        RECT 4.725 2.975 4.955 3.620 ;
        RECT 9.545 2.590 9.775 3.620 ;
    END
  END VDD
  PIN VNW
    DIRECTION INOUT ;
    USE POWER ;
    PORT
      LAYER Nwell ;
        RECT -0.430 1.885 11.070 4.350 ;
        RECT -0.430 1.760 5.605 1.885 ;
        RECT 8.985 1.760 11.070 1.885 ;
    END
  END VNW
  PIN VPW
    DIRECTION INOUT ;
    USE GROUND ;
    PORT
      LAYER Pwell ;
        RECT -0.430 -0.430 11.070 1.760 ;
    END
  END VPW
  PIN VSS
    DIRECTION INOUT ;
    USE GROUND ;
    SHAPE ABUTMENT ;
    PORT
      LAYER Metal1 ;
        RECT 1.365 0.300 1.595 0.815 ;
        RECT 3.605 0.300 3.835 0.815 ;
        RECT 0.000 -0.300 10.640 0.300 ;
    END
  END VSS
  OBS
      LAYER Metal1 ;
        RECT 0.190 1.045 4.455 1.275 ;
        RECT 0.190 0.530 0.530 1.045 ;
        RECT 2.430 0.530 2.770 1.045 ;
        RECT 4.225 0.760 4.455 1.045 ;
        RECT 4.225 0.530 9.940 0.760 ;
  END
END gf180mcu_fd_sc_mcu7t5v0__oai22_2

#--------EOF---------

MACRO gf180mcu_fd_sc_mcu7t5v0__oai31_1
  CLASS core ;
  FOREIGN gf180mcu_fd_sc_mcu7t5v0__oai31_1 ;
  ORIGIN 0.000 0.000 ;
  SIZE 6.160 BY 3.920 ;
  SYMMETRY X Y ;
  SITE GF018hv5v_mcu_sc7 ;
  PIN A1
    DIRECTION INPUT ;
    ANTENNAGATEAREA 1.036500 ;
    PORT
      LAYER Metal1 ;
        RECT 1.230 1.750 2.130 2.150 ;
        RECT 1.790 1.160 2.130 1.750 ;
    END
  END A1
  PIN A2
    DIRECTION INPUT ;
    ANTENNAGATEAREA 1.036500 ;
    PORT
      LAYER Metal1 ;
        RECT 3.470 1.470 3.810 3.320 ;
    END
  END A2
  PIN A3
    DIRECTION INPUT ;
    ANTENNAGATEAREA 1.036500 ;
    PORT
      LAYER Metal1 ;
        RECT 4.590 1.470 4.935 3.320 ;
    END
  END A3
  PIN B
    DIRECTION INPUT ;
    ANTENNAGATEAREA 1.054000 ;
    PORT
      LAYER Metal1 ;
        RECT 0.705 1.160 1.000 3.320 ;
    END
  END B
  PIN ZN
    DIRECTION OUTPUT ;
    ANTENNADIFFAREA 1.988400 ;
    PORT
      LAYER Metal1 ;
        RECT 1.330 2.680 1.670 3.380 ;
        RECT 1.330 2.380 2.680 2.680 ;
        RECT 2.360 1.220 2.680 2.380 ;
        RECT 2.360 0.990 5.395 1.220 ;
        RECT 5.165 0.605 5.395 0.990 ;
    END
  END ZN
  PIN VDD
    DIRECTION INOUT ;
    USE POWER ;
    SHAPE ABUTMENT ;
    PORT
      LAYER Metal1 ;
        RECT 0.000 3.620 6.160 4.220 ;
        RECT 0.245 2.530 0.475 3.620 ;
        RECT 5.165 2.530 5.395 3.620 ;
    END
  END VDD
  PIN VNW
    DIRECTION INOUT ;
    USE POWER ;
    PORT
      LAYER Nwell ;
        RECT -0.430 1.885 6.590 4.350 ;
        RECT -0.430 1.760 2.195 1.885 ;
        RECT 3.440 1.760 6.590 1.885 ;
    END
  END VNW
  PIN VPW
    DIRECTION INOUT ;
    USE GROUND ;
    PORT
      LAYER Pwell ;
        RECT -0.430 -0.430 6.590 1.760 ;
    END
  END VPW
  PIN VSS
    DIRECTION INOUT ;
    USE GROUND ;
    SHAPE ABUTMENT ;
    PORT
      LAYER Metal1 ;
        RECT 0.245 0.300 0.475 0.945 ;
        RECT 0.000 -0.300 6.160 0.300 ;
    END
  END VSS
  OBS
      LAYER Metal1 ;
        RECT 1.310 0.530 4.330 0.760 ;
  END
END gf180mcu_fd_sc_mcu7t5v0__oai31_1

#--------EOF---------

MACRO gf180mcu_fd_sc_mcu7t5v0__oai31_2
  CLASS core ;
  FOREIGN gf180mcu_fd_sc_mcu7t5v0__oai31_2 ;
  ORIGIN 0.000 0.000 ;
  SIZE 10.640 BY 3.920 ;
  SYMMETRY X Y ;
  SITE GF018hv5v_mcu_sc7 ;
  PIN A1
    DIRECTION INPUT ;
    ANTENNAGATEAREA 2.079000 ;
    PORT
      LAYER Metal1 ;
        RECT 5.420 1.680 6.975 1.985 ;
        RECT 9.620 1.680 9.980 2.280 ;
        RECT 5.420 1.665 9.980 1.680 ;
        RECT 6.745 1.450 9.980 1.665 ;
        RECT 8.970 1.210 9.980 1.450 ;
    END
  END A1
  PIN A2
    DIRECTION INPUT ;
    ANTENNAGATEAREA 2.079000 ;
    PORT
      LAYER Metal1 ;
        RECT 7.255 2.465 8.350 2.690 ;
        RECT 4.460 2.235 8.350 2.465 ;
        RECT 4.460 2.150 4.990 2.235 ;
        RECT 4.030 1.770 4.990 2.150 ;
        RECT 7.670 1.910 8.350 2.235 ;
    END
  END A2
  PIN A3
    DIRECTION INPUT ;
    ANTENNAGATEAREA 2.079000 ;
    PORT
      LAYER Metal1 ;
        RECT 6.600 2.930 9.240 3.260 ;
        RECT 3.470 2.920 9.240 2.930 ;
        RECT 3.470 2.695 6.850 2.920 ;
        RECT 3.470 2.120 3.800 2.695 ;
        RECT 2.970 1.770 3.800 2.120 ;
        RECT 9.010 1.910 9.240 2.920 ;
    END
  END A3
  PIN B
    DIRECTION INPUT ;
    ANTENNAGATEAREA 2.064000 ;
    PORT
      LAYER Metal1 ;
        RECT 0.280 1.770 2.130 2.150 ;
    END
  END B
  PIN ZN
    DIRECTION OUTPUT ;
    ANTENNADIFFAREA 2.796000 ;
    PORT
      LAYER Metal1 ;
        RECT 1.365 2.760 1.595 3.375 ;
        RECT 2.970 3.160 6.350 3.390 ;
        RECT 2.970 2.760 3.200 3.160 ;
        RECT 1.365 2.530 3.200 2.760 ;
        RECT 2.360 1.220 2.680 2.530 ;
        RECT 2.360 0.990 8.600 1.220 ;
    END
  END ZN
  PIN VDD
    DIRECTION INOUT ;
    USE POWER ;
    SHAPE ABUTMENT ;
    PORT
      LAYER Metal1 ;
        RECT 0.000 3.620 10.640 4.220 ;
        RECT 0.295 2.530 0.525 3.620 ;
        RECT 2.330 3.020 2.670 3.620 ;
        RECT 9.490 2.530 9.830 3.620 ;
    END
  END VDD
  PIN VNW
    DIRECTION INOUT ;
    USE POWER ;
    PORT
      LAYER Nwell ;
        RECT -0.430 1.885 11.070 4.350 ;
        RECT -0.430 1.760 3.340 1.885 ;
        RECT 9.070 1.760 11.070 1.885 ;
    END
  END VNW
  PIN VPW
    DIRECTION INOUT ;
    USE GROUND ;
    PORT
      LAYER Pwell ;
        RECT -0.430 -0.430 11.070 1.760 ;
    END
  END VPW
  PIN VSS
    DIRECTION INOUT ;
    USE GROUND ;
    SHAPE ABUTMENT ;
    PORT
      LAYER Metal1 ;
        RECT 1.310 0.300 1.650 0.635 ;
        RECT 0.000 -0.300 10.640 0.300 ;
    END
  END VSS
  OBS
      LAYER Metal1 ;
        RECT 0.180 0.865 2.130 1.095 ;
        RECT 1.900 0.760 2.130 0.865 ;
        RECT 1.900 0.530 9.940 0.760 ;
  END
END gf180mcu_fd_sc_mcu7t5v0__oai31_2

#--------EOF---------

MACRO gf180mcu_fd_sc_mcu7t5v0__oai32_1
  CLASS core ;
  FOREIGN gf180mcu_fd_sc_mcu7t5v0__oai32_1 ;
  ORIGIN 0.000 0.000 ;
  SIZE 6.720 BY 3.920 ;
  SYMMETRY X Y ;
  SITE GF018hv5v_mcu_sc7 ;
  PIN A1
    DIRECTION INPUT ;
    ANTENNAGATEAREA 1.102000 ;
    PORT
      LAYER Metal1 ;
        RECT 2.920 2.150 3.240 2.750 ;
        RECT 2.920 1.730 3.830 2.150 ;
    END
  END A1
  PIN A2
    DIRECTION INPUT ;
    ANTENNAGATEAREA 1.102000 ;
    PORT
      LAYER Metal1 ;
        RECT 1.800 1.650 2.120 3.310 ;
    END
  END A2
  PIN A3
    DIRECTION INPUT ;
    ANTENNAGATEAREA 1.102000 ;
    PORT
      LAYER Metal1 ;
        RECT 0.705 1.650 1.000 3.310 ;
    END
  END A3
  PIN B1
    DIRECTION INPUT ;
    ANTENNAGATEAREA 1.102000 ;
    PORT
      LAYER Metal1 ;
        RECT 4.065 0.610 4.370 2.150 ;
    END
  END B1
  PIN B2
    DIRECTION INPUT ;
    ANTENNAGATEAREA 1.102000 ;
    PORT
      LAYER Metal1 ;
        RECT 5.185 0.610 5.490 2.190 ;
    END
  END B2
  PIN ZN
    DIRECTION OUTPUT ;
    ANTENNADIFFAREA 1.304800 ;
    PORT
      LAYER Metal1 ;
        RECT 3.470 2.380 4.955 2.700 ;
        RECT 4.600 0.610 4.955 2.380 ;
    END
  END ZN
  PIN VDD
    DIRECTION INOUT ;
    USE POWER ;
    SHAPE ABUTMENT ;
    PORT
      LAYER Metal1 ;
        RECT 0.000 3.620 6.720 4.220 ;
        RECT 0.245 2.590 0.475 3.620 ;
        RECT 5.745 3.200 5.975 3.620 ;
    END
  END VDD
  PIN VNW
    DIRECTION INOUT ;
    USE POWER ;
    PORT
      LAYER Nwell ;
        RECT -0.430 1.760 7.150 4.350 ;
    END
  END VNW
  PIN VPW
    DIRECTION INOUT ;
    USE GROUND ;
    PORT
      LAYER Pwell ;
        RECT -0.430 -0.430 7.150 1.760 ;
    END
  END VPW
  PIN VSS
    DIRECTION INOUT ;
    USE GROUND ;
    SHAPE ABUTMENT ;
    PORT
      LAYER Metal1 ;
        RECT 0.245 0.300 0.475 0.915 ;
        RECT 2.485 0.300 2.715 0.915 ;
        RECT 0.000 -0.300 6.720 0.300 ;
    END
  END VSS
  OBS
      LAYER Metal1 ;
        RECT 2.450 3.050 5.450 3.280 ;
        RECT 2.450 1.400 2.680 3.050 ;
        RECT 5.220 2.870 5.450 3.050 ;
        RECT 5.220 2.640 6.075 2.870 ;
        RECT 1.365 1.165 3.835 1.400 ;
        RECT 1.365 0.610 1.595 1.165 ;
        RECT 3.605 0.610 3.835 1.165 ;
        RECT 5.845 0.610 6.075 2.640 ;
  END
END gf180mcu_fd_sc_mcu7t5v0__oai32_1

#--------EOF---------

MACRO gf180mcu_fd_sc_mcu7t5v0__oai32_2
  CLASS core ;
  FOREIGN gf180mcu_fd_sc_mcu7t5v0__oai32_2 ;
  ORIGIN 0.000 0.000 ;
  SIZE 12.880 BY 3.920 ;
  SYMMETRY X Y ;
  SITE GF018hv5v_mcu_sc7 ;
  PIN A1
    DIRECTION INPUT ;
    ANTENNAGATEAREA 2.079000 ;
    PORT
      LAYER Metal1 ;
        RECT 2.850 1.800 4.390 2.120 ;
    END
  END A1
  PIN A2
    DIRECTION INPUT ;
    ANTENNAGATEAREA 2.079000 ;
    PORT
      LAYER Metal1 ;
        RECT 1.535 1.770 2.600 2.135 ;
        RECT 2.350 1.555 2.600 1.770 ;
        RECT 4.620 1.770 6.070 2.120 ;
        RECT 4.620 1.555 4.850 1.770 ;
        RECT 2.350 1.325 4.850 1.555 ;
    END
  END A2
  PIN A3
    DIRECTION INPUT ;
    ANTENNAGATEAREA 2.079000 ;
    PORT
      LAYER Metal1 ;
        RECT 0.825 2.595 6.160 2.680 ;
        RECT 0.825 2.365 6.600 2.595 ;
        RECT 0.825 1.560 1.145 2.365 ;
        RECT 6.300 1.560 6.600 2.365 ;
    END
  END A3
  PIN B1
    DIRECTION INPUT ;
    ANTENNAGATEAREA 2.079000 ;
    PORT
      LAYER Metal1 ;
        RECT 8.450 1.800 10.590 2.120 ;
    END
  END B1
  PIN B2
    DIRECTION INPUT ;
    ANTENNAGATEAREA 2.079000 ;
    PORT
      LAYER Metal1 ;
        RECT 8.120 2.595 11.535 2.680 ;
        RECT 7.560 2.365 11.535 2.595 ;
        RECT 7.560 1.785 7.880 2.365 ;
        RECT 11.215 1.560 11.535 2.365 ;
    END
  END B2
  PIN ZN
    DIRECTION OUTPUT ;
    ANTENNADIFFAREA 2.377400 ;
    PORT
      LAYER Metal1 ;
        RECT 3.365 3.055 6.660 3.240 ;
        RECT 7.500 3.055 10.170 3.240 ;
        RECT 3.365 2.920 10.170 3.055 ;
        RECT 6.410 2.825 7.750 2.920 ;
        RECT 6.840 1.220 7.160 2.825 ;
        RECT 6.840 0.990 10.840 1.220 ;
    END
  END ZN
  PIN VDD
    DIRECTION INOUT ;
    USE POWER ;
    SHAPE ABUTMENT ;
    PORT
      LAYER Metal1 ;
        RECT 0.000 3.620 12.880 4.220 ;
        RECT 0.345 2.650 0.575 3.620 ;
        RECT 6.910 3.285 7.250 3.620 ;
        RECT 11.785 2.650 12.015 3.620 ;
    END
  END VDD
  PIN VNW
    DIRECTION INOUT ;
    USE POWER ;
    PORT
      LAYER Nwell ;
        RECT -0.430 1.885 13.310 4.350 ;
        RECT -0.430 1.760 7.770 1.885 ;
        RECT 11.280 1.760 13.310 1.885 ;
    END
  END VNW
  PIN VPW
    DIRECTION INOUT ;
    USE GROUND ;
    PORT
      LAYER Pwell ;
        RECT -0.430 -0.430 13.310 1.760 ;
    END
  END VPW
  PIN VSS
    DIRECTION INOUT ;
    USE GROUND ;
    SHAPE ABUTMENT ;
    PORT
      LAYER Metal1 ;
        RECT 1.310 0.300 1.650 0.635 ;
        RECT 3.550 0.300 3.890 0.635 ;
        RECT 5.790 0.300 6.130 0.635 ;
        RECT 0.000 -0.300 12.880 0.300 ;
    END
  END VSS
  OBS
      LAYER Metal1 ;
        RECT 0.180 0.865 6.600 1.095 ;
        RECT 6.370 0.760 6.600 0.865 ;
        RECT 6.370 0.530 12.180 0.760 ;
  END
END gf180mcu_fd_sc_mcu7t5v0__oai32_2

#--------EOF---------

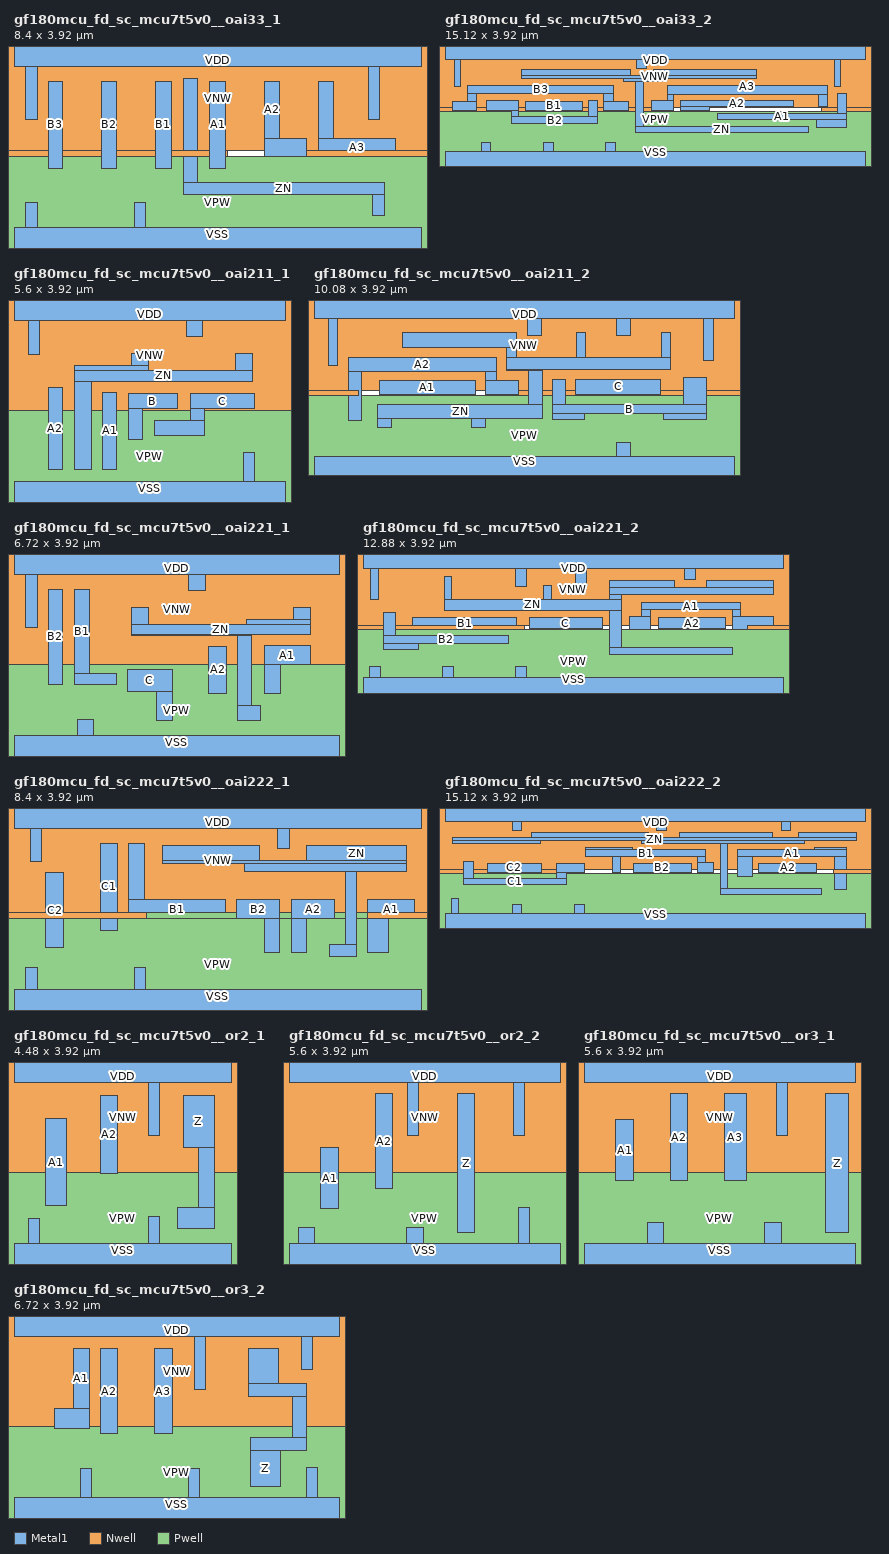
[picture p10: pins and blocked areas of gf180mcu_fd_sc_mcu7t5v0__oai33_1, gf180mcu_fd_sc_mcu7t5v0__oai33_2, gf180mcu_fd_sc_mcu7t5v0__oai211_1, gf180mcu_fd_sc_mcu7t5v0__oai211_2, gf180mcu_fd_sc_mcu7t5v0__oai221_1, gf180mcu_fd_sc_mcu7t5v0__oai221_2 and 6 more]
MACRO gf180mcu_fd_sc_mcu7t5v0__oai33_1
  CLASS core ;
  FOREIGN gf180mcu_fd_sc_mcu7t5v0__oai33_1 ;
  ORIGIN 0.000 0.000 ;
  SIZE 8.400 BY 3.920 ;
  SYMMETRY X Y ;
  SITE GF018hv5v_mcu_sc7 ;
  PIN A1
    DIRECTION INPUT ;
    ANTENNAGATEAREA 1.039500 ;
    PORT
      LAYER Metal1 ;
        RECT 4.040 1.525 4.360 3.320 ;
    END
  END A1
  PIN A2
    DIRECTION INPUT ;
    ANTENNAGATEAREA 1.039500 ;
    PORT
      LAYER Metal1 ;
        RECT 5.160 2.140 5.480 3.320 ;
        RECT 5.160 1.770 6.040 2.140 ;
    END
  END A2
  PIN A3
    DIRECTION INPUT ;
    ANTENNAGATEAREA 1.039500 ;
    PORT
      LAYER Metal1 ;
        RECT 6.280 2.140 6.600 3.320 ;
        RECT 6.280 1.770 7.870 2.140 ;
    END
  END A3
  PIN B1
    DIRECTION INPUT ;
    ANTENNAGATEAREA 1.039500 ;
    PORT
      LAYER Metal1 ;
        RECT 2.920 1.525 3.240 3.320 ;
    END
  END B1
  PIN B2
    DIRECTION INPUT ;
    ANTENNAGATEAREA 1.039500 ;
    PORT
      LAYER Metal1 ;
        RECT 1.800 1.525 2.120 3.320 ;
    END
  END B2
  PIN B3
    DIRECTION INPUT ;
    ANTENNAGATEAREA 1.039500 ;
    PORT
      LAYER Metal1 ;
        RECT 0.705 1.525 1.000 3.320 ;
    END
  END B3
  PIN ZN
    DIRECTION OUTPUT ;
    ANTENNADIFFAREA 1.871900 ;
    PORT
      LAYER Metal1 ;
        RECT 3.490 1.220 3.790 3.380 ;
        RECT 3.490 0.990 7.635 1.220 ;
        RECT 7.405 0.555 7.635 0.990 ;
    END
  END ZN
  PIN VDD
    DIRECTION INOUT ;
    USE POWER ;
    SHAPE ABUTMENT ;
    PORT
      LAYER Metal1 ;
        RECT 0.000 3.620 8.400 4.220 ;
        RECT 0.245 2.530 0.475 3.620 ;
        RECT 7.305 2.530 7.535 3.620 ;
    END
  END VDD
  PIN VNW
    DIRECTION INOUT ;
    USE POWER ;
    PORT
      LAYER Nwell ;
        RECT -0.430 1.885 8.830 4.350 ;
        RECT -0.430 1.760 4.410 1.885 ;
        RECT 5.695 1.760 8.830 1.885 ;
    END
  END VNW
  PIN VPW
    DIRECTION INOUT ;
    USE GROUND ;
    PORT
      LAYER Pwell ;
        RECT -0.430 -0.430 8.830 1.760 ;
    END
  END VPW
  PIN VSS
    DIRECTION INOUT ;
    USE GROUND ;
    SHAPE ABUTMENT ;
    PORT
      LAYER Metal1 ;
        RECT 0.245 0.300 0.475 0.815 ;
        RECT 2.485 0.300 2.715 0.815 ;
        RECT 0.000 -0.300 8.400 0.300 ;
    END
  END VSS
  OBS
      LAYER Metal1 ;
        RECT 1.365 1.045 3.175 1.275 ;
        RECT 1.365 0.530 1.595 1.045 ;
        RECT 2.945 0.760 3.175 1.045 ;
        RECT 2.945 0.530 6.570 0.760 ;
  END
END gf180mcu_fd_sc_mcu7t5v0__oai33_1

#--------EOF---------

MACRO gf180mcu_fd_sc_mcu7t5v0__oai33_2
  CLASS core ;
  FOREIGN gf180mcu_fd_sc_mcu7t5v0__oai33_2 ;
  ORIGIN 0.000 0.000 ;
  SIZE 15.120 BY 3.920 ;
  SYMMETRY X Y ;
  SITE GF018hv5v_mcu_sc7 ;
  PIN A1
    DIRECTION INPUT ;
    ANTENNAGATEAREA 2.079000 ;
    PORT
      LAYER Metal1 ;
        RECT 14.120 1.680 14.440 2.380 ;
        RECT 9.800 1.450 14.440 1.680 ;
        RECT 13.380 1.160 14.440 1.450 ;
    END
  END A1
  PIN A2
    DIRECTION INPUT ;
    ANTENNAGATEAREA 2.079000 ;
    PORT
      LAYER Metal1 ;
        RECT 8.480 1.910 12.540 2.140 ;
        RECT 8.480 1.780 9.520 1.910 ;
    END
  END A2
  PIN A3
    DIRECTION INPUT ;
    ANTENNAGATEAREA 2.079000 ;
    PORT
      LAYER Metal1 ;
        RECT 8.000 2.370 13.775 2.680 ;
        RECT 8.000 2.140 8.230 2.370 ;
        RECT 7.440 1.780 8.230 2.140 ;
        RECT 13.435 1.910 13.775 2.370 ;
    END
  END A3
  PIN B1
    DIRECTION INPUT ;
    ANTENNAGATEAREA 2.079000 ;
    PORT
      LAYER Metal1 ;
        RECT 2.890 1.800 4.950 2.120 ;
    END
  END B1
  PIN B2
    DIRECTION INPUT ;
    ANTENNAGATEAREA 2.079000 ;
    PORT
      LAYER Metal1 ;
        RECT 1.510 1.770 2.660 2.150 ;
        RECT 2.410 1.555 2.660 1.770 ;
        RECT 5.180 1.555 5.480 2.150 ;
        RECT 2.410 1.325 5.480 1.555 ;
    END
  END B2
  PIN B3
    DIRECTION INPUT ;
    ANTENNAGATEAREA 2.079000 ;
    PORT
      LAYER Metal1 ;
        RECT 0.825 2.380 6.060 2.680 ;
        RECT 0.825 2.120 1.145 2.380 ;
        RECT 0.280 1.800 1.145 2.120 ;
        RECT 5.720 2.120 6.060 2.380 ;
        RECT 5.720 1.800 6.600 2.120 ;
    END
  END B3
  PIN ZN
    DIRECTION OUTPUT ;
    ANTENNADIFFAREA 2.803800 ;
    PORT
      LAYER Metal1 ;
        RECT 2.750 3.055 6.660 3.240 ;
        RECT 7.500 3.055 11.215 3.240 ;
        RECT 2.750 2.920 11.215 3.055 ;
        RECT 6.410 2.825 7.750 2.920 ;
        RECT 6.850 1.220 7.150 2.825 ;
        RECT 6.850 0.990 13.070 1.220 ;
    END
  END ZN
  PIN VDD
    DIRECTION INOUT ;
    USE POWER ;
    SHAPE ABUTMENT ;
    PORT
      LAYER Metal1 ;
        RECT 0.000 3.620 15.120 4.220 ;
        RECT 0.345 2.630 0.575 3.620 ;
        RECT 6.910 3.285 7.250 3.620 ;
        RECT 14.025 2.630 14.255 3.620 ;
    END
  END VDD
  PIN VNW
    DIRECTION INOUT ;
    USE POWER ;
    PORT
      LAYER Nwell ;
        RECT -0.430 1.885 15.550 4.350 ;
        RECT -0.430 1.760 7.800 1.885 ;
        RECT 13.565 1.760 15.550 1.885 ;
    END
  END VNW
  PIN VPW
    DIRECTION INOUT ;
    USE GROUND ;
    PORT
      LAYER Pwell ;
        RECT -0.430 -0.430 15.550 1.760 ;
    END
  END VPW
  PIN VSS
    DIRECTION INOUT ;
    USE GROUND ;
    SHAPE ABUTMENT ;
    PORT
      LAYER Metal1 ;
        RECT 1.310 0.300 1.650 0.635 ;
        RECT 3.550 0.300 3.890 0.635 ;
        RECT 5.790 0.300 6.130 0.635 ;
        RECT 0.000 -0.300 15.120 0.300 ;
    END
  END VSS
  OBS
      LAYER Metal1 ;
        RECT 0.180 0.865 6.610 1.095 ;
        RECT 6.380 0.760 6.610 0.865 ;
        RECT 6.380 0.530 14.420 0.760 ;
  END
END gf180mcu_fd_sc_mcu7t5v0__oai33_2

#--------EOF---------

MACRO gf180mcu_fd_sc_mcu7t5v0__oai211_1
  CLASS core ;
  FOREIGN gf180mcu_fd_sc_mcu7t5v0__oai211_1 ;
  ORIGIN 0.000 0.000 ;
  SIZE 5.600 BY 3.920 ;
  SYMMETRY X Y ;
  SITE GF018hv5v_mcu_sc7 ;
  PIN A1
    DIRECTION INPUT ;
    ANTENNAGATEAREA 1.102000 ;
    PORT
      LAYER Metal1 ;
        RECT 1.825 0.550 2.120 2.135 ;
    END
  END A1
  PIN A2
    DIRECTION INPUT ;
    ANTENNAGATEAREA 1.102000 ;
    PORT
      LAYER Metal1 ;
        RECT 0.705 0.550 1.000 2.230 ;
    END
  END A2
  PIN B
    DIRECTION INPUT ;
    ANTENNAGATEAREA 0.984500 ;
    PORT
      LAYER Metal1 ;
        RECT 2.360 1.800 3.370 2.120 ;
        RECT 2.360 1.160 2.660 1.800 ;
    END
  END B
  PIN C
    DIRECTION INPUT ;
    ANTENNAGATEAREA 0.984500 ;
    PORT
      LAYER Metal1 ;
        RECT 3.650 1.800 4.970 2.120 ;
        RECT 3.650 1.560 3.940 1.800 ;
        RECT 2.890 1.240 3.940 1.560 ;
    END
  END C
  PIN ZN
    DIRECTION OUTPUT ;
    ANTENNADIFFAREA 1.672850 ;
    PORT
      LAYER Metal1 ;
        RECT 2.430 2.700 2.770 2.930 ;
        RECT 1.240 2.595 2.770 2.700 ;
        RECT 4.580 2.595 4.920 2.930 ;
        RECT 1.240 2.365 4.920 2.595 ;
        RECT 1.240 0.550 1.595 2.365 ;
    END
  END ZN
  PIN VDD
    DIRECTION INOUT ;
    USE POWER ;
    SHAPE ABUTMENT ;
    PORT
      LAYER Metal1 ;
        RECT 0.000 3.620 5.600 4.220 ;
        RECT 0.295 2.920 0.525 3.620 ;
        RECT 3.550 3.285 3.890 3.620 ;
    END
  END VDD
  PIN VNW
    DIRECTION INOUT ;
    USE POWER ;
    PORT
      LAYER Nwell ;
        RECT -0.430 1.760 6.030 4.350 ;
    END
  END VNW
  PIN VPW
    DIRECTION INOUT ;
    USE GROUND ;
    PORT
      LAYER Pwell ;
        RECT -0.430 -0.430 6.030 1.760 ;
    END
  END VPW
  PIN VSS
    DIRECTION INOUT ;
    USE GROUND ;
    SHAPE ABUTMENT ;
    PORT
      LAYER Metal1 ;
        RECT 4.725 0.300 4.955 0.890 ;
        RECT 0.000 -0.300 5.600 0.300 ;
    END
  END VSS
  OBS
      LAYER Metal1 ;
        RECT 0.755 3.160 3.290 3.390 ;
        RECT 0.755 2.690 0.985 3.160 ;
        RECT 3.060 3.055 3.290 3.160 ;
        RECT 4.120 3.160 5.450 3.390 ;
        RECT 4.120 3.055 4.350 3.160 ;
        RECT 3.060 2.825 4.350 3.055 ;
        RECT 0.245 2.460 0.985 2.690 ;
        RECT 0.245 0.550 0.475 2.460 ;
        RECT 5.220 1.370 5.450 3.160 ;
        RECT 4.240 1.140 5.450 1.370 ;
        RECT 4.240 0.835 4.470 1.140 ;
        RECT 2.430 0.605 4.470 0.835 ;
        RECT 4.240 0.600 4.470 0.605 ;
  END
END gf180mcu_fd_sc_mcu7t5v0__oai211_1

#--------EOF---------

MACRO gf180mcu_fd_sc_mcu7t5v0__oai211_2
  CLASS core ;
  FOREIGN gf180mcu_fd_sc_mcu7t5v0__oai211_2 ;
  ORIGIN 0.000 0.000 ;
  SIZE 10.080 BY 3.920 ;
  SYMMETRY X Y ;
  SITE GF018hv5v_mcu_sc7 ;
  PIN A1
    DIRECTION INPUT ;
    ANTENNAGATEAREA 2.079000 ;
    PORT
      LAYER Metal1 ;
        RECT 1.560 1.790 3.870 2.120 ;
    END
  END A1
  PIN A2
    DIRECTION INPUT ;
    ANTENNAGATEAREA 2.079000 ;
    PORT
      LAYER Metal1 ;
        RECT 0.825 2.350 4.380 2.680 ;
        RECT 0.825 1.160 1.145 2.350 ;
        RECT 4.120 2.120 4.380 2.350 ;
        RECT 4.120 1.790 4.900 2.120 ;
    END
  END A2
  PIN B
    DIRECTION INPUT ;
    ANTENNAGATEAREA 1.969000 ;
    PORT
      LAYER Metal1 ;
        RECT 5.720 1.555 6.040 2.150 ;
        RECT 8.865 1.555 9.420 2.190 ;
        RECT 5.720 1.325 9.420 1.555 ;
        RECT 5.720 1.190 6.485 1.325 ;
        RECT 8.380 1.190 9.420 1.325 ;
    END
  END B
  PIN C
    DIRECTION INPUT ;
    ANTENNAGATEAREA 1.969000 ;
    PORT
      LAYER Metal1 ;
        RECT 6.280 1.800 8.320 2.140 ;
    END
  END C
  PIN ZN
    DIRECTION OUTPUT ;
    ANTENNADIFFAREA 2.837400 ;
    PORT
      LAYER Metal1 ;
        RECT 2.130 2.920 4.860 3.280 ;
        RECT 4.630 2.680 4.860 2.920 ;
        RECT 6.290 2.680 6.520 3.275 ;
        RECT 8.330 2.680 8.560 3.275 ;
        RECT 4.630 2.380 8.560 2.680 ;
        RECT 4.630 2.370 5.480 2.380 ;
        RECT 5.150 1.560 5.480 2.370 ;
        RECT 1.530 1.220 5.480 1.560 ;
        RECT 1.530 0.990 1.870 1.220 ;
        RECT 3.770 0.990 4.110 1.220 ;
    END
  END ZN
  PIN VDD
    DIRECTION INOUT ;
    USE POWER ;
    SHAPE ABUTMENT ;
    PORT
      LAYER Metal1 ;
        RECT 0.000 3.620 10.080 4.220 ;
        RECT 0.345 2.485 0.575 3.620 ;
        RECT 5.115 3.205 5.455 3.620 ;
        RECT 7.255 3.205 7.595 3.620 ;
        RECT 9.350 2.595 9.580 3.620 ;
    END
  END VDD
  PIN VNW
    DIRECTION INOUT ;
    USE POWER ;
    PORT
      LAYER Nwell ;
        RECT -0.430 1.885 10.510 4.350 ;
        RECT -0.430 1.760 1.075 1.885 ;
        RECT 4.615 1.760 10.510 1.885 ;
    END
  END VNW
  PIN VPW
    DIRECTION INOUT ;
    USE GROUND ;
    PORT
      LAYER Pwell ;
        RECT -0.430 -0.430 10.510 1.760 ;
    END
  END VPW
  PIN VSS
    DIRECTION INOUT ;
    USE GROUND ;
    SHAPE ABUTMENT ;
    PORT
      LAYER Metal1 ;
        RECT 7.255 0.300 7.595 0.635 ;
        RECT 0.000 -0.300 10.080 0.300 ;
    END
  END VSS
  OBS
      LAYER Metal1 ;
        RECT 6.735 0.865 8.080 1.095 ;
        RECT 6.735 0.760 6.965 0.865 ;
        RECT 0.180 0.530 6.965 0.760 ;
        RECT 7.850 0.760 8.080 0.865 ;
        RECT 7.850 0.530 9.645 0.760 ;
  END
END gf180mcu_fd_sc_mcu7t5v0__oai211_2

#--------EOF---------

MACRO gf180mcu_fd_sc_mcu7t5v0__oai221_1
  CLASS core ;
  FOREIGN gf180mcu_fd_sc_mcu7t5v0__oai221_1 ;
  ORIGIN 0.000 0.000 ;
  SIZE 6.720 BY 3.920 ;
  SYMMETRY X Y ;
  SITE GF018hv5v_mcu_sc7 ;
  PIN A1
    DIRECTION INPUT ;
    ANTENNAGATEAREA 1.102000 ;
    PORT
      LAYER Metal1 ;
        RECT 5.160 1.770 6.110 2.150 ;
        RECT 5.160 1.170 5.500 1.770 ;
    END
  END A1
  PIN A2
    DIRECTION INPUT ;
    ANTENNAGATEAREA 1.102000 ;
    PORT
      LAYER Metal1 ;
        RECT 4.010 1.170 4.390 2.135 ;
    END
  END A2
  PIN B1
    DIRECTION INPUT ;
    ANTENNAGATEAREA 1.102000 ;
    PORT
      LAYER Metal1 ;
        RECT 1.240 1.575 1.560 3.320 ;
        RECT 1.240 1.345 2.110 1.575 ;
    END
  END B1
  PIN B2
    DIRECTION INPUT ;
    ANTENNAGATEAREA 1.102000 ;
    PORT
      LAYER Metal1 ;
        RECT 0.705 1.345 1.000 3.320 ;
    END
  END B2
  PIN C
    DIRECTION INPUT ;
    ANTENNAGATEAREA 0.964500 ;
    PORT
      LAYER Metal1 ;
        RECT 2.340 1.210 3.260 1.665 ;
        RECT 2.945 0.610 3.260 1.210 ;
    END
  END C
  PIN ZN
    DIRECTION OUTPUT ;
    ANTENNADIFFAREA 1.753600 ;
    PORT
      LAYER Metal1 ;
        RECT 2.430 2.595 2.770 2.930 ;
        RECT 5.770 2.700 6.110 2.930 ;
        RECT 4.795 2.595 6.110 2.700 ;
        RECT 2.430 2.380 6.110 2.595 ;
        RECT 2.430 2.365 4.910 2.380 ;
        RECT 4.620 0.910 4.910 2.365 ;
        RECT 4.620 0.610 5.095 0.910 ;
    END
  END ZN
  PIN VDD
    DIRECTION INOUT ;
    USE POWER ;
    SHAPE ABUTMENT ;
    PORT
      LAYER Metal1 ;
        RECT 0.000 3.620 6.720 4.220 ;
        RECT 0.245 2.530 0.475 3.620 ;
        RECT 3.610 3.285 3.950 3.620 ;
    END
  END VDD
  PIN VNW
    DIRECTION INOUT ;
    USE POWER ;
    PORT
      LAYER Nwell ;
        RECT -0.430 1.760 7.150 4.350 ;
    END
  END VNW
  PIN VPW
    DIRECTION INOUT ;
    USE GROUND ;
    PORT
      LAYER Pwell ;
        RECT -0.430 -0.430 7.150 1.760 ;
    END
  END VPW
  PIN VSS
    DIRECTION INOUT ;
    USE GROUND ;
    SHAPE ABUTMENT ;
    PORT
      LAYER Metal1 ;
        RECT 1.310 0.300 1.650 0.635 ;
        RECT 0.000 -0.300 6.720 0.300 ;
    END
  END VSS
  OBS
      LAYER Metal1 ;
        RECT 1.950 3.160 3.360 3.390 ;
        RECT 1.950 2.135 2.180 3.160 ;
        RECT 3.130 3.055 3.360 3.160 ;
        RECT 4.290 3.160 6.570 3.390 ;
        RECT 4.290 3.055 4.520 3.160 ;
        RECT 3.130 2.825 4.520 3.055 ;
        RECT 1.950 1.905 3.770 2.135 ;
        RECT 0.245 0.965 2.110 1.095 ;
        RECT 0.245 0.865 2.715 0.965 ;
        RECT 0.245 0.625 0.475 0.865 ;
        RECT 1.880 0.625 2.715 0.865 ;
        RECT 3.540 0.910 3.770 1.905 ;
        RECT 6.340 0.910 6.570 3.160 ;
        RECT 3.540 0.680 3.950 0.910 ;
        RECT 5.870 0.680 6.570 0.910 ;
  END
END gf180mcu_fd_sc_mcu7t5v0__oai221_1

#--------EOF---------

MACRO gf180mcu_fd_sc_mcu7t5v0__oai221_2
  CLASS core ;
  FOREIGN gf180mcu_fd_sc_mcu7t5v0__oai221_2 ;
  ORIGIN 0.000 0.000 ;
  SIZE 12.880 BY 3.920 ;
  SYMMETRY X Y ;
  SITE GF018hv5v_mcu_sc7 ;
  PIN A1
    DIRECTION INPUT ;
    ANTENNAGATEAREA 2.079000 ;
    PORT
      LAYER Metal1 ;
        RECT 8.550 2.365 11.570 2.595 ;
        RECT 8.550 2.150 8.820 2.365 ;
        RECT 8.160 1.770 8.820 2.150 ;
        RECT 11.340 2.150 11.570 2.365 ;
        RECT 11.340 1.770 12.590 2.150 ;
    END
  END A1
  PIN A2
    DIRECTION INPUT ;
    ANTENNAGATEAREA 2.079000 ;
    PORT
      LAYER Metal1 ;
        RECT 9.050 1.800 11.110 2.120 ;
    END
  END A2
  PIN B1
    DIRECTION INPUT ;
    ANTENNAGATEAREA 2.079000 ;
    PORT
      LAYER Metal1 ;
        RECT 1.530 1.800 4.710 2.120 ;
    END
  END B1
  PIN B2
    DIRECTION INPUT ;
    ANTENNAGATEAREA 2.079000 ;
    PORT
      LAYER Metal1 ;
        RECT 0.625 1.570 1.000 2.275 ;
        RECT 0.625 1.340 4.455 1.570 ;
        RECT 0.625 1.160 1.690 1.340 ;
    END
  END B2
  PIN C
    DIRECTION INPUT ;
    ANTENNAGATEAREA 1.969000 ;
    PORT
      LAYER Metal1 ;
        RECT 5.105 1.800 7.330 2.120 ;
    END
  END C
  PIN ZN
    DIRECTION OUTPUT ;
    ANTENNADIFFAREA 3.382000 ;
    PORT
      LAYER Metal1 ;
        RECT 2.485 2.680 2.715 3.375 ;
        RECT 5.545 2.680 5.775 3.110 ;
        RECT 7.560 3.055 9.540 3.260 ;
        RECT 10.525 3.055 12.580 3.260 ;
        RECT 7.560 2.825 12.580 3.055 ;
        RECT 7.560 2.680 7.915 2.825 ;
        RECT 2.485 2.360 7.915 2.680 ;
        RECT 7.560 1.220 7.915 2.360 ;
        RECT 7.560 0.990 11.330 1.220 ;
    END
  END ZN
  PIN VDD
    DIRECTION INOUT ;
    USE POWER ;
    SHAPE ABUTMENT ;
    PORT
      LAYER Metal1 ;
        RECT 0.000 3.620 12.880 4.220 ;
        RECT 0.245 2.690 0.475 3.620 ;
        RECT 4.670 3.090 5.010 3.620 ;
        RECT 6.510 3.090 6.850 3.620 ;
        RECT 9.870 3.285 10.210 3.620 ;
    END
  END VDD
  PIN VNW
    DIRECTION INOUT ;
    USE POWER ;
    PORT
      LAYER Nwell ;
        RECT -0.430 1.885 13.310 4.350 ;
        RECT -0.430 1.760 4.965 1.885 ;
        RECT 11.780 1.760 13.310 1.885 ;
    END
  END VNW
  PIN VPW
    DIRECTION INOUT ;
    USE GROUND ;
    PORT
      LAYER Pwell ;
        RECT -0.430 -0.430 13.310 1.760 ;
    END
  END VPW
  PIN VSS
    DIRECTION INOUT ;
    USE GROUND ;
    SHAPE ABUTMENT ;
    PORT
      LAYER Metal1 ;
        RECT 0.185 0.300 0.530 0.635 ;
        RECT 2.425 0.300 2.770 0.635 ;
        RECT 4.665 0.300 5.010 0.635 ;
        RECT 0.000 -0.300 12.880 0.300 ;
    END
  END VSS
  OBS
      LAYER Metal1 ;
        RECT 4.860 1.095 6.865 1.220 ;
        RECT 1.940 0.990 6.865 1.095 ;
        RECT 1.940 0.865 5.110 0.990 ;
        RECT 1.940 0.780 2.170 0.865 ;
        RECT 1.260 0.550 2.170 0.780 ;
        RECT 5.380 0.530 12.680 0.760 ;
  END
END gf180mcu_fd_sc_mcu7t5v0__oai221_2

#--------EOF---------

MACRO gf180mcu_fd_sc_mcu7t5v0__oai222_1
  CLASS core ;
  FOREIGN gf180mcu_fd_sc_mcu7t5v0__oai222_1 ;
  ORIGIN 0.000 0.000 ;
  SIZE 8.400 BY 3.920 ;
  SYMMETRY X Y ;
  SITE GF018hv5v_mcu_sc7 ;
  PIN A1
    DIRECTION INPUT ;
    ANTENNAGATEAREA 1.039500 ;
    PORT
      LAYER Metal1 ;
        RECT 7.300 1.770 8.270 2.150 ;
        RECT 7.300 1.060 7.720 1.770 ;
    END
  END A1
  PIN A2
    DIRECTION INPUT ;
    ANTENNAGATEAREA 1.039500 ;
    PORT
      LAYER Metal1 ;
        RECT 5.720 1.770 6.610 2.150 ;
        RECT 5.720 1.060 6.040 1.770 ;
    END
  END A2
  PIN B1
    DIRECTION INPUT ;
    ANTENNAGATEAREA 1.039500 ;
    PORT
      LAYER Metal1 ;
        RECT 2.370 2.150 2.690 3.320 ;
        RECT 2.370 1.770 4.360 2.150 ;
    END
  END B1
  PIN B2
    DIRECTION INPUT ;
    ANTENNAGATEAREA 1.039500 ;
    PORT
      LAYER Metal1 ;
        RECT 4.590 1.770 5.480 2.150 ;
        RECT 5.160 1.060 5.480 1.770 ;
    END
  END B2
  PIN C1
    DIRECTION INPUT ;
    ANTENNAGATEAREA 1.039500 ;
    PORT
      LAYER Metal1 ;
        RECT 1.780 1.520 2.140 3.320 ;
    END
  END C1
  PIN C2
    DIRECTION INPUT ;
    ANTENNAGATEAREA 1.039500 ;
    PORT
      LAYER Metal1 ;
        RECT 0.660 1.160 1.020 2.710 ;
    END
  END C2
  PIN ZN
    DIRECTION OUTPUT ;
    ANTENNADIFFAREA 2.568400 ;
    PORT
      LAYER Metal1 ;
        RECT 3.055 2.970 5.065 3.260 ;
        RECT 6.035 2.970 8.100 3.260 ;
        RECT 3.055 2.900 8.100 2.970 ;
        RECT 4.755 2.740 8.100 2.900 ;
        RECT 6.840 1.220 7.070 2.740 ;
        RECT 6.510 0.990 7.070 1.220 ;
    END
  END ZN
  PIN VDD
    DIRECTION INOUT ;
    USE POWER ;
    SHAPE ABUTMENT ;
    PORT
      LAYER Metal1 ;
        RECT 0.000 3.620 8.400 4.220 ;
        RECT 0.345 2.950 0.575 3.620 ;
        RECT 5.445 3.200 5.675 3.620 ;
    END
  END VDD
  PIN VNW
    DIRECTION INOUT ;
    USE POWER ;
    PORT
      LAYER Nwell ;
        RECT -0.430 1.885 8.830 4.350 ;
        RECT -0.430 1.760 2.725 1.885 ;
        RECT 7.300 1.760 8.830 1.885 ;
    END
  END VNW
  PIN VPW
    DIRECTION INOUT ;
    USE GROUND ;
    PORT
      LAYER Pwell ;
        RECT 2.725 1.760 7.300 1.885 ;
        RECT -0.430 -0.430 8.830 1.760 ;
    END
  END VPW
  PIN VSS
    DIRECTION INOUT ;
    USE GROUND ;
    SHAPE ABUTMENT ;
    PORT
      LAYER Metal1 ;
        RECT 0.245 0.300 0.475 0.760 ;
        RECT 2.485 0.300 2.715 0.760 ;
        RECT 0.000 -0.300 8.400 0.300 ;
    END
  END VSS
  OBS
      LAYER Metal1 ;
        RECT 1.365 0.990 4.610 1.220 ;
        RECT 1.365 0.530 1.595 0.990 ;
        RECT 3.150 0.530 8.200 0.760 ;
  END
END gf180mcu_fd_sc_mcu7t5v0__oai222_1

#--------EOF---------

MACRO gf180mcu_fd_sc_mcu7t5v0__oai222_2
  CLASS core ;
  FOREIGN gf180mcu_fd_sc_mcu7t5v0__oai222_2 ;
  ORIGIN 0.000 0.000 ;
  SIZE 15.120 BY 3.920 ;
  SYMMETRY X Y ;
  SITE GF018hv5v_mcu_sc7 ;
  PIN A1
    DIRECTION INPUT ;
    ANTENNAGATEAREA 2.079000 ;
    PORT
      LAYER Metal1 ;
        RECT 13.285 2.595 14.460 2.690 ;
        RECT 10.525 2.365 14.460 2.595 ;
        RECT 10.525 1.645 11.060 2.365 ;
        RECT 14.005 1.160 14.460 2.365 ;
    END
  END A1
  PIN A2
    DIRECTION INPUT ;
    ANTENNAGATEAREA 2.079000 ;
    PORT
      LAYER Metal1 ;
        RECT 11.290 1.800 13.390 2.120 ;
    END
  END A2
  PIN B1
    DIRECTION INPUT ;
    ANTENNAGATEAREA 2.079000 ;
    PORT
      LAYER Metal1 ;
        RECT 5.070 2.595 6.740 2.690 ;
        RECT 5.070 2.365 9.380 2.595 ;
        RECT 6.040 1.790 6.300 2.365 ;
        RECT 9.100 2.150 9.380 2.365 ;
        RECT 9.100 1.770 9.680 2.150 ;
    END
  END B1
  PIN B2
    DIRECTION INPUT ;
    ANTENNAGATEAREA 2.079000 ;
    PORT
      LAYER Metal1 ;
        RECT 6.770 1.800 8.870 2.120 ;
    END
  END B2
  PIN C1
    DIRECTION INPUT ;
    ANTENNAGATEAREA 2.079000 ;
    PORT
      LAYER Metal1 ;
        RECT 0.660 1.570 1.020 2.190 ;
        RECT 4.010 1.800 5.015 2.120 ;
        RECT 4.010 1.570 4.380 1.800 ;
        RECT 0.660 1.335 4.380 1.570 ;
    END
  END C1
  PIN C2
    DIRECTION INPUT ;
    ANTENNAGATEAREA 2.079000 ;
    PORT
      LAYER Metal1 ;
        RECT 1.530 1.800 3.460 2.120 ;
    END
  END C2
  PIN ZN
    DIRECTION OUTPUT ;
    ANTENNADIFFAREA 4.265000 ;
    PORT
      LAYER Metal1 ;
        RECT 3.125 3.055 7.340 3.240 ;
        RECT 8.445 3.055 11.775 3.240 ;
        RECT 12.720 3.055 14.820 3.240 ;
        RECT 0.280 2.920 14.820 3.055 ;
        RECT 0.280 2.825 3.420 2.920 ;
        RECT 7.090 2.825 12.950 2.920 ;
        RECT 9.930 1.220 10.160 2.825 ;
        RECT 9.930 0.990 13.570 1.220 ;
    END
  END ZN
  PIN VDD
    DIRECTION INOUT ;
    USE POWER ;
    SHAPE ABUTMENT ;
    PORT
      LAYER Metal1 ;
        RECT 0.000 3.620 15.120 4.220 ;
        RECT 2.430 3.285 2.770 3.620 ;
        RECT 7.630 3.285 7.970 3.620 ;
        RECT 12.110 3.285 12.450 3.620 ;
    END
  END VDD
  PIN VNW
    DIRECTION INOUT ;
    USE POWER ;
    PORT
      LAYER Nwell ;
        RECT -0.430 1.885 15.550 4.350 ;
        RECT -0.430 1.760 4.940 1.885 ;
        RECT 13.995 1.760 15.550 1.885 ;
    END
  END VNW
  PIN VPW
    DIRECTION INOUT ;
    USE GROUND ;
    PORT
      LAYER Pwell ;
        RECT -0.430 -0.430 15.550 1.760 ;
    END
  END VPW
  PIN VSS
    DIRECTION INOUT ;
    USE GROUND ;
    SHAPE ABUTMENT ;
    PORT
      LAYER Metal1 ;
        RECT 0.245 0.300 0.475 0.845 ;
        RECT 2.430 0.300 2.770 0.635 ;
        RECT 4.670 0.300 5.010 0.635 ;
        RECT 0.000 -0.300 15.120 0.300 ;
    END
  END VSS
  OBS
      LAYER Metal1 ;
        RECT 4.880 1.095 9.090 1.220 ;
        RECT 1.310 0.990 9.090 1.095 ;
        RECT 1.310 0.865 5.130 0.990 ;
        RECT 5.390 0.530 14.920 0.760 ;
  END
END gf180mcu_fd_sc_mcu7t5v0__oai222_2

#--------EOF---------

MACRO gf180mcu_fd_sc_mcu7t5v0__or2_1
  CLASS core ;
  FOREIGN gf180mcu_fd_sc_mcu7t5v0__or2_1 ;
  ORIGIN 0.000 0.000 ;
  SIZE 4.480 BY 3.920 ;
  SYMMETRY X Y ;
  SITE GF018hv5v_mcu_sc7 ;
  PIN A1
    DIRECTION INPUT ;
    ANTENNAGATEAREA 0.498500 ;
    PORT
      LAYER Metal1 ;
        RECT 0.660 1.075 1.080 2.880 ;
    END
  END A1
  PIN A2
    DIRECTION INPUT ;
    ANTENNAGATEAREA 0.498500 ;
    PORT
      LAYER Metal1 ;
        RECT 1.780 1.740 2.140 3.345 ;
    END
  END A2
  PIN Z
    DIRECTION OUTPUT ;
    ANTENNADIFFAREA 0.897600 ;
    PORT
      LAYER Metal1 ;
        RECT 3.500 2.290 4.130 3.345 ;
        RECT 3.800 1.040 4.130 2.290 ;
        RECT 3.365 0.610 4.130 1.040 ;
    END
  END Z
  PIN VDD
    DIRECTION INOUT ;
    USE POWER ;
    SHAPE ABUTMENT ;
    PORT
      LAYER Metal1 ;
        RECT 0.000 3.620 4.480 4.220 ;
        RECT 2.780 2.530 3.010 3.620 ;
    END
  END VDD
  PIN VNW
    DIRECTION INOUT ;
    USE POWER ;
    PORT
      LAYER Nwell ;
        RECT -0.430 1.760 4.910 4.350 ;
    END
  END VNW
  PIN VPW
    DIRECTION INOUT ;
    USE GROUND ;
    PORT
      LAYER Pwell ;
        RECT -0.430 -0.430 4.910 1.760 ;
    END
  END VPW
  PIN VSS
    DIRECTION INOUT ;
    USE GROUND ;
    SHAPE ABUTMENT ;
    PORT
      LAYER Metal1 ;
        RECT 0.300 0.300 0.530 0.825 ;
        RECT 2.780 0.300 3.010 0.850 ;
        RECT 0.000 -0.300 4.480 0.300 ;
    END
  END VSS
  OBS
      LAYER Metal1 ;
        RECT 0.335 3.130 1.540 3.360 ;
        RECT 1.310 1.510 1.540 3.130 ;
        RECT 2.680 1.510 3.535 1.640 ;
        RECT 1.310 1.280 3.535 1.510 ;
        RECT 1.310 0.530 1.705 1.280 ;
  END
END gf180mcu_fd_sc_mcu7t5v0__or2_1

#--------EOF---------

MACRO gf180mcu_fd_sc_mcu7t5v0__or2_2
  CLASS core ;
  FOREIGN gf180mcu_fd_sc_mcu7t5v0__or2_2 ;
  ORIGIN 0.000 0.000 ;
  SIZE 5.600 BY 3.920 ;
  SYMMETRY X Y ;
  SITE GF018hv5v_mcu_sc7 ;
  PIN A1
    DIRECTION INPUT ;
    ANTENNAGATEAREA 1.102000 ;
    PORT
      LAYER Metal1 ;
        RECT 0.660 1.015 1.020 2.280 ;
    END
  END A1
  PIN A2
    DIRECTION INPUT ;
    ANTENNAGATEAREA 1.102000 ;
    PORT
      LAYER Metal1 ;
        RECT 1.780 1.430 2.140 3.390 ;
    END
  END A2
  PIN Z
    DIRECTION OUTPUT ;
    ANTENNADIFFAREA 1.121800 ;
    PORT
      LAYER Metal1 ;
        RECT 3.480 0.530 3.835 3.390 ;
    END
  END Z
  PIN VDD
    DIRECTION INOUT ;
    USE POWER ;
    SHAPE ABUTMENT ;
    PORT
      LAYER Metal1 ;
        RECT 0.000 3.620 5.600 4.220 ;
        RECT 2.435 2.530 2.665 3.620 ;
        RECT 4.625 2.530 4.855 3.620 ;
    END
  END VDD
  PIN VNW
    DIRECTION INOUT ;
    USE POWER ;
    PORT
      LAYER Nwell ;
        RECT -0.430 1.760 6.030 4.350 ;
    END
  END VNW
  PIN VPW
    DIRECTION INOUT ;
    USE GROUND ;
    PORT
      LAYER Pwell ;
        RECT -0.430 -0.430 6.030 1.760 ;
    END
  END VPW
  PIN VSS
    DIRECTION INOUT ;
    USE GROUND ;
    SHAPE ABUTMENT ;
    PORT
      LAYER Metal1 ;
        RECT 0.190 0.300 0.530 0.635 ;
        RECT 2.430 0.300 2.770 0.635 ;
        RECT 4.725 0.300 4.955 1.045 ;
        RECT 0.000 -0.300 5.600 0.300 ;
    END
  END VSS
  OBS
      LAYER Metal1 ;
        RECT 0.345 2.765 0.575 3.390 ;
        RECT 0.345 2.530 1.530 2.765 ;
        RECT 1.300 1.115 1.530 2.530 ;
        RECT 2.975 1.115 3.205 2.115 ;
        RECT 1.300 0.885 3.205 1.115 ;
        RECT 1.300 0.530 1.595 0.885 ;
  END
END gf180mcu_fd_sc_mcu7t5v0__or2_2

#--------EOF---------

MACRO gf180mcu_fd_sc_mcu7t5v0__or3_1
  CLASS core ;
  FOREIGN gf180mcu_fd_sc_mcu7t5v0__or3_1 ;
  ORIGIN 0.000 0.000 ;
  SIZE 5.600 BY 3.920 ;
  SYMMETRY X Y ;
  SITE GF018hv5v_mcu_sc7 ;
  PIN A1
    DIRECTION INPUT ;
    ANTENNAGATEAREA 0.520000 ;
    PORT
      LAYER Metal1 ;
        RECT 0.660 1.595 1.020 2.855 ;
    END
  END A1
  PIN A2
    DIRECTION INPUT ;
    ANTENNAGATEAREA 0.520000 ;
    PORT
      LAYER Metal1 ;
        RECT 1.780 1.595 2.140 3.390 ;
    END
  END A2
  PIN A3
    DIRECTION INPUT ;
    ANTENNAGATEAREA 0.520000 ;
    PORT
      LAYER Metal1 ;
        RECT 2.900 1.595 3.350 3.390 ;
    END
  END A3
  PIN Z
    DIRECTION OUTPUT ;
    ANTENNADIFFAREA 0.897600 ;
    PORT
      LAYER Metal1 ;
        RECT 4.985 0.530 5.455 3.390 ;
    END
  END Z
  PIN VDD
    DIRECTION INOUT ;
    USE POWER ;
    SHAPE ABUTMENT ;
    PORT
      LAYER Metal1 ;
        RECT 0.000 3.620 5.600 4.220 ;
        RECT 3.965 2.530 4.195 3.620 ;
    END
  END VDD
  PIN VNW
    DIRECTION INOUT ;
    USE POWER ;
    PORT
      LAYER Nwell ;
        RECT -0.430 1.760 6.030 4.350 ;
    END
  END VNW
  PIN VPW
    DIRECTION INOUT ;
    USE GROUND ;
    PORT
      LAYER Pwell ;
        RECT -0.430 -0.430 6.030 1.760 ;
    END
  END VPW
  PIN VSS
    DIRECTION INOUT ;
    USE GROUND ;
    SHAPE ABUTMENT ;
    PORT
      LAYER Metal1 ;
        RECT 1.310 0.300 1.650 0.735 ;
        RECT 3.730 0.300 4.070 0.735 ;
        RECT 0.000 -0.300 5.600 0.300 ;
    END
  END VSS
  OBS
      LAYER Metal1 ;
        RECT 0.180 3.160 1.515 3.390 ;
        RECT 1.285 1.200 1.515 3.160 ;
        RECT 4.445 1.200 4.675 2.220 ;
        RECT 0.190 0.965 4.675 1.200 ;
        RECT 0.190 0.530 0.530 0.965 ;
        RECT 2.430 0.530 2.770 0.965 ;
  END
END gf180mcu_fd_sc_mcu7t5v0__or3_1

#--------EOF---------

MACRO gf180mcu_fd_sc_mcu7t5v0__or3_2
  CLASS core ;
  FOREIGN gf180mcu_fd_sc_mcu7t5v0__or3_2 ;
  ORIGIN 0.000 0.000 ;
  SIZE 6.720 BY 3.920 ;
  SYMMETRY X Y ;
  SITE GF018hv5v_mcu_sc7 ;
  PIN A1
    DIRECTION INPUT ;
    ANTENNAGATEAREA 1.009000 ;
    PORT
      LAYER Metal1 ;
        RECT 1.220 2.140 1.560 3.380 ;
        RECT 0.840 1.730 1.560 2.140 ;
    END
  END A1
  PIN A2
    DIRECTION INPUT ;
    ANTENNAGATEAREA 1.009000 ;
    PORT
      LAYER Metal1 ;
        RECT 1.790 1.610 2.140 3.380 ;
    END
  END A2
  PIN A3
    DIRECTION INPUT ;
    ANTENNAGATEAREA 1.009000 ;
    PORT
      LAYER Metal1 ;
        RECT 2.900 1.610 3.260 3.380 ;
    END
  END A3
  PIN Z
    DIRECTION OUTPUT ;
    ANTENNADIFFAREA 1.182800 ;
    PORT
      LAYER Metal1 ;
        RECT 4.840 2.655 5.460 3.380 ;
        RECT 4.840 2.380 6.040 2.655 ;
        RECT 5.745 1.535 6.040 2.380 ;
        RECT 4.870 1.265 6.040 1.535 ;
        RECT 4.870 0.530 5.490 1.265 ;
    END
  END Z
  PIN VDD
    DIRECTION INOUT ;
    USE POWER ;
    SHAPE ABUTMENT ;
    PORT
      LAYER Metal1 ;
        RECT 0.000 3.620 6.720 4.220 ;
        RECT 3.715 2.530 3.945 3.620 ;
        RECT 5.925 2.935 6.155 3.620 ;
    END
  END VDD
  PIN VNW
    DIRECTION INOUT ;
    USE POWER ;
    PORT
      LAYER Nwell ;
        RECT -0.430 1.760 7.150 4.350 ;
    END
  END VNW
  PIN VPW
    DIRECTION INOUT ;
    USE GROUND ;
    PORT
      LAYER Pwell ;
        RECT -0.430 -0.430 7.150 1.760 ;
    END
  END VPW
  PIN VSS
    DIRECTION INOUT ;
    USE GROUND ;
    SHAPE ABUTMENT ;
    PORT
      LAYER Metal1 ;
        RECT 1.365 0.300 1.595 0.895 ;
        RECT 3.605 0.300 3.835 0.895 ;
        RECT 6.025 0.300 6.255 0.920 ;
        RECT 0.000 -0.300 6.720 0.300 ;
    END
  END VSS
  OBS
      LAYER Metal1 ;
        RECT 0.245 1.360 0.575 3.390 ;
        RECT 3.960 1.765 5.515 1.995 ;
        RECT 3.960 1.360 4.190 1.765 ;
        RECT 0.245 1.125 4.190 1.360 ;
        RECT 0.245 0.530 0.475 1.125 ;
        RECT 2.485 0.530 2.715 1.125 ;
  END
END gf180mcu_fd_sc_mcu7t5v0__or3_2

#--------EOF---------

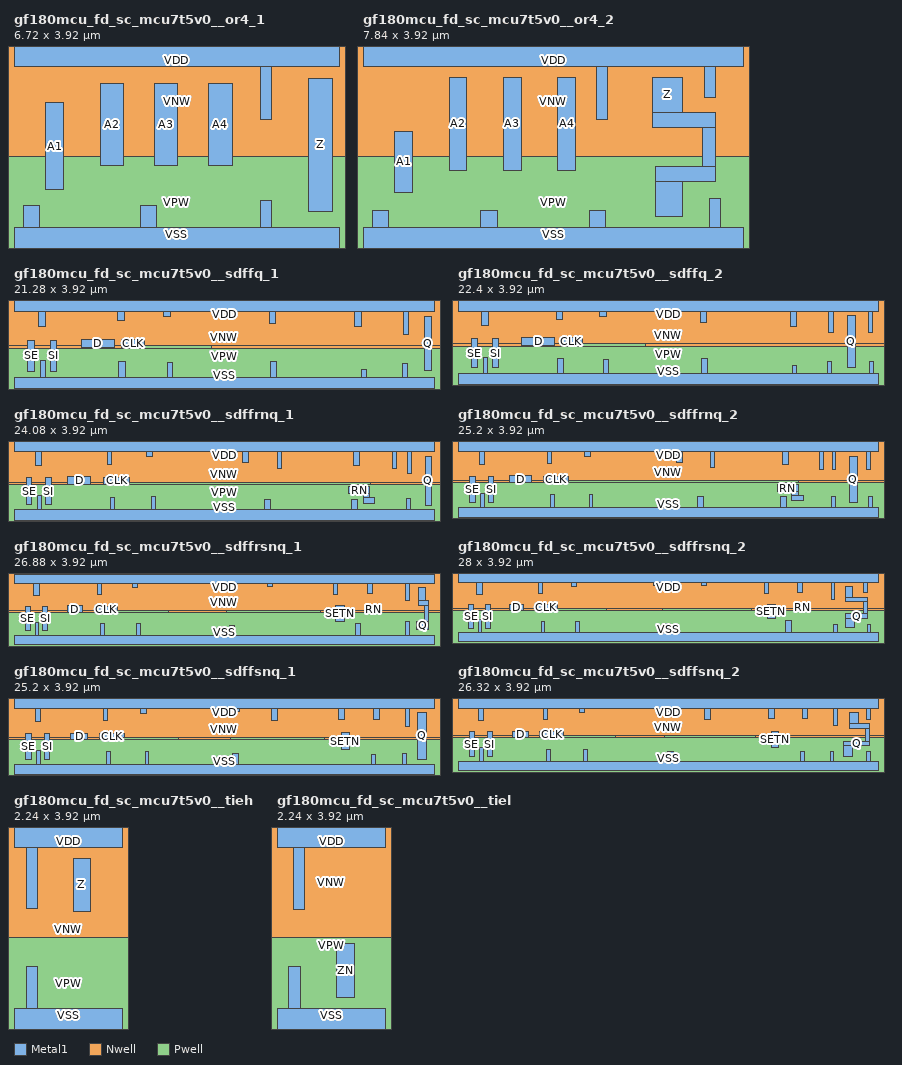
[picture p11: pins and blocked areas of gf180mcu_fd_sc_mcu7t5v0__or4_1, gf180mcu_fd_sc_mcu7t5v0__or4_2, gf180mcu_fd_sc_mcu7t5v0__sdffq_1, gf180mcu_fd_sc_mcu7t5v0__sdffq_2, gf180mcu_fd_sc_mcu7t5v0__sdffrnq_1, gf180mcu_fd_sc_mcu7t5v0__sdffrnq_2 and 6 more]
MACRO gf180mcu_fd_sc_mcu7t5v0__or4_1
  CLASS core ;
  FOREIGN gf180mcu_fd_sc_mcu7t5v0__or4_1 ;
  ORIGIN 0.000 0.000 ;
  SIZE 6.720 BY 3.920 ;
  SYMMETRY X Y ;
  SITE GF018hv5v_mcu_sc7 ;
  PIN A1
    DIRECTION INPUT ;
    ANTENNAGATEAREA 0.496000 ;
    PORT
      LAYER Metal1 ;
        RECT 0.660 1.085 1.020 2.870 ;
    END
  END A1
  PIN A2
    DIRECTION INPUT ;
    ANTENNAGATEAREA 0.496000 ;
    PORT
      LAYER Metal1 ;
        RECT 1.780 1.580 2.260 3.280 ;
    END
  END A2
  PIN A3
    DIRECTION INPUT ;
    ANTENNAGATEAREA 0.496000 ;
    PORT
      LAYER Metal1 ;
        RECT 2.900 1.580 3.380 3.280 ;
    END
  END A3
  PIN A4
    DIRECTION INPUT ;
    ANTENNAGATEAREA 0.496000 ;
    PORT
      LAYER Metal1 ;
        RECT 4.020 1.580 4.500 3.280 ;
    END
  END A4
  PIN Z
    DIRECTION OUTPUT ;
    ANTENNADIFFAREA 0.897600 ;
    PORT
      LAYER Metal1 ;
        RECT 6.070 0.630 6.575 3.380 ;
    END
  END Z
  PIN VDD
    DIRECTION INOUT ;
    USE POWER ;
    SHAPE ABUTMENT ;
    PORT
      LAYER Metal1 ;
        RECT 0.000 3.620 6.720 4.220 ;
        RECT 5.085 2.530 5.315 3.620 ;
    END
  END VDD
  PIN VNW
    DIRECTION INOUT ;
    USE POWER ;
    PORT
      LAYER Nwell ;
        RECT -0.430 1.760 7.150 4.350 ;
    END
  END VNW
  PIN VPW
    DIRECTION INOUT ;
    USE GROUND ;
    PORT
      LAYER Pwell ;
        RECT -0.430 -0.430 7.150 1.760 ;
    END
  END VPW
  PIN VSS
    DIRECTION INOUT ;
    USE GROUND ;
    SHAPE ABUTMENT ;
    PORT
      LAYER Metal1 ;
        RECT 0.190 0.300 0.530 0.760 ;
        RECT 2.610 0.300 2.950 0.760 ;
        RECT 5.085 0.300 5.315 0.855 ;
        RECT 0.000 -0.300 6.720 0.300 ;
    END
  END VSS
  OBS
      LAYER Metal1 ;
        RECT 0.280 3.120 1.530 3.350 ;
        RECT 1.300 1.330 1.530 3.120 ;
        RECT 5.515 1.330 5.765 2.270 ;
        RECT 1.300 1.095 5.765 1.330 ;
        RECT 1.490 0.530 1.830 1.095 ;
        RECT 3.730 0.530 4.070 1.095 ;
  END
END gf180mcu_fd_sc_mcu7t5v0__or4_1

#--------EOF---------

MACRO gf180mcu_fd_sc_mcu7t5v0__or4_2
  CLASS core ;
  FOREIGN gf180mcu_fd_sc_mcu7t5v0__or4_2 ;
  ORIGIN 0.000 0.000 ;
  SIZE 7.840 BY 3.920 ;
  SYMMETRY X Y ;
  SITE GF018hv5v_mcu_sc7 ;
  PIN A1
    DIRECTION INPUT ;
    ANTENNAGATEAREA 0.889000 ;
    PORT
      LAYER Metal1 ;
        RECT 0.660 1.015 1.020 2.290 ;
    END
  END A1
  PIN A2
    DIRECTION INPUT ;
    ANTENNAGATEAREA 0.889000 ;
    PORT
      LAYER Metal1 ;
        RECT 1.780 1.480 2.140 3.390 ;
    END
  END A2
  PIN A3
    DIRECTION INPUT ;
    ANTENNAGATEAREA 0.889000 ;
    PORT
      LAYER Metal1 ;
        RECT 2.900 1.480 3.260 3.390 ;
    END
  END A3
  PIN A4
    DIRECTION INPUT ;
    ANTENNAGATEAREA 0.889000 ;
    PORT
      LAYER Metal1 ;
        RECT 4.020 1.480 4.380 3.390 ;
    END
  END A4
  PIN Z
    DIRECTION OUTPUT ;
    ANTENNADIFFAREA 1.121800 ;
    PORT
      LAYER Metal1 ;
        RECT 5.970 2.680 6.585 3.390 ;
        RECT 5.970 2.360 7.280 2.680 ;
        RECT 7.010 1.560 7.280 2.360 ;
        RECT 6.025 1.240 7.280 1.560 ;
        RECT 6.025 0.530 6.585 1.240 ;
    END
  END Z
  PIN VDD
    DIRECTION INOUT ;
    USE POWER ;
    SHAPE ABUTMENT ;
    PORT
      LAYER Metal1 ;
        RECT 0.000 3.620 7.840 4.220 ;
        RECT 4.820 2.530 5.050 3.620 ;
        RECT 7.045 2.990 7.275 3.620 ;
    END
  END VDD
  PIN VNW
    DIRECTION INOUT ;
    USE POWER ;
    PORT
      LAYER Nwell ;
        RECT -0.430 1.760 8.270 4.350 ;
    END
  END VNW
  PIN VPW
    DIRECTION INOUT ;
    USE GROUND ;
    PORT
      LAYER Pwell ;
        RECT -0.430 -0.430 8.270 1.760 ;
    END
  END VPW
  PIN VSS
    DIRECTION INOUT ;
    USE GROUND ;
    SHAPE ABUTMENT ;
    PORT
      LAYER Metal1 ;
        RECT 0.190 0.300 0.530 0.655 ;
        RECT 2.430 0.300 2.770 0.655 ;
        RECT 4.670 0.300 5.010 0.655 ;
        RECT 7.145 0.300 7.375 0.900 ;
        RECT 0.000 -0.300 7.840 0.300 ;
    END
  END VSS
  OBS
      LAYER Metal1 ;
        RECT 0.345 2.760 0.575 3.390 ;
        RECT 0.345 2.530 1.540 2.760 ;
        RECT 1.310 1.180 1.540 2.530 ;
        RECT 5.030 1.845 6.750 2.075 ;
        RECT 5.030 1.180 5.260 1.845 ;
        RECT 1.310 0.945 5.260 1.180 ;
        RECT 1.310 0.530 1.650 0.945 ;
        RECT 3.550 0.530 3.890 0.945 ;
  END
END gf180mcu_fd_sc_mcu7t5v0__or4_2

#--------EOF---------

MACRO gf180mcu_fd_sc_mcu7t5v0__sdffq_1
  CLASS core ;
  FOREIGN gf180mcu_fd_sc_mcu7t5v0__sdffq_1 ;
  ORIGIN 0.000 0.000 ;
  SIZE 21.280 BY 3.920 ;
  SYMMETRY X Y ;
  SITE GF018hv5v_mcu_sc7 ;
  PIN D
    DIRECTION INPUT ;
    ANTENNAGATEAREA 0.531000 ;
    PORT
      LAYER Metal1 ;
        RECT 3.410 1.795 5.085 2.215 ;
    END
  END D
  PIN SE
    DIRECTION INPUT ;
    ANTENNAGATEAREA 1.062000 ;
    PORT
      LAYER Metal1 ;
        RECT 0.705 0.595 1.030 2.150 ;
    END
  END SE
  PIN SI
    DIRECTION INPUT ;
    ANTENNAGATEAREA 0.531000 ;
    PORT
      LAYER Metal1 ;
        RECT 1.825 0.595 2.150 2.150 ;
    END
  END SI
  PIN CLK
    DIRECTION INPUT ;
    USE CLOCK ;
    ANTENNAGATEAREA 0.739000 ;
    PORT
      LAYER Metal1 ;
        RECT 5.465 1.795 6.630 2.200 ;
    END
  END CLK
  PIN Q
    DIRECTION OUTPUT ;
    ANTENNADIFFAREA 0.893200 ;
    PORT
      LAYER Metal1 ;
        RECT 20.790 0.615 21.150 3.365 ;
    END
  END Q
  PIN VDD
    DIRECTION INOUT ;
    USE POWER ;
    SHAPE ABUTMENT ;
    PORT
      LAYER Metal1 ;
        RECT 0.000 3.620 21.280 4.220 ;
        RECT 1.260 2.845 1.600 3.620 ;
        RECT 5.250 3.180 5.590 3.620 ;
        RECT 7.570 3.350 7.910 3.620 ;
        RECT 12.930 2.995 13.270 3.620 ;
        RECT 17.250 2.845 17.590 3.620 ;
        RECT 19.735 2.460 19.965 3.620 ;
    END
  END VDD
  PIN VNW
    DIRECTION INOUT ;
    USE POWER ;
    PORT
      LAYER Nwell ;
        RECT -0.430 1.885 21.710 4.350 ;
        RECT -0.430 1.760 6.245 1.885 ;
        RECT 10.000 1.760 21.710 1.885 ;
    END
  END VNW
  PIN VPW
    DIRECTION INOUT ;
    USE GROUND ;
    PORT
      LAYER Pwell ;
        RECT 6.245 1.760 10.000 1.885 ;
        RECT -0.430 -0.430 21.710 1.760 ;
    END
  END VPW
  PIN VSS
    DIRECTION INOUT ;
    USE GROUND ;
    SHAPE ABUTMENT ;
    PORT
      LAYER Metal1 ;
        RECT 1.365 0.300 1.595 1.140 ;
        RECT 5.295 0.300 5.635 1.075 ;
        RECT 7.780 0.300 8.010 1.045 ;
        RECT 12.980 0.300 13.320 1.085 ;
        RECT 17.625 0.300 17.855 0.680 ;
        RECT 19.685 0.300 19.915 0.995 ;
        RECT 0.000 -0.300 21.280 0.300 ;
    END
  END VSS
  OBS
      LAYER Metal1 ;
        RECT 5.875 3.120 7.320 3.320 ;
        RECT 8.370 3.120 10.015 3.350 ;
        RECT 5.875 3.090 8.600 3.120 ;
        RECT 0.245 2.615 0.475 3.015 ;
        RECT 5.875 2.935 6.105 3.090 ;
        RECT 3.030 2.705 6.105 2.935 ;
        RECT 7.090 2.890 8.600 3.090 ;
        RECT 6.585 2.660 6.815 2.860 ;
        RECT 0.245 2.385 2.775 2.615 ;
        RECT 6.585 2.430 8.600 2.660 ;
        RECT 0.245 0.790 0.475 2.385 ;
        RECT 2.545 1.625 2.775 2.385 ;
        RECT 4.425 1.305 6.320 1.535 ;
        RECT 4.425 1.075 4.655 1.305 ;
        RECT 3.270 0.845 4.655 1.075 ;
        RECT 6.090 0.760 6.320 1.305 ;
        RECT 6.860 1.275 7.090 2.430 ;
        RECT 8.370 1.875 8.600 2.430 ;
        RECT 8.900 2.050 9.130 2.860 ;
        RECT 9.785 2.690 10.015 3.120 ;
        RECT 10.325 3.150 12.490 3.390 ;
        RECT 10.325 2.050 10.555 3.150 ;
        RECT 8.900 1.820 10.555 2.050 ;
        RECT 6.750 0.990 7.090 1.275 ;
        RECT 7.320 1.305 8.605 1.535 ;
        RECT 7.320 0.760 7.550 1.305 ;
        RECT 6.090 0.530 7.550 0.760 ;
        RECT 8.375 0.760 8.605 1.305 ;
        RECT 9.065 1.275 9.295 1.820 ;
        RECT 10.855 1.700 11.085 2.870 ;
        RECT 12.260 2.765 12.490 3.150 ;
        RECT 13.670 3.160 16.245 3.390 ;
        RECT 13.670 2.765 13.900 3.160 ;
        RECT 12.260 2.530 13.900 2.765 ;
        RECT 14.325 2.300 14.555 2.870 ;
        RECT 12.200 2.070 14.555 2.300 ;
        RECT 10.855 1.470 13.965 1.700 ;
        RECT 9.065 0.990 9.405 1.275 ;
        RECT 9.840 0.760 10.070 1.140 ;
        RECT 10.960 0.800 11.190 1.470 ;
        RECT 14.325 0.800 14.555 2.070 ;
        RECT 14.785 1.260 15.015 3.160 ;
        RECT 15.445 1.775 15.675 2.870 ;
        RECT 15.905 2.070 16.245 3.160 ;
        RECT 16.505 2.315 18.170 2.550 ;
        RECT 16.505 1.775 16.735 2.315 ;
        RECT 15.445 1.540 16.735 1.775 ;
        RECT 17.830 1.670 18.170 2.315 ;
        RECT 18.465 2.010 18.695 2.950 ;
        RECT 18.465 1.780 20.540 2.010 ;
        RECT 15.445 0.800 15.675 1.540 ;
        RECT 16.965 1.230 17.195 1.600 ;
        RECT 18.965 1.230 19.195 1.780 ;
        RECT 16.965 0.995 19.195 1.230 ;
        RECT 18.965 0.760 19.195 0.995 ;
        RECT 8.375 0.530 10.070 0.760 ;
  END
END gf180mcu_fd_sc_mcu7t5v0__sdffq_1

#--------EOF---------

MACRO gf180mcu_fd_sc_mcu7t5v0__sdffq_2
  CLASS core ;
  FOREIGN gf180mcu_fd_sc_mcu7t5v0__sdffq_2 ;
  ORIGIN 0.000 0.000 ;
  SIZE 22.400 BY 3.920 ;
  SYMMETRY X Y ;
  SITE GF018hv5v_mcu_sc7 ;
  PIN D
    DIRECTION INPUT ;
    ANTENNAGATEAREA 0.531000 ;
    PORT
      LAYER Metal1 ;
        RECT 3.410 1.795 5.140 2.215 ;
    END
  END D
  PIN SE
    DIRECTION INPUT ;
    ANTENNAGATEAREA 1.062000 ;
    PORT
      LAYER Metal1 ;
        RECT 0.705 0.595 1.030 2.150 ;
    END
  END SE
  PIN SI
    DIRECTION INPUT ;
    ANTENNAGATEAREA 0.531000 ;
    PORT
      LAYER Metal1 ;
        RECT 1.825 0.595 2.150 2.150 ;
    END
  END SI
  PIN CLK
    DIRECTION INPUT ;
    USE CLOCK ;
    ANTENNAGATEAREA 0.739000 ;
    PORT
      LAYER Metal1 ;
        RECT 5.465 1.795 6.630 2.200 ;
    END
  END CLK
  PIN Q
    DIRECTION OUTPUT ;
    ANTENNADIFFAREA 1.116350 ;
    PORT
      LAYER Metal1 ;
        RECT 20.760 0.615 21.180 3.390 ;
    END
  END Q
  PIN VDD
    DIRECTION INOUT ;
    USE POWER ;
    SHAPE ABUTMENT ;
    PORT
      LAYER Metal1 ;
        RECT 0.000 3.620 22.400 4.220 ;
        RECT 1.260 2.845 1.600 3.620 ;
        RECT 5.250 3.180 5.590 3.620 ;
        RECT 7.570 3.350 7.910 3.620 ;
        RECT 12.930 2.995 13.270 3.620 ;
        RECT 17.710 2.800 18.050 3.620 ;
        RECT 19.785 2.460 20.015 3.620 ;
        RECT 21.875 2.460 22.105 3.620 ;
    END
  END VDD
  PIN VNW
    DIRECTION INOUT ;
    USE POWER ;
    PORT
      LAYER Nwell ;
        RECT -0.430 1.885 22.830 4.350 ;
        RECT -0.430 1.760 6.245 1.885 ;
        RECT 10.000 1.760 22.830 1.885 ;
    END
  END VNW
  PIN VPW
    DIRECTION INOUT ;
    USE GROUND ;
    PORT
      LAYER Pwell ;
        RECT 6.245 1.760 10.000 1.885 ;
        RECT -0.430 -0.430 22.830 1.760 ;
    END
  END VPW
  PIN VSS
    DIRECTION INOUT ;
    USE GROUND ;
    SHAPE ABUTMENT ;
    PORT
      LAYER Metal1 ;
        RECT 1.365 0.300 1.595 1.140 ;
        RECT 5.295 0.300 5.635 1.075 ;
        RECT 7.780 0.300 8.010 1.045 ;
        RECT 12.980 0.300 13.320 1.085 ;
        RECT 17.845 0.300 18.075 0.725 ;
        RECT 19.685 0.300 19.915 0.950 ;
        RECT 21.925 0.300 22.155 0.950 ;
        RECT 0.000 -0.300 22.400 0.300 ;
    END
  END VSS
  OBS
      LAYER Metal1 ;
        RECT 5.875 3.120 7.320 3.320 ;
        RECT 8.370 3.120 10.015 3.350 ;
        RECT 5.875 3.090 8.600 3.120 ;
        RECT 0.245 2.615 0.475 3.015 ;
        RECT 5.875 2.935 6.105 3.090 ;
        RECT 3.030 2.705 6.105 2.935 ;
        RECT 7.090 2.890 8.600 3.090 ;
        RECT 6.585 2.660 6.815 2.860 ;
        RECT 0.245 2.385 2.775 2.615 ;
        RECT 6.585 2.430 8.600 2.660 ;
        RECT 0.245 0.790 0.475 2.385 ;
        RECT 2.545 1.625 2.775 2.385 ;
        RECT 4.425 1.305 6.265 1.535 ;
        RECT 4.425 1.075 4.655 1.305 ;
        RECT 3.270 0.845 4.655 1.075 ;
        RECT 6.035 0.760 6.265 1.305 ;
        RECT 6.860 1.275 7.090 2.430 ;
        RECT 8.370 1.875 8.600 2.430 ;
        RECT 8.900 2.050 9.130 2.860 ;
        RECT 9.785 2.690 10.015 3.120 ;
        RECT 10.325 3.150 12.490 3.390 ;
        RECT 10.325 2.050 10.555 3.150 ;
        RECT 8.900 1.820 10.555 2.050 ;
        RECT 6.750 0.990 7.090 1.275 ;
        RECT 7.320 1.305 8.605 1.535 ;
        RECT 7.320 0.760 7.550 1.305 ;
        RECT 6.035 0.530 7.550 0.760 ;
        RECT 8.375 0.760 8.605 1.305 ;
        RECT 9.065 1.275 9.295 1.820 ;
        RECT 10.855 1.700 11.085 2.870 ;
        RECT 12.260 2.765 12.490 3.150 ;
        RECT 13.670 3.160 16.245 3.390 ;
        RECT 13.670 2.765 13.900 3.160 ;
        RECT 12.260 2.530 13.900 2.765 ;
        RECT 14.325 2.300 14.555 2.870 ;
        RECT 12.200 2.070 14.555 2.300 ;
        RECT 10.855 1.470 13.965 1.700 ;
        RECT 9.065 0.990 9.405 1.275 ;
        RECT 9.840 0.760 10.070 1.140 ;
        RECT 10.960 0.800 11.190 1.470 ;
        RECT 14.285 0.800 14.555 2.070 ;
        RECT 14.785 1.260 15.015 3.160 ;
        RECT 15.425 1.775 15.675 2.870 ;
        RECT 15.905 2.070 16.245 3.160 ;
        RECT 16.655 2.315 18.630 2.550 ;
        RECT 16.655 1.775 16.885 2.315 ;
        RECT 15.425 1.540 16.885 1.775 ;
        RECT 15.425 0.800 15.675 1.540 ;
        RECT 17.200 1.230 17.450 2.080 ;
        RECT 18.290 1.460 18.630 2.315 ;
        RECT 18.965 1.795 19.195 3.345 ;
        RECT 20.245 1.795 20.515 2.085 ;
        RECT 18.965 1.565 20.515 1.795 ;
        RECT 18.965 1.230 19.195 1.565 ;
        RECT 20.245 1.275 20.515 1.565 ;
        RECT 17.200 0.995 19.195 1.230 ;
        RECT 8.375 0.530 10.070 0.760 ;
        RECT 18.965 0.575 19.195 0.995 ;
  END
END gf180mcu_fd_sc_mcu7t5v0__sdffq_2

#--------EOF---------

MACRO gf180mcu_fd_sc_mcu7t5v0__sdffrnq_1
  CLASS core ;
  FOREIGN gf180mcu_fd_sc_mcu7t5v0__sdffrnq_1 ;
  ORIGIN 0.000 0.000 ;
  SIZE 24.080 BY 3.920 ;
  SYMMETRY X Y ;
  SITE GF018hv5v_mcu_sc7 ;
  PIN D
    DIRECTION INPUT ;
    ANTENNAGATEAREA 0.531000 ;
    PORT
      LAYER Metal1 ;
        RECT 3.095 1.765 4.390 2.190 ;
    END
  END D
  PIN RN
    DIRECTION INPUT ;
    ANTENNAGATEAREA 1.062000 ;
    PORT
      LAYER Metal1 ;
        RECT 19.155 1.210 20.410 1.635 ;
        RECT 20.040 1.020 20.410 1.210 ;
        RECT 20.040 0.645 20.670 1.020 ;
    END
  END RN
  PIN SE
    DIRECTION INPUT ;
    ANTENNAGATEAREA 1.062000 ;
    PORT
      LAYER Metal1 ;
        RECT 0.705 0.595 1.030 2.150 ;
    END
  END SE
  PIN SI
    DIRECTION INPUT ;
    ANTENNAGATEAREA 0.531000 ;
    PORT
      LAYER Metal1 ;
        RECT 1.825 0.595 2.150 2.150 ;
    END
  END SI
  PIN CLK
    DIRECTION INPUT ;
    USE CLOCK ;
    ANTENNAGATEAREA 0.741500 ;
    PORT
      LAYER Metal1 ;
        RECT 5.130 1.765 6.630 2.155 ;
    END
  END CLK
  PIN Q
    DIRECTION OUTPUT ;
    ANTENNADIFFAREA 0.891000 ;
    PORT
      LAYER Metal1 ;
        RECT 23.590 0.555 23.950 3.380 ;
    END
  END Q
  PIN VDD
    DIRECTION INOUT ;
    USE POWER ;
    SHAPE ABUTMENT ;
    PORT
      LAYER Metal1 ;
        RECT 0.000 3.620 24.080 4.220 ;
        RECT 1.260 2.845 1.600 3.620 ;
        RECT 5.375 2.885 5.605 3.620 ;
        RECT 7.590 3.350 7.930 3.620 ;
        RECT 13.120 3.000 13.460 3.620 ;
        RECT 15.135 2.665 15.365 3.620 ;
        RECT 19.480 2.845 19.820 3.620 ;
        RECT 21.675 2.675 21.905 3.620 ;
        RECT 22.535 2.360 22.765 3.620 ;
    END
  END VDD
  PIN VNW
    DIRECTION INOUT ;
    USE POWER ;
    PORT
      LAYER Nwell ;
        RECT -0.430 1.885 24.510 4.350 ;
        RECT -0.430 1.760 5.605 1.885 ;
        RECT 20.425 1.760 24.510 1.885 ;
    END
  END VNW
  PIN VPW
    DIRECTION INOUT ;
    USE GROUND ;
    PORT
      LAYER Pwell ;
        RECT 5.605 1.760 20.425 1.885 ;
        RECT -0.430 -0.430 24.510 1.760 ;
    END
  END VPW
  PIN VSS
    DIRECTION INOUT ;
    USE GROUND ;
    SHAPE ABUTMENT ;
    PORT
      LAYER Metal1 ;
        RECT 1.365 0.300 1.595 1.140 ;
        RECT 5.550 0.300 5.780 1.025 ;
        RECT 7.865 0.300 8.095 1.045 ;
        RECT 14.370 0.300 14.710 0.915 ;
        RECT 19.360 0.300 19.700 0.915 ;
        RECT 22.485 0.300 22.715 0.925 ;
        RECT 0.000 -0.300 24.080 0.300 ;
    END
  END VSS
  OBS
      LAYER Metal1 ;
        RECT 6.085 3.160 7.360 3.390 ;
        RECT 0.245 2.615 0.475 3.040 ;
        RECT 3.230 2.745 5.075 2.975 ;
        RECT 4.845 2.655 5.075 2.745 ;
        RECT 6.085 2.655 6.315 3.160 ;
        RECT 7.130 3.120 7.360 3.160 ;
        RECT 8.205 3.160 10.125 3.390 ;
        RECT 8.205 3.120 8.435 3.160 ;
        RECT 7.130 2.890 8.435 3.120 ;
        RECT 0.245 2.385 2.855 2.615 ;
        RECT 4.845 2.420 6.315 2.655 ;
        RECT 6.610 2.620 6.840 2.890 ;
        RECT 6.610 2.385 8.535 2.620 ;
        RECT 0.245 0.780 0.475 2.385 ;
        RECT 2.625 1.535 2.855 2.385 ;
        RECT 4.630 1.535 4.860 1.750 ;
        RECT 2.625 1.305 4.860 1.535 ;
        RECT 5.090 1.260 6.605 1.490 ;
        RECT 6.945 1.275 7.175 2.385 ;
        RECT 8.305 1.910 8.535 2.385 ;
        RECT 8.885 2.035 9.115 2.845 ;
        RECT 9.895 2.645 10.125 3.160 ;
        RECT 17.155 3.160 19.075 3.390 ;
        RECT 10.915 2.295 11.145 3.125 ;
        RECT 11.935 2.760 12.165 3.005 ;
        RECT 14.415 2.760 14.645 3.005 ;
        RECT 11.935 2.530 14.645 2.760 ;
        RECT 16.155 2.300 16.385 3.035 ;
        RECT 10.915 2.065 12.195 2.295 ;
        RECT 12.460 2.070 16.385 2.300 ;
        RECT 17.155 2.690 17.460 3.160 ;
        RECT 8.885 1.800 10.620 2.035 ;
        RECT 5.090 1.075 5.320 1.260 ;
        RECT 3.250 0.845 5.320 1.075 ;
        RECT 6.375 0.760 6.605 1.260 ;
        RECT 6.835 0.990 7.175 1.275 ;
        RECT 7.405 1.295 8.680 1.530 ;
        RECT 7.405 0.760 7.635 1.295 ;
        RECT 6.375 0.530 7.635 0.760 ;
        RECT 8.450 0.760 8.680 1.295 ;
        RECT 9.150 0.990 9.490 1.800 ;
        RECT 9.925 0.760 10.155 0.970 ;
        RECT 8.450 0.530 10.155 0.760 ;
        RECT 11.045 0.630 11.275 2.065 ;
        RECT 11.965 1.840 12.195 2.065 ;
        RECT 11.505 1.375 11.735 1.720 ;
        RECT 11.965 1.610 15.370 1.840 ;
        RECT 11.505 1.145 15.210 1.375 ;
        RECT 14.980 0.760 15.210 1.145 ;
        RECT 15.710 0.990 16.050 2.070 ;
        RECT 16.370 0.760 16.600 1.735 ;
        RECT 17.155 1.220 17.385 2.690 ;
        RECT 18.220 2.420 18.570 2.930 ;
        RECT 18.845 2.615 19.075 3.160 ;
        RECT 20.195 3.155 21.345 3.390 ;
        RECT 20.195 2.615 20.425 3.155 ;
        RECT 16.830 0.990 17.385 1.220 ;
        RECT 17.615 2.060 17.990 2.400 ;
        RECT 17.615 0.760 17.845 2.060 ;
        RECT 18.220 1.745 18.450 2.420 ;
        RECT 18.845 2.385 20.425 2.615 ;
        RECT 20.655 2.155 20.885 2.860 ;
        RECT 18.075 1.510 18.450 1.745 ;
        RECT 18.680 1.925 20.885 2.155 ;
        RECT 21.115 2.030 21.345 3.155 ;
        RECT 18.680 1.680 18.910 1.925 ;
        RECT 20.655 1.790 20.885 1.925 ;
        RECT 20.655 1.560 23.240 1.790 ;
        RECT 18.075 0.790 18.305 1.510 ;
        RECT 21.675 0.810 21.905 1.560 ;
        RECT 14.980 0.530 17.845 0.760 ;
  END
END gf180mcu_fd_sc_mcu7t5v0__sdffrnq_1

#--------EOF---------

MACRO gf180mcu_fd_sc_mcu7t5v0__sdffrnq_2
  CLASS core ;
  FOREIGN gf180mcu_fd_sc_mcu7t5v0__sdffrnq_2 ;
  ORIGIN 0.000 0.000 ;
  SIZE 25.200 BY 3.920 ;
  SYMMETRY X Y ;
  SITE GF018hv5v_mcu_sc7 ;
  PIN D
    DIRECTION INPUT ;
    ANTENNAGATEAREA 0.531000 ;
    PORT
      LAYER Metal1 ;
        RECT 3.095 1.765 4.390 2.190 ;
    END
  END D
  PIN RN
    DIRECTION INPUT ;
    ANTENNAGATEAREA 1.315000 ;
    PORT
      LAYER Metal1 ;
        RECT 19.155 1.210 20.410 1.635 ;
        RECT 20.035 1.020 20.410 1.210 ;
        RECT 20.035 0.665 20.700 1.020 ;
    END
  END RN
  PIN SE
    DIRECTION INPUT ;
    ANTENNAGATEAREA 1.062000 ;
    PORT
      LAYER Metal1 ;
        RECT 0.705 0.595 1.030 2.150 ;
    END
  END SE
  PIN SI
    DIRECTION INPUT ;
    ANTENNAGATEAREA 0.531000 ;
    PORT
      LAYER Metal1 ;
        RECT 1.825 0.595 2.150 2.150 ;
    END
  END SI
  PIN CLK
    DIRECTION INPUT ;
    USE CLOCK ;
    ANTENNAGATEAREA 0.741500 ;
    PORT
      LAYER Metal1 ;
        RECT 5.130 1.765 6.630 2.155 ;
    END
  END CLK
  PIN Q
    DIRECTION OUTPUT ;
    ANTENNADIFFAREA 1.113750 ;
    PORT
      LAYER Metal1 ;
        RECT 23.460 0.600 23.980 3.360 ;
    END
  END Q
  PIN VDD
    DIRECTION INOUT ;
    USE POWER ;
    SHAPE ABUTMENT ;
    PORT
      LAYER Metal1 ;
        RECT 0.000 3.620 25.200 4.220 ;
        RECT 1.260 2.845 1.600 3.620 ;
        RECT 5.375 2.885 5.605 3.620 ;
        RECT 7.590 3.350 7.930 3.620 ;
        RECT 13.120 3.000 13.460 3.620 ;
        RECT 15.135 2.665 15.365 3.620 ;
        RECT 19.480 2.845 19.820 3.620 ;
        RECT 21.675 2.570 21.905 3.620 ;
        RECT 22.445 2.560 22.675 3.620 ;
        RECT 24.535 2.560 24.765 3.620 ;
    END
  END VDD
  PIN VNW
    DIRECTION INOUT ;
    USE POWER ;
    PORT
      LAYER Nwell ;
        RECT -0.430 1.885 25.630 4.350 ;
        RECT -0.430 1.760 5.605 1.885 ;
        RECT 20.425 1.760 25.630 1.885 ;
    END
  END VNW
  PIN VPW
    DIRECTION INOUT ;
    USE GROUND ;
    PORT
      LAYER Pwell ;
        RECT 5.605 1.760 20.425 1.885 ;
        RECT -0.430 -0.430 25.630 1.760 ;
    END
  END VPW
  PIN VSS
    DIRECTION INOUT ;
    USE GROUND ;
    SHAPE ABUTMENT ;
    PORT
      LAYER Metal1 ;
        RECT 1.365 0.300 1.595 1.140 ;
        RECT 5.550 0.300 5.780 1.025 ;
        RECT 7.865 0.300 8.095 1.045 ;
        RECT 14.370 0.300 14.710 0.915 ;
        RECT 19.360 0.300 19.700 0.915 ;
        RECT 22.395 0.300 22.625 0.925 ;
        RECT 24.635 0.300 24.865 0.925 ;
        RECT 0.000 -0.300 25.200 0.300 ;
    END
  END VSS
  OBS
      LAYER Metal1 ;
        RECT 6.085 3.160 7.360 3.390 ;
        RECT 0.245 2.615 0.475 3.040 ;
        RECT 3.270 2.745 5.075 2.975 ;
        RECT 4.845 2.655 5.075 2.745 ;
        RECT 6.085 2.655 6.315 3.160 ;
        RECT 7.130 3.120 7.360 3.160 ;
        RECT 8.205 3.160 10.125 3.390 ;
        RECT 8.205 3.120 8.435 3.160 ;
        RECT 7.130 2.890 8.435 3.120 ;
        RECT 0.245 2.385 2.855 2.615 ;
        RECT 4.845 2.420 6.315 2.655 ;
        RECT 6.610 2.620 6.840 2.890 ;
        RECT 6.610 2.385 8.535 2.620 ;
        RECT 0.245 0.780 0.475 2.385 ;
        RECT 2.625 1.535 2.855 2.385 ;
        RECT 4.630 1.535 4.860 1.750 ;
        RECT 2.625 1.305 4.860 1.535 ;
        RECT 5.090 1.260 6.605 1.490 ;
        RECT 6.945 1.275 7.175 2.385 ;
        RECT 8.305 1.910 8.535 2.385 ;
        RECT 8.885 2.035 9.115 2.845 ;
        RECT 9.895 2.645 10.125 3.160 ;
        RECT 17.155 3.160 19.075 3.390 ;
        RECT 10.915 2.295 11.145 3.125 ;
        RECT 11.935 2.760 12.165 3.005 ;
        RECT 14.415 2.760 14.645 3.005 ;
        RECT 11.935 2.530 14.645 2.760 ;
        RECT 16.155 2.300 16.385 3.035 ;
        RECT 10.915 2.065 12.195 2.295 ;
        RECT 12.460 2.070 16.385 2.300 ;
        RECT 17.155 2.690 17.460 3.160 ;
        RECT 8.885 1.800 10.620 2.035 ;
        RECT 5.090 1.075 5.320 1.260 ;
        RECT 3.250 0.845 5.320 1.075 ;
        RECT 6.375 0.760 6.605 1.260 ;
        RECT 6.835 0.990 7.175 1.275 ;
        RECT 7.405 1.295 8.680 1.530 ;
        RECT 7.405 0.760 7.635 1.295 ;
        RECT 6.375 0.530 7.635 0.760 ;
        RECT 8.450 0.760 8.680 1.295 ;
        RECT 9.150 0.990 9.490 1.800 ;
        RECT 9.925 0.760 10.155 0.970 ;
        RECT 8.450 0.530 10.155 0.760 ;
        RECT 11.045 0.630 11.275 2.065 ;
        RECT 11.965 1.840 12.195 2.065 ;
        RECT 11.505 1.375 11.735 1.720 ;
        RECT 11.965 1.610 15.370 1.840 ;
        RECT 11.505 1.145 15.210 1.375 ;
        RECT 14.980 0.760 15.210 1.145 ;
        RECT 15.710 0.990 16.050 2.070 ;
        RECT 16.370 0.760 16.600 1.735 ;
        RECT 17.155 1.220 17.385 2.690 ;
        RECT 18.220 2.420 18.570 2.930 ;
        RECT 18.845 2.615 19.075 3.160 ;
        RECT 20.195 3.155 21.345 3.390 ;
        RECT 20.195 2.615 20.425 3.155 ;
        RECT 16.830 0.990 17.385 1.220 ;
        RECT 17.615 2.060 17.990 2.400 ;
        RECT 17.615 0.760 17.845 2.060 ;
        RECT 18.220 1.745 18.450 2.420 ;
        RECT 18.845 2.385 20.425 2.615 ;
        RECT 20.655 2.155 20.885 2.860 ;
        RECT 18.075 1.510 18.450 1.745 ;
        RECT 18.680 1.925 20.885 2.155 ;
        RECT 21.115 2.030 21.345 3.155 ;
        RECT 18.680 1.680 18.910 1.925 ;
        RECT 20.655 1.635 20.885 1.925 ;
        RECT 22.915 1.635 23.145 2.250 ;
        RECT 18.075 0.790 18.305 1.510 ;
        RECT 20.655 1.405 23.145 1.635 ;
        RECT 21.675 0.810 21.905 1.405 ;
        RECT 14.980 0.530 17.845 0.760 ;
  END
END gf180mcu_fd_sc_mcu7t5v0__sdffrnq_2

#--------EOF---------

MACRO gf180mcu_fd_sc_mcu7t5v0__sdffrsnq_1
  CLASS core ;
  FOREIGN gf180mcu_fd_sc_mcu7t5v0__sdffrsnq_1 ;
  ORIGIN 0.000 0.000 ;
  SIZE 26.880 BY 3.920 ;
  SYMMETRY X Y ;
  SITE GF018hv5v_mcu_sc7 ;
  PIN D
    DIRECTION INPUT ;
    ANTENNAGATEAREA 0.531000 ;
    PORT
      LAYER Metal1 ;
        RECT 3.405 1.765 4.390 2.190 ;
    END
  END D
  PIN RN
    DIRECTION INPUT ;
    ANTENNAGATEAREA 1.204500 ;
    PORT
      LAYER Metal1 ;
        RECT 22.525 1.765 23.430 2.155 ;
    END
  END RN
  PIN SE
    DIRECTION INPUT ;
    ANTENNAGATEAREA 1.062000 ;
    PORT
      LAYER Metal1 ;
        RECT 0.705 0.595 1.030 2.150 ;
    END
  END SE
  PIN SETN
    DIRECTION INPUT ;
    ANTENNAGATEAREA 1.062000 ;
    PORT
      LAYER Metal1 ;
        RECT 20.605 1.210 21.140 2.195 ;
    END
  END SETN
  PIN SI
    DIRECTION INPUT ;
    ANTENNAGATEAREA 0.531000 ;
    PORT
      LAYER Metal1 ;
        RECT 1.825 0.595 2.150 2.150 ;
    END
  END SI
  PIN CLK
    DIRECTION INPUT ;
    USE CLOCK ;
    ANTENNAGATEAREA 0.741500 ;
    PORT
      LAYER Metal1 ;
        RECT 5.130 1.765 6.630 2.155 ;
    END
  END CLK
  PIN Q
    DIRECTION OUTPUT ;
    ANTENNADIFFAREA 0.897600 ;
    PORT
      LAYER Metal1 ;
        RECT 25.860 2.505 26.320 3.380 ;
        RECT 25.860 2.205 26.555 2.505 ;
        RECT 26.255 1.160 26.555 2.205 ;
        RECT 25.755 0.655 26.555 1.160 ;
    END
  END Q
  PIN VDD
    DIRECTION INOUT ;
    USE POWER ;
    SHAPE ABUTMENT ;
    PORT
      LAYER Metal1 ;
        RECT 0.000 3.620 26.880 4.220 ;
        RECT 1.260 2.845 1.600 3.620 ;
        RECT 5.375 2.885 5.605 3.620 ;
        RECT 7.590 3.350 7.930 3.620 ;
        RECT 13.010 3.445 13.350 3.620 ;
        RECT 16.200 3.445 16.560 3.620 ;
        RECT 20.465 2.915 20.695 3.620 ;
        RECT 22.630 2.970 22.970 3.620 ;
        RECT 25.055 2.530 25.285 3.620 ;
    END
  END VDD
  PIN VNW
    DIRECTION INOUT ;
    USE POWER ;
    PORT
      LAYER Nwell ;
        RECT -0.430 1.885 27.310 4.350 ;
        RECT -0.430 1.760 6.455 1.885 ;
        RECT 9.870 1.760 13.630 1.885 ;
        RECT 19.590 1.760 27.310 1.885 ;
    END
  END VNW
  PIN VPW
    DIRECTION INOUT ;
    USE GROUND ;
    PORT
      LAYER Pwell ;
        RECT 6.455 1.760 9.870 1.885 ;
        RECT 13.630 1.760 19.590 1.885 ;
        RECT -0.430 -0.430 27.310 1.760 ;
    END
  END VPW
  PIN VSS
    DIRECTION INOUT ;
    USE GROUND ;
    SHAPE ABUTMENT ;
    PORT
      LAYER Metal1 ;
        RECT 1.365 0.300 1.595 1.140 ;
        RECT 5.550 0.300 5.780 1.025 ;
        RECT 7.865 0.300 8.095 1.045 ;
        RECT 13.780 0.300 14.140 0.915 ;
        RECT 21.860 0.300 22.200 1.075 ;
        RECT 25.055 0.300 25.285 1.160 ;
        RECT 0.000 -0.300 26.880 0.300 ;
    END
  END VSS
  OBS
      LAYER Metal1 ;
        RECT 6.085 3.160 7.360 3.390 ;
        RECT 0.245 2.615 0.475 3.040 ;
        RECT 3.270 2.745 5.075 2.975 ;
        RECT 4.845 2.655 5.075 2.745 ;
        RECT 6.085 2.655 6.315 3.160 ;
        RECT 7.130 3.120 7.360 3.160 ;
        RECT 8.205 3.160 9.835 3.390 ;
        RECT 11.265 3.215 12.780 3.390 ;
        RECT 13.580 3.215 15.970 3.390 ;
        RECT 16.790 3.215 18.275 3.390 ;
        RECT 11.265 3.160 18.275 3.215 ;
        RECT 8.205 3.120 8.435 3.160 ;
        RECT 7.130 2.890 8.435 3.120 ;
        RECT 0.245 2.385 2.855 2.615 ;
        RECT 4.845 2.420 6.315 2.655 ;
        RECT 6.610 2.620 6.840 2.890 ;
        RECT 6.610 2.385 8.535 2.620 ;
        RECT 0.245 0.780 0.475 2.385 ;
        RECT 2.625 1.535 2.855 2.385 ;
        RECT 4.630 1.535 4.860 1.750 ;
        RECT 2.625 1.305 4.860 1.535 ;
        RECT 5.090 1.260 6.240 1.490 ;
        RECT 6.945 1.275 7.175 2.385 ;
        RECT 8.305 1.910 8.535 2.385 ;
        RECT 8.885 2.035 9.115 2.845 ;
        RECT 9.605 2.485 9.835 3.160 ;
        RECT 12.550 2.985 13.810 3.160 ;
        RECT 15.740 2.985 17.020 3.160 ;
        RECT 10.800 2.295 11.030 2.870 ;
        RECT 11.680 2.755 12.200 2.775 ;
        RECT 14.160 2.755 14.600 2.780 ;
        RECT 11.680 2.525 14.600 2.755 ;
        RECT 14.960 2.755 15.400 2.780 ;
        RECT 17.360 2.755 17.790 2.780 ;
        RECT 14.960 2.525 17.790 2.755 ;
        RECT 10.800 2.065 15.905 2.295 ;
        RECT 8.885 1.800 10.405 2.035 ;
        RECT 5.090 1.075 5.320 1.260 ;
        RECT 3.250 0.845 5.320 1.075 ;
        RECT 6.010 0.760 6.240 1.260 ;
        RECT 6.835 0.990 7.175 1.275 ;
        RECT 7.405 1.295 8.680 1.530 ;
        RECT 7.405 0.760 7.635 1.295 ;
        RECT 6.010 0.530 7.635 0.760 ;
        RECT 8.450 0.760 8.680 1.295 ;
        RECT 9.150 0.990 9.490 1.800 ;
        RECT 9.925 0.760 10.155 0.980 ;
        RECT 8.450 0.530 10.155 0.760 ;
        RECT 11.045 0.620 11.275 2.065 ;
        RECT 16.325 1.835 16.665 2.525 ;
        RECT 18.045 2.035 18.275 3.160 ;
        RECT 18.525 3.160 20.235 3.390 ;
        RECT 11.625 1.375 11.855 1.700 ;
        RECT 12.295 1.605 16.665 1.835 ;
        RECT 18.525 1.805 18.755 3.160 ;
        RECT 19.545 2.225 19.775 2.835 ;
        RECT 20.005 2.685 20.235 3.160 ;
        RECT 20.925 3.160 22.310 3.390 ;
        RECT 20.925 2.685 21.155 3.160 ;
        RECT 20.005 2.455 21.155 2.685 ;
        RECT 11.625 1.145 14.600 1.375 ;
        RECT 14.370 0.760 14.600 1.145 ;
        RECT 16.325 0.990 16.665 1.605 ;
        RECT 16.940 0.760 17.170 1.745 ;
        RECT 17.445 1.575 18.755 1.805 ;
        RECT 18.985 1.995 20.185 2.225 ;
        RECT 21.430 2.155 21.770 2.930 ;
        RECT 22.080 2.740 22.310 3.160 ;
        RECT 23.200 3.160 24.490 3.390 ;
        RECT 23.200 2.740 23.430 3.160 ;
        RECT 22.080 2.510 23.430 2.740 ;
        RECT 17.445 0.990 17.785 1.575 ;
        RECT 18.985 1.220 19.215 1.995 ;
        RECT 18.570 0.990 19.215 1.220 ;
        RECT 19.445 0.760 19.675 1.765 ;
        RECT 14.370 0.530 19.675 0.760 ;
        RECT 19.955 0.960 20.185 1.995 ;
        RECT 21.400 1.925 21.770 2.155 ;
        RECT 21.400 0.960 21.630 1.925 ;
        RECT 22.065 1.535 22.295 2.200 ;
        RECT 23.690 1.535 24.030 2.930 ;
        RECT 24.260 2.060 24.490 3.160 ;
        RECT 24.335 1.600 25.780 1.830 ;
        RECT 24.335 1.535 24.565 1.600 ;
        RECT 22.065 1.305 24.565 1.535 ;
        RECT 19.955 0.715 21.630 0.960 ;
        RECT 24.335 0.780 24.565 1.305 ;
  END
END gf180mcu_fd_sc_mcu7t5v0__sdffrsnq_1

#--------EOF---------

MACRO gf180mcu_fd_sc_mcu7t5v0__sdffrsnq_2
  CLASS core ;
  FOREIGN gf180mcu_fd_sc_mcu7t5v0__sdffrsnq_2 ;
  ORIGIN 0.000 0.000 ;
  SIZE 28.000 BY 3.920 ;
  SYMMETRY X Y ;
  SITE GF018hv5v_mcu_sc7 ;
  PIN D
    DIRECTION INPUT ;
    ANTENNAGATEAREA 0.531000 ;
    PORT
      LAYER Metal1 ;
        RECT 3.410 1.765 4.390 2.155 ;
    END
  END D
  PIN RN
    DIRECTION INPUT ;
    ANTENNAGATEAREA 1.354500 ;
    PORT
      LAYER Metal1 ;
        RECT 22.490 1.765 23.430 2.155 ;
    END
  END RN
  PIN SE
    DIRECTION INPUT ;
    ANTENNAGATEAREA 1.062000 ;
    PORT
      LAYER Metal1 ;
        RECT 0.705 0.595 1.030 2.150 ;
    END
  END SE
  PIN SETN
    DIRECTION INPUT ;
    ANTENNAGATEAREA 1.062000 ;
    PORT
      LAYER Metal1 ;
        RECT 20.605 1.210 21.140 2.190 ;
    END
  END SETN
  PIN SI
    DIRECTION INPUT ;
    ANTENNAGATEAREA 0.531000 ;
    PORT
      LAYER Metal1 ;
        RECT 1.825 0.595 2.150 2.150 ;
    END
  END SI
  PIN CLK
    DIRECTION INPUT ;
    USE CLOCK ;
    ANTENNAGATEAREA 0.741500 ;
    PORT
      LAYER Metal1 ;
        RECT 5.130 1.765 6.630 2.155 ;
    END
  END CLK
  PIN Q
    DIRECTION OUTPUT ;
    ANTENNADIFFAREA 1.060800 ;
    PORT
      LAYER Metal1 ;
        RECT 25.850 2.660 26.300 3.380 ;
        RECT 25.850 2.385 27.310 2.660 ;
        RECT 27.025 1.535 27.310 2.385 ;
        RECT 25.850 1.210 27.310 1.535 ;
        RECT 25.850 0.610 26.435 1.210 ;
    END
  END Q
  PIN VDD
    DIRECTION INOUT ;
    USE POWER ;
    SHAPE ABUTMENT ;
    PORT
      LAYER Metal1 ;
        RECT 0.000 3.620 28.000 4.220 ;
        RECT 1.260 2.845 1.600 3.620 ;
        RECT 5.375 2.885 5.605 3.620 ;
        RECT 7.590 3.350 7.930 3.620 ;
        RECT 13.010 3.445 13.350 3.620 ;
        RECT 16.200 3.445 16.560 3.620 ;
        RECT 20.465 2.915 20.695 3.620 ;
        RECT 22.630 2.970 22.970 3.620 ;
        RECT 24.885 2.530 25.115 3.620 ;
        RECT 27.055 2.940 27.285 3.620 ;
    END
  END VDD
  PIN VNW
    DIRECTION INOUT ;
    USE POWER ;
    PORT
      LAYER Nwell ;
        RECT -0.430 1.885 28.430 4.350 ;
        RECT -0.430 1.760 6.455 1.885 ;
        RECT 9.870 1.760 13.630 1.885 ;
        RECT 19.590 1.760 28.430 1.885 ;
    END
  END VNW
  PIN VPW
    DIRECTION INOUT ;
    USE GROUND ;
    PORT
      LAYER Pwell ;
        RECT 6.455 1.760 9.870 1.885 ;
        RECT 13.630 1.760 19.590 1.885 ;
        RECT -0.430 -0.430 28.430 1.760 ;
    END
  END VPW
  PIN VSS
    DIRECTION INOUT ;
    USE GROUND ;
    SHAPE ABUTMENT ;
    PORT
      LAYER Metal1 ;
        RECT 1.365 0.300 1.595 1.140 ;
        RECT 5.550 0.300 5.780 1.025 ;
        RECT 7.865 0.300 8.095 1.045 ;
        RECT 13.780 0.300 14.140 0.915 ;
        RECT 21.860 0.300 22.200 1.075 ;
        RECT 25.055 0.300 25.285 0.850 ;
        RECT 27.295 0.300 27.525 0.850 ;
        RECT 0.000 -0.300 28.000 0.300 ;
    END
  END VSS
  OBS
      LAYER Metal1 ;
        RECT 6.085 3.160 7.360 3.390 ;
        RECT 0.245 2.615 0.475 3.040 ;
        RECT 3.270 2.745 4.120 2.975 ;
        RECT 3.890 2.655 4.120 2.745 ;
        RECT 6.085 2.655 6.315 3.160 ;
        RECT 7.130 3.120 7.360 3.160 ;
        RECT 8.205 3.160 9.835 3.390 ;
        RECT 11.265 3.215 12.780 3.390 ;
        RECT 13.580 3.215 15.970 3.390 ;
        RECT 16.790 3.215 18.275 3.390 ;
        RECT 11.265 3.160 18.275 3.215 ;
        RECT 8.205 3.120 8.435 3.160 ;
        RECT 7.130 2.890 8.435 3.120 ;
        RECT 0.245 2.385 2.855 2.615 ;
        RECT 3.890 2.420 6.315 2.655 ;
        RECT 6.610 2.620 6.840 2.890 ;
        RECT 6.610 2.385 8.535 2.620 ;
        RECT 0.245 0.780 0.475 2.385 ;
        RECT 2.625 1.535 2.855 2.385 ;
        RECT 4.630 1.535 4.860 1.750 ;
        RECT 2.625 1.305 4.860 1.535 ;
        RECT 5.090 1.260 6.240 1.490 ;
        RECT 6.945 1.275 7.175 2.385 ;
        RECT 8.305 1.910 8.535 2.385 ;
        RECT 8.885 2.035 9.115 2.890 ;
        RECT 9.605 2.485 9.835 3.160 ;
        RECT 12.550 2.985 13.810 3.160 ;
        RECT 15.740 2.985 17.020 3.160 ;
        RECT 10.800 2.295 11.030 2.870 ;
        RECT 11.680 2.755 12.200 2.775 ;
        RECT 14.160 2.755 14.600 2.780 ;
        RECT 11.680 2.525 14.600 2.755 ;
        RECT 14.960 2.755 15.400 2.780 ;
        RECT 17.360 2.755 17.790 2.780 ;
        RECT 14.960 2.525 17.790 2.755 ;
        RECT 10.800 2.065 15.905 2.295 ;
        RECT 8.885 1.800 10.390 2.035 ;
        RECT 5.090 1.075 5.320 1.260 ;
        RECT 3.250 0.845 5.320 1.075 ;
        RECT 6.010 0.760 6.240 1.260 ;
        RECT 6.835 0.990 7.175 1.275 ;
        RECT 7.405 1.295 8.680 1.530 ;
        RECT 7.405 0.760 7.635 1.295 ;
        RECT 6.010 0.530 7.635 0.760 ;
        RECT 8.450 0.760 8.680 1.295 ;
        RECT 9.150 0.990 9.490 1.800 ;
        RECT 9.925 0.760 10.155 0.980 ;
        RECT 8.450 0.530 10.155 0.760 ;
        RECT 11.045 0.620 11.275 2.065 ;
        RECT 16.325 1.835 16.665 2.525 ;
        RECT 18.045 2.035 18.275 3.160 ;
        RECT 18.525 3.160 20.235 3.390 ;
        RECT 11.625 1.375 11.855 1.700 ;
        RECT 12.295 1.605 16.665 1.835 ;
        RECT 18.525 1.805 18.755 3.160 ;
        RECT 19.545 2.225 19.775 2.835 ;
        RECT 20.005 2.685 20.235 3.160 ;
        RECT 20.925 3.160 22.315 3.390 ;
        RECT 20.925 2.685 21.155 3.160 ;
        RECT 20.005 2.455 21.155 2.685 ;
        RECT 11.625 1.145 14.600 1.375 ;
        RECT 14.370 0.760 14.600 1.145 ;
        RECT 16.325 0.990 16.665 1.605 ;
        RECT 16.940 0.760 17.170 1.745 ;
        RECT 17.445 1.575 18.755 1.805 ;
        RECT 18.985 1.995 20.185 2.225 ;
        RECT 21.430 2.155 21.770 2.930 ;
        RECT 22.080 2.740 22.315 3.160 ;
        RECT 23.200 3.160 24.490 3.390 ;
        RECT 23.200 2.740 23.430 3.160 ;
        RECT 22.080 2.510 23.430 2.740 ;
        RECT 17.445 0.990 17.785 1.575 ;
        RECT 18.985 1.220 19.215 1.995 ;
        RECT 18.570 0.990 19.215 1.220 ;
        RECT 19.445 0.760 19.675 1.765 ;
        RECT 14.370 0.530 19.675 0.760 ;
        RECT 19.955 0.960 20.185 1.995 ;
        RECT 21.400 1.925 21.770 2.155 ;
        RECT 21.400 0.960 21.630 1.925 ;
        RECT 22.010 1.535 22.240 2.200 ;
        RECT 23.690 1.535 24.030 2.930 ;
        RECT 24.260 1.910 24.490 3.160 ;
        RECT 24.945 1.825 26.790 2.095 ;
        RECT 24.945 1.535 25.175 1.825 ;
        RECT 22.010 1.305 25.175 1.535 ;
        RECT 19.955 0.715 21.630 0.960 ;
        RECT 24.335 0.640 24.565 1.305 ;
  END
END gf180mcu_fd_sc_mcu7t5v0__sdffrsnq_2

#--------EOF---------

MACRO gf180mcu_fd_sc_mcu7t5v0__sdffsnq_1
  CLASS core ;
  FOREIGN gf180mcu_fd_sc_mcu7t5v0__sdffsnq_1 ;
  ORIGIN 0.000 0.000 ;
  SIZE 25.200 BY 3.920 ;
  SYMMETRY X Y ;
  SITE GF018hv5v_mcu_sc7 ;
  PIN D
    DIRECTION INPUT ;
    ANTENNAGATEAREA 0.531000 ;
    PORT
      LAYER Metal1 ;
        RECT 3.410 1.765 4.390 2.155 ;
    END
  END D
  PIN SE
    DIRECTION INPUT ;
    ANTENNAGATEAREA 1.062000 ;
    PORT
      LAYER Metal1 ;
        RECT 0.705 0.595 1.030 2.150 ;
    END
  END SE
  PIN SETN
    DIRECTION INPUT ;
    ANTENNAGATEAREA 1.057000 ;
    PORT
      LAYER Metal1 ;
        RECT 19.620 1.170 20.110 2.190 ;
    END
  END SETN
  PIN SI
    DIRECTION INPUT ;
    ANTENNAGATEAREA 0.531000 ;
    PORT
      LAYER Metal1 ;
        RECT 1.825 0.595 2.150 2.150 ;
    END
  END SI
  PIN CLK
    DIRECTION INPUT ;
    USE CLOCK ;
    ANTENNAGATEAREA 0.741500 ;
    PORT
      LAYER Metal1 ;
        RECT 5.130 1.765 6.630 2.155 ;
    END
  END CLK
  PIN Q
    DIRECTION OUTPUT ;
    ANTENNADIFFAREA 0.897600 ;
    PORT
      LAYER Metal1 ;
        RECT 24.220 0.595 24.770 3.380 ;
    END
  END Q
  PIN VDD
    DIRECTION INOUT ;
    USE POWER ;
    SHAPE ABUTMENT ;
    PORT
      LAYER Metal1 ;
        RECT 0.000 3.620 25.200 4.220 ;
        RECT 1.260 2.845 1.600 3.620 ;
        RECT 5.375 2.885 5.605 3.620 ;
        RECT 7.590 3.350 7.930 3.620 ;
        RECT 13.190 3.445 13.530 3.620 ;
        RECT 15.460 2.910 15.820 3.620 ;
        RECT 19.470 2.965 19.810 3.620 ;
        RECT 21.590 2.965 21.930 3.620 ;
        RECT 23.515 2.530 23.745 3.620 ;
    END
  END VDD
  PIN VNW
    DIRECTION INOUT ;
    USE POWER ;
    PORT
      LAYER Nwell ;
        RECT -0.430 1.885 25.630 4.350 ;
        RECT -0.430 1.760 6.455 1.885 ;
        RECT 9.875 1.760 12.970 1.885 ;
        RECT 18.650 1.760 25.630 1.885 ;
    END
  END VNW
  PIN VPW
    DIRECTION INOUT ;
    USE GROUND ;
    PORT
      LAYER Pwell ;
        RECT 6.455 1.760 9.875 1.885 ;
        RECT 12.970 1.760 18.650 1.885 ;
        RECT -0.430 -0.430 25.630 1.760 ;
    END
  END VPW
  PIN VSS
    DIRECTION INOUT ;
    USE GROUND ;
    SHAPE ABUTMENT ;
    PORT
      LAYER Metal1 ;
        RECT 1.365 0.300 1.595 1.140 ;
        RECT 5.550 0.300 5.780 1.025 ;
        RECT 7.865 0.300 8.095 1.045 ;
        RECT 13.120 0.300 13.480 0.915 ;
        RECT 21.475 0.300 21.705 0.890 ;
        RECT 23.315 0.300 23.545 0.905 ;
        RECT 0.000 -0.300 25.200 0.300 ;
    END
  END VSS
  OBS
      LAYER Metal1 ;
        RECT 6.085 3.160 7.360 3.390 ;
        RECT 0.245 2.615 0.475 3.040 ;
        RECT 3.270 2.745 4.120 2.975 ;
        RECT 3.890 2.655 4.120 2.745 ;
        RECT 6.085 2.655 6.315 3.160 ;
        RECT 7.130 3.120 7.360 3.160 ;
        RECT 8.205 3.160 9.835 3.390 ;
        RECT 11.265 3.215 12.780 3.390 ;
        RECT 13.760 3.215 15.230 3.390 ;
        RECT 11.265 3.160 15.230 3.215 ;
        RECT 8.205 3.120 8.435 3.160 ;
        RECT 7.130 2.890 8.435 3.120 ;
        RECT 0.245 2.385 2.855 2.615 ;
        RECT 3.890 2.420 6.315 2.655 ;
        RECT 6.610 2.620 6.840 2.890 ;
        RECT 6.610 2.385 8.535 2.620 ;
        RECT 0.245 0.780 0.475 2.385 ;
        RECT 2.625 1.535 2.855 2.385 ;
        RECT 4.630 1.535 4.860 1.740 ;
        RECT 2.625 1.305 4.860 1.535 ;
        RECT 5.090 1.260 6.240 1.490 ;
        RECT 6.945 1.275 7.175 2.385 ;
        RECT 8.305 1.910 8.535 2.385 ;
        RECT 8.885 2.035 9.115 2.890 ;
        RECT 9.605 2.485 9.835 3.160 ;
        RECT 12.550 2.985 13.990 3.160 ;
        RECT 10.800 2.295 11.030 2.870 ;
        RECT 10.800 2.065 14.255 2.295 ;
        RECT 14.485 2.220 14.715 2.930 ;
        RECT 15.000 2.680 15.230 3.160 ;
        RECT 16.050 3.115 17.250 3.345 ;
        RECT 16.050 2.680 16.280 3.115 ;
        RECT 15.000 2.450 16.280 2.680 ;
        RECT 16.510 2.220 16.740 2.885 ;
        RECT 8.885 1.800 10.390 2.035 ;
        RECT 5.090 1.075 5.320 1.260 ;
        RECT 3.250 0.845 5.320 1.075 ;
        RECT 6.010 0.760 6.240 1.260 ;
        RECT 6.835 0.990 7.175 1.275 ;
        RECT 7.405 1.295 8.680 1.530 ;
        RECT 7.405 0.760 7.635 1.295 ;
        RECT 6.010 0.530 7.635 0.760 ;
        RECT 8.450 0.760 8.680 1.295 ;
        RECT 9.150 0.990 9.490 1.800 ;
        RECT 9.925 0.760 10.155 0.980 ;
        RECT 8.450 0.530 10.155 0.760 ;
        RECT 11.045 0.620 11.275 2.065 ;
        RECT 14.485 1.990 16.740 2.220 ;
        RECT 17.020 2.065 17.250 3.115 ;
        RECT 17.530 3.115 19.240 3.345 ;
        RECT 14.485 1.835 14.715 1.990 ;
        RECT 11.625 1.375 11.955 1.700 ;
        RECT 12.475 1.605 14.715 1.835 ;
        RECT 11.625 1.145 14.330 1.375 ;
        RECT 14.100 0.760 14.330 1.145 ;
        RECT 15.470 0.990 15.810 1.990 ;
        RECT 17.530 1.760 17.760 3.115 ;
        RECT 18.550 2.315 18.780 2.885 ;
        RECT 19.010 2.735 19.240 3.115 ;
        RECT 20.040 3.160 21.340 3.390 ;
        RECT 20.040 2.735 20.270 3.160 ;
        RECT 19.010 2.505 20.270 2.735 ;
        RECT 16.090 0.760 16.320 1.740 ;
        RECT 16.590 1.525 17.760 1.760 ;
        RECT 17.990 2.275 18.780 2.315 ;
        RECT 17.990 2.045 19.280 2.275 ;
        RECT 16.590 0.990 16.930 1.525 ;
        RECT 17.990 1.265 18.220 2.045 ;
        RECT 17.710 0.990 18.220 1.265 ;
        RECT 18.450 0.760 18.820 1.815 ;
        RECT 14.100 0.530 18.820 0.760 ;
        RECT 19.050 0.760 19.280 2.045 ;
        RECT 20.500 0.760 20.840 2.930 ;
        RECT 21.110 2.735 21.340 3.160 ;
        RECT 21.110 2.505 22.530 2.735 ;
        RECT 21.115 1.725 21.345 2.170 ;
        RECT 22.190 1.960 22.530 2.505 ;
        RECT 22.775 1.780 23.005 3.150 ;
        RECT 22.775 1.725 23.990 1.780 ;
        RECT 21.115 1.495 23.990 1.725 ;
        RECT 19.050 0.530 20.840 0.760 ;
        RECT 22.540 1.440 23.990 1.495 ;
        RECT 22.540 0.655 22.890 1.440 ;
  END
END gf180mcu_fd_sc_mcu7t5v0__sdffsnq_1

#--------EOF---------

MACRO gf180mcu_fd_sc_mcu7t5v0__sdffsnq_2
  CLASS core ;
  FOREIGN gf180mcu_fd_sc_mcu7t5v0__sdffsnq_2 ;
  ORIGIN 0.000 0.000 ;
  SIZE 26.320 BY 3.920 ;
  SYMMETRY X Y ;
  SITE GF018hv5v_mcu_sc7 ;
  PIN D
    DIRECTION INPUT ;
    ANTENNAGATEAREA 0.531000 ;
    PORT
      LAYER Metal1 ;
        RECT 3.410 1.765 4.390 2.155 ;
    END
  END D
  PIN SE
    DIRECTION INPUT ;
    ANTENNAGATEAREA 1.062000 ;
    PORT
      LAYER Metal1 ;
        RECT 0.705 0.595 1.030 2.150 ;
    END
  END SE
  PIN SETN
    DIRECTION INPUT ;
    ANTENNAGATEAREA 1.057000 ;
    PORT
      LAYER Metal1 ;
        RECT 19.620 1.170 20.110 2.190 ;
    END
  END SETN
  PIN SI
    DIRECTION INPUT ;
    ANTENNAGATEAREA 0.531000 ;
    PORT
      LAYER Metal1 ;
        RECT 1.825 0.595 2.150 2.150 ;
    END
  END SI
  PIN CLK
    DIRECTION INPUT ;
    USE CLOCK ;
    ANTENNAGATEAREA 0.741500 ;
    PORT
      LAYER Metal1 ;
        RECT 5.130 1.765 6.630 2.155 ;
    END
  END CLK
  PIN Q
    DIRECTION OUTPUT ;
    ANTENNADIFFAREA 1.079100 ;
    PORT
      LAYER Metal1 ;
        RECT 24.555 2.655 25.100 3.380 ;
        RECT 24.555 2.380 25.795 2.655 ;
        RECT 25.530 1.535 25.795 2.380 ;
        RECT 24.170 1.265 25.795 1.535 ;
        RECT 24.170 0.610 24.695 1.265 ;
    END
  END Q
  PIN VDD
    DIRECTION INOUT ;
    USE POWER ;
    SHAPE ABUTMENT ;
    PORT
      LAYER Metal1 ;
        RECT 0.000 3.620 26.320 4.220 ;
        RECT 1.260 2.845 1.600 3.620 ;
        RECT 5.375 2.885 5.605 3.620 ;
        RECT 7.590 3.350 7.930 3.620 ;
        RECT 13.190 3.445 13.530 3.620 ;
        RECT 15.460 2.910 15.820 3.620 ;
        RECT 19.485 2.965 19.825 3.620 ;
        RECT 21.580 2.965 21.920 3.620 ;
        RECT 23.540 2.530 23.770 3.620 ;
        RECT 25.595 2.945 25.825 3.620 ;
    END
  END VDD
  PIN VNW
    DIRECTION INOUT ;
    USE POWER ;
    PORT
      LAYER Nwell ;
        RECT -0.430 1.885 26.750 4.350 ;
        RECT -0.430 1.760 6.455 1.885 ;
        RECT 9.870 1.760 12.970 1.885 ;
        RECT 18.650 1.760 26.750 1.885 ;
    END
  END VNW
  PIN VPW
    DIRECTION INOUT ;
    USE GROUND ;
    PORT
      LAYER Pwell ;
        RECT 6.455 1.760 9.870 1.885 ;
        RECT 12.970 1.760 18.650 1.885 ;
        RECT -0.430 -0.430 26.750 1.760 ;
    END
  END VPW
  PIN VSS
    DIRECTION INOUT ;
    USE GROUND ;
    SHAPE ABUTMENT ;
    PORT
      LAYER Metal1 ;
        RECT 1.365 0.300 1.595 1.140 ;
        RECT 5.550 0.300 5.780 1.025 ;
        RECT 7.865 0.300 8.095 1.045 ;
        RECT 13.120 0.300 13.480 0.915 ;
        RECT 21.475 0.300 21.705 0.890 ;
        RECT 23.315 0.300 23.545 0.905 ;
        RECT 25.595 0.300 25.825 0.905 ;
        RECT 0.000 -0.300 26.320 0.300 ;
    END
  END VSS
  OBS
      LAYER Metal1 ;
        RECT 6.085 3.160 7.360 3.390 ;
        RECT 0.245 2.615 0.475 3.040 ;
        RECT 3.270 2.745 4.120 2.975 ;
        RECT 3.890 2.655 4.120 2.745 ;
        RECT 6.085 2.655 6.315 3.160 ;
        RECT 7.130 3.120 7.360 3.160 ;
        RECT 8.205 3.160 9.835 3.390 ;
        RECT 11.265 3.215 12.780 3.390 ;
        RECT 13.760 3.215 15.230 3.390 ;
        RECT 11.265 3.160 15.230 3.215 ;
        RECT 8.205 3.120 8.435 3.160 ;
        RECT 7.130 2.890 8.435 3.120 ;
        RECT 0.245 2.385 2.855 2.615 ;
        RECT 3.890 2.420 6.315 2.655 ;
        RECT 6.610 2.620 6.840 2.890 ;
        RECT 6.610 2.385 8.535 2.620 ;
        RECT 0.245 0.780 0.475 2.385 ;
        RECT 2.625 1.535 2.855 2.385 ;
        RECT 4.630 1.535 4.860 1.740 ;
        RECT 2.625 1.305 4.860 1.535 ;
        RECT 5.090 1.260 6.240 1.490 ;
        RECT 6.945 1.275 7.175 2.385 ;
        RECT 8.305 1.910 8.535 2.385 ;
        RECT 8.885 2.035 9.115 2.890 ;
        RECT 9.605 2.485 9.835 3.160 ;
        RECT 12.550 2.985 13.990 3.160 ;
        RECT 10.800 2.295 11.030 2.870 ;
        RECT 10.800 2.065 14.255 2.295 ;
        RECT 14.485 2.220 14.715 2.930 ;
        RECT 15.000 2.680 15.230 3.160 ;
        RECT 16.050 3.115 17.250 3.345 ;
        RECT 16.050 2.680 16.280 3.115 ;
        RECT 15.000 2.450 16.280 2.680 ;
        RECT 16.510 2.220 16.740 2.885 ;
        RECT 8.885 1.800 10.390 2.035 ;
        RECT 5.090 1.075 5.320 1.260 ;
        RECT 3.250 0.845 5.320 1.075 ;
        RECT 6.010 0.760 6.240 1.260 ;
        RECT 6.835 0.990 7.175 1.275 ;
        RECT 7.405 1.295 8.680 1.530 ;
        RECT 7.405 0.760 7.635 1.295 ;
        RECT 6.010 0.530 7.635 0.760 ;
        RECT 8.450 0.760 8.680 1.295 ;
        RECT 9.150 0.990 9.490 1.800 ;
        RECT 9.925 0.760 10.155 0.980 ;
        RECT 8.450 0.530 10.155 0.760 ;
        RECT 11.045 0.620 11.275 2.065 ;
        RECT 14.485 1.990 16.740 2.220 ;
        RECT 17.020 2.065 17.250 3.115 ;
        RECT 17.530 3.115 19.240 3.345 ;
        RECT 14.485 1.835 14.715 1.990 ;
        RECT 11.625 1.375 11.855 1.700 ;
        RECT 12.475 1.605 14.715 1.835 ;
        RECT 11.625 1.145 14.330 1.375 ;
        RECT 14.100 0.760 14.330 1.145 ;
        RECT 15.470 0.990 15.810 1.990 ;
        RECT 17.530 1.760 17.760 3.115 ;
        RECT 18.550 2.315 18.780 2.885 ;
        RECT 19.010 2.735 19.240 3.115 ;
        RECT 20.055 3.160 21.330 3.390 ;
        RECT 20.055 2.735 20.285 3.160 ;
        RECT 19.010 2.505 20.285 2.735 ;
        RECT 16.090 0.760 16.320 1.740 ;
        RECT 16.590 1.525 17.760 1.760 ;
        RECT 17.990 2.275 18.780 2.315 ;
        RECT 17.990 2.045 19.280 2.275 ;
        RECT 16.590 0.990 16.930 1.525 ;
        RECT 17.990 1.265 18.220 2.045 ;
        RECT 17.710 0.990 18.220 1.265 ;
        RECT 18.450 0.760 18.820 1.815 ;
        RECT 14.100 0.530 18.820 0.760 ;
        RECT 19.050 0.760 19.280 2.045 ;
        RECT 20.525 0.760 20.865 2.930 ;
        RECT 21.100 2.735 21.330 3.160 ;
        RECT 21.100 2.505 22.540 2.735 ;
        RECT 21.115 1.725 21.345 2.170 ;
        RECT 22.200 1.960 22.540 2.505 ;
        RECT 22.800 2.095 23.030 3.380 ;
        RECT 22.800 1.825 25.300 2.095 ;
        RECT 22.800 1.725 23.030 1.825 ;
        RECT 21.115 1.495 23.030 1.725 ;
        RECT 19.050 0.530 20.865 0.760 ;
        RECT 22.595 0.655 23.030 1.495 ;
  END
END gf180mcu_fd_sc_mcu7t5v0__sdffsnq_2

#--------EOF---------

MACRO gf180mcu_fd_sc_mcu7t5v0__tieh
  CLASS core TIEHIGH ;
  FOREIGN gf180mcu_fd_sc_mcu7t5v0__tieh ;
  ORIGIN 0.000 0.000 ;
  SIZE 2.240 BY 3.920 ;
  SYMMETRY X Y ;
  SITE GF018hv5v_mcu_sc7 ;
  PIN Z
    DIRECTION OUTPUT ;
    ANTENNADIFFAREA 0.536800 ;
    PORT
      LAYER Metal1 ;
        RECT 1.220 2.305 1.580 3.390 ;
    END
  END Z
  PIN VDD
    DIRECTION INOUT ;
    USE POWER ;
    SHAPE ABUTMENT ;
    PORT
      LAYER Metal1 ;
        RECT 0.000 3.620 2.240 4.220 ;
        RECT 0.250 2.360 0.480 3.620 ;
    END
  END VDD
  PIN VNW
    DIRECTION INOUT ;
    USE POWER ;
    PORT
      LAYER Nwell ;
        RECT -0.430 1.760 2.670 4.350 ;
    END
  END VNW
  PIN VPW
    DIRECTION INOUT ;
    USE GROUND ;
    PORT
      LAYER Pwell ;
        RECT -0.430 -0.430 2.670 1.760 ;
    END
  END VPW
  PIN VSS
    DIRECTION INOUT ;
    USE GROUND ;
    SHAPE ABUTMENT ;
    PORT
      LAYER Metal1 ;
        RECT 0.250 0.300 0.480 1.160 ;
        RECT 0.000 -0.300 2.240 0.300 ;
    END
  END VSS
  OBS
      LAYER Metal1 ;
        RECT 0.875 1.335 1.600 1.570 ;
        RECT 1.370 0.530 1.600 1.335 ;
  END
END gf180mcu_fd_sc_mcu7t5v0__tieh

#--------EOF---------

MACRO gf180mcu_fd_sc_mcu7t5v0__tiel
  CLASS core TIELOW ;
  FOREIGN gf180mcu_fd_sc_mcu7t5v0__tiel ;
  ORIGIN 0.000 0.000 ;
  SIZE 2.240 BY 3.920 ;
  SYMMETRY X Y ;
  SITE GF018hv5v_mcu_sc7 ;
  PIN ZN
    DIRECTION OUTPUT ;
    ANTENNADIFFAREA 0.360800 ;
    PORT
      LAYER Metal1 ;
        RECT 1.220 0.530 1.595 1.650 ;
    END
  END ZN
  PIN VDD
    DIRECTION INOUT ;
    USE POWER ;
    SHAPE ABUTMENT ;
    PORT
      LAYER Metal1 ;
        RECT 0.000 3.620 2.240 4.220 ;
        RECT 0.345 2.345 0.575 3.620 ;
    END
  END VDD
  PIN VNW
    DIRECTION INOUT ;
    USE POWER ;
    PORT
      LAYER Nwell ;
        RECT -0.430 1.760 2.670 4.350 ;
    END
  END VNW
  PIN VPW
    DIRECTION INOUT ;
    USE GROUND ;
    PORT
      LAYER Pwell ;
        RECT -0.430 -0.430 2.670 1.760 ;
    END
  END VPW
  PIN VSS
    DIRECTION INOUT ;
    USE GROUND ;
    SHAPE ABUTMENT ;
    PORT
      LAYER Metal1 ;
        RECT 0.245 0.300 0.475 1.160 ;
        RECT 0.000 -0.300 2.240 0.300 ;
    END
  END VSS
  OBS
      LAYER Metal1 ;
        RECT 1.365 2.185 1.595 3.390 ;
        RECT 0.870 1.950 1.595 2.185 ;
  END
END gf180mcu_fd_sc_mcu7t5v0__tiel

#--------EOF---------

MACRO gf180mcu_fd_sc_mcu7t5v0__xnor2_1
  CLASS core ;
  FOREIGN gf180mcu_fd_sc_mcu7t5v0__xnor2_1 ;
  ORIGIN 0.000 0.000 ;
  SIZE 7.280 BY 3.920 ;
  SYMMETRY X Y ;
  SITE GF018hv5v_mcu_sc7 ;
  PIN A1
    DIRECTION INPUT ;
    ANTENNAGATEAREA 1.535500 ;
    PORT
      LAYER Metal1 ;
        RECT 1.815 1.825 4.570 2.095 ;
        RECT 1.815 1.450 2.220 1.825 ;
    END
  END A1
  PIN A2
    DIRECTION INPUT ;
    ANTENNAGATEAREA 1.535500 ;
    PORT
      LAYER Metal1 ;
        RECT 1.305 2.385 5.455 2.655 ;
        RECT 1.305 1.855 1.535 2.385 ;
        RECT 0.910 1.625 1.535 1.855 ;
        RECT 5.185 1.740 5.455 2.385 ;
        RECT 5.185 1.510 6.010 1.740 ;
    END
  END A2
  PIN ZN
    DIRECTION OUTPUT ;
    ANTENNADIFFAREA 1.456350 ;
    PORT
      LAYER Metal1 ;
        RECT 3.305 2.945 6.020 3.215 ;
        RECT 5.745 2.215 6.020 2.945 ;
        RECT 5.745 1.980 6.580 2.215 ;
        RECT 6.290 1.220 6.580 1.980 ;
        RECT 4.980 0.990 6.580 1.220 ;
    END
  END ZN
  PIN VDD
    DIRECTION INOUT ;
    USE POWER ;
    SHAPE ABUTMENT ;
    PORT
      LAYER Metal1 ;
        RECT 0.000 3.620 7.280 4.220 ;
        RECT 0.385 2.720 0.615 3.620 ;
        RECT 2.650 2.930 2.990 3.620 ;
        RECT 6.305 2.690 6.535 3.620 ;
    END
  END VDD
  PIN VNW
    DIRECTION INOUT ;
    USE POWER ;
    PORT
      LAYER Nwell ;
        RECT -0.430 1.885 7.710 4.350 ;
        RECT -0.430 1.760 4.630 1.885 ;
        RECT 5.730 1.760 7.710 1.885 ;
    END
  END VNW
  PIN VPW
    DIRECTION INOUT ;
    USE GROUND ;
    PORT
      LAYER Pwell ;
        RECT 4.630 1.760 5.730 1.885 ;
        RECT -0.430 -0.430 7.710 1.760 ;
    END
  END VPW
  PIN VSS
    DIRECTION INOUT ;
    USE GROUND ;
    SHAPE ABUTMENT ;
    PORT
      LAYER Metal1 ;
        RECT 2.370 0.300 2.710 0.760 ;
        RECT 0.000 -0.300 7.280 0.300 ;
    END
  END VSS
  OBS
      LAYER Metal1 ;
        RECT 0.845 2.945 1.780 3.215 ;
        RECT 0.845 2.415 1.075 2.945 ;
        RECT 0.330 2.180 1.075 2.415 ;
        RECT 0.330 1.220 0.615 2.180 ;
        RECT 3.105 1.220 3.445 1.565 ;
        RECT 0.330 0.990 3.445 1.220 ;
        RECT 0.330 0.530 0.670 0.990 ;
        RECT 3.630 0.530 6.690 0.760 ;
  END
END gf180mcu_fd_sc_mcu7t5v0__xnor2_1

#--------EOF---------

MACRO gf180mcu_fd_sc_mcu7t5v0__xnor2_2
  CLASS core ;
  FOREIGN gf180mcu_fd_sc_mcu7t5v0__xnor2_2 ;
  ORIGIN 0.000 0.000 ;
  SIZE 9.520 BY 3.920 ;
  SYMMETRY X Y ;
  SITE GF018hv5v_mcu_sc7 ;
  PIN A1
    DIRECTION INPUT ;
    ANTENNAGATEAREA 1.600500 ;
    PORT
      LAYER Metal1 ;
        RECT 1.825 1.825 4.105 2.095 ;
        RECT 1.825 1.570 2.290 1.825 ;
        RECT 3.855 1.745 4.105 1.825 ;
        RECT 3.855 1.255 4.480 1.745 ;
    END
  END A1
  PIN A2
    DIRECTION INPUT ;
    ANTENNAGATEAREA 1.600500 ;
    PORT
      LAYER Metal1 ;
        RECT 1.260 2.470 4.520 2.660 ;
        RECT 1.260 2.325 5.475 2.470 ;
        RECT 1.260 1.885 1.535 2.325 ;
        RECT 4.290 2.235 5.475 2.325 ;
        RECT 0.835 1.655 1.535 1.885 ;
        RECT 5.215 1.785 5.475 2.235 ;
    END
  END A2
  PIN ZN
    DIRECTION OUTPUT ;
    ANTENNADIFFAREA 1.182800 ;
    PORT
      LAYER Metal1 ;
        RECT 7.585 0.600 8.265 3.380 ;
    END
  END ZN
  PIN VDD
    DIRECTION INOUT ;
    USE POWER ;
    SHAPE ABUTMENT ;
    PORT
      LAYER Metal1 ;
        RECT 0.000 3.620 9.520 4.220 ;
        RECT 2.435 2.915 2.665 3.620 ;
        RECT 6.545 2.530 6.775 3.620 ;
        RECT 8.685 2.530 8.915 3.620 ;
    END
  END VDD
  PIN VNW
    DIRECTION INOUT ;
    USE POWER ;
    PORT
      LAYER Nwell ;
        RECT -0.430 1.760 9.950 4.350 ;
    END
  END VNW
  PIN VPW
    DIRECTION INOUT ;
    USE GROUND ;
    PORT
      LAYER Pwell ;
        RECT -0.430 -0.430 9.950 1.760 ;
    END
  END VPW
  PIN VSS
    DIRECTION INOUT ;
    USE GROUND ;
    SHAPE ABUTMENT ;
    PORT
      LAYER Metal1 ;
        RECT 0.245 0.300 0.475 0.825 ;
        RECT 2.485 0.300 2.715 0.825 ;
        RECT 5.825 0.300 6.055 0.915 ;
        RECT 6.545 0.300 6.775 0.915 ;
        RECT 8.785 0.300 9.015 1.115 ;
        RECT 0.000 -0.300 9.520 0.300 ;
    END
  END VSS
  OBS
      LAYER Metal1 ;
        RECT 0.345 1.290 0.575 3.360 ;
        RECT 3.640 3.160 6.110 3.390 ;
        RECT 4.750 2.700 5.935 2.930 ;
        RECT 3.040 1.365 3.535 1.595 ;
        RECT 5.705 1.555 5.935 2.700 ;
        RECT 6.920 1.555 7.290 2.110 ;
        RECT 3.040 1.290 3.270 1.365 ;
        RECT 0.345 1.055 3.270 1.290 ;
        RECT 4.810 1.155 7.290 1.555 ;
        RECT 1.310 0.530 1.650 1.055 ;
        RECT 4.810 0.820 5.040 1.155 ;
        RECT 3.640 0.590 5.040 0.820 ;
  END
END gf180mcu_fd_sc_mcu7t5v0__xnor2_2

#--------EOF---------

MACRO gf180mcu_fd_sc_mcu7t5v0__xnor3_1
  CLASS core ;
  FOREIGN gf180mcu_fd_sc_mcu7t5v0__xnor3_1 ;
  ORIGIN 0.000 0.000 ;
  SIZE 13.440 BY 3.920 ;
  SYMMETRY X Y ;
  SITE GF018hv5v_mcu_sc7 ;
  PIN A1
    DIRECTION INPUT ;
    ANTENNAGATEAREA 0.892000 ;
    PORT
      LAYER Metal1 ;
        RECT 1.770 1.825 3.900 2.095 ;
        RECT 1.770 1.455 2.225 1.825 ;
        RECT 3.670 1.690 3.900 1.825 ;
        RECT 3.670 1.455 4.770 1.690 ;
    END
  END A1
  PIN A2
    DIRECTION INPUT ;
    ANTENNAGATEAREA 0.892000 ;
    PORT
      LAYER Metal1 ;
        RECT 0.870 2.385 4.360 2.655 ;
        RECT 4.130 2.150 4.360 2.385 ;
        RECT 4.130 1.920 5.620 2.150 ;
        RECT 5.175 1.595 5.620 1.920 ;
    END
  END A2
  PIN A3
    DIRECTION INPUT ;
    ANTENNAGATEAREA 1.535500 ;
    PORT
      LAYER Metal1 ;
        RECT 8.085 1.825 10.765 2.095 ;
    END
  END A3
  PIN ZN
    DIRECTION OUTPUT ;
    ANTENNADIFFAREA 1.511100 ;
    PORT
      LAYER Metal1 ;
        RECT 9.570 2.920 12.215 3.240 ;
        RECT 11.880 2.680 12.215 2.920 ;
        RECT 11.880 2.360 12.760 2.680 ;
        RECT 12.440 1.580 12.760 2.360 ;
        RECT 11.170 0.990 12.760 1.580 ;
    END
  END ZN
  PIN VDD
    DIRECTION INOUT ;
    USE POWER ;
    SHAPE ABUTMENT ;
    PORT
      LAYER Metal1 ;
        RECT 0.000 3.620 13.440 4.220 ;
        RECT 2.370 2.900 2.730 3.620 ;
        RECT 6.545 2.840 6.775 3.620 ;
        RECT 8.760 2.815 9.100 3.620 ;
        RECT 12.465 3.015 12.695 3.620 ;
    END
  END VDD
  PIN VNW
    DIRECTION INOUT ;
    USE POWER ;
    PORT
      LAYER Nwell ;
        RECT -0.430 1.885 13.870 4.350 ;
        RECT -0.430 1.760 10.790 1.885 ;
        RECT 11.890 1.760 13.870 1.885 ;
    END
  END VNW
  PIN VPW
    DIRECTION INOUT ;
    USE GROUND ;
    PORT
      LAYER Pwell ;
        RECT 10.790 1.760 11.890 1.885 ;
        RECT -0.430 -0.430 13.870 1.760 ;
    END
  END VPW
  PIN VSS
    DIRECTION INOUT ;
    USE GROUND ;
    SHAPE ABUTMENT ;
    PORT
      LAYER Metal1 ;
        RECT 0.190 0.300 0.530 0.760 ;
        RECT 2.430 0.300 2.770 0.760 ;
        RECT 5.770 0.300 6.110 0.760 ;
        RECT 8.530 0.300 8.870 0.760 ;
        RECT 0.000 -0.300 13.440 0.300 ;
    END
  END VSS
  OBS
      LAYER Metal1 ;
        RECT 0.345 1.220 0.575 3.195 ;
        RECT 3.720 3.160 6.120 3.390 ;
        RECT 3.720 2.900 4.080 3.160 ;
        RECT 4.740 2.610 5.100 2.930 ;
        RECT 5.760 2.900 6.120 3.160 ;
        RECT 7.030 3.160 8.500 3.390 ;
        RECT 7.030 2.610 7.260 3.160 ;
        RECT 4.740 2.380 7.260 2.610 ;
        RECT 5.880 1.225 6.110 2.380 ;
        RECT 7.030 1.535 7.260 2.380 ;
        RECT 7.510 1.225 7.850 2.930 ;
        RECT 8.270 2.565 8.500 3.160 ;
        RECT 8.270 2.330 11.450 2.565 ;
        RECT 11.220 2.095 11.450 2.330 ;
        RECT 11.220 1.860 12.170 2.095 ;
        RECT 9.200 1.225 9.540 1.565 ;
        RECT 0.345 0.990 3.495 1.220 ;
        RECT 3.730 0.990 6.110 1.225 ;
        RECT 6.490 0.990 9.540 1.225 ;
        RECT 1.305 0.530 1.650 0.990 ;
        RECT 3.730 0.530 4.070 0.990 ;
        RECT 6.490 0.530 6.830 0.990 ;
        RECT 9.740 0.530 12.860 0.760 ;
  END
END gf180mcu_fd_sc_mcu7t5v0__xnor3_1

#--------EOF---------

MACRO gf180mcu_fd_sc_mcu7t5v0__xnor3_2
  CLASS core ;
  FOREIGN gf180mcu_fd_sc_mcu7t5v0__xnor3_2 ;
  ORIGIN 0.000 0.000 ;
  SIZE 15.680 BY 3.920 ;
  SYMMETRY X Y ;
  SITE GF018hv5v_mcu_sc7 ;
  PIN A1
    DIRECTION INPUT ;
    ANTENNAGATEAREA 0.904500 ;
    PORT
      LAYER Metal1 ;
        RECT 1.935 1.265 4.905 1.535 ;
    END
  END A1
  PIN A2
    DIRECTION INPUT ;
    ANTENNAGATEAREA 0.904500 ;
    PORT
      LAYER Metal1 ;
        RECT 0.825 2.385 4.240 2.655 ;
        RECT 3.935 2.100 4.240 2.385 ;
        RECT 3.935 1.815 5.715 2.100 ;
    END
  END A2
  PIN A3
    DIRECTION INPUT ;
    ANTENNAGATEAREA 1.598000 ;
    PORT
      LAYER Metal1 ;
        RECT 8.300 1.815 10.425 2.095 ;
        RECT 10.170 1.610 10.425 1.815 ;
        RECT 10.170 1.210 11.075 1.610 ;
    END
  END A3
  PIN ZN
    DIRECTION OUTPUT ;
    ANTENNADIFFAREA 1.795200 ;
    PORT
      LAYER Metal1 ;
        RECT 13.015 2.680 13.295 3.390 ;
        RECT 15.155 2.680 15.535 3.390 ;
        RECT 13.015 2.360 15.535 2.680 ;
        RECT 15.155 1.560 15.535 2.360 ;
        RECT 12.965 1.240 15.535 1.560 ;
        RECT 12.965 0.600 13.310 1.240 ;
        RECT 15.155 0.600 15.535 1.240 ;
    END
  END ZN
  PIN VDD
    DIRECTION INOUT ;
    USE POWER ;
    SHAPE ABUTMENT ;
    PORT
      LAYER Metal1 ;
        RECT 0.000 3.620 15.680 4.220 ;
        RECT 2.420 2.895 2.780 3.620 ;
        RECT 9.090 2.785 9.430 3.620 ;
        RECT 14.035 2.950 14.265 3.620 ;
    END
  END VDD
  PIN VNW
    DIRECTION INOUT ;
    USE POWER ;
    PORT
      LAYER Nwell ;
        RECT -0.430 1.760 16.110 4.350 ;
    END
  END VNW
  PIN VPW
    DIRECTION INOUT ;
    USE GROUND ;
    PORT
      LAYER Pwell ;
        RECT -0.430 -0.430 16.110 1.760 ;
    END
  END VPW
  PIN VSS
    DIRECTION INOUT ;
    USE GROUND ;
    SHAPE ABUTMENT ;
    PORT
      LAYER Metal1 ;
        RECT 0.190 0.300 0.530 0.760 ;
        RECT 2.515 0.300 2.855 0.760 ;
        RECT 5.770 0.300 6.110 0.760 ;
        RECT 6.570 0.300 6.910 0.760 ;
        RECT 9.045 0.300 9.275 0.890 ;
        RECT 12.150 0.300 12.490 0.635 ;
        RECT 14.085 0.300 14.315 0.975 ;
        RECT 0.000 -0.300 15.680 0.300 ;
    END
  END VSS
  OBS
      LAYER Metal1 ;
        RECT 0.345 1.225 0.575 3.190 ;
        RECT 3.720 3.155 6.055 3.390 ;
        RECT 3.720 2.895 4.080 3.155 ;
        RECT 4.750 2.565 5.090 2.925 ;
        RECT 5.760 2.840 6.055 3.155 ;
        RECT 6.285 3.155 8.065 3.390 ;
        RECT 10.045 3.160 12.575 3.390 ;
        RECT 6.285 2.565 6.515 3.155 ;
        RECT 4.750 2.335 6.515 2.565 ;
        RECT 1.365 1.765 3.570 1.995 ;
        RECT 1.365 1.225 1.650 1.765 ;
        RECT 0.345 0.990 1.650 1.225 ;
        RECT 6.285 1.225 6.515 2.335 ;
        RECT 6.745 2.095 7.085 2.925 ;
        RECT 7.835 2.555 8.065 3.155 ;
        RECT 11.115 2.700 12.575 2.930 ;
        RECT 7.835 2.470 10.885 2.555 ;
        RECT 7.835 2.325 11.995 2.470 ;
        RECT 10.655 2.240 11.995 2.325 ;
        RECT 6.745 1.860 8.030 2.095 ;
        RECT 7.690 1.380 8.030 1.860 ;
        RECT 11.765 1.715 11.995 2.240 ;
        RECT 12.345 2.045 12.575 2.700 ;
        RECT 12.345 1.815 14.915 2.045 ;
        RECT 9.515 1.380 9.905 1.555 ;
        RECT 6.285 1.220 7.435 1.225 ;
        RECT 1.310 0.530 1.650 0.990 ;
        RECT 5.230 0.990 7.435 1.220 ;
        RECT 7.690 1.150 9.905 1.380 ;
        RECT 5.230 0.760 5.460 0.990 ;
        RECT 3.730 0.530 5.460 0.760 ;
        RECT 7.690 0.530 8.030 1.150 ;
        RECT 12.345 1.095 12.575 1.815 ;
        RECT 11.405 0.865 12.575 1.095 ;
        RECT 11.405 0.765 11.710 0.865 ;
        RECT 10.035 0.530 11.710 0.765 ;
  END
END gf180mcu_fd_sc_mcu7t5v0__xnor3_2

#--------EOF---------

MACRO gf180mcu_fd_sc_mcu7t5v0__xor2_1
  CLASS core ;
  FOREIGN gf180mcu_fd_sc_mcu7t5v0__xor2_1 ;
  ORIGIN 0.000 0.000 ;
  SIZE 6.720 BY 3.920 ;
  SYMMETRY X Y ;
  SITE GF018hv5v_mcu_sc7 ;
  PIN A1
    DIRECTION INPUT ;
    ANTENNAGATEAREA 1.598000 ;
    PORT
      LAYER Metal1 ;
        RECT 1.875 1.820 4.015 2.100 ;
        RECT 3.785 1.570 4.015 1.820 ;
        RECT 3.785 1.340 4.525 1.570 ;
    END
  END A1
  PIN A2
    DIRECTION INPUT ;
    ANTENNAGATEAREA 1.598000 ;
    PORT
      LAYER Metal1 ;
        RECT 0.880 2.560 2.325 2.730 ;
        RECT 0.880 2.330 4.495 2.560 ;
        RECT 0.880 1.690 1.560 2.330 ;
        RECT 4.255 2.155 4.495 2.330 ;
        RECT 4.255 1.800 5.490 2.155 ;
    END
  END A2
  PIN Z
    DIRECTION OUTPUT ;
    ANTENNADIFFAREA 1.060800 ;
    PORT
      LAYER Metal1 ;
        RECT 4.750 2.695 6.040 2.925 ;
        RECT 5.720 1.110 6.040 2.695 ;
        RECT 3.785 0.875 6.040 1.110 ;
        RECT 3.785 0.530 4.015 0.875 ;
    END
  END Z
  PIN VDD
    DIRECTION INOUT ;
    USE POWER ;
    SHAPE ABUTMENT ;
    PORT
      LAYER Metal1 ;
        RECT 0.000 3.620 6.720 4.220 ;
        RECT 2.710 2.790 3.050 3.620 ;
    END
  END VDD
  PIN VNW
    DIRECTION INOUT ;
    USE POWER ;
    PORT
      LAYER Nwell ;
        RECT -0.430 1.760 7.150 4.350 ;
    END
  END VNW
  PIN VPW
    DIRECTION INOUT ;
    USE GROUND ;
    PORT
      LAYER Pwell ;
        RECT -0.430 -0.430 7.150 1.760 ;
    END
  END VPW
  PIN VSS
    DIRECTION INOUT ;
    USE GROUND ;
    SHAPE ABUTMENT ;
    PORT
      LAYER Metal1 ;
        RECT 0.190 0.300 0.530 0.760 ;
        RECT 2.610 0.300 2.950 0.760 ;
        RECT 5.770 0.300 6.110 0.635 ;
        RECT 0.000 -0.300 6.720 0.300 ;
    END
  END VSS
  OBS
      LAYER Metal1 ;
        RECT 0.290 1.290 0.630 3.350 ;
        RECT 3.590 3.155 6.120 3.390 ;
        RECT 3.170 1.290 3.510 1.555 ;
        RECT 0.290 0.990 3.510 1.290 ;
        RECT 1.310 0.530 1.650 0.990 ;
  END
END gf180mcu_fd_sc_mcu7t5v0__xor2_1

#--------EOF---------

MACRO gf180mcu_fd_sc_mcu7t5v0__xor2_2
  CLASS core ;
  FOREIGN gf180mcu_fd_sc_mcu7t5v0__xor2_2 ;
  ORIGIN 0.000 0.000 ;
  SIZE 10.080 BY 3.920 ;
  SYMMETRY X Y ;
  SITE GF018hv5v_mcu_sc7 ;
  PIN A1
    DIRECTION INPUT ;
    ANTENNAGATEAREA 1.535500 ;
    PORT
      LAYER Metal1 ;
        RECT 2.595 1.795 4.565 2.095 ;
        RECT 2.595 1.680 2.870 1.795 ;
        RECT 1.850 1.450 2.870 1.680 ;
        RECT 4.270 1.265 4.565 1.795 ;
    END
  END A1
  PIN A2
    DIRECTION INPUT ;
    ANTENNAGATEAREA 1.535500 ;
    PORT
      LAYER Metal1 ;
        RECT 3.375 2.555 5.105 2.680 ;
        RECT 2.035 2.325 5.105 2.555 ;
        RECT 2.035 2.140 2.315 2.325 ;
        RECT 0.915 1.910 2.315 2.140 ;
        RECT 4.830 2.120 5.105 2.325 ;
        RECT 0.915 1.800 1.610 1.910 ;
        RECT 4.830 1.800 6.225 2.120 ;
    END
  END A2
  PIN Z
    DIRECTION OUTPUT ;
    ANTENNADIFFAREA 1.060800 ;
    PORT
      LAYER Metal1 ;
        RECT 8.195 2.680 8.560 3.380 ;
        RECT 8.195 2.360 9.600 2.680 ;
        RECT 9.315 1.560 9.600 2.360 ;
        RECT 8.195 1.240 9.600 1.560 ;
        RECT 8.195 0.610 8.545 1.240 ;
    END
  END Z
  PIN VDD
    DIRECTION INOUT ;
    USE POWER ;
    SHAPE ABUTMENT ;
    PORT
      LAYER Metal1 ;
        RECT 0.000 3.620 10.080 4.220 ;
        RECT 0.455 2.830 0.685 3.620 ;
        RECT 2.720 2.790 3.060 3.620 ;
        RECT 6.320 2.815 6.660 3.620 ;
        RECT 7.295 2.530 7.525 3.620 ;
        RECT 9.335 2.940 9.565 3.620 ;
    END
  END VDD
  PIN VNW
    DIRECTION INOUT ;
    USE POWER ;
    PORT
      LAYER Nwell ;
        RECT -0.430 1.885 10.510 4.350 ;
        RECT -0.430 1.760 4.700 1.885 ;
        RECT 5.800 1.760 10.510 1.885 ;
    END
  END VNW
  PIN VPW
    DIRECTION INOUT ;
    USE GROUND ;
    PORT
      LAYER Pwell ;
        RECT 4.700 1.760 5.800 1.885 ;
        RECT -0.430 -0.430 10.510 1.760 ;
    END
  END VPW
  PIN VSS
    DIRECTION INOUT ;
    USE GROUND ;
    SHAPE ABUTMENT ;
    PORT
      LAYER Metal1 ;
        RECT 2.620 0.300 2.960 0.760 ;
        RECT 7.195 0.300 7.425 0.990 ;
        RECT 9.435 0.300 9.665 0.990 ;
        RECT 0.000 -0.300 10.080 0.300 ;
    END
  END VSS
  OBS
      LAYER Metal1 ;
        RECT 1.475 2.600 1.705 3.350 ;
        RECT 3.600 2.990 5.630 3.220 ;
        RECT 0.400 2.370 1.705 2.600 ;
        RECT 5.400 2.580 5.630 2.990 ;
        RECT 0.400 1.220 0.680 2.370 ;
        RECT 5.400 2.350 6.770 2.580 ;
        RECT 6.540 2.095 6.770 2.350 ;
        RECT 6.540 1.820 9.080 2.095 ;
        RECT 3.180 1.220 3.520 1.555 ;
        RECT 6.540 1.220 6.770 1.820 ;
        RECT 0.400 0.990 3.520 1.220 ;
        RECT 5.070 0.990 6.770 1.220 ;
        RECT 0.400 0.530 0.740 0.990 ;
        RECT 3.650 0.530 6.770 0.760 ;
  END
END gf180mcu_fd_sc_mcu7t5v0__xor2_2

#--------EOF---------

MACRO gf180mcu_fd_sc_mcu7t5v0__xor3_1
  CLASS core ;
  FOREIGN gf180mcu_fd_sc_mcu7t5v0__xor3_1 ;
  ORIGIN 0.000 0.000 ;
  SIZE 12.880 BY 3.920 ;
  SYMMETRY X Y ;
  SITE GF018hv5v_mcu_sc7 ;
  PIN A1
    DIRECTION INPUT ;
    ANTENNAGATEAREA 0.894500 ;
    PORT
      LAYER Metal1 ;
        RECT 1.890 1.265 4.600 1.535 ;
    END
  END A1
  PIN A2
    DIRECTION INPUT ;
    ANTENNAGATEAREA 0.894500 ;
    PORT
      LAYER Metal1 ;
        RECT 0.865 2.455 2.100 2.710 ;
        RECT 0.865 2.225 4.195 2.455 ;
        RECT 0.865 1.570 1.095 2.225 ;
        RECT 3.915 2.095 4.195 2.225 ;
        RECT 3.915 1.820 5.600 2.095 ;
    END
  END A2
  PIN A3
    DIRECTION INPUT ;
    ANTENNAGATEAREA 1.600500 ;
    PORT
      LAYER Metal1 ;
        RECT 8.205 1.825 10.205 2.100 ;
        RECT 8.205 1.455 8.545 1.825 ;
        RECT 9.975 1.560 10.205 1.825 ;
        RECT 9.975 1.265 11.110 1.560 ;
    END
  END A3
  PIN Z
    DIRECTION OUTPUT ;
    ANTENNADIFFAREA 1.060800 ;
    PORT
      LAYER Metal1 ;
        RECT 10.770 2.700 12.200 2.930 ;
        RECT 11.880 1.295 12.200 2.700 ;
        RECT 11.560 1.015 12.200 1.295 ;
        RECT 11.560 1.000 11.830 1.015 ;
        RECT 10.045 0.670 11.830 1.000 ;
    END
  END Z
  PIN VDD
    DIRECTION INOUT ;
    USE POWER ;
    SHAPE ABUTMENT ;
    PORT
      LAYER Metal1 ;
        RECT 0.000 3.620 12.880 4.220 ;
        RECT 2.330 2.685 2.670 3.620 ;
        RECT 8.750 2.790 9.090 3.620 ;
    END
  END VDD
  PIN VNW
    DIRECTION INOUT ;
    USE POWER ;
    PORT
      LAYER Nwell ;
        RECT -0.430 1.760 13.310 4.350 ;
    END
  END VNW
  PIN VPW
    DIRECTION INOUT ;
    USE GROUND ;
    PORT
      LAYER Pwell ;
        RECT -0.430 -0.430 13.310 1.760 ;
    END
  END VPW
  PIN VSS
    DIRECTION INOUT ;
    USE GROUND ;
    SHAPE ABUTMENT ;
    PORT
      LAYER Metal1 ;
        RECT 0.190 0.300 0.530 0.760 ;
        RECT 2.430 0.300 2.770 0.760 ;
        RECT 5.770 0.300 6.850 0.760 ;
        RECT 8.915 0.300 9.275 0.760 ;
        RECT 12.085 0.300 12.425 0.635 ;
        RECT 0.000 -0.300 12.880 0.300 ;
    END
  END VSS
  OBS
      LAYER Metal1 ;
        RECT 3.730 3.160 6.055 3.390 ;
        RECT 0.345 1.305 0.575 2.980 ;
        RECT 3.730 2.755 4.070 3.160 ;
        RECT 4.750 2.555 5.090 2.915 ;
        RECT 5.825 2.815 6.055 3.160 ;
        RECT 6.285 3.160 7.925 3.390 ;
        RECT 9.640 3.160 12.160 3.390 ;
        RECT 6.285 2.555 6.515 3.160 ;
        RECT 4.750 2.325 6.515 2.555 ;
        RECT 1.385 1.765 3.510 1.995 ;
        RECT 1.385 1.305 1.650 1.765 ;
        RECT 5.880 1.305 6.110 2.325 ;
        RECT 6.745 1.765 6.975 2.925 ;
        RECT 7.695 2.560 7.925 3.160 ;
        RECT 7.695 2.470 10.585 2.560 ;
        RECT 7.695 2.330 11.585 2.470 ;
        RECT 10.395 2.240 11.585 2.330 ;
        RECT 6.745 1.535 7.930 1.765 ;
        RECT 11.350 1.760 11.585 2.240 ;
        RECT 0.345 1.070 1.650 1.305 ;
        RECT 1.310 0.530 1.650 1.070 ;
        RECT 5.195 1.070 7.390 1.305 ;
        RECT 7.625 1.220 7.930 1.535 ;
        RECT 9.395 1.220 9.745 1.555 ;
        RECT 5.195 0.760 5.425 1.070 ;
        RECT 3.700 0.530 5.425 0.760 ;
        RECT 7.625 0.990 9.745 1.220 ;
        RECT 7.625 0.530 7.965 0.990 ;
  END
END gf180mcu_fd_sc_mcu7t5v0__xor3_1

#--------EOF---------

MACRO gf180mcu_fd_sc_mcu7t5v0__xor3_2
  CLASS core ;
  FOREIGN gf180mcu_fd_sc_mcu7t5v0__xor3_2 ;
  ORIGIN 0.000 0.000 ;
  SIZE 16.240 BY 3.920 ;
  SYMMETRY X Y ;
  SITE GF018hv5v_mcu_sc7 ;
  PIN A1
    DIRECTION INPUT ;
    ANTENNAGATEAREA 0.892000 ;
    PORT
      LAYER Metal1 ;
        RECT 2.050 1.265 4.535 1.535 ;
    END
  END A1
  PIN A2
    DIRECTION INPUT ;
    ANTENNAGATEAREA 0.892000 ;
    PORT
      LAYER Metal1 ;
        RECT 1.075 2.455 2.275 2.660 ;
        RECT 1.075 2.225 4.065 2.455 ;
        RECT 1.075 1.490 1.305 2.225 ;
        RECT 3.835 2.095 4.065 2.225 ;
        RECT 3.835 1.765 5.095 2.095 ;
        RECT 4.800 1.720 5.095 1.765 ;
        RECT 4.800 1.485 5.695 1.720 ;
    END
  END A2
  PIN A3
    DIRECTION INPUT ;
    ANTENNAGATEAREA 1.535500 ;
    PORT
      LAYER Metal1 ;
        RECT 8.115 1.825 10.710 2.095 ;
    END
  END A3
  PIN Z
    DIRECTION OUTPUT ;
    ANTENNADIFFAREA 1.795200 ;
    PORT
      LAYER Metal1 ;
        RECT 13.290 2.680 13.520 3.360 ;
        RECT 15.240 2.680 15.760 3.360 ;
        RECT 13.290 2.360 15.760 2.680 ;
        RECT 15.460 1.560 15.760 2.360 ;
        RECT 13.290 1.240 15.760 1.560 ;
        RECT 13.290 0.655 13.520 1.240 ;
        RECT 15.530 0.655 15.760 1.240 ;
    END
  END Z
  PIN VDD
    DIRECTION INOUT ;
    USE POWER ;
    SHAPE ABUTMENT ;
    PORT
      LAYER Metal1 ;
        RECT 0.000 3.620 16.240 4.220 ;
        RECT 2.725 2.735 3.065 3.620 ;
        RECT 6.525 2.680 6.810 3.620 ;
        RECT 8.775 2.795 9.135 3.620 ;
        RECT 11.990 3.280 12.355 3.620 ;
        RECT 14.310 3.015 14.540 3.620 ;
    END
  END VDD
  PIN VNW
    DIRECTION INOUT ;
    USE POWER ;
    PORT
      LAYER Nwell ;
        RECT -0.430 1.885 16.670 4.350 ;
        RECT -0.430 1.760 10.795 1.885 ;
        RECT 11.895 1.760 16.670 1.885 ;
    END
  END VNW
  PIN VPW
    DIRECTION INOUT ;
    USE GROUND ;
    PORT
      LAYER Pwell ;
        RECT 10.795 1.760 11.895 1.885 ;
        RECT -0.430 -0.430 16.670 1.760 ;
    END
  END VPW
  PIN VSS
    DIRECTION INOUT ;
    USE GROUND ;
    SHAPE ABUTMENT ;
    PORT
      LAYER Metal1 ;
        RECT 0.355 0.300 0.695 0.760 ;
        RECT 2.595 0.300 2.935 0.775 ;
        RECT 5.755 0.300 6.095 0.760 ;
        RECT 8.535 0.300 8.880 0.760 ;
        RECT 14.410 0.300 14.640 0.905 ;
        RECT 0.000 -0.300 16.240 0.300 ;
    END
  END VSS
  OBS
      LAYER Metal1 ;
        RECT 3.735 3.160 6.070 3.390 ;
        RECT 0.510 1.220 0.740 3.030 ;
        RECT 3.735 2.735 4.095 3.160 ;
        RECT 4.720 2.605 5.555 2.835 ;
        RECT 5.785 2.680 6.070 3.160 ;
        RECT 7.040 3.010 8.445 3.240 ;
        RECT 5.325 2.220 5.555 2.605 ;
        RECT 7.040 2.220 7.270 3.010 ;
        RECT 1.535 1.765 3.560 1.995 ;
        RECT 5.325 1.990 7.270 2.220 ;
        RECT 1.535 1.220 1.815 1.765 ;
        RECT 7.010 1.220 7.270 1.990 ;
        RECT 0.510 0.990 1.815 1.220 ;
        RECT 1.475 0.530 1.815 0.990 ;
        RECT 5.240 0.990 7.270 1.220 ;
        RECT 7.545 1.220 7.885 2.780 ;
        RECT 8.160 2.565 8.445 3.010 ;
        RECT 9.750 2.815 12.355 3.050 ;
        RECT 8.160 2.330 11.335 2.565 ;
        RECT 11.105 1.900 11.335 2.330 ;
        RECT 12.125 2.095 12.355 2.815 ;
        RECT 11.105 1.670 11.760 1.900 ;
        RECT 12.125 1.825 15.210 2.095 ;
        RECT 9.270 1.220 9.610 1.555 ;
        RECT 12.125 1.220 12.355 1.825 ;
        RECT 7.545 0.990 9.610 1.220 ;
        RECT 11.170 0.990 12.355 1.220 ;
        RECT 5.240 0.760 5.470 0.990 ;
        RECT 7.545 0.760 7.885 0.990 ;
        RECT 3.625 0.530 5.470 0.760 ;
        RECT 6.485 0.530 7.885 0.760 ;
        RECT 9.795 0.530 12.865 0.760 ;
  END
END gf180mcu_fd_sc_mcu7t5v0__xor3_2

#--------EOF---------

END LIBRARY
